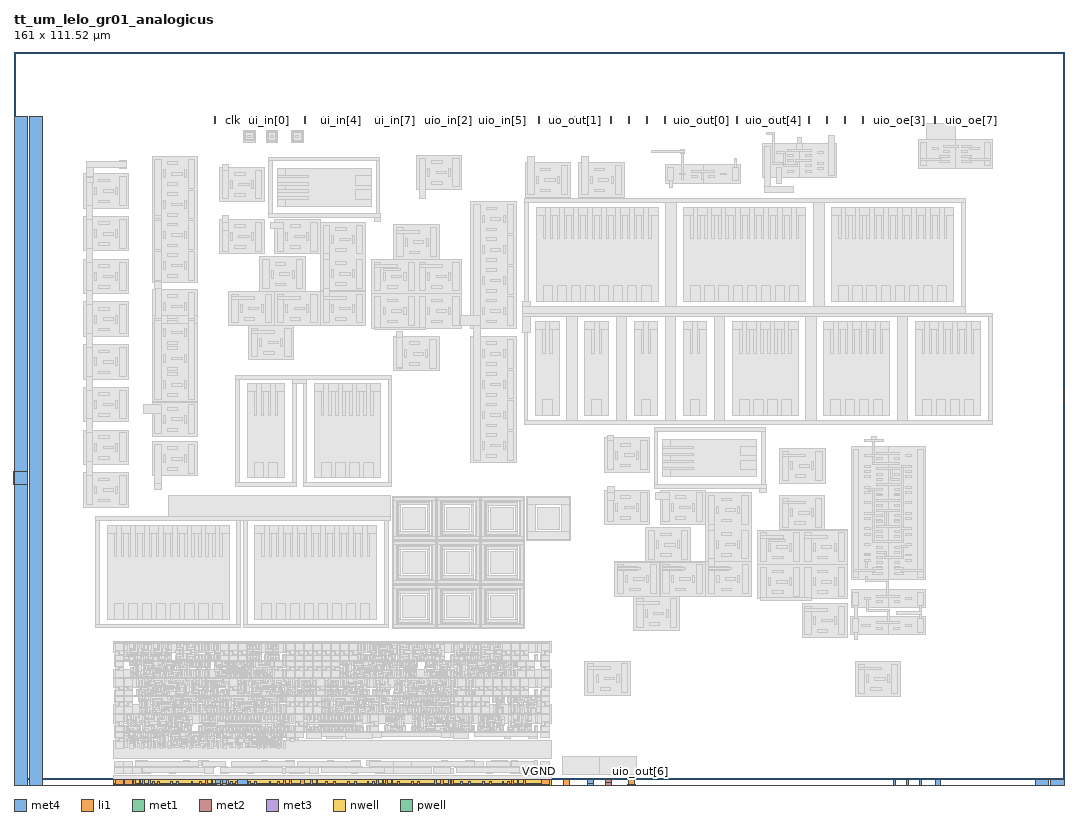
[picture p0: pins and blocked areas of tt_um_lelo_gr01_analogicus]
MACRO tt_um_lelo_gr01_analogicus
  CLASS BLOCK ;
  FOREIGN tt_um_lelo_gr01_analogicus ;
  ORIGIN 0.000 0.000 ;
  SIZE 161.000 BY 111.520 ;
  PIN clk
    DIRECTION INPUT ;
    USE SIGNAL ;
    ANTENNAGATEAREA 0.852000 ;
    PORT
      LAYER met4 ;
        RECT 33.430 100.520 33.730 101.520 ;
    END
  END clk
  PIN ena
    DIRECTION INPUT ;
    USE SIGNAL ;
    PORT
      LAYER met4 ;
        RECT 30.670 100.520 30.970 101.520 ;
    END
  END ena
  PIN rst_n
    DIRECTION INPUT ;
    USE SIGNAL ;
    ANTENNAGATEAREA 0.490500 ;
    ANTENNADIFFAREA 0.202500 ;
    PORT
      LAYER met4 ;
        RECT 36.190 100.520 36.490 101.520 ;
    END
  END rst_n
  PIN ui_in[0]
    DIRECTION INPUT ;
    USE SIGNAL ;
    ANTENNAGATEAREA 0.415500 ;
    ANTENNADIFFAREA 0.202500 ;
    PORT
      LAYER met4 ;
        RECT 38.950 100.520 39.250 101.520 ;
    END
  END ui_in[0]
  PIN ui_in[1]
    DIRECTION INPUT ;
    USE SIGNAL ;
    ANTENNAGATEAREA 0.490500 ;
    ANTENNADIFFAREA 0.202500 ;
    PORT
      LAYER met4 ;
        RECT 41.710 100.520 42.010 101.520 ;
    END
  END ui_in[1]
  PIN ui_in[2]
    DIRECTION INPUT ;
    USE SIGNAL ;
    PORT
      LAYER met4 ;
        RECT 44.470 100.520 44.770 101.520 ;
    END
  END ui_in[2]
  PIN ui_in[3]
    DIRECTION INPUT ;
    USE SIGNAL ;
    PORT
      LAYER met4 ;
        RECT 47.230 100.520 47.530 101.520 ;
    END
  END ui_in[3]
  PIN ui_in[4]
    DIRECTION INPUT ;
    USE SIGNAL ;
    PORT
      LAYER met4 ;
        RECT 49.990 100.520 50.290 101.520 ;
    END
  END ui_in[4]
  PIN ui_in[5]
    DIRECTION INPUT ;
    USE SIGNAL ;
    PORT
      LAYER met4 ;
        RECT 52.750 100.520 53.050 101.520 ;
    END
  END ui_in[5]
  PIN ui_in[6]
    DIRECTION INPUT ;
    USE SIGNAL ;
    PORT
      LAYER met4 ;
        RECT 55.510 100.520 55.810 101.520 ;
    END
  END ui_in[6]
  PIN ui_in[7]
    DIRECTION INPUT ;
    USE SIGNAL ;
    PORT
      LAYER met4 ;
        RECT 58.270 100.520 58.570 101.520 ;
    END
  END ui_in[7]
  PIN uio_in[0]
    DIRECTION INPUT ;
    USE SIGNAL ;
    PORT
      LAYER met4 ;
        RECT 61.030 100.520 61.330 101.520 ;
    END
  END uio_in[0]
  PIN uio_in[1]
    DIRECTION INPUT ;
    USE SIGNAL ;
    PORT
      LAYER met4 ;
        RECT 63.790 100.520 64.090 101.520 ;
    END
  END uio_in[1]
  PIN uio_in[2]
    DIRECTION INPUT ;
    USE SIGNAL ;
    PORT
      LAYER met4 ;
        RECT 66.550 100.520 66.850 101.520 ;
    END
  END uio_in[2]
  PIN uio_in[3]
    DIRECTION INPUT ;
    USE SIGNAL ;
    PORT
      LAYER met4 ;
        RECT 69.310 100.520 69.610 101.520 ;
    END
  END uio_in[3]
  PIN uio_in[4]
    DIRECTION INPUT ;
    USE SIGNAL ;
    PORT
      LAYER met4 ;
        RECT 72.070 100.520 72.370 101.520 ;
    END
  END uio_in[4]
  PIN uio_in[5]
    DIRECTION INPUT ;
    USE SIGNAL ;
    PORT
      LAYER met4 ;
        RECT 74.830 100.520 75.130 101.520 ;
    END
  END uio_in[5]
  PIN uio_in[6]
    DIRECTION INPUT ;
    USE SIGNAL ;
    PORT
      LAYER met4 ;
        RECT 77.590 100.520 77.890 101.520 ;
    END
  END uio_in[6]
  PIN uio_in[7]
    DIRECTION INPUT ;
    USE SIGNAL ;
    PORT
      LAYER met4 ;
        RECT 80.350 100.520 80.650 101.520 ;
    END
  END uio_in[7]
  PIN uio_oe[0]
    DIRECTION OUTPUT ;
    USE SIGNAL ;
    PORT
      LAYER met4 ;
        RECT 127.270 100.520 127.570 101.520 ;
    END
  END uio_oe[0]
  PIN uio_oe[1]
    DIRECTION OUTPUT ;
    USE SIGNAL ;
    PORT
      LAYER met4 ;
        RECT 130.030 100.520 130.330 101.520 ;
    END
  END uio_oe[1]
  PIN uio_oe[2]
    DIRECTION OUTPUT ;
    USE SIGNAL ;
    PORT
      LAYER met4 ;
        RECT 132.790 100.520 133.090 101.520 ;
    END
  END uio_oe[2]
  PIN uio_oe[3]
    DIRECTION OUTPUT ;
    USE SIGNAL ;
    PORT
      LAYER met4 ;
        RECT 135.550 100.520 135.850 101.520 ;
    END
  END uio_oe[3]
  PIN uio_oe[4]
    DIRECTION OUTPUT ;
    USE SIGNAL ;
    PORT
      LAYER met4 ;
        RECT 138.310 100.520 138.610 101.520 ;
    END
  END uio_oe[4]
  PIN uio_oe[5]
    DIRECTION OUTPUT ;
    USE SIGNAL ;
    PORT
      LAYER met4 ;
        RECT 141.070 100.520 141.370 101.520 ;
    END
  END uio_oe[5]
  PIN uio_oe[6]
    DIRECTION OUTPUT ;
    USE SIGNAL ;
    PORT
      LAYER met4 ;
        RECT 143.830 100.520 144.130 101.520 ;
    END
  END uio_oe[6]
  PIN uio_oe[7]
    DIRECTION OUTPUT ;
    USE SIGNAL ;
    PORT
      LAYER met4 ;
        RECT 146.590 100.520 146.890 101.520 ;
    END
  END uio_oe[7]
  PIN uio_out[0]
    DIRECTION OUTPUT ;
    USE SIGNAL ;
    ANTENNADIFFAREA 0.702900 ;
    PORT
      LAYER met4 ;
        RECT 105.190 100.520 105.490 101.520 ;
    END
  END uio_out[0]
  PIN uio_out[1]
    DIRECTION OUTPUT ;
    USE SIGNAL ;
    ANTENNADIFFAREA 0.702900 ;
    PORT
      LAYER met4 ;
        RECT 107.950 100.520 108.250 101.520 ;
    END
  END uio_out[1]
  PIN uio_out[2]
    DIRECTION OUTPUT ;
    USE SIGNAL ;
    ANTENNADIFFAREA 0.702900 ;
    PORT
      LAYER met4 ;
        RECT 110.710 100.520 111.010 101.520 ;
    END
  END uio_out[2]
  PIN uio_out[3]
    DIRECTION OUTPUT ;
    USE SIGNAL ;
    ANTENNADIFFAREA 0.702900 ;
    PORT
      LAYER met4 ;
        RECT 113.470 100.520 113.770 101.520 ;
    END
  END uio_out[3]
  PIN uio_out[4]
    DIRECTION OUTPUT ;
    USE SIGNAL ;
    ANTENNADIFFAREA 0.702900 ;
    PORT
      LAYER met4 ;
        RECT 116.230 100.520 116.530 101.520 ;
    END
  END uio_out[4]
  PIN uio_out[5]
    DIRECTION OUTPUT ;
    USE SIGNAL ;
    ANTENNADIFFAREA 0.702900 ;
    PORT
      LAYER li1 ;
        RECT 58.315 -2.050 58.875 -1.150 ;
        RECT 58.315 -2.975 58.680 -2.050 ;
        RECT 58.315 -3.360 58.895 -2.975 ;
      LAYER met1 ;
        RECT 54.160 -3.035 54.480 -2.975 ;
        RECT 58.315 -3.035 58.605 -2.990 ;
        RECT 54.160 -3.175 58.605 -3.035 ;
        RECT 54.160 -3.235 54.480 -3.175 ;
        RECT 58.315 -3.220 58.605 -3.175 ;
      LAYER met2 ;
        RECT 54.190 -3.265 54.450 -2.945 ;
        RECT 54.250 -4.030 54.390 -3.265 ;
        RECT 54.135 -4.310 54.505 -4.030 ;
      LAYER met3 ;
        RECT 53.900 -4.455 54.520 -4.005 ;
      LAYER met4 ;
        RECT 118.990 100.520 119.290 101.520 ;
        RECT 54.160 -4.020 54.490 -4.000 ;
        RECT 134.850 -4.020 135.150 0.000 ;
        RECT 54.160 -4.320 135.150 -4.020 ;
        RECT 54.160 -4.340 54.490 -4.320 ;
    END
  END uio_out[5]
  PIN uio_out[6]
    DIRECTION OUTPUT ;
    USE SIGNAL ;
    ANTENNADIFFAREA 0.702900 ;
    PORT
      LAYER li1 ;
        RECT 64.945 -2.050 65.505 -1.150 ;
        RECT 65.140 -2.975 65.505 -2.050 ;
        RECT 64.925 -3.360 65.505 -2.975 ;
      LAYER met1 ;
        RECT 55.080 -1.335 55.400 -1.275 ;
        RECT 65.215 -1.335 65.505 -1.290 ;
        RECT 55.080 -1.475 65.505 -1.335 ;
        RECT 55.080 -1.535 55.400 -1.475 ;
        RECT 65.215 -1.520 65.505 -1.475 ;
        RECT 55.075 -4.280 137.120 -4.000 ;
        RECT 55.075 -4.310 55.400 -4.280 ;
      LAYER met2 ;
        RECT 55.110 -1.565 55.370 -1.245 ;
        RECT 55.170 -4.000 55.310 -1.565 ;
        RECT 55.075 -4.280 55.415 -4.000 ;
        RECT 136.810 -4.325 137.090 -3.955 ;
      LAYER met3 ;
        RECT 136.700 -4.400 137.200 -3.900 ;
      LAYER met4 ;
        RECT 121.750 100.520 122.050 101.520 ;
        RECT 136.800 -3.900 137.100 0.000 ;
        RECT 136.700 -4.400 137.200 -3.900 ;
    END
  END uio_out[6]
  PIN uio_out[7]
    DIRECTION OUTPUT ;
    USE SIGNAL ;
    ANTENNADIFFAREA 0.702900 ;
    PORT
      LAYER li1 ;
        RECT 44.705 -2.050 45.265 -1.150 ;
        RECT 44.900 -2.975 45.265 -2.050 ;
        RECT 44.685 -3.360 45.265 -2.975 ;
      LAYER met1 ;
        RECT 39.440 -3.035 39.760 -2.975 ;
        RECT 44.975 -3.035 45.265 -2.990 ;
        RECT 39.440 -3.175 45.265 -3.035 ;
        RECT 39.440 -3.235 39.760 -3.175 ;
        RECT 44.975 -3.220 45.265 -3.175 ;
      LAYER met2 ;
        RECT 39.470 -3.265 39.730 -2.945 ;
        RECT 39.530 -3.920 39.670 -3.265 ;
        RECT 39.475 -4.550 39.755 -3.920 ;
        RECT 39.350 -5.150 39.900 -4.550 ;
      LAYER met3 ;
        RECT 39.350 -5.150 39.900 -4.550 ;
      LAYER met4 ;
        RECT 124.510 100.520 124.810 101.520 ;
        RECT 39.350 -4.705 39.900 -4.550 ;
        RECT 138.800 -4.650 139.100 0.000 ;
        RECT 137.750 -4.705 139.150 -4.650 ;
        RECT 39.350 -5.000 139.150 -4.705 ;
        RECT 39.350 -5.005 138.150 -5.000 ;
        RECT 39.350 -5.150 39.900 -5.005 ;
    END
  END uio_out[7]
  PIN uo_out[0]
    DIRECTION OUTPUT ;
    USE SIGNAL ;
    ANTENNAGATEAREA 0.789000 ;
    ANTENNADIFFAREA 1.872000 ;
    PORT
      LAYER li1 ;
        RECT 27.845 -2.540 28.245 -2.295 ;
      LAYER met1 ;
        RECT 27.955 -2.355 28.245 -2.310 ;
        RECT 27.955 -2.495 30.010 -2.355 ;
        RECT 27.955 -2.540 28.245 -2.495 ;
        RECT 29.870 -3.035 30.010 -2.495 ;
        RECT 33.460 -3.035 33.780 -2.975 ;
        RECT 29.870 -3.175 33.780 -3.035 ;
        RECT 33.460 -3.235 33.780 -3.175 ;
        RECT 33.500 -5.210 33.780 -5.180 ;
        RECT 141.350 -5.210 142.050 -3.550 ;
        RECT 33.500 -5.490 142.050 -5.210 ;
        RECT 33.500 -5.520 33.780 -5.490 ;
        RECT 141.350 -5.500 142.050 -5.490 ;
      LAYER met2 ;
        RECT 33.490 -3.265 33.750 -2.945 ;
        RECT 33.550 -3.900 33.690 -3.265 ;
        RECT 141.350 -3.650 142.050 -3.605 ;
        RECT 33.500 -5.210 33.780 -3.900 ;
        RECT 141.320 -4.350 142.080 -3.650 ;
        RECT 33.470 -5.490 33.810 -5.210 ;
      LAYER met3 ;
        RECT 141.325 -4.345 142.075 -3.595 ;
      LAYER met4 ;
        RECT 83.110 100.520 83.410 101.520 ;
        RECT 141.350 -3.620 142.050 0.000 ;
        RECT 141.320 -4.320 142.080 -3.620 ;
        RECT 141.350 -4.800 142.050 -4.320 ;
    END
  END uo_out[0]
  PIN uo_out[1]
    DIRECTION OUTPUT ;
    USE SIGNAL ;
    ANTENNADIFFAREA 0.702900 ;
    PORT
      LAYER met4 ;
        RECT 85.870 100.520 86.170 101.520 ;
    END
  END uo_out[1]
  PIN uo_out[2]
    DIRECTION OUTPUT ;
    USE SIGNAL ;
    PORT
      LAYER met4 ;
        RECT 88.630 100.520 88.930 101.520 ;
    END
  END uo_out[2]
  PIN uo_out[3]
    DIRECTION OUTPUT ;
    USE SIGNAL ;
    PORT
      LAYER met4 ;
        RECT 91.390 100.520 91.690 101.520 ;
    END
  END uo_out[3]
  PIN uo_out[4]
    DIRECTION OUTPUT ;
    USE SIGNAL ;
    PORT
      LAYER met4 ;
        RECT 94.150 100.520 94.450 101.520 ;
    END
  END uo_out[4]
  PIN uo_out[5]
    DIRECTION OUTPUT ;
    USE SIGNAL ;
    PORT
      LAYER met4 ;
        RECT 96.910 100.520 97.210 101.520 ;
    END
  END uo_out[5]
  PIN uo_out[6]
    DIRECTION OUTPUT ;
    USE SIGNAL ;
    PORT
      LAYER met4 ;
        RECT 99.670 100.520 99.970 101.520 ;
    END
  END uo_out[6]
  PIN uo_out[7]
    DIRECTION OUTPUT ;
    USE SIGNAL ;
    PORT
      LAYER met4 ;
        RECT 102.430 100.520 102.730 101.520 ;
    END
  END uo_out[7]
  PIN VDPWR
    DIRECTION INOUT ;
    USE POWER ;
    PORT
      LAYER nwell ;
        RECT 15.260 -2.310 82.340 0.000 ;
      LAYER li1 ;
        RECT 15.535 -0.810 16.745 0.000 ;
        RECT 16.915 -0.810 18.125 0.000 ;
        RECT 18.355 -0.810 18.565 0.000 ;
        RECT 19.235 -0.810 19.465 0.000 ;
        RECT 19.725 -0.810 19.975 0.000 ;
        RECT 20.565 -0.810 20.870 0.000 ;
        RECT 21.210 -0.810 21.540 -0.430 ;
        RECT 22.060 -0.810 22.310 -0.350 ;
        RECT 23.925 -0.810 24.295 -0.350 ;
        RECT 24.930 -0.810 25.260 -0.380 ;
        RECT 27.150 -0.810 27.400 -0.350 ;
        RECT 28.405 -0.810 28.735 -0.310 ;
        RECT 29.395 -0.810 29.605 0.000 ;
        RECT 30.275 -0.810 30.505 0.000 ;
        RECT 31.685 -0.810 31.935 0.000 ;
        RECT 32.525 -0.810 32.830 0.000 ;
        RECT 33.170 -0.810 33.500 -0.430 ;
        RECT 34.020 -0.810 34.270 -0.350 ;
        RECT 35.885 -0.810 36.255 -0.350 ;
        RECT 36.890 -0.810 37.220 -0.380 ;
        RECT 39.110 -0.810 39.360 -0.350 ;
        RECT 40.365 -0.810 40.695 -0.310 ;
        RECT 41.295 -0.810 41.585 0.000 ;
        RECT 42.270 -0.810 42.595 -0.005 ;
        RECT 43.905 -0.810 44.515 -0.010 ;
        RECT 45.475 -0.810 45.705 0.000 ;
        RECT 46.375 -0.810 46.585 0.000 ;
        RECT 47.705 -0.810 48.035 -0.310 ;
        RECT 49.040 -0.810 49.290 -0.350 ;
        RECT 51.180 -0.810 51.510 -0.380 ;
        RECT 52.145 -0.810 52.515 -0.350 ;
        RECT 54.130 -0.810 54.380 -0.350 ;
        RECT 54.900 -0.810 55.230 -0.430 ;
        RECT 55.570 -0.810 55.875 0.000 ;
        RECT 56.465 -0.810 56.715 0.000 ;
        RECT 56.995 -0.810 57.205 0.000 ;
        RECT 57.875 -0.810 58.105 0.000 ;
        RECT 58.800 -0.810 59.050 -0.310 ;
        RECT 61.000 -0.810 61.250 -0.310 ;
        RECT 61.840 -0.810 62.145 -0.310 ;
        RECT 64.495 -0.810 64.775 -0.140 ;
        RECT 65.455 -0.810 65.785 -0.090 ;
        RECT 66.595 -0.810 66.885 0.000 ;
        RECT 67.055 -0.810 67.345 0.000 ;
        RECT 68.405 -0.810 68.735 -0.310 ;
        RECT 69.740 -0.810 69.990 -0.350 ;
        RECT 71.880 -0.810 72.210 -0.380 ;
        RECT 72.845 -0.810 73.215 -0.350 ;
        RECT 74.830 -0.810 75.080 -0.350 ;
        RECT 75.600 -0.810 75.930 -0.430 ;
        RECT 76.270 -0.810 76.575 0.000 ;
        RECT 77.165 -0.810 77.415 0.000 ;
        RECT 78.085 -0.810 78.415 -0.010 ;
        RECT 80.855 -0.810 82.065 0.000 ;
        RECT 15.450 -0.980 82.150 -0.810 ;
        RECT 94.200 -0.900 95.150 0.000 ;
        RECT 15.535 -2.070 16.745 -0.980 ;
        RECT 17.665 -1.780 18.275 -0.980 ;
        RECT 19.585 -1.785 19.910 -0.980 ;
        RECT 21.625 -1.440 21.895 -0.980 ;
        RECT 23.685 -1.440 24.010 -0.980 ;
        RECT 25.485 -1.780 26.095 -0.980 ;
        RECT 27.405 -1.785 27.730 -0.980 ;
        RECT 16.225 -2.610 16.745 -2.070 ;
        RECT 28.415 -2.145 28.705 -0.980 ;
        RECT 29.325 -1.490 29.655 -0.980 ;
        RECT 30.725 -1.395 31.055 -0.980 ;
        RECT 31.625 -1.950 31.915 -0.980 ;
        RECT 32.665 -1.440 32.935 -0.980 ;
        RECT 34.725 -1.440 35.050 -0.980 ;
        RECT 36.285 -2.120 36.455 -0.980 ;
        RECT 38.825 -1.740 38.995 -0.980 ;
        RECT 39.915 -2.070 41.125 -0.980 ;
        RECT 40.605 -2.610 41.125 -2.070 ;
        RECT 41.295 -2.145 41.585 -0.980 ;
        RECT 42.270 -1.785 42.595 -0.980 ;
        RECT 43.905 -1.780 44.515 -0.980 ;
        RECT 45.435 -1.935 45.705 -0.980 ;
        RECT 46.375 -1.450 47.060 -0.980 ;
        RECT 47.725 -1.430 48.055 -0.980 ;
        RECT 48.655 -2.070 49.865 -0.980 ;
        RECT 49.345 -2.610 49.865 -2.070 ;
        RECT 50.545 -2.120 50.715 -0.980 ;
        RECT 53.085 -1.740 53.255 -0.980 ;
        RECT 54.175 -2.145 54.465 -0.980 ;
        RECT 55.190 -1.440 55.515 -0.980 ;
        RECT 57.305 -1.440 57.575 -0.980 ;
        RECT 59.065 -1.780 59.675 -0.980 ;
        RECT 60.985 -1.785 61.310 -0.980 ;
        RECT 62.510 -1.785 62.835 -0.980 ;
        RECT 64.145 -1.780 64.755 -0.980 ;
        RECT 65.675 -2.070 66.885 -0.980 ;
        RECT 66.365 -2.610 66.885 -2.070 ;
        RECT 67.055 -2.145 67.345 -0.980 ;
        RECT 68.945 -2.120 69.115 -0.980 ;
        RECT 71.485 -1.740 71.655 -0.980 ;
        RECT 72.615 -2.120 72.845 -0.980 ;
        RECT 73.515 -2.120 73.725 -0.980 ;
        RECT 74.510 -1.440 74.835 -0.980 ;
        RECT 76.625 -1.440 76.895 -0.980 ;
        RECT 78.085 -1.780 78.415 -0.980 ;
        RECT 79.935 -2.145 80.225 -0.980 ;
        RECT 80.855 -2.070 82.065 -0.980 ;
        RECT 80.855 -2.610 81.375 -2.070 ;
        RECT 94.100 -2.100 95.250 -0.900 ;
      LAYER met1 ;
        RECT 15.450 -1.135 82.150 -0.655 ;
        RECT 94.100 -2.100 95.250 -0.900 ;
      LAYER met2 ;
        RECT 90.630 -0.475 91.570 0.000 ;
        RECT 31.000 -1.080 32.540 -0.710 ;
        RECT 90.650 -9.695 91.550 -0.475 ;
        RECT 94.100 -2.100 95.250 -0.900 ;
        RECT 94.150 -9.920 95.200 -2.100 ;
      LAYER met3 ;
        RECT 161.000 57.670 161.030 59.670 ;
        RECT -0.030 45.180 0.000 47.180 ;
        RECT 90.650 -0.500 91.550 0.000 ;
        RECT 30.980 -1.060 32.560 -0.730 ;
        RECT 0.000 -10.000 161.000 -8.000 ;
      LAYER met4 ;
        RECT 0.000 47.185 2.000 101.520 ;
        RECT 161.000 57.665 161.005 59.675 ;
        RECT -0.005 45.175 2.000 47.185 ;
        RECT 0.000 -10.000 2.000 45.175 ;
        RECT 30.970 -9.895 32.570 0.000 ;
        RECT 159.000 -10.000 161.000 0.000 ;
    END
  END VDPWR
  PIN VGND
    DIRECTION INOUT ;
    USE GROUND ;
    PORT
      LAYER pwell ;
        RECT 28.345 -3.425 28.775 -2.640 ;
        RECT 41.225 -3.425 41.655 -2.640 ;
        RECT 54.105 -3.425 54.535 -2.640 ;
        RECT 66.985 -3.425 67.415 -2.640 ;
        RECT 79.865 -3.425 80.295 -2.640 ;
      LAYER li1 ;
        RECT 84.300 -1.950 85.250 0.000 ;
        RECT 15.535 -2.780 16.055 -2.240 ;
        RECT 39.915 -2.780 40.435 -2.240 ;
        RECT 48.655 -2.780 49.175 -2.240 ;
        RECT 65.675 -2.780 66.195 -2.240 ;
        RECT 15.535 -3.530 16.745 -2.780 ;
        RECT 17.665 -3.530 18.270 -3.050 ;
        RECT 19.600 -3.530 19.930 -3.050 ;
        RECT 21.625 -3.530 21.895 -3.070 ;
        RECT 23.685 -3.530 24.010 -3.070 ;
        RECT 25.485 -3.530 26.090 -3.050 ;
        RECT 27.420 -3.530 27.750 -3.050 ;
        RECT 28.415 -3.530 28.705 -2.805 ;
        RECT 28.875 -3.530 29.205 -3.050 ;
        RECT 30.555 -3.530 30.885 -3.170 ;
        RECT 31.415 -3.530 31.745 -3.150 ;
        RECT 32.665 -3.530 32.935 -3.070 ;
        RECT 34.725 -3.530 35.050 -3.070 ;
        RECT 36.205 -3.530 36.535 -3.130 ;
        RECT 38.495 -3.530 39.005 -2.995 ;
        RECT 39.915 -3.530 41.125 -2.780 ;
        RECT 41.295 -3.530 41.585 -2.805 ;
        RECT 42.250 -3.530 42.580 -3.050 ;
        RECT 43.910 -3.530 44.515 -3.050 ;
        RECT 45.435 -3.530 45.705 -2.895 ;
        RECT 46.295 -3.530 46.695 -3.035 ;
        RECT 48.145 -3.530 48.475 -3.025 ;
        RECT 48.655 -3.530 49.865 -2.780 ;
        RECT 50.465 -3.530 50.795 -3.130 ;
        RECT 52.755 -3.530 53.265 -2.995 ;
        RECT 54.175 -3.530 54.465 -2.805 ;
        RECT 55.190 -3.530 55.515 -3.070 ;
        RECT 57.305 -3.530 57.575 -3.070 ;
        RECT 59.065 -3.530 59.670 -3.050 ;
        RECT 61.000 -3.530 61.330 -3.050 ;
        RECT 62.490 -3.530 62.820 -3.050 ;
        RECT 64.150 -3.530 64.755 -3.050 ;
        RECT 65.675 -3.530 66.885 -2.780 ;
        RECT 67.055 -3.530 67.345 -2.805 ;
        RECT 68.865 -3.530 69.195 -3.130 ;
        RECT 71.155 -3.530 71.665 -2.995 ;
        RECT 72.615 -3.530 72.845 -2.710 ;
        RECT 73.515 -3.530 73.725 -2.710 ;
        RECT 74.510 -3.530 74.835 -3.070 ;
        RECT 76.625 -3.530 76.895 -3.070 ;
        RECT 77.640 -3.530 77.915 -2.710 ;
        RECT 81.545 -2.780 82.065 -2.240 ;
        RECT 78.585 -3.530 78.755 -3.060 ;
        RECT 79.425 -3.530 79.715 -3.060 ;
        RECT 79.935 -3.530 80.225 -2.805 ;
        RECT 80.855 -3.530 82.065 -2.780 ;
        RECT 15.450 -3.700 82.150 -3.530 ;
      LAYER met1 ;
        RECT 84.200 -2.050 85.400 -0.950 ;
        RECT 15.450 -3.855 82.150 -3.375 ;
      LAYER met2 ;
        RECT 84.200 -2.050 85.400 -0.950 ;
        RECT 34.300 -3.800 35.840 -3.430 ;
      LAYER met3 ;
        RECT 84.200 -2.050 85.400 -0.950 ;
        RECT 87.900 -1.750 88.900 -0.750 ;
        RECT 34.280 -3.780 35.860 -3.450 ;
        RECT 84.300 -5.600 85.250 -2.050 ;
        RECT 87.950 -5.600 88.850 -1.750 ;
        RECT 2.400 -7.600 158.600 -5.600 ;
      LAYER met4 ;
        RECT 2.400 -10.000 4.400 101.520 ;
        RECT 34.270 -7.350 35.870 0.000 ;
        RECT 87.950 -0.750 88.850 0.000 ;
        RECT 87.900 -1.750 88.900 -0.750 ;
        RECT 156.600 -10.000 158.600 0.000 ;
    END
  END VGND
  OBS
      LAYER pwell ;
        RECT 35.200 97.650 37.030 99.480 ;
        RECT 38.650 97.620 40.480 99.450 ;
        RECT 42.530 97.580 44.360 99.410 ;
        RECT 139.985 98.030 144.380 100.460 ;
      LAYER nwell ;
        RECT 10.670 87.520 17.630 92.800 ;
        RECT 10.670 80.970 17.630 86.250 ;
        RECT 10.670 74.420 17.630 79.700 ;
      LAYER pwell ;
        RECT 21.170 76.070 28.130 95.450 ;
      LAYER nwell ;
        RECT 31.460 88.520 38.420 93.800 ;
      LAYER pwell ;
        RECT 40.360 87.840 54.760 93.600 ;
      LAYER nwell ;
        RECT 61.720 90.370 68.680 95.650 ;
        RECT 78.370 89.220 85.330 94.500 ;
        RECT 86.620 89.220 93.580 94.500 ;
      LAYER pwell ;
        RECT 99.960 91.370 105.660 94.170 ;
      LAYER nwell ;
        RECT 105.660 91.370 111.360 94.170 ;
      LAYER pwell ;
        RECT 114.750 92.200 120.450 97.400 ;
      LAYER nwell ;
        RECT 120.450 92.200 126.150 97.400 ;
      LAYER pwell ;
        RECT 138.680 93.635 144.380 98.030 ;
      LAYER nwell ;
        RECT 144.380 93.635 150.080 98.030 ;
        RECT 31.460 80.520 38.420 85.800 ;
        RECT 39.960 80.520 46.920 85.800 ;
        RECT 10.670 67.870 17.630 73.150 ;
      LAYER pwell ;
        RECT 21.180 71.100 28.140 75.100 ;
        RECT 37.710 74.800 44.670 80.050 ;
        RECT 46.950 74.840 53.910 85.380 ;
      LAYER nwell ;
        RECT 58.260 79.690 65.220 84.960 ;
        RECT 58.260 79.680 68.680 79.690 ;
      LAYER pwell ;
        RECT 21.170 69.820 28.140 71.100 ;
        RECT 32.960 74.770 46.920 74.800 ;
      LAYER nwell ;
        RECT 10.670 61.320 17.630 66.600 ;
        RECT 10.670 54.770 17.630 60.050 ;
      LAYER pwell ;
        RECT 21.170 57.820 28.130 69.820 ;
        RECT 32.960 69.550 39.920 74.770 ;
        RECT 39.960 69.550 46.920 74.770 ;
        RECT 32.960 69.520 46.920 69.550 ;
        RECT 46.970 69.520 53.930 74.800 ;
      LAYER nwell ;
        RECT 54.870 74.410 68.680 79.680 ;
        RECT 54.870 74.400 61.830 74.410 ;
      LAYER pwell ;
        RECT 35.960 64.270 42.920 69.520 ;
        RECT 54.870 69.110 68.680 74.390 ;
      LAYER nwell ;
        RECT 70.070 69.120 77.030 88.500 ;
      LAYER pwell ;
        RECT 80.040 73.220 98.760 87.620 ;
        RECT 102.690 73.220 121.410 87.620 ;
        RECT 125.390 73.220 144.110 87.620 ;
      LAYER nwell ;
        RECT 58.220 62.570 65.180 67.850 ;
        RECT 10.670 48.220 17.630 53.500 ;
        RECT 21.170 52.520 28.130 57.800 ;
        RECT 10.670 41.670 17.630 46.950 ;
      LAYER pwell ;
        RECT 21.170 46.470 28.130 51.750 ;
        RECT 35.740 46.170 41.500 60.570 ;
        RECT 46.090 46.170 56.170 60.570 ;
      LAYER nwell ;
        RECT 70.070 48.470 77.030 67.850 ;
      LAYER pwell ;
        RECT 79.990 55.720 83.590 70.120 ;
        RECT 87.540 55.720 91.140 70.120 ;
        RECT 95.090 55.720 98.690 70.120 ;
        RECT 102.640 55.720 106.240 70.120 ;
        RECT 110.190 55.720 120.270 70.120 ;
        RECT 124.190 55.720 134.270 70.120 ;
        RECT 138.190 55.720 148.270 70.120 ;
      LAYER nwell ;
        RECT 90.560 47.015 97.520 52.295 ;
      LAYER pwell ;
        RECT 99.460 46.335 113.860 52.095 ;
      LAYER nwell ;
        RECT 117.400 45.385 124.360 50.665 ;
      LAYER pwell ;
        RECT 58.020 42.555 64.720 43.320 ;
        RECT 14.290 24.520 33.010 38.920 ;
        RECT 36.940 24.520 55.660 38.920 ;
        RECT 58.020 37.385 58.785 42.555 ;
        RECT 63.955 37.385 64.720 42.555 ;
        RECT 58.020 36.620 64.720 37.385 ;
        RECT 64.770 42.555 71.470 43.320 ;
        RECT 64.770 37.385 65.535 42.555 ;
        RECT 70.705 37.385 71.470 42.555 ;
        RECT 64.770 36.620 71.470 37.385 ;
        RECT 71.520 42.545 78.220 43.310 ;
        RECT 71.520 37.375 72.285 42.545 ;
        RECT 77.455 37.375 78.220 42.545 ;
        RECT 71.520 36.610 78.220 37.375 ;
        RECT 78.610 42.555 85.310 43.320 ;
        RECT 78.610 37.385 79.375 42.555 ;
        RECT 84.545 37.385 85.310 42.555 ;
      LAYER nwell ;
        RECT 90.560 39.015 97.520 44.295 ;
        RECT 99.060 39.015 106.020 44.295 ;
      LAYER pwell ;
        RECT 78.610 36.620 85.310 37.385 ;
        RECT 58.020 35.805 64.720 36.570 ;
        RECT 58.020 30.635 58.785 35.805 ;
        RECT 63.955 30.635 64.720 35.805 ;
        RECT 58.020 29.870 64.720 30.635 ;
        RECT 64.770 35.805 71.470 36.570 ;
        RECT 64.770 30.635 65.535 35.805 ;
        RECT 70.705 30.635 71.470 35.805 ;
        RECT 64.770 29.870 71.470 30.635 ;
        RECT 71.520 35.805 78.220 36.570 ;
        RECT 71.520 30.635 72.285 35.805 ;
        RECT 77.455 30.635 78.220 35.805 ;
        RECT 96.810 33.295 103.770 38.545 ;
        RECT 106.050 33.335 113.010 43.875 ;
      LAYER nwell ;
        RECT 117.360 38.185 124.320 43.455 ;
        RECT 117.360 38.175 127.780 38.185 ;
      LAYER pwell ;
        RECT 71.520 29.870 78.220 30.635 ;
        RECT 92.060 33.265 106.020 33.295 ;
        RECT 58.020 29.055 64.720 29.820 ;
        RECT 58.020 23.885 58.785 29.055 ;
        RECT 63.955 23.885 64.720 29.055 ;
        RECT 58.020 23.120 64.720 23.885 ;
        RECT 64.770 29.055 71.470 29.820 ;
        RECT 64.770 23.885 65.535 29.055 ;
        RECT 70.705 23.885 71.470 29.055 ;
        RECT 64.770 23.120 71.470 23.885 ;
        RECT 71.520 29.055 78.220 29.820 ;
        RECT 71.520 23.885 72.285 29.055 ;
        RECT 77.455 23.885 78.220 29.055 ;
        RECT 92.060 28.045 99.020 33.265 ;
        RECT 99.060 28.045 106.020 33.265 ;
        RECT 92.060 28.015 106.020 28.045 ;
        RECT 106.070 28.015 113.030 33.295 ;
      LAYER nwell ;
        RECT 113.970 32.905 127.780 38.175 ;
        RECT 113.970 32.895 120.930 32.905 ;
      LAYER pwell ;
        RECT 71.520 23.120 78.220 23.885 ;
        RECT 95.060 22.765 102.020 28.015 ;
        RECT 113.970 27.605 127.780 32.885 ;
        RECT 128.350 30.545 134.050 50.945 ;
      LAYER nwell ;
        RECT 134.050 30.545 139.750 50.945 ;
      LAYER pwell ;
        RECT 120.830 21.645 127.790 26.925 ;
        RECT 128.340 26.235 134.040 29.035 ;
      LAYER nwell ;
        RECT 134.040 26.235 139.740 29.035 ;
      LAYER pwell ;
        RECT 128.330 22.135 134.030 24.935 ;
      LAYER nwell ;
        RECT 134.030 22.135 139.730 24.935 ;
        RECT 15.260 19.450 82.340 21.055 ;
      LAYER pwell ;
        RECT 15.455 18.250 16.825 19.060 ;
        RECT 17.590 18.930 19.980 19.160 ;
        RECT 21.270 18.930 23.660 19.160 ;
        RECT 27.310 18.930 28.230 19.160 ;
        RECT 16.835 18.250 20.505 18.930 ;
        RECT 20.515 18.250 24.185 18.930 ;
        RECT 24.765 18.250 28.230 18.930 ;
        RECT 28.345 18.335 28.775 19.120 ;
        RECT 28.805 18.250 30.155 19.160 ;
        RECT 30.185 18.250 31.535 19.160 ;
        RECT 31.555 18.250 32.925 19.060 ;
        RECT 32.935 18.250 34.305 19.060 ;
        RECT 34.315 18.250 35.685 19.060 ;
        RECT 35.775 18.250 37.985 19.160 ;
        RECT 38.455 18.250 40.665 19.160 ;
        RECT 41.225 18.335 41.655 19.120 ;
        RECT 41.675 18.250 43.045 19.060 ;
        RECT 43.055 18.250 44.425 19.060 ;
        RECT 44.435 18.250 45.805 19.060 ;
        RECT 45.815 18.250 47.185 19.060 ;
        RECT 47.195 18.250 48.565 19.060 ;
        RECT 48.575 18.250 49.945 19.060 ;
        RECT 49.955 18.250 51.325 19.060 ;
        RECT 51.335 18.250 52.705 19.060 ;
        RECT 52.725 18.250 54.075 19.160 ;
        RECT 54.105 18.335 54.535 19.120 ;
        RECT 54.555 18.930 55.485 19.160 ;
        RECT 58.790 18.930 59.710 19.160 ;
        RECT 62.900 18.930 65.290 19.160 ;
        RECT 54.555 18.250 58.455 18.930 ;
        RECT 58.790 18.250 62.255 18.930 ;
        RECT 62.375 18.250 66.045 18.930 ;
        RECT 66.985 18.335 67.415 19.120 ;
        RECT 68.190 18.930 70.580 19.160 ;
        RECT 71.210 18.930 72.130 19.160 ;
        RECT 67.435 18.250 71.105 18.930 ;
        RECT 71.210 18.250 74.675 18.930 ;
        RECT 74.795 18.250 76.165 19.060 ;
        RECT 76.175 18.250 77.545 19.060 ;
        RECT 77.555 18.250 78.925 19.060 ;
        RECT 79.865 18.335 80.295 19.120 ;
        RECT 80.775 18.250 82.145 19.060 ;
        RECT 15.595 18.040 15.765 18.250 ;
        RECT 16.985 18.085 17.145 18.195 ;
        RECT 17.895 18.040 18.065 18.230 ;
        RECT 20.190 18.060 20.360 18.250 ;
        RECT 23.870 18.060 24.040 18.250 ;
        RECT 24.330 18.090 24.450 18.200 ;
        RECT 24.795 18.060 24.965 18.250 ;
        RECT 28.475 18.040 28.645 18.230 ;
        RECT 29.855 18.040 30.025 18.250 ;
        RECT 30.310 18.090 30.430 18.200 ;
        RECT 31.235 18.060 31.405 18.250 ;
        RECT 31.695 18.060 31.865 18.250 ;
        RECT 33.075 18.060 33.245 18.250 ;
        RECT 34.455 18.060 34.625 18.250 ;
        RECT 36.295 18.040 36.465 18.230 ;
        RECT 36.755 18.040 36.925 18.230 ;
        RECT 37.670 18.060 37.840 18.250 ;
        RECT 38.130 18.090 38.250 18.200 ;
        RECT 38.600 18.060 38.770 18.250 ;
        RECT 39.975 18.040 40.145 18.230 ;
        RECT 40.890 18.090 41.010 18.200 ;
        RECT 41.815 18.040 41.985 18.250 ;
        RECT 43.195 18.040 43.365 18.250 ;
        RECT 44.575 18.040 44.745 18.250 ;
        RECT 45.955 18.040 46.125 18.250 ;
        RECT 47.335 18.040 47.505 18.250 ;
        RECT 48.715 18.040 48.885 18.250 ;
        RECT 50.095 18.040 50.265 18.250 ;
        RECT 51.475 18.060 51.645 18.250 ;
        RECT 52.855 18.060 53.025 18.250 ;
        RECT 54.970 18.060 55.140 18.250 ;
        RECT 59.760 18.040 59.930 18.230 ;
        RECT 62.055 18.060 62.225 18.250 ;
        RECT 62.520 18.060 62.690 18.250 ;
        RECT 66.205 18.095 66.365 18.205 ;
        RECT 66.380 18.040 66.550 18.230 ;
        RECT 67.575 18.040 67.745 18.230 ;
        RECT 70.790 18.060 70.960 18.250 ;
        RECT 74.475 18.060 74.645 18.250 ;
        RECT 74.935 18.060 75.105 18.250 ;
        RECT 76.315 18.060 76.485 18.250 ;
        RECT 77.235 18.040 77.405 18.230 ;
        RECT 77.695 18.060 77.865 18.250 ;
        RECT 78.615 18.040 78.785 18.230 ;
        RECT 79.085 18.095 79.245 18.205 ;
        RECT 80.005 18.085 80.165 18.195 ;
        RECT 80.450 18.090 80.570 18.200 ;
        RECT 81.835 18.040 82.005 18.250 ;
        RECT 15.455 17.230 16.825 18.040 ;
        RECT 17.755 17.360 27.365 18.040 ;
        RECT 22.265 17.140 23.195 17.360 ;
        RECT 26.025 17.130 27.365 17.360 ;
        RECT 27.425 17.130 28.775 18.040 ;
        RECT 28.805 17.130 30.155 18.040 ;
        RECT 30.785 17.130 36.605 18.040 ;
        RECT 36.615 17.130 39.825 18.040 ;
        RECT 39.835 17.230 41.205 18.040 ;
        RECT 41.225 17.170 41.655 17.955 ;
        RECT 41.675 17.230 43.045 18.040 ;
        RECT 43.055 17.230 44.425 18.040 ;
        RECT 44.435 17.230 45.805 18.040 ;
        RECT 45.815 17.230 47.185 18.040 ;
        RECT 47.195 17.230 48.565 18.040 ;
        RECT 48.575 17.230 49.945 18.040 ;
        RECT 49.955 17.360 59.565 18.040 ;
        RECT 54.465 17.140 55.395 17.360 ;
        RECT 58.225 17.130 59.565 17.360 ;
        RECT 59.615 17.130 61.825 18.040 ;
        RECT 63.065 17.360 66.965 18.040 ;
        RECT 66.035 17.130 66.965 17.360 ;
        RECT 66.985 17.170 67.415 17.955 ;
        RECT 67.435 17.360 77.045 18.040 ;
        RECT 71.945 17.140 72.875 17.360 ;
        RECT 75.705 17.130 77.045 17.360 ;
        RECT 77.095 17.230 78.465 18.040 ;
        RECT 78.475 17.230 79.845 18.040 ;
        RECT 80.775 17.230 82.145 18.040 ;
      LAYER nwell ;
        RECT 15.260 14.010 82.340 16.840 ;
      LAYER pwell ;
        RECT 15.455 12.810 16.825 13.620 ;
        RECT 16.835 12.810 18.205 13.620 ;
        RECT 18.715 13.490 20.055 13.720 ;
        RECT 22.885 13.490 23.815 13.710 ;
        RECT 18.715 12.810 28.325 13.490 ;
        RECT 28.345 12.895 28.775 13.680 ;
        RECT 28.795 13.490 29.725 13.720 ;
        RECT 28.795 12.810 32.695 13.490 ;
        RECT 32.935 12.810 34.305 13.620 ;
        RECT 38.825 13.490 39.755 13.710 ;
        RECT 42.585 13.490 43.925 13.720 ;
        RECT 34.315 12.810 43.925 13.490 ;
        RECT 44.055 12.810 46.265 13.720 ;
        RECT 46.275 12.810 47.645 13.620 ;
        RECT 47.655 12.810 49.865 13.720 ;
        RECT 49.955 13.490 51.325 13.720 ;
        RECT 49.955 12.810 54.085 13.490 ;
        RECT 54.105 12.895 54.535 13.680 ;
        RECT 55.025 13.630 56.615 13.720 ;
        RECT 55.025 12.810 57.595 13.630 ;
        RECT 62.745 13.490 63.675 13.710 ;
        RECT 66.505 13.490 67.845 13.720 ;
        RECT 58.235 12.810 67.845 13.490 ;
        RECT 67.895 12.810 69.265 13.620 ;
        RECT 69.285 12.810 70.635 13.720 ;
        RECT 70.655 12.810 72.025 13.620 ;
        RECT 72.035 12.810 73.405 13.620 ;
        RECT 73.415 12.810 74.785 13.620 ;
        RECT 74.795 12.810 76.165 13.620 ;
        RECT 76.175 12.810 77.545 13.620 ;
        RECT 77.555 12.810 78.925 13.620 ;
        RECT 79.865 12.895 80.295 13.680 ;
        RECT 80.775 12.810 82.145 13.620 ;
        RECT 15.595 12.600 15.765 12.810 ;
        RECT 16.975 12.600 17.145 12.810 ;
        RECT 18.350 12.755 18.470 12.760 ;
        RECT 18.350 12.650 18.525 12.755 ;
        RECT 18.365 12.645 18.525 12.650 ;
        RECT 19.275 12.600 19.445 12.790 ;
        RECT 28.015 12.620 28.185 12.810 ;
        RECT 15.455 11.790 16.825 12.600 ;
        RECT 16.835 11.790 18.205 12.600 ;
        RECT 19.135 11.920 28.745 12.600 ;
        RECT 28.935 12.570 29.105 12.790 ;
        RECT 29.210 12.620 29.380 12.810 ;
        RECT 31.695 12.600 31.865 12.790 ;
        RECT 33.075 12.620 33.245 12.810 ;
        RECT 34.455 12.620 34.625 12.810 ;
        RECT 45.950 12.790 46.120 12.810 ;
        RECT 41.815 12.600 41.985 12.790 ;
        RECT 43.195 12.600 43.365 12.790 ;
        RECT 44.575 12.600 44.745 12.790 ;
        RECT 45.950 12.620 46.125 12.790 ;
        RECT 46.415 12.620 46.585 12.810 ;
        RECT 45.955 12.600 46.125 12.620 ;
        RECT 47.335 12.600 47.505 12.790 ;
        RECT 47.800 12.620 47.970 12.810 ;
        RECT 50.085 12.620 50.255 12.810 ;
        RECT 57.455 12.790 57.595 12.810 ;
        RECT 54.690 12.650 54.810 12.760 ;
        RECT 56.995 12.620 57.165 12.790 ;
        RECT 57.455 12.620 57.625 12.790 ;
        RECT 57.910 12.650 58.030 12.760 ;
        RECT 58.375 12.620 58.545 12.810 ;
        RECT 57.025 12.600 57.165 12.620 ;
        RECT 30.150 12.570 31.545 12.600 ;
        RECT 23.645 11.700 24.575 11.920 ;
        RECT 27.405 11.690 28.745 11.920 ;
        RECT 28.810 11.890 31.545 12.570 ;
        RECT 31.555 11.920 41.165 12.600 ;
        RECT 30.135 11.690 31.545 11.890 ;
        RECT 36.065 11.700 36.995 11.920 ;
        RECT 39.825 11.690 41.165 11.920 ;
        RECT 41.225 11.730 41.655 12.515 ;
        RECT 41.675 11.790 43.045 12.600 ;
        RECT 43.055 11.790 44.425 12.600 ;
        RECT 44.435 11.790 45.805 12.600 ;
        RECT 45.815 11.790 47.185 12.600 ;
        RECT 47.195 11.920 56.805 12.600 ;
        RECT 51.705 11.700 52.635 11.920 ;
        RECT 55.465 11.690 56.805 11.920 ;
        RECT 57.025 11.780 59.595 12.600 ;
        RECT 59.755 12.570 59.925 12.790 ;
        RECT 64.350 12.600 64.520 12.790 ;
        RECT 66.650 12.600 66.820 12.790 ;
        RECT 67.575 12.600 67.745 12.790 ;
        RECT 68.035 12.620 68.205 12.810 ;
        RECT 68.955 12.600 69.125 12.790 ;
        RECT 69.415 12.620 69.585 12.810 ;
        RECT 70.335 12.600 70.505 12.790 ;
        RECT 70.795 12.620 70.965 12.810 ;
        RECT 71.715 12.600 71.885 12.790 ;
        RECT 72.175 12.620 72.345 12.810 ;
        RECT 73.090 12.650 73.210 12.760 ;
        RECT 73.555 12.620 73.725 12.810 ;
        RECT 74.935 12.600 75.105 12.810 ;
        RECT 75.390 12.650 75.510 12.760 ;
        RECT 75.855 12.600 76.025 12.790 ;
        RECT 76.315 12.620 76.485 12.810 ;
        RECT 77.240 12.600 77.410 12.790 ;
        RECT 77.695 12.620 77.865 12.810 ;
        RECT 79.085 12.655 79.245 12.765 ;
        RECT 80.450 12.650 80.570 12.760 ;
        RECT 81.835 12.600 82.005 12.810 ;
        RECT 87.530 12.795 94.490 18.075 ;
        RECT 129.010 12.725 135.970 18.005 ;
        RECT 60.970 12.570 62.365 12.600 ;
        RECT 59.630 11.890 62.365 12.570 ;
        RECT 58.005 11.690 59.595 11.780 ;
        RECT 60.955 11.690 62.365 11.890 ;
        RECT 62.455 11.690 64.665 12.600 ;
        RECT 64.755 11.690 66.965 12.600 ;
        RECT 66.985 11.730 67.415 12.515 ;
        RECT 67.435 11.790 68.805 12.600 ;
        RECT 68.815 11.790 70.185 12.600 ;
        RECT 70.195 11.790 71.565 12.600 ;
        RECT 71.575 11.790 72.945 12.600 ;
        RECT 73.415 11.920 75.245 12.600 ;
        RECT 73.415 11.690 74.760 11.920 ;
        RECT 75.725 11.690 77.075 12.600 ;
        RECT 77.095 11.920 80.765 12.600 ;
        RECT 77.620 11.690 80.010 11.920 ;
        RECT 80.775 11.790 82.145 12.600 ;
      LAYER nwell ;
        RECT 15.260 8.570 82.340 11.400 ;
      LAYER pwell ;
        RECT 16.845 8.190 18.435 8.280 ;
        RECT 15.455 7.370 16.825 8.180 ;
        RECT 16.845 7.370 19.415 8.190 ;
        RECT 19.690 8.050 20.610 8.280 ;
        RECT 23.275 8.050 24.205 8.280 ;
        RECT 19.690 7.370 23.155 8.050 ;
        RECT 23.275 7.370 27.175 8.050 ;
        RECT 28.345 7.455 28.775 8.240 ;
        RECT 28.795 7.370 31.005 8.280 ;
        RECT 31.180 7.370 40.285 8.050 ;
        RECT 40.295 7.370 42.905 8.280 ;
        RECT 43.055 7.370 44.425 8.180 ;
        RECT 44.435 7.370 53.540 8.050 ;
        RECT 54.105 7.455 54.535 8.240 ;
        RECT 54.555 7.370 55.925 8.180 ;
        RECT 56.855 7.370 60.065 8.280 ;
        RECT 65.505 8.050 66.435 8.270 ;
        RECT 69.265 8.050 70.605 8.280 ;
        RECT 60.995 7.370 70.605 8.050 ;
        RECT 71.115 8.050 72.045 8.280 ;
        RECT 76.470 8.050 78.860 8.280 ;
        RECT 71.115 7.370 75.015 8.050 ;
        RECT 75.715 7.370 79.385 8.050 ;
        RECT 79.865 7.455 80.295 8.240 ;
        RECT 80.775 7.370 82.145 8.180 ;
        RECT 15.595 7.160 15.765 7.370 ;
        RECT 19.275 7.350 19.415 7.370 ;
        RECT 19.275 7.180 19.445 7.350 ;
        RECT 20.190 7.160 20.360 7.350 ;
        RECT 20.655 7.160 20.825 7.350 ;
        RECT 22.035 7.160 22.205 7.350 ;
        RECT 22.955 7.180 23.125 7.370 ;
        RECT 23.690 7.180 23.860 7.370 ;
        RECT 27.565 7.215 27.725 7.325 ;
        RECT 28.940 7.180 29.110 7.370 ;
        RECT 34.915 7.160 35.085 7.350 ;
        RECT 39.975 7.180 40.145 7.370 ;
        RECT 40.440 7.180 40.610 7.370 ;
        RECT 40.895 7.160 41.065 7.350 ;
        RECT 41.815 7.160 41.985 7.350 ;
        RECT 43.195 7.160 43.365 7.370 ;
        RECT 44.575 7.320 44.745 7.370 ;
        RECT 44.570 7.210 44.745 7.320 ;
        RECT 44.575 7.180 44.745 7.210 ;
        RECT 45.040 7.160 45.210 7.350 ;
        RECT 50.550 7.160 50.720 7.350 ;
        RECT 51.020 7.160 51.190 7.350 ;
        RECT 53.770 7.210 53.890 7.320 ;
        RECT 54.695 7.180 54.865 7.370 ;
        RECT 55.155 7.160 55.325 7.350 ;
        RECT 56.085 7.215 56.245 7.325 ;
        RECT 56.535 7.160 56.705 7.350 ;
        RECT 56.995 7.180 57.165 7.370 ;
        RECT 60.225 7.215 60.385 7.325 ;
        RECT 61.135 7.180 61.305 7.370 ;
        RECT 65.735 7.160 65.905 7.350 ;
        RECT 67.580 7.160 67.750 7.350 ;
        RECT 70.795 7.320 70.965 7.350 ;
        RECT 69.885 7.205 70.045 7.315 ;
        RECT 70.790 7.210 70.965 7.320 ;
        RECT 70.795 7.160 70.965 7.210 ;
        RECT 71.530 7.180 71.700 7.370 ;
        RECT 75.390 7.210 75.510 7.320 ;
        RECT 79.070 7.180 79.240 7.370 ;
        RECT 79.530 7.210 79.650 7.320 ;
        RECT 80.450 7.210 80.570 7.320 ;
        RECT 81.835 7.160 82.005 7.370 ;
        RECT 15.455 6.350 16.825 7.160 ;
        RECT 16.835 6.480 20.505 7.160 ;
        RECT 17.590 6.250 19.980 6.480 ;
        RECT 20.525 6.250 21.875 7.160 ;
        RECT 21.895 6.480 31.505 7.160 ;
        RECT 26.405 6.260 27.335 6.480 ;
        RECT 30.165 6.250 31.505 6.480 ;
        RECT 31.650 6.480 35.115 7.160 ;
        RECT 31.650 6.250 32.570 6.480 ;
        RECT 35.385 6.250 41.205 7.160 ;
        RECT 41.225 6.290 41.655 7.075 ;
        RECT 41.675 6.350 43.045 7.160 ;
        RECT 43.055 6.350 44.425 7.160 ;
        RECT 44.895 6.250 47.105 7.160 ;
        RECT 47.195 6.480 50.865 7.160 ;
        RECT 47.950 6.250 50.340 6.480 ;
        RECT 50.875 6.250 55.005 7.160 ;
        RECT 55.015 6.350 56.385 7.160 ;
        RECT 56.395 6.480 65.500 7.160 ;
        RECT 65.595 6.350 66.965 7.160 ;
        RECT 66.985 6.290 67.415 7.075 ;
        RECT 67.435 6.250 69.645 7.160 ;
        RECT 70.655 6.480 80.265 7.160 ;
        RECT 75.165 6.260 76.095 6.480 ;
        RECT 78.925 6.250 80.265 6.480 ;
        RECT 80.775 6.350 82.145 7.160 ;
      LAYER nwell ;
        RECT 15.260 3.130 82.340 5.960 ;
      LAYER pwell ;
        RECT 15.455 1.930 16.825 2.740 ;
        RECT 16.835 1.930 18.205 2.740 ;
        RECT 18.680 2.730 20.450 2.840 ;
        RECT 18.680 2.610 21.380 2.730 ;
        RECT 26.045 2.610 26.965 2.830 ;
        RECT 18.680 1.930 28.325 2.610 ;
        RECT 28.345 2.015 28.775 2.800 ;
        RECT 28.890 2.610 29.810 2.840 ;
        RECT 37.905 2.610 38.835 2.830 ;
        RECT 41.665 2.610 43.005 2.840 ;
        RECT 48.025 2.610 48.955 2.830 ;
        RECT 51.785 2.610 53.125 2.840 ;
        RECT 28.890 1.930 32.355 2.610 ;
        RECT 33.395 1.930 43.005 2.610 ;
        RECT 43.515 1.930 53.125 2.610 ;
        RECT 54.105 2.015 54.535 2.800 ;
        RECT 54.555 2.610 56.145 2.840 ;
        RECT 65.505 2.610 66.435 2.830 ;
        RECT 69.265 2.610 70.605 2.840 ;
        RECT 54.555 1.930 58.225 2.610 ;
        RECT 58.235 1.930 60.975 2.610 ;
        RECT 60.995 1.930 70.605 2.610 ;
        RECT 70.655 1.930 72.025 2.740 ;
        RECT 73.250 2.610 75.640 2.840 ;
        RECT 76.270 2.610 77.190 2.840 ;
        RECT 72.495 1.930 76.165 2.610 ;
        RECT 76.270 1.930 79.735 2.610 ;
        RECT 79.865 2.015 80.295 2.800 ;
        RECT 80.775 1.930 82.145 2.740 ;
        RECT 15.595 1.720 15.765 1.930 ;
        RECT 16.975 1.720 17.145 1.930 ;
        RECT 18.350 1.770 18.470 1.880 ;
        RECT 19.275 1.720 19.445 1.910 ;
        RECT 28.015 1.740 28.185 1.930 ;
        RECT 28.935 1.720 29.105 1.910 ;
        RECT 30.315 1.720 30.485 1.910 ;
        RECT 30.785 1.765 30.945 1.875 ;
        RECT 32.155 1.740 32.325 1.930 ;
        RECT 32.625 1.775 32.785 1.885 ;
        RECT 33.535 1.740 33.705 1.930 ;
        RECT 40.895 1.720 41.065 1.910 ;
        RECT 41.820 1.720 41.990 1.910 ;
        RECT 43.190 1.770 43.310 1.880 ;
        RECT 43.655 1.740 43.825 1.930 ;
        RECT 57.910 1.910 58.080 1.930 ;
        RECT 45.495 1.720 45.665 1.910 ;
        RECT 46.870 1.770 46.990 1.880 ;
        RECT 47.335 1.720 47.505 1.910 ;
        RECT 53.325 1.775 53.485 1.885 ;
        RECT 57.910 1.740 58.085 1.910 ;
        RECT 57.915 1.720 58.085 1.740 ;
        RECT 58.375 1.720 58.545 1.930 ;
        RECT 61.135 1.740 61.305 1.930 ;
        RECT 64.355 1.740 64.525 1.910 ;
        RECT 67.570 1.770 67.690 1.880 ;
        RECT 64.385 1.720 64.525 1.740 ;
        RECT 68.035 1.720 68.205 1.910 ;
        RECT 70.795 1.740 70.965 1.930 ;
        RECT 72.170 1.770 72.290 1.880 ;
        RECT 75.850 1.740 76.020 1.930 ;
        RECT 77.700 1.720 77.870 1.910 ;
        RECT 79.535 1.740 79.705 1.930 ;
        RECT 80.005 1.765 80.165 1.875 ;
        RECT 80.450 1.770 80.570 1.880 ;
        RECT 81.835 1.720 82.005 1.930 ;
        RECT 15.455 0.910 16.825 1.720 ;
        RECT 16.835 0.910 18.205 1.720 ;
        RECT 18.225 0.810 19.575 1.720 ;
        RECT 19.635 1.040 29.245 1.720 ;
        RECT 19.635 0.810 20.975 1.040 ;
        RECT 23.805 0.820 24.735 1.040 ;
        RECT 29.265 0.810 30.615 1.720 ;
        RECT 31.595 1.040 41.205 1.720 ;
        RECT 31.595 0.810 32.935 1.040 ;
        RECT 35.765 0.820 36.695 1.040 ;
        RECT 41.225 0.850 41.655 1.635 ;
        RECT 41.675 1.040 45.345 1.720 ;
        RECT 42.200 0.810 44.590 1.040 ;
        RECT 45.365 0.810 46.715 1.720 ;
        RECT 47.195 1.040 56.805 1.720 ;
        RECT 51.705 0.820 52.635 1.040 ;
        RECT 55.465 0.810 56.805 1.040 ;
        RECT 56.865 0.810 58.215 1.720 ;
        RECT 58.235 0.810 64.055 1.720 ;
        RECT 64.385 0.900 66.955 1.720 ;
        RECT 65.365 0.810 66.955 0.900 ;
        RECT 66.985 0.850 67.415 1.635 ;
        RECT 67.895 1.040 77.505 1.720 ;
        RECT 72.405 0.820 73.335 1.040 ;
        RECT 76.165 0.810 77.505 1.040 ;
        RECT 77.555 0.810 79.765 1.720 ;
        RECT 80.775 0.910 82.145 1.720 ;
        RECT 84.040 0.660 89.740 3.460 ;
      LAYER nwell ;
        RECT 89.740 0.660 95.440 3.460 ;
        RECT 15.260 0.000 82.340 0.520 ;
      LAYER pwell ;
        RECT 15.455 -3.510 16.825 -2.700 ;
        RECT 17.590 -2.830 19.980 -2.600 ;
        RECT 23.630 -2.830 24.550 -2.600 ;
        RECT 25.410 -2.830 27.800 -2.600 ;
        RECT 16.835 -3.510 20.505 -2.830 ;
        RECT 21.085 -3.510 24.550 -2.830 ;
        RECT 24.655 -3.510 28.325 -2.830 ;
        RECT 28.795 -3.510 31.835 -2.600 ;
        RECT 34.670 -2.830 35.590 -2.600 ;
        RECT 32.125 -3.510 35.590 -2.830 ;
        RECT 35.695 -2.830 36.625 -2.600 ;
        RECT 35.695 -3.510 39.595 -2.830 ;
        RECT 39.835 -3.510 41.205 -2.700 ;
        RECT 42.200 -2.830 44.590 -2.600 ;
        RECT 45.355 -2.830 46.720 -2.600 ;
        RECT 41.675 -3.510 45.345 -2.830 ;
        RECT 45.355 -3.510 48.565 -2.830 ;
        RECT 48.575 -3.510 49.945 -2.700 ;
        RECT 49.955 -2.830 50.885 -2.600 ;
        RECT 54.650 -2.830 55.570 -2.600 ;
        RECT 58.990 -2.830 61.380 -2.600 ;
        RECT 62.440 -2.830 64.830 -2.600 ;
        RECT 49.955 -3.510 53.855 -2.830 ;
        RECT 54.650 -3.510 58.115 -2.830 ;
        RECT 58.235 -3.510 61.905 -2.830 ;
        RECT 61.915 -3.510 65.585 -2.830 ;
        RECT 65.595 -3.510 66.965 -2.700 ;
        RECT 68.355 -2.830 69.285 -2.600 ;
        RECT 68.355 -3.510 72.255 -2.830 ;
        RECT 72.505 -3.510 73.855 -2.600 ;
        RECT 73.970 -2.830 74.890 -2.600 ;
        RECT 73.970 -3.510 77.435 -2.830 ;
        RECT 77.555 -3.510 79.765 -2.600 ;
        RECT 80.775 -3.510 82.145 -2.700 ;
        RECT 15.595 -3.700 15.765 -3.510 ;
        RECT 20.190 -3.700 20.360 -3.510 ;
        RECT 20.650 -3.670 20.770 -3.560 ;
        RECT 21.115 -3.700 21.285 -3.510 ;
        RECT 28.010 -3.700 28.180 -3.510 ;
        RECT 31.690 -3.530 31.835 -3.510 ;
        RECT 31.690 -3.700 31.860 -3.530 ;
        RECT 32.155 -3.700 32.325 -3.510 ;
        RECT 36.110 -3.700 36.280 -3.510 ;
        RECT 39.975 -3.700 40.145 -3.510 ;
        RECT 41.820 -3.700 41.990 -3.510 ;
        RECT 48.250 -3.700 48.420 -3.510 ;
        RECT 48.715 -3.700 48.885 -3.510 ;
        RECT 50.370 -3.700 50.540 -3.510 ;
        RECT 57.915 -3.700 58.085 -3.510 ;
        RECT 61.590 -3.700 61.760 -3.510 ;
        RECT 62.060 -3.700 62.230 -3.510 ;
        RECT 65.735 -3.700 65.905 -3.510 ;
        RECT 67.585 -3.665 67.745 -3.555 ;
        RECT 68.770 -3.700 68.940 -3.510 ;
        RECT 72.635 -3.700 72.805 -3.510 ;
        RECT 77.235 -3.700 77.405 -3.510 ;
        RECT 77.700 -3.700 77.870 -3.510 ;
        RECT 80.450 -3.670 80.570 -3.560 ;
        RECT 81.835 -3.700 82.005 -3.510 ;
      LAYER li1 ;
        RECT 35.380 99.130 36.850 99.300 ;
        RECT 35.380 98.000 35.550 99.130 ;
        RECT 35.870 98.400 36.360 98.730 ;
        RECT 36.680 98.000 36.850 99.130 ;
        RECT 35.380 97.830 36.850 98.000 ;
        RECT 38.830 99.100 40.300 99.270 ;
        RECT 38.830 97.970 39.000 99.100 ;
        RECT 39.320 98.370 39.810 98.700 ;
        RECT 40.130 97.970 40.300 99.100 ;
        RECT 38.830 97.800 40.300 97.970 ;
        RECT 42.710 99.060 44.180 99.230 ;
        RECT 42.710 97.930 42.880 99.060 ;
        RECT 43.200 98.330 43.690 98.660 ;
        RECT 44.010 97.930 44.180 99.060 ;
        RECT 115.335 98.855 116.535 99.155 ;
        RECT 42.710 97.760 44.180 97.930 ;
        RECT 102.200 96.380 102.850 96.600 ;
        RECT 97.740 96.080 102.850 96.380 ;
        RECT 102.200 95.950 102.850 96.080 ;
        RECT 16.170 94.720 17.270 94.770 ;
        RECT 11.120 93.720 17.270 94.720 ;
        RECT 11.120 92.360 12.120 93.720 ;
        RECT 16.170 93.670 17.270 93.720 ;
        RECT 11.110 92.245 12.120 92.360 ;
        RECT 11.095 91.470 12.120 92.245 ;
        RECT 13.030 91.560 14.630 91.960 ;
        RECT 11.095 87.960 12.070 91.470 ;
        RECT 12.390 89.560 12.710 90.760 ;
        RECT 13.670 89.960 15.270 90.360 ;
        RECT 15.590 89.560 15.910 90.760 ;
        RECT 13.030 88.360 14.630 88.760 ;
        RECT 16.230 87.960 17.190 92.360 ;
        RECT 11.095 85.810 12.045 87.960 ;
        RECT 21.610 86.400 22.570 95.010 ;
        RECT 23.530 94.210 25.130 94.610 ;
        RECT 22.890 92.210 23.210 93.410 ;
        RECT 24.170 92.610 25.770 93.010 ;
        RECT 26.090 92.210 26.410 93.410 ;
        RECT 23.530 91.010 25.130 91.410 ;
        RECT 26.730 90.610 27.690 95.010 ;
        RECT 39.040 94.780 56.080 95.340 ;
        RECT 31.910 93.360 32.860 94.220 ;
        RECT 23.530 89.510 25.130 89.910 ;
        RECT 22.890 87.510 23.210 88.710 ;
        RECT 24.170 87.910 25.770 88.310 ;
        RECT 26.090 87.510 26.410 88.710 ;
        RECT 21.590 85.910 22.570 86.400 ;
        RECT 23.530 86.310 25.130 86.710 ;
        RECT 26.730 85.910 27.690 90.310 ;
        RECT 31.900 88.960 32.860 93.360 ;
        RECT 33.820 92.560 35.420 92.960 ;
        RECT 33.180 90.560 33.500 91.760 ;
        RECT 34.460 90.960 36.060 91.360 ;
        RECT 36.380 90.560 36.700 91.760 ;
        RECT 33.820 89.360 35.420 89.760 ;
        RECT 37.020 88.960 37.980 93.360 ;
        RECT 39.040 86.660 39.600 94.780 ;
        RECT 40.360 92.520 41.560 93.600 ;
        RECT 40.360 92.160 45.160 92.520 ;
        RECT 40.360 91.080 45.160 91.440 ;
        RECT 52.360 91.080 54.760 92.520 ;
        RECT 40.360 90.360 41.560 91.080 ;
        RECT 40.360 90.000 45.160 90.360 ;
        RECT 40.360 88.920 45.160 89.280 ;
        RECT 52.360 88.920 54.760 90.360 ;
        RECT 40.360 87.840 41.560 88.920 ;
        RECT 55.520 86.670 56.080 94.780 ;
        RECT 62.160 88.990 63.120 95.210 ;
        RECT 64.080 94.410 65.680 94.810 ;
        RECT 63.440 92.410 63.760 93.610 ;
        RECT 64.720 92.810 66.320 93.210 ;
        RECT 66.640 92.410 66.960 93.610 ;
        RECT 64.080 91.210 65.680 91.610 ;
        RECT 67.280 90.810 68.240 95.210 ;
        RECT 78.810 89.660 79.770 95.500 ;
        RECT 80.730 93.260 82.330 93.660 ;
        RECT 80.090 91.260 80.410 92.460 ;
        RECT 81.370 91.660 82.970 92.060 ;
        RECT 83.290 91.260 83.610 92.460 ;
        RECT 80.730 90.060 82.330 90.460 ;
        RECT 83.930 89.660 84.890 94.060 ;
        RECT 87.060 89.660 88.020 95.500 ;
        RECT 88.980 93.260 90.580 93.660 ;
        RECT 88.340 91.260 88.660 92.460 ;
        RECT 89.620 91.660 91.220 92.060 ;
        RECT 91.540 91.260 91.860 92.460 ;
        RECT 88.980 90.060 90.580 90.460 ;
        RECT 92.180 89.660 93.140 94.060 ;
        RECT 100.260 91.770 101.160 93.770 ;
        RECT 102.330 92.920 102.630 95.950 ;
        RECT 110.430 93.770 110.830 95.160 ;
        RECT 103.860 93.020 107.460 93.320 ;
        RECT 102.060 92.620 102.960 92.920 ;
        RECT 102.330 91.950 102.630 92.620 ;
        RECT 103.860 92.520 104.700 92.540 ;
        RECT 103.860 92.220 104.760 92.520 ;
        RECT 105.490 91.910 105.790 93.020 ;
        RECT 108.360 92.620 109.260 92.920 ;
        RECT 106.560 92.520 107.400 92.540 ;
        RECT 106.560 92.220 107.460 92.520 ;
        RECT 110.160 91.770 111.060 93.770 ;
        RECT 100.520 90.680 100.920 91.770 ;
        RECT 115.005 90.880 115.955 97.010 ;
        RECT 116.235 94.555 116.535 98.855 ;
        RECT 120.200 97.500 120.700 98.300 ;
        RECT 120.000 96.550 120.900 97.500 ;
        RECT 118.650 96.250 122.250 96.550 ;
        RECT 116.850 95.850 118.350 96.150 ;
        RECT 123.150 95.850 124.050 96.150 ;
        RECT 116.230 94.240 117.760 94.555 ;
        RECT 118.050 94.150 118.350 95.850 ;
        RECT 118.650 95.750 119.490 95.770 ;
        RECT 121.350 95.750 122.190 95.770 ;
        RECT 118.650 95.450 119.550 95.750 ;
        RECT 121.350 95.450 122.250 95.750 ;
        RECT 118.650 94.950 119.490 94.970 ;
        RECT 118.650 94.650 119.550 94.950 ;
        RECT 119.850 94.650 122.250 94.950 ;
        RECT 119.850 94.150 120.150 94.650 ;
        RECT 123.150 94.250 124.050 94.550 ;
        RECT 118.050 93.850 120.150 94.150 ;
        RECT 121.350 93.850 122.250 94.150 ;
        RECT 116.850 91.350 117.750 93.750 ;
        RECT 123.150 93.450 124.050 93.750 ;
        RECT 118.650 93.350 119.490 93.370 ;
        RECT 121.350 93.350 122.190 93.370 ;
        RECT 118.650 93.050 119.550 93.350 ;
        RECT 121.350 93.050 122.250 93.350 ;
        RECT 124.950 92.600 125.850 98.650 ;
        RECT 138.980 95.185 139.880 97.630 ;
        RECT 142.580 96.880 144.765 97.180 ;
        RECT 145.280 96.880 146.780 97.180 ;
        RECT 146.480 96.780 146.780 96.880 ;
        RECT 140.780 96.480 141.680 96.780 ;
        RECT 146.480 96.480 147.980 96.780 ;
        RECT 142.580 96.380 143.420 96.400 ;
        RECT 145.280 96.380 146.120 96.400 ;
        RECT 142.580 96.080 143.480 96.380 ;
        RECT 145.280 96.080 146.180 96.380 ;
        RECT 142.580 95.585 143.420 95.605 ;
        RECT 145.280 95.585 146.120 95.605 ;
        RECT 141.980 95.285 143.480 95.585 ;
        RECT 145.280 95.285 146.780 95.585 ;
        RECT 141.980 95.185 142.280 95.285 ;
        RECT 138.980 94.885 142.280 95.185 ;
        RECT 138.980 94.035 139.880 94.885 ;
        RECT 141.980 94.785 142.280 94.885 ;
        RECT 146.480 95.185 146.780 95.285 ;
        RECT 148.880 95.185 149.780 97.630 ;
        RECT 146.480 94.885 149.780 95.185 ;
        RECT 142.580 94.785 143.420 94.805 ;
        RECT 145.280 94.785 146.120 94.805 ;
        RECT 146.480 94.785 146.780 94.885 ;
        RECT 141.980 94.485 143.480 94.785 ;
        RECT 145.280 94.485 146.780 94.785 ;
        RECT 148.880 94.035 149.780 94.885 ;
        RECT 115.005 89.950 119.535 90.880 ;
        RECT 115.005 89.945 115.955 89.950 ;
        RECT 99.920 88.940 101.520 88.970 ;
        RECT 122.570 88.940 124.170 88.970 ;
        RECT 78.300 88.380 145.850 88.940 ;
        RECT 55.210 86.660 56.210 86.670 ;
        RECT 11.095 81.410 12.070 85.810 ;
        RECT 13.030 85.010 14.630 85.410 ;
        RECT 12.390 83.010 12.710 84.210 ;
        RECT 13.670 83.410 15.270 83.810 ;
        RECT 15.590 83.010 15.910 84.210 ;
        RECT 13.030 81.810 14.630 82.210 ;
        RECT 16.230 81.410 17.190 85.810 ;
        RECT 21.590 85.610 22.550 85.910 ;
        RECT 11.095 79.260 12.045 81.410 ;
        RECT 21.590 81.210 22.570 85.610 ;
        RECT 23.530 84.810 25.130 85.210 ;
        RECT 22.890 82.810 23.210 84.010 ;
        RECT 24.170 83.210 25.770 83.610 ;
        RECT 26.090 82.810 26.410 84.010 ;
        RECT 23.530 81.610 25.130 82.010 ;
        RECT 26.730 81.210 27.690 85.610 ;
        RECT 31.910 85.360 32.910 86.370 ;
        RECT 39.040 86.100 56.210 86.660 ;
        RECT 55.210 85.420 56.210 86.100 ;
        RECT 31.900 84.170 32.910 85.360 ;
        RECT 33.820 84.560 35.420 84.960 ;
        RECT 21.590 80.910 22.550 81.210 ;
        RECT 31.900 80.960 32.860 84.170 ;
        RECT 33.180 82.560 33.500 83.760 ;
        RECT 34.460 82.960 36.060 83.360 ;
        RECT 36.380 82.560 36.700 83.760 ;
        RECT 33.820 81.360 35.420 81.760 ;
        RECT 37.020 80.960 37.980 85.360 ;
        RECT 39.330 84.400 41.360 85.360 ;
        RECT 42.320 84.560 43.920 84.960 ;
        RECT 40.400 80.960 41.360 84.400 ;
        RECT 41.680 82.560 42.000 83.760 ;
        RECT 42.960 82.960 44.560 83.360 ;
        RECT 44.880 82.560 45.200 83.760 ;
        RECT 42.320 81.360 43.920 81.760 ;
        RECT 45.520 80.960 46.480 85.360 ;
        RECT 47.390 84.920 48.350 84.940 ;
        RECT 11.095 74.860 12.070 79.260 ;
        RECT 13.030 78.460 14.630 78.860 ;
        RECT 12.390 76.460 12.710 77.660 ;
        RECT 13.670 76.860 15.270 77.260 ;
        RECT 15.590 76.460 15.910 77.660 ;
        RECT 13.030 75.260 14.630 75.660 ;
        RECT 16.230 74.860 17.190 79.260 ;
        RECT 21.590 76.510 22.570 80.910 ;
        RECT 23.530 80.110 25.130 80.510 ;
        RECT 22.890 78.110 23.210 79.310 ;
        RECT 24.170 78.510 25.770 78.910 ;
        RECT 26.090 78.110 26.410 79.310 ;
        RECT 23.530 76.910 25.130 77.310 ;
        RECT 26.730 76.510 27.690 80.910 ;
        RECT 47.390 80.540 48.370 84.920 ;
        RECT 49.310 84.140 50.910 84.540 ;
        RECT 48.670 82.140 48.990 83.340 ;
        RECT 49.950 82.540 51.550 82.940 ;
        RECT 51.870 82.140 52.190 83.340 ;
        RECT 49.310 80.940 50.910 81.340 ;
        RECT 52.510 80.540 53.470 84.940 ;
        RECT 58.700 84.120 59.660 84.520 ;
        RECT 58.700 83.720 62.220 84.120 ;
        RECT 47.410 79.680 48.370 80.540 ;
        RECT 58.700 80.120 59.660 83.720 ;
        RECT 59.980 81.720 60.300 82.920 ;
        RECT 61.260 82.120 62.860 82.520 ;
        RECT 63.180 81.720 63.500 82.920 ;
        RECT 60.620 80.520 62.220 80.920 ;
        RECT 63.820 80.120 64.780 84.520 ;
        RECT 21.590 76.250 22.550 76.510 ;
        RECT 21.590 75.210 22.580 76.250 ;
        RECT 38.150 75.210 39.110 79.610 ;
        RECT 40.070 78.810 41.670 79.210 ;
        RECT 39.430 76.810 39.750 78.010 ;
        RECT 40.710 77.210 42.310 77.610 ;
        RECT 42.630 76.810 42.950 78.010 ;
        RECT 40.070 75.610 41.670 76.010 ;
        RECT 43.270 75.210 44.230 79.610 ;
        RECT 47.390 75.280 48.370 79.680 ;
        RECT 49.310 78.880 50.910 79.280 ;
        RECT 48.670 76.880 48.990 78.080 ;
        RECT 49.950 77.280 51.550 77.680 ;
        RECT 51.870 76.880 52.190 78.080 ;
        RECT 49.310 75.680 50.910 76.080 ;
        RECT 52.510 75.280 53.470 79.680 ;
        RECT 55.310 78.840 56.270 79.240 ;
        RECT 55.310 78.440 58.830 78.840 ;
        RECT 11.095 72.710 12.045 74.860 ;
        RECT 11.095 68.310 12.070 72.710 ;
        RECT 13.030 71.910 14.630 72.310 ;
        RECT 12.390 69.910 12.710 71.110 ;
        RECT 13.670 70.310 15.270 70.710 ;
        RECT 15.590 69.910 15.910 71.110 ;
        RECT 13.030 68.710 14.630 69.110 ;
        RECT 16.230 68.310 17.190 72.710 ;
        RECT 21.620 70.660 22.580 75.210 ;
        RECT 23.540 73.860 25.140 74.260 ;
        RECT 22.900 71.860 23.220 73.060 ;
        RECT 24.180 72.260 25.780 72.660 ;
        RECT 26.100 71.860 26.420 73.060 ;
        RECT 23.540 70.660 25.140 71.060 ;
        RECT 26.740 70.660 27.700 74.660 ;
        RECT 21.610 70.260 22.580 70.660 ;
        RECT 26.730 70.260 27.700 70.660 ;
        RECT 33.400 74.020 34.360 74.360 ;
        RECT 33.400 73.960 36.460 74.020 ;
        RECT 33.400 73.560 36.920 73.960 ;
        RECT 33.400 73.520 36.460 73.560 ;
        RECT 11.095 66.160 12.045 68.310 ;
        RECT 11.095 61.760 12.070 66.160 ;
        RECT 13.030 65.360 14.630 65.760 ;
        RECT 12.390 63.360 12.710 64.560 ;
        RECT 13.670 63.760 15.270 64.160 ;
        RECT 15.590 63.360 15.910 64.560 ;
        RECT 13.030 62.160 14.630 62.560 ;
        RECT 16.230 61.760 17.190 66.160 ;
        RECT 11.095 59.610 12.045 61.760 ;
        RECT 11.095 55.210 12.070 59.610 ;
        RECT 13.030 58.810 14.630 59.210 ;
        RECT 12.390 56.810 12.710 58.010 ;
        RECT 13.670 57.210 15.270 57.610 ;
        RECT 15.590 56.810 15.910 58.010 ;
        RECT 13.030 55.610 14.630 56.010 ;
        RECT 16.230 55.210 17.190 59.610 ;
        RECT 21.610 58.260 22.570 70.260 ;
        RECT 23.530 69.860 25.130 70.260 ;
        RECT 22.890 67.860 23.210 69.060 ;
        RECT 24.170 68.260 25.770 68.660 ;
        RECT 26.090 67.860 26.410 69.060 ;
        RECT 23.530 66.660 25.130 67.060 ;
        RECT 23.530 65.860 25.130 66.260 ;
        RECT 22.890 63.860 23.210 65.060 ;
        RECT 24.170 64.260 25.770 64.660 ;
        RECT 26.090 63.860 26.410 65.060 ;
        RECT 23.530 62.660 25.130 63.060 ;
        RECT 23.530 61.860 25.130 62.260 ;
        RECT 22.890 59.860 23.210 61.060 ;
        RECT 24.170 60.260 25.770 60.660 ;
        RECT 26.090 59.860 26.410 61.060 ;
        RECT 23.530 58.660 25.130 59.060 ;
        RECT 26.730 58.260 27.690 70.260 ;
        RECT 33.400 69.960 34.360 73.520 ;
        RECT 34.680 71.560 35.000 72.760 ;
        RECT 35.960 71.960 37.560 72.360 ;
        RECT 37.880 71.560 38.200 72.760 ;
        RECT 35.320 70.360 36.920 70.760 ;
        RECT 38.520 69.960 39.480 74.360 ;
        RECT 40.400 74.020 41.360 74.360 ;
        RECT 40.400 73.960 43.460 74.020 ;
        RECT 40.400 73.560 43.920 73.960 ;
        RECT 40.400 73.520 43.460 73.560 ;
        RECT 40.400 69.960 41.360 73.520 ;
        RECT 41.680 71.560 42.000 72.760 ;
        RECT 42.960 71.960 44.560 72.360 ;
        RECT 44.880 71.560 45.200 72.760 ;
        RECT 42.320 70.360 43.920 70.760 ;
        RECT 45.520 69.960 46.480 74.360 ;
        RECT 47.410 74.020 48.370 75.280 ;
        RECT 55.310 74.840 56.270 78.440 ;
        RECT 56.590 77.950 59.190 78.270 ;
        RECT 56.590 76.440 56.910 77.640 ;
        RECT 57.870 76.840 59.470 77.240 ;
        RECT 59.790 76.440 60.110 77.640 ;
        RECT 57.230 75.240 58.830 75.640 ;
        RECT 60.430 74.840 61.390 79.240 ;
        RECT 62.160 78.850 63.120 79.250 ;
        RECT 62.160 78.450 65.680 78.850 ;
        RECT 62.160 74.850 63.120 78.450 ;
        RECT 63.440 76.450 63.760 77.650 ;
        RECT 64.720 76.850 66.320 77.250 ;
        RECT 66.640 76.450 66.960 77.650 ;
        RECT 64.080 75.250 65.680 75.650 ;
        RECT 67.280 74.850 68.240 79.250 ;
        RECT 47.410 73.960 50.460 74.020 ;
        RECT 47.410 73.560 50.930 73.960 ;
        RECT 47.410 73.520 50.460 73.560 ;
        RECT 47.410 69.960 48.370 73.520 ;
        RECT 48.690 71.560 49.010 72.760 ;
        RECT 49.970 71.960 51.570 72.360 ;
        RECT 51.890 71.560 52.210 72.760 ;
        RECT 49.330 70.360 50.930 70.760 ;
        RECT 52.530 69.960 53.490 74.360 ;
        RECT 55.310 69.260 56.270 73.950 ;
        RECT 57.230 73.150 58.830 73.550 ;
        RECT 56.590 71.150 56.910 72.350 ;
        RECT 57.870 71.550 59.470 71.950 ;
        RECT 59.790 71.150 60.110 72.350 ;
        RECT 57.230 69.950 58.830 70.350 ;
        RECT 60.430 69.550 61.390 73.950 ;
        RECT 62.160 69.260 63.120 73.950 ;
        RECT 64.080 73.150 65.680 73.550 ;
        RECT 63.440 71.150 63.760 72.350 ;
        RECT 64.720 71.550 66.320 71.950 ;
        RECT 66.640 71.150 66.960 72.350 ;
        RECT 64.080 69.950 65.680 70.350 ;
        RECT 67.280 69.550 68.240 73.950 ;
        RECT 70.510 71.020 71.470 88.060 ;
        RECT 72.430 87.260 74.030 87.660 ;
        RECT 71.790 85.260 72.110 86.460 ;
        RECT 73.070 85.660 74.670 86.060 ;
        RECT 74.990 85.260 75.310 86.460 ;
        RECT 72.430 84.060 74.030 84.460 ;
        RECT 75.630 83.660 76.590 88.060 ;
        RECT 72.430 82.560 74.030 82.960 ;
        RECT 71.790 80.560 72.110 81.760 ;
        RECT 73.070 80.960 74.670 81.360 ;
        RECT 74.990 80.560 75.310 81.760 ;
        RECT 72.430 79.360 74.030 79.760 ;
        RECT 75.630 78.960 76.590 83.360 ;
        RECT 72.430 77.860 74.030 78.260 ;
        RECT 71.790 75.860 72.110 77.060 ;
        RECT 73.070 76.260 74.670 76.660 ;
        RECT 74.990 75.860 75.310 77.060 ;
        RECT 72.430 74.660 74.030 75.060 ;
        RECT 75.630 74.260 76.590 78.660 ;
        RECT 72.430 73.160 74.030 73.560 ;
        RECT 71.790 71.160 72.110 72.360 ;
        RECT 73.070 71.560 74.670 71.960 ;
        RECT 74.990 71.160 75.310 72.360 ;
        RECT 68.420 69.520 71.470 71.020 ;
        RECT 72.430 69.960 74.030 70.360 ;
        RECT 75.630 69.560 76.590 73.960 ;
        RECT 78.300 73.220 78.860 88.380 ;
        RECT 80.040 86.420 81.480 87.620 ;
        RECT 81.120 82.820 81.480 86.420 ;
        RECT 82.200 86.420 83.640 87.620 ;
        RECT 82.200 82.820 82.560 86.420 ;
        RECT 83.280 82.820 83.640 86.420 ;
        RECT 84.360 86.420 85.800 87.620 ;
        RECT 84.360 82.820 84.720 86.420 ;
        RECT 85.440 82.820 85.800 86.420 ;
        RECT 86.520 86.420 87.960 87.620 ;
        RECT 86.520 82.820 86.880 86.420 ;
        RECT 87.600 82.820 87.960 86.420 ;
        RECT 88.680 86.420 90.120 87.620 ;
        RECT 88.680 82.820 89.040 86.420 ;
        RECT 89.760 82.820 90.120 86.420 ;
        RECT 90.840 86.420 92.280 87.620 ;
        RECT 90.840 82.820 91.200 86.420 ;
        RECT 91.920 82.820 92.280 86.420 ;
        RECT 93.000 86.420 94.440 87.620 ;
        RECT 93.000 82.820 93.360 86.420 ;
        RECT 94.080 82.820 94.440 86.420 ;
        RECT 95.160 86.420 96.600 87.620 ;
        RECT 95.160 82.820 95.520 86.420 ;
        RECT 96.240 82.820 96.600 86.420 ;
        RECT 97.320 86.420 98.760 87.620 ;
        RECT 97.320 82.820 97.680 86.420 ;
        RECT 81.120 73.220 82.560 75.620 ;
        RECT 83.280 73.220 84.720 75.620 ;
        RECT 85.440 73.220 86.880 75.620 ;
        RECT 87.600 73.220 89.040 75.620 ;
        RECT 89.760 73.220 91.200 75.620 ;
        RECT 91.920 73.220 93.360 75.620 ;
        RECT 94.080 73.220 95.520 75.620 ;
        RECT 96.240 73.220 97.680 75.620 ;
        RECT 77.970 72.460 79.120 73.220 ;
        RECT 99.920 72.460 101.520 88.380 ;
        RECT 102.690 86.420 104.130 87.620 ;
        RECT 103.770 82.820 104.130 86.420 ;
        RECT 104.850 86.420 106.290 87.620 ;
        RECT 104.850 82.820 105.210 86.420 ;
        RECT 105.930 82.820 106.290 86.420 ;
        RECT 107.010 86.420 108.450 87.620 ;
        RECT 107.010 82.820 107.370 86.420 ;
        RECT 108.090 82.820 108.450 86.420 ;
        RECT 109.170 86.420 110.610 87.620 ;
        RECT 109.170 82.820 109.530 86.420 ;
        RECT 110.250 82.820 110.610 86.420 ;
        RECT 111.330 86.420 112.770 87.620 ;
        RECT 111.330 82.820 111.690 86.420 ;
        RECT 112.410 82.820 112.770 86.420 ;
        RECT 113.490 86.420 114.930 87.620 ;
        RECT 113.490 82.820 113.850 86.420 ;
        RECT 114.570 82.820 114.930 86.420 ;
        RECT 115.650 86.420 117.090 87.620 ;
        RECT 115.650 82.820 116.010 86.420 ;
        RECT 116.730 82.820 117.090 86.420 ;
        RECT 117.810 86.420 119.250 87.620 ;
        RECT 117.810 82.820 118.170 86.420 ;
        RECT 118.890 82.820 119.250 86.420 ;
        RECT 119.970 86.420 121.410 87.620 ;
        RECT 119.970 82.820 120.330 86.420 ;
        RECT 103.770 73.220 105.210 75.620 ;
        RECT 105.930 73.220 107.370 75.620 ;
        RECT 108.090 73.220 109.530 75.620 ;
        RECT 110.250 73.220 111.690 75.620 ;
        RECT 112.410 73.220 113.850 75.620 ;
        RECT 114.570 73.220 116.010 75.620 ;
        RECT 116.730 73.220 118.170 75.620 ;
        RECT 118.890 73.220 120.330 75.620 ;
        RECT 122.570 72.460 124.210 88.380 ;
        RECT 125.390 86.420 126.830 87.620 ;
        RECT 126.470 82.820 126.830 86.420 ;
        RECT 127.550 86.420 128.990 87.620 ;
        RECT 127.550 82.820 127.910 86.420 ;
        RECT 128.630 82.820 128.990 86.420 ;
        RECT 129.710 86.420 131.150 87.620 ;
        RECT 129.710 82.820 130.070 86.420 ;
        RECT 130.790 82.820 131.150 86.420 ;
        RECT 131.870 86.420 133.310 87.620 ;
        RECT 131.870 82.820 132.230 86.420 ;
        RECT 132.950 82.820 133.310 86.420 ;
        RECT 134.030 86.420 135.470 87.620 ;
        RECT 134.030 82.820 134.390 86.420 ;
        RECT 135.110 82.820 135.470 86.420 ;
        RECT 136.190 86.420 137.630 87.620 ;
        RECT 136.190 82.820 136.550 86.420 ;
        RECT 137.270 82.820 137.630 86.420 ;
        RECT 138.350 86.420 139.790 87.620 ;
        RECT 138.350 82.820 138.710 86.420 ;
        RECT 139.430 82.820 139.790 86.420 ;
        RECT 140.510 86.420 141.950 87.620 ;
        RECT 140.510 82.820 140.870 86.420 ;
        RECT 141.590 82.820 141.950 86.420 ;
        RECT 142.670 86.420 144.110 87.620 ;
        RECT 142.670 82.820 143.030 86.420 ;
        RECT 126.470 73.220 127.910 75.620 ;
        RECT 128.630 73.220 130.070 75.620 ;
        RECT 130.790 73.220 132.230 75.620 ;
        RECT 132.950 73.220 134.390 75.620 ;
        RECT 135.110 73.220 136.550 75.620 ;
        RECT 137.270 73.220 138.710 75.620 ;
        RECT 139.430 73.220 140.870 75.620 ;
        RECT 141.590 73.220 143.030 75.620 ;
        RECT 145.290 72.460 145.850 88.380 ;
        RECT 77.970 72.420 145.850 72.460 ;
        RECT 77.970 71.440 145.870 72.420 ;
        RECT 77.970 70.880 150.010 71.440 ;
        RECT 77.970 70.870 145.870 70.880 ;
        RECT 36.400 68.770 37.360 69.110 ;
        RECT 36.400 68.710 39.210 68.770 ;
        RECT 36.400 68.310 39.920 68.710 ;
        RECT 36.400 68.270 39.210 68.310 ;
        RECT 36.400 64.710 37.360 68.270 ;
        RECT 37.680 66.310 38.000 67.510 ;
        RECT 38.960 66.710 40.560 67.110 ;
        RECT 40.880 66.310 41.200 67.510 ;
        RECT 38.320 65.110 39.920 65.510 ;
        RECT 41.520 64.710 42.480 69.110 ;
        RECT 55.310 68.860 63.120 69.260 ;
        RECT 58.620 67.670 59.620 68.670 ;
        RECT 58.625 63.025 59.620 67.670 ;
        RECT 60.580 66.610 62.180 67.010 ;
        RECT 59.940 64.610 60.260 65.810 ;
        RECT 61.220 65.010 62.820 65.410 ;
        RECT 63.140 64.610 63.460 65.810 ;
        RECT 60.580 63.410 62.180 63.810 ;
        RECT 58.660 63.010 59.620 63.025 ;
        RECT 63.780 63.010 64.740 67.410 ;
        RECT 42.670 61.890 44.920 61.920 ;
        RECT 34.000 61.330 57.910 61.890 ;
        RECT 19.870 57.360 21.820 57.370 ;
        RECT 19.870 56.020 22.570 57.360 ;
        RECT 23.530 56.560 25.130 56.960 ;
        RECT 11.095 53.060 12.045 55.210 ;
        RECT 11.095 48.660 12.070 53.060 ;
        RECT 13.030 52.260 14.630 52.660 ;
        RECT 12.390 50.260 12.710 51.460 ;
        RECT 13.670 50.660 15.270 51.060 ;
        RECT 15.590 50.260 15.910 51.460 ;
        RECT 13.030 49.060 14.630 49.460 ;
        RECT 16.230 48.660 17.190 53.060 ;
        RECT 21.610 52.960 22.570 56.020 ;
        RECT 22.890 54.560 23.210 55.760 ;
        RECT 24.170 54.960 25.770 55.360 ;
        RECT 26.090 54.560 26.410 55.760 ;
        RECT 23.530 53.360 25.130 53.760 ;
        RECT 26.730 52.960 27.690 57.360 ;
        RECT 11.095 46.510 12.045 48.660 ;
        RECT 11.095 42.120 12.070 46.510 ;
        RECT 13.030 45.710 14.630 46.110 ;
        RECT 12.390 43.710 12.710 44.910 ;
        RECT 13.670 44.110 15.270 44.510 ;
        RECT 15.590 43.710 15.910 44.910 ;
        RECT 13.030 42.510 14.630 42.910 ;
        RECT 11.110 42.110 12.070 42.120 ;
        RECT 16.230 42.110 17.190 46.510 ;
        RECT 21.610 45.270 22.570 51.320 ;
        RECT 23.530 50.510 25.130 50.910 ;
        RECT 22.890 48.510 23.210 49.710 ;
        RECT 24.170 48.910 25.770 49.310 ;
        RECT 26.090 48.510 26.410 49.710 ;
        RECT 23.530 47.310 25.130 47.710 ;
        RECT 26.730 46.910 27.690 51.310 ;
        RECT 21.570 44.320 22.570 45.270 ;
        RECT 34.000 45.410 34.560 61.330 ;
        RECT 42.670 60.720 44.920 61.330 ;
        RECT 35.740 59.370 37.180 60.570 ;
        RECT 36.820 55.770 37.180 59.370 ;
        RECT 37.900 59.370 39.340 60.570 ;
        RECT 37.900 55.770 38.260 59.370 ;
        RECT 38.980 55.770 39.340 59.370 ;
        RECT 40.060 59.370 41.500 60.570 ;
        RECT 40.060 55.770 40.420 59.370 ;
        RECT 36.820 46.170 38.260 48.570 ;
        RECT 38.980 46.170 40.420 48.570 ;
        RECT 42.680 45.410 43.240 60.720 ;
        RECT 34.000 44.850 43.240 45.410 ;
        RECT 44.350 45.410 44.910 60.720 ;
        RECT 46.090 59.370 47.530 60.570 ;
        RECT 47.170 55.770 47.530 59.370 ;
        RECT 48.250 59.370 49.690 60.570 ;
        RECT 48.250 55.770 48.610 59.370 ;
        RECT 49.330 55.770 49.690 59.370 ;
        RECT 50.410 59.370 51.850 60.570 ;
        RECT 50.410 55.770 50.770 59.370 ;
        RECT 51.490 55.770 51.850 59.370 ;
        RECT 52.570 59.370 54.010 60.570 ;
        RECT 52.570 55.770 52.930 59.370 ;
        RECT 53.650 55.770 54.010 59.370 ;
        RECT 54.730 59.370 56.170 60.570 ;
        RECT 54.730 55.770 55.090 59.370 ;
        RECT 47.170 46.170 48.610 48.570 ;
        RECT 49.330 46.170 50.770 48.570 ;
        RECT 51.490 46.170 52.930 48.570 ;
        RECT 53.650 46.170 55.090 48.570 ;
        RECT 57.350 45.410 57.910 61.330 ;
        RECT 70.510 48.910 71.470 69.520 ;
        RECT 77.970 68.520 79.120 70.870 ;
        RECT 79.990 68.920 81.430 70.120 ;
        RECT 72.430 66.610 74.030 67.010 ;
        RECT 71.790 64.610 72.110 65.810 ;
        RECT 73.070 65.010 74.670 65.410 ;
        RECT 74.990 64.610 75.310 65.810 ;
        RECT 72.430 63.410 74.030 63.810 ;
        RECT 75.630 63.010 76.590 67.410 ;
        RECT 72.430 61.910 74.030 62.310 ;
        RECT 71.790 59.910 72.110 61.110 ;
        RECT 73.070 60.310 74.670 60.710 ;
        RECT 74.990 59.910 75.310 61.110 ;
        RECT 72.430 58.710 74.030 59.110 ;
        RECT 75.630 58.310 76.590 62.710 ;
        RECT 72.430 57.210 74.030 57.610 ;
        RECT 71.790 55.210 72.110 56.410 ;
        RECT 73.070 55.610 74.670 56.010 ;
        RECT 74.990 55.210 75.310 56.410 ;
        RECT 72.430 54.010 74.030 54.410 ;
        RECT 75.630 53.610 76.590 58.010 ;
        RECT 78.250 54.960 78.810 68.520 ;
        RECT 81.070 65.320 81.430 68.920 ;
        RECT 82.150 68.920 83.590 70.120 ;
        RECT 82.150 65.320 82.510 68.920 ;
        RECT 81.070 55.720 82.510 58.120 ;
        RECT 84.720 54.960 86.370 70.870 ;
        RECT 87.540 68.920 88.980 70.120 ;
        RECT 88.620 65.320 88.980 68.920 ;
        RECT 89.700 68.920 91.140 70.120 ;
        RECT 89.700 65.320 90.060 68.920 ;
        RECT 88.620 55.720 90.060 58.120 ;
        RECT 92.320 54.960 93.920 70.870 ;
        RECT 95.090 68.920 96.530 70.120 ;
        RECT 96.170 65.320 96.530 68.920 ;
        RECT 97.250 68.920 98.690 70.120 ;
        RECT 97.250 65.320 97.610 68.920 ;
        RECT 96.170 55.720 97.610 58.120 ;
        RECT 99.870 54.960 101.470 70.870 ;
        RECT 102.640 68.920 104.080 70.120 ;
        RECT 103.720 65.320 104.080 68.920 ;
        RECT 104.800 68.920 106.240 70.120 ;
        RECT 104.800 65.320 105.160 68.920 ;
        RECT 103.720 55.720 105.160 58.120 ;
        RECT 107.420 54.960 109.020 70.870 ;
        RECT 110.190 68.920 111.630 70.120 ;
        RECT 111.270 65.320 111.630 68.920 ;
        RECT 112.350 68.920 113.790 70.120 ;
        RECT 112.350 65.320 112.710 68.920 ;
        RECT 113.430 65.320 113.790 68.920 ;
        RECT 114.510 68.920 115.950 70.120 ;
        RECT 114.510 65.320 114.870 68.920 ;
        RECT 115.590 65.320 115.950 68.920 ;
        RECT 116.670 68.920 118.110 70.120 ;
        RECT 116.670 65.320 117.030 68.920 ;
        RECT 117.750 65.320 118.110 68.920 ;
        RECT 118.830 68.920 120.270 70.120 ;
        RECT 118.830 65.320 119.190 68.920 ;
        RECT 111.270 55.720 112.710 58.120 ;
        RECT 113.430 55.720 114.870 58.120 ;
        RECT 115.590 55.720 117.030 58.120 ;
        RECT 117.750 55.720 119.190 58.120 ;
        RECT 121.420 54.960 123.020 70.870 ;
        RECT 124.190 68.920 125.630 70.120 ;
        RECT 125.270 65.320 125.630 68.920 ;
        RECT 126.350 68.920 127.790 70.120 ;
        RECT 126.350 65.320 126.710 68.920 ;
        RECT 127.430 65.320 127.790 68.920 ;
        RECT 128.510 68.920 129.950 70.120 ;
        RECT 128.510 65.320 128.870 68.920 ;
        RECT 129.590 65.320 129.950 68.920 ;
        RECT 130.670 68.920 132.110 70.120 ;
        RECT 130.670 65.320 131.030 68.920 ;
        RECT 131.750 65.320 132.110 68.920 ;
        RECT 132.830 68.920 134.270 70.120 ;
        RECT 132.830 65.320 133.190 68.920 ;
        RECT 125.270 55.720 126.710 58.120 ;
        RECT 127.430 55.720 128.870 58.120 ;
        RECT 129.590 55.720 131.030 58.120 ;
        RECT 131.750 55.720 133.190 58.120 ;
        RECT 135.420 54.960 137.020 70.870 ;
        RECT 138.190 68.920 139.630 70.120 ;
        RECT 139.270 65.320 139.630 68.920 ;
        RECT 140.350 68.920 141.790 70.120 ;
        RECT 140.350 65.320 140.710 68.920 ;
        RECT 141.430 65.320 141.790 68.920 ;
        RECT 142.510 68.920 143.950 70.120 ;
        RECT 142.510 65.320 142.870 68.920 ;
        RECT 143.590 65.320 143.950 68.920 ;
        RECT 144.670 68.920 146.110 70.120 ;
        RECT 144.670 65.320 145.030 68.920 ;
        RECT 145.750 65.320 146.110 68.920 ;
        RECT 146.830 68.920 148.270 70.120 ;
        RECT 146.830 65.320 147.190 68.920 ;
        RECT 139.270 55.720 140.710 58.120 ;
        RECT 141.430 55.720 142.870 58.120 ;
        RECT 143.590 55.720 145.030 58.120 ;
        RECT 145.750 55.720 147.190 58.120 ;
        RECT 149.450 54.960 150.010 70.880 ;
        RECT 78.250 54.420 150.010 54.960 ;
        RECT 78.250 54.400 85.330 54.420 ;
        RECT 85.800 54.400 122.010 54.420 ;
        RECT 122.450 54.400 150.010 54.420 ;
        RECT 92.320 54.370 93.920 54.400 ;
        RECT 99.870 54.370 101.470 54.400 ;
        RECT 107.420 54.370 109.020 54.400 ;
        RECT 135.420 54.370 137.020 54.400 ;
        RECT 72.430 52.510 74.030 52.910 ;
        RECT 71.790 50.510 72.110 51.710 ;
        RECT 73.070 50.910 74.670 51.310 ;
        RECT 74.990 50.510 75.310 51.710 ;
        RECT 72.430 49.310 74.030 49.710 ;
        RECT 75.630 48.910 76.590 53.310 ;
        RECT 98.140 53.275 115.180 53.835 ;
        RECT 91.010 51.855 91.960 52.715 ;
        RECT 91.000 47.455 91.960 51.855 ;
        RECT 92.920 51.055 94.520 51.455 ;
        RECT 92.280 49.055 92.600 50.255 ;
        RECT 93.560 49.455 95.160 49.855 ;
        RECT 95.480 49.055 95.800 50.255 ;
        RECT 92.920 47.855 94.520 48.255 ;
        RECT 96.120 47.455 97.080 51.855 ;
        RECT 44.350 44.850 57.910 45.410 ;
        RECT 98.140 45.155 98.700 53.275 ;
        RECT 99.460 51.015 100.660 52.095 ;
        RECT 99.460 50.655 104.260 51.015 ;
        RECT 99.460 49.575 104.260 49.935 ;
        RECT 111.460 49.575 113.860 51.015 ;
        RECT 99.460 48.855 100.660 49.575 ;
        RECT 99.460 48.495 104.260 48.855 ;
        RECT 99.460 47.415 104.260 47.775 ;
        RECT 111.460 47.415 113.860 48.855 ;
        RECT 99.460 46.335 100.660 47.415 ;
        RECT 114.620 45.165 115.180 53.275 ;
        RECT 131.510 52.075 132.250 52.460 ;
        RECT 130.470 52.070 132.630 52.075 ;
        RECT 130.470 51.775 133.320 52.070 ;
        RECT 131.510 51.750 132.250 51.775 ;
        RECT 132.420 51.770 133.320 51.775 ;
        RECT 117.840 49.825 118.800 50.225 ;
        RECT 117.840 49.425 121.360 49.825 ;
        RECT 117.840 45.825 118.800 49.425 ;
        RECT 119.120 47.425 119.440 48.625 ;
        RECT 120.400 47.825 122.000 48.225 ;
        RECT 122.320 47.425 122.640 48.625 ;
        RECT 119.760 46.225 121.360 46.625 ;
        RECT 122.960 45.825 123.920 50.225 ;
        RECT 114.310 45.155 115.310 45.165 ;
        RECT 91.010 43.855 92.010 44.865 ;
        RECT 98.140 44.595 115.310 45.155 ;
        RECT 114.310 43.915 115.310 44.595 ;
        RECT 23.620 40.240 57.770 43.420 ;
        RECT 12.550 39.680 57.770 40.240 ;
        RECT 12.550 23.760 13.110 39.680 ;
        RECT 23.620 39.620 57.770 39.680 ;
        RECT 58.150 42.695 64.590 43.190 ;
        RECT 14.290 37.720 15.730 38.920 ;
        RECT 15.370 34.120 15.730 37.720 ;
        RECT 16.450 37.720 17.890 38.920 ;
        RECT 16.450 34.120 16.810 37.720 ;
        RECT 17.530 34.120 17.890 37.720 ;
        RECT 18.610 37.720 20.050 38.920 ;
        RECT 18.610 34.120 18.970 37.720 ;
        RECT 19.690 34.120 20.050 37.720 ;
        RECT 20.770 37.720 22.210 38.920 ;
        RECT 20.770 34.120 21.130 37.720 ;
        RECT 21.850 34.120 22.210 37.720 ;
        RECT 22.930 37.720 24.370 38.920 ;
        RECT 22.930 34.120 23.290 37.720 ;
        RECT 24.010 34.120 24.370 37.720 ;
        RECT 25.090 37.720 26.530 38.920 ;
        RECT 25.090 34.120 25.450 37.720 ;
        RECT 26.170 34.120 26.530 37.720 ;
        RECT 27.250 37.720 28.690 38.920 ;
        RECT 27.250 34.120 27.610 37.720 ;
        RECT 28.330 34.120 28.690 37.720 ;
        RECT 29.410 37.720 30.850 38.920 ;
        RECT 29.410 34.120 29.770 37.720 ;
        RECT 30.490 34.120 30.850 37.720 ;
        RECT 31.570 37.720 33.010 38.920 ;
        RECT 31.570 34.120 31.930 37.720 ;
        RECT 15.370 24.520 16.810 26.920 ;
        RECT 17.530 24.520 18.970 26.920 ;
        RECT 19.690 24.520 21.130 26.920 ;
        RECT 21.850 24.520 23.290 26.920 ;
        RECT 24.010 24.520 25.450 26.920 ;
        RECT 26.170 24.520 27.610 26.920 ;
        RECT 28.330 24.520 29.770 26.920 ;
        RECT 30.490 24.520 31.930 26.920 ;
        RECT 34.190 23.760 34.750 39.620 ;
        RECT 12.550 23.200 34.750 23.760 ;
        RECT 35.200 23.760 35.760 39.620 ;
        RECT 36.940 37.720 38.380 38.920 ;
        RECT 38.020 34.120 38.380 37.720 ;
        RECT 39.100 37.720 40.540 38.920 ;
        RECT 39.100 34.120 39.460 37.720 ;
        RECT 40.180 34.120 40.540 37.720 ;
        RECT 41.260 37.720 42.700 38.920 ;
        RECT 41.260 34.120 41.620 37.720 ;
        RECT 42.340 34.120 42.700 37.720 ;
        RECT 43.420 37.720 44.860 38.920 ;
        RECT 43.420 34.120 43.780 37.720 ;
        RECT 44.500 34.120 44.860 37.720 ;
        RECT 45.580 37.720 47.020 38.920 ;
        RECT 45.580 34.120 45.940 37.720 ;
        RECT 46.660 34.120 47.020 37.720 ;
        RECT 47.740 37.720 49.180 38.920 ;
        RECT 47.740 34.120 48.100 37.720 ;
        RECT 48.820 34.120 49.180 37.720 ;
        RECT 49.900 37.720 51.340 38.920 ;
        RECT 49.900 34.120 50.260 37.720 ;
        RECT 50.980 34.120 51.340 37.720 ;
        RECT 52.060 37.720 53.500 38.920 ;
        RECT 52.060 34.120 52.420 37.720 ;
        RECT 53.140 34.120 53.500 37.720 ;
        RECT 54.220 37.720 55.660 38.920 ;
        RECT 54.220 34.120 54.580 37.720 ;
        RECT 38.020 24.520 39.460 26.920 ;
        RECT 40.180 24.520 41.620 26.920 ;
        RECT 42.340 24.520 43.780 26.920 ;
        RECT 44.500 24.520 45.940 26.920 ;
        RECT 46.660 24.520 48.100 26.920 ;
        RECT 48.820 24.520 50.260 26.920 ;
        RECT 50.980 24.520 52.420 26.920 ;
        RECT 53.140 24.520 54.580 26.920 ;
        RECT 56.840 23.760 57.400 39.620 ;
        RECT 58.150 37.245 58.645 42.695 ;
        RECT 58.965 42.015 63.775 42.375 ;
        RECT 58.965 37.925 59.325 42.015 ;
        RECT 59.635 38.235 63.105 41.705 ;
        RECT 63.415 37.925 63.775 42.015 ;
        RECT 58.965 37.565 63.775 37.925 ;
        RECT 64.095 37.245 64.590 42.695 ;
        RECT 58.150 36.750 64.590 37.245 ;
        RECT 64.900 42.695 71.340 43.190 ;
        RECT 64.900 37.245 65.395 42.695 ;
        RECT 65.715 42.015 70.525 42.375 ;
        RECT 65.715 37.925 66.075 42.015 ;
        RECT 66.385 38.235 69.855 41.705 ;
        RECT 70.165 37.925 70.525 42.015 ;
        RECT 65.715 37.565 70.525 37.925 ;
        RECT 70.845 37.245 71.340 42.695 ;
        RECT 64.900 36.750 71.340 37.245 ;
        RECT 71.650 42.685 78.090 43.180 ;
        RECT 71.650 37.235 72.145 42.685 ;
        RECT 72.465 42.005 77.275 42.365 ;
        RECT 72.465 37.915 72.825 42.005 ;
        RECT 73.135 38.225 76.605 41.695 ;
        RECT 76.915 37.915 77.275 42.005 ;
        RECT 72.465 37.555 77.275 37.915 ;
        RECT 77.595 37.235 78.090 42.685 ;
        RECT 71.650 36.740 78.090 37.235 ;
        RECT 78.740 42.015 85.180 43.190 ;
        RECT 78.740 37.925 79.915 42.015 ;
        RECT 80.225 38.235 83.695 41.705 ;
        RECT 84.005 37.925 85.180 42.015 ;
        RECT 91.000 42.665 92.010 43.855 ;
        RECT 92.920 43.055 94.520 43.455 ;
        RECT 91.000 39.455 91.960 42.665 ;
        RECT 92.280 41.055 92.600 42.255 ;
        RECT 93.560 41.455 95.160 41.855 ;
        RECT 95.480 41.055 95.800 42.255 ;
        RECT 92.920 39.855 94.520 40.255 ;
        RECT 96.120 39.455 97.080 43.855 ;
        RECT 98.430 42.895 100.460 43.855 ;
        RECT 101.420 43.055 103.020 43.455 ;
        RECT 99.500 39.455 100.460 42.895 ;
        RECT 100.780 41.055 101.100 42.255 ;
        RECT 102.060 41.455 103.660 41.855 ;
        RECT 103.980 41.055 104.300 42.255 ;
        RECT 101.420 39.855 103.020 40.255 ;
        RECT 104.620 39.455 105.580 43.855 ;
        RECT 106.490 43.415 107.450 43.435 ;
        RECT 106.490 39.035 107.470 43.415 ;
        RECT 108.410 42.635 110.010 43.035 ;
        RECT 107.770 40.635 108.090 41.835 ;
        RECT 109.050 41.035 110.650 41.435 ;
        RECT 110.970 40.635 111.290 41.835 ;
        RECT 108.410 39.435 110.010 39.835 ;
        RECT 111.610 39.035 112.570 43.435 ;
        RECT 117.800 42.615 118.760 43.015 ;
        RECT 117.800 42.215 121.320 42.615 ;
        RECT 106.510 38.175 107.470 39.035 ;
        RECT 117.800 38.615 118.760 42.215 ;
        RECT 119.080 40.215 119.400 41.415 ;
        RECT 120.360 40.615 121.960 41.015 ;
        RECT 122.280 40.215 122.600 41.415 ;
        RECT 119.720 39.015 121.320 39.415 ;
        RECT 122.920 38.615 123.880 43.015 ;
        RECT 78.740 36.750 85.180 37.925 ;
        RECT 58.150 35.945 64.590 36.440 ;
        RECT 58.150 30.495 58.645 35.945 ;
        RECT 58.965 35.265 63.775 35.625 ;
        RECT 58.965 31.175 59.325 35.265 ;
        RECT 59.635 31.485 63.105 34.955 ;
        RECT 63.415 31.175 63.775 35.265 ;
        RECT 58.965 30.815 63.775 31.175 ;
        RECT 64.095 30.495 64.590 35.945 ;
        RECT 58.150 30.000 64.590 30.495 ;
        RECT 64.900 35.945 71.340 36.440 ;
        RECT 64.900 30.495 65.395 35.945 ;
        RECT 65.715 35.265 70.525 35.625 ;
        RECT 65.715 31.175 66.075 35.265 ;
        RECT 66.385 31.485 69.855 34.955 ;
        RECT 70.165 31.175 70.525 35.265 ;
        RECT 65.715 30.815 70.525 31.175 ;
        RECT 70.845 30.495 71.340 35.945 ;
        RECT 64.900 30.000 71.340 30.495 ;
        RECT 71.650 35.945 78.090 36.440 ;
        RECT 71.650 30.495 72.145 35.945 ;
        RECT 72.465 35.265 77.275 35.625 ;
        RECT 72.465 31.175 72.825 35.265 ;
        RECT 73.135 31.485 76.605 34.955 ;
        RECT 76.915 31.175 77.275 35.265 ;
        RECT 72.465 30.815 77.275 31.175 ;
        RECT 77.595 30.495 78.090 35.945 ;
        RECT 97.250 33.705 98.210 38.105 ;
        RECT 99.170 37.305 100.770 37.705 ;
        RECT 98.530 35.305 98.850 36.505 ;
        RECT 99.810 35.705 101.410 36.105 ;
        RECT 101.730 35.305 102.050 36.505 ;
        RECT 99.170 34.105 100.770 34.505 ;
        RECT 102.370 33.705 103.330 38.105 ;
        RECT 106.490 33.775 107.470 38.175 ;
        RECT 108.410 37.375 110.010 37.775 ;
        RECT 107.770 35.375 108.090 36.575 ;
        RECT 109.050 35.775 110.650 36.175 ;
        RECT 110.970 35.375 111.290 36.575 ;
        RECT 108.410 34.175 110.010 34.575 ;
        RECT 111.610 33.775 112.570 38.175 ;
        RECT 114.410 37.335 115.370 37.735 ;
        RECT 114.410 36.935 117.930 37.335 ;
        RECT 71.650 30.000 78.090 30.495 ;
        RECT 92.500 32.515 93.460 32.855 ;
        RECT 92.500 32.455 95.560 32.515 ;
        RECT 92.500 32.055 96.020 32.455 ;
        RECT 92.500 32.015 95.560 32.055 ;
        RECT 35.200 23.200 57.400 23.760 ;
        RECT 58.150 29.195 64.590 29.690 ;
        RECT 58.150 23.745 58.645 29.195 ;
        RECT 58.965 28.515 63.775 28.875 ;
        RECT 58.965 24.425 59.325 28.515 ;
        RECT 59.635 24.735 63.105 28.205 ;
        RECT 63.415 24.425 63.775 28.515 ;
        RECT 58.965 24.065 63.775 24.425 ;
        RECT 64.095 23.745 64.590 29.195 ;
        RECT 58.150 23.250 64.590 23.745 ;
        RECT 64.900 29.195 71.340 29.690 ;
        RECT 64.900 23.745 65.395 29.195 ;
        RECT 65.715 28.515 70.525 28.875 ;
        RECT 65.715 24.425 66.075 28.515 ;
        RECT 66.385 24.735 69.855 28.205 ;
        RECT 70.165 24.425 70.525 28.515 ;
        RECT 65.715 24.065 70.525 24.425 ;
        RECT 70.845 23.745 71.340 29.195 ;
        RECT 64.900 23.250 71.340 23.745 ;
        RECT 71.650 29.195 78.090 29.690 ;
        RECT 71.650 23.745 72.145 29.195 ;
        RECT 72.465 28.515 77.275 28.875 ;
        RECT 72.465 24.425 72.825 28.515 ;
        RECT 73.135 24.735 76.605 28.205 ;
        RECT 76.915 24.425 77.275 28.515 ;
        RECT 72.465 24.065 77.275 24.425 ;
        RECT 77.595 23.745 78.090 29.195 ;
        RECT 92.500 28.455 93.460 32.015 ;
        RECT 93.780 30.055 94.100 31.255 ;
        RECT 95.060 30.455 96.660 30.855 ;
        RECT 96.980 30.055 97.300 31.255 ;
        RECT 94.420 28.855 96.020 29.255 ;
        RECT 97.620 28.455 98.580 32.855 ;
        RECT 99.500 32.515 100.460 32.855 ;
        RECT 99.500 32.455 102.560 32.515 ;
        RECT 99.500 32.055 103.020 32.455 ;
        RECT 99.500 32.015 102.560 32.055 ;
        RECT 99.500 28.455 100.460 32.015 ;
        RECT 100.780 30.055 101.100 31.255 ;
        RECT 102.060 30.455 103.660 30.855 ;
        RECT 103.980 30.055 104.300 31.255 ;
        RECT 101.420 28.855 103.020 29.255 ;
        RECT 104.620 28.455 105.580 32.855 ;
        RECT 106.510 32.515 107.470 33.775 ;
        RECT 114.410 33.335 115.370 36.935 ;
        RECT 115.690 36.445 118.290 36.765 ;
        RECT 115.690 34.935 116.010 36.135 ;
        RECT 116.970 35.335 118.570 35.735 ;
        RECT 118.890 34.935 119.210 36.135 ;
        RECT 116.330 33.735 117.930 34.135 ;
        RECT 119.530 33.335 120.490 37.735 ;
        RECT 121.260 37.345 122.220 37.745 ;
        RECT 121.260 36.945 124.780 37.345 ;
        RECT 121.260 33.345 122.220 36.945 ;
        RECT 122.540 34.945 122.860 36.145 ;
        RECT 123.820 35.345 125.420 35.745 ;
        RECT 125.740 34.945 126.060 36.145 ;
        RECT 123.180 33.745 124.780 34.145 ;
        RECT 126.380 33.345 127.340 37.745 ;
        RECT 106.510 32.455 109.560 32.515 ;
        RECT 106.510 32.055 110.030 32.455 ;
        RECT 106.510 32.015 109.560 32.055 ;
        RECT 106.510 28.455 107.470 32.015 ;
        RECT 107.790 30.055 108.110 31.255 ;
        RECT 109.070 30.455 110.670 30.855 ;
        RECT 110.990 30.055 111.310 31.255 ;
        RECT 108.430 28.855 110.030 29.255 ;
        RECT 111.630 28.455 112.590 32.855 ;
        RECT 114.410 27.755 115.370 32.445 ;
        RECT 116.330 31.645 117.930 32.045 ;
        RECT 115.690 29.645 116.010 30.845 ;
        RECT 116.970 30.045 118.570 30.445 ;
        RECT 118.890 29.645 119.210 30.845 ;
        RECT 116.330 28.445 117.930 28.845 ;
        RECT 119.530 28.045 120.490 32.445 ;
        RECT 121.260 27.755 122.220 32.445 ;
        RECT 123.180 31.645 124.780 32.045 ;
        RECT 122.540 29.645 122.860 30.845 ;
        RECT 123.820 30.045 125.420 30.445 ;
        RECT 125.740 29.645 126.060 30.845 ;
        RECT 123.180 28.445 124.780 28.845 ;
        RECT 126.380 28.045 127.340 32.445 ;
        RECT 128.650 32.095 129.550 50.545 ;
        RECT 131.650 49.695 131.950 51.750 ;
        RECT 134.950 50.095 135.790 50.115 ;
        RECT 132.250 49.795 135.850 50.095 ;
        RECT 130.450 49.395 131.950 49.695 ;
        RECT 136.750 49.395 137.650 49.695 ;
        RECT 131.650 48.495 131.950 49.395 ;
        RECT 132.250 49.295 133.090 49.315 ;
        RECT 134.950 49.295 135.790 49.315 ;
        RECT 132.250 48.995 133.150 49.295 ;
        RECT 134.950 48.995 135.850 49.295 ;
        RECT 132.250 48.495 133.090 48.515 ;
        RECT 131.650 48.195 135.850 48.495 ;
        RECT 130.450 48.095 131.290 48.115 ;
        RECT 130.450 47.795 131.350 48.095 ;
        RECT 136.150 47.795 137.650 48.095 ;
        RECT 132.250 47.395 135.850 47.695 ;
        RECT 130.450 46.995 131.350 47.295 ;
        RECT 132.250 46.595 133.150 46.895 ;
        RECT 130.450 46.495 131.290 46.515 ;
        RECT 130.450 46.195 131.350 46.495 ;
        RECT 132.250 46.095 133.090 46.115 ;
        RECT 134.350 46.095 134.650 47.395 ;
        RECT 134.950 46.895 135.790 46.915 ;
        RECT 134.950 46.595 135.850 46.895 ;
        RECT 132.250 45.795 133.150 46.095 ;
        RECT 134.350 45.795 135.850 46.095 ;
        RECT 132.250 45.295 133.090 45.315 ;
        RECT 132.250 44.995 135.850 45.295 ;
        RECT 130.450 44.595 131.350 44.895 ;
        RECT 131.050 44.295 131.950 44.595 ;
        RECT 130.450 43.795 131.350 44.095 ;
        RECT 130.450 42.495 131.290 42.515 ;
        RECT 130.450 42.195 131.350 42.495 ;
        RECT 131.650 40.895 131.950 44.295 ;
        RECT 132.250 44.195 133.150 44.495 ;
        RECT 134.950 44.195 135.850 44.495 ;
        RECT 132.250 43.695 133.090 43.715 ;
        RECT 134.950 43.695 135.790 43.715 ;
        RECT 132.250 43.395 133.150 43.695 ;
        RECT 134.950 43.395 135.850 43.695 ;
        RECT 134.950 42.895 135.790 42.915 ;
        RECT 132.250 42.595 135.850 42.895 ;
        RECT 132.250 42.095 133.090 42.115 ;
        RECT 134.950 42.095 135.790 42.115 ;
        RECT 132.250 41.795 133.150 42.095 ;
        RECT 134.950 41.795 135.850 42.095 ;
        RECT 132.250 41.295 133.090 41.315 ;
        RECT 132.250 40.995 135.850 41.295 ;
        RECT 130.450 40.595 131.950 40.895 ;
        RECT 130.450 39.795 131.350 40.095 ;
        RECT 130.450 38.495 131.290 38.515 ;
        RECT 130.450 38.195 131.350 38.495 ;
        RECT 130.450 37.395 131.350 37.695 ;
        RECT 131.650 36.495 131.950 40.595 ;
        RECT 132.250 40.195 133.150 40.495 ;
        RECT 132.250 39.695 133.090 39.715 ;
        RECT 132.250 39.395 133.150 39.695 ;
        RECT 133.450 38.895 133.750 40.995 ;
        RECT 134.950 40.195 135.850 40.495 ;
        RECT 134.950 39.695 135.790 39.715 ;
        RECT 134.950 39.395 135.850 39.695 ;
        RECT 132.250 38.595 135.850 38.895 ;
        RECT 136.150 38.495 136.450 47.795 ;
        RECT 136.750 47.295 137.590 47.315 ;
        RECT 136.750 46.995 137.650 47.295 ;
        RECT 136.750 46.195 137.650 46.495 ;
        RECT 136.750 44.895 137.590 44.915 ;
        RECT 136.750 44.595 137.650 44.895 ;
        RECT 136.750 44.095 137.590 44.115 ;
        RECT 136.750 43.795 137.650 44.095 ;
        RECT 136.750 42.195 137.650 42.495 ;
        RECT 136.750 40.895 137.590 40.915 ;
        RECT 136.750 40.595 137.650 40.895 ;
        RECT 136.750 40.095 137.590 40.115 ;
        RECT 136.750 39.795 137.650 40.095 ;
        RECT 136.150 38.195 137.650 38.495 ;
        RECT 132.250 37.795 133.150 38.095 ;
        RECT 134.950 37.795 135.850 38.095 ;
        RECT 132.250 37.295 133.090 37.315 ;
        RECT 134.950 37.295 135.790 37.315 ;
        RECT 132.250 36.995 133.150 37.295 ;
        RECT 134.950 36.995 135.850 37.295 ;
        RECT 136.150 36.495 136.450 38.195 ;
        RECT 136.750 37.395 137.650 37.695 ;
        RECT 131.650 36.195 136.450 36.495 ;
        RECT 130.450 35.795 131.350 36.095 ;
        RECT 136.750 35.795 137.650 36.095 ;
        RECT 132.250 35.695 133.090 35.715 ;
        RECT 134.950 35.695 135.790 35.715 ;
        RECT 132.250 35.395 133.150 35.695 ;
        RECT 134.950 35.395 135.850 35.695 ;
        RECT 136.150 35.495 137.050 35.795 ;
        RECT 132.250 34.895 133.090 34.915 ;
        RECT 134.950 34.895 135.790 34.915 ;
        RECT 132.250 34.595 133.750 34.895 ;
        RECT 134.950 34.595 135.850 34.895 ;
        RECT 130.450 34.495 131.290 34.515 ;
        RECT 130.450 34.195 131.350 34.495 ;
        RECT 133.450 34.095 133.750 34.595 ;
        RECT 134.950 34.095 135.790 34.115 ;
        RECT 136.150 34.095 136.450 35.495 ;
        RECT 136.750 34.195 137.650 34.495 ;
        RECT 132.250 33.795 133.150 34.095 ;
        RECT 133.450 33.795 136.450 34.095 ;
        RECT 130.450 33.395 131.350 33.695 ;
        RECT 136.750 33.395 137.650 33.695 ;
        RECT 130.610 32.375 130.910 33.395 ;
        RECT 132.250 33.295 133.090 33.315 ;
        RECT 134.950 33.295 135.790 33.315 ;
        RECT 132.250 32.995 133.150 33.295 ;
        RECT 134.950 32.995 135.850 33.295 ;
        RECT 132.250 32.495 133.090 32.515 ;
        RECT 134.950 32.495 135.790 32.515 ;
        RECT 131.650 32.195 133.150 32.495 ;
        RECT 134.950 32.195 136.450 32.495 ;
        RECT 131.650 32.095 131.950 32.195 ;
        RECT 128.650 31.795 131.950 32.095 ;
        RECT 128.650 30.945 129.550 31.795 ;
        RECT 131.650 31.695 131.950 31.795 ;
        RECT 136.150 32.095 136.450 32.195 ;
        RECT 138.550 32.095 139.450 50.545 ;
        RECT 136.150 31.795 139.450 32.095 ;
        RECT 132.250 31.695 133.090 31.715 ;
        RECT 134.950 31.695 135.790 31.715 ;
        RECT 136.150 31.695 136.450 31.795 ;
        RECT 131.650 31.395 133.150 31.695 ;
        RECT 134.950 31.395 136.450 31.695 ;
        RECT 130.610 30.625 130.910 30.985 ;
        RECT 138.550 30.945 139.450 31.795 ;
        RECT 130.610 30.325 134.060 30.625 ;
        RECT 71.650 23.250 78.090 23.745 ;
        RECT 95.500 27.265 96.460 27.605 ;
        RECT 95.500 27.205 98.310 27.265 ;
        RECT 95.500 26.805 99.020 27.205 ;
        RECT 95.500 26.765 98.310 26.805 ;
        RECT 95.500 23.205 96.460 26.765 ;
        RECT 96.780 24.805 97.100 26.005 ;
        RECT 98.060 25.205 99.660 25.605 ;
        RECT 99.980 24.805 100.300 26.005 ;
        RECT 97.420 23.605 99.020 24.005 ;
        RECT 100.620 23.205 101.580 27.605 ;
        RECT 114.410 27.355 122.220 27.755 ;
        RECT 128.640 26.635 129.540 28.635 ;
        RECT 133.760 28.185 134.060 30.325 ;
        RECT 132.240 27.885 135.840 28.185 ;
        RECT 130.690 27.785 130.990 27.795 ;
        RECT 130.440 27.485 131.340 27.785 ;
        RECT 136.740 27.485 137.640 27.785 ;
        RECT 121.270 26.085 122.230 26.485 ;
        RECT 121.270 25.695 124.790 26.085 ;
        RECT 121.270 22.085 122.230 25.695 ;
        RECT 123.190 25.685 124.790 25.695 ;
        RECT 122.550 23.685 122.870 24.885 ;
        RECT 123.830 24.085 125.430 24.485 ;
        RECT 125.750 23.685 126.070 24.885 ;
        RECT 123.190 22.485 124.790 22.885 ;
        RECT 126.390 22.085 127.350 26.485 ;
        RECT 128.880 24.535 129.280 26.635 ;
        RECT 130.690 25.975 130.990 27.485 ;
        RECT 132.240 27.385 133.080 27.405 ;
        RECT 134.940 27.385 135.780 27.405 ;
        RECT 132.240 27.085 133.140 27.385 ;
        RECT 134.940 27.085 135.840 27.385 ;
        RECT 138.540 26.635 139.440 28.635 ;
        RECT 130.690 25.675 134.190 25.975 ;
        RECT 128.630 22.535 129.530 24.535 ;
        RECT 133.890 24.085 134.190 25.675 ;
        RECT 138.820 25.655 139.220 26.635 ;
        RECT 135.250 25.255 139.220 25.655 ;
        RECT 138.820 24.535 139.220 25.255 ;
        RECT 132.230 23.785 135.830 24.085 ;
        RECT 129.950 23.385 131.330 23.685 ;
        RECT 136.730 23.385 137.630 23.685 ;
        RECT 132.230 23.285 133.070 23.305 ;
        RECT 134.930 23.285 135.770 23.305 ;
        RECT 132.230 22.985 133.130 23.285 ;
        RECT 134.930 22.985 135.830 23.285 ;
        RECT 138.530 22.535 139.430 24.535 ;
        RECT 128.880 21.345 129.280 22.535 ;
        RECT 15.450 20.780 82.150 20.950 ;
        RECT 15.535 19.690 16.745 20.780 ;
        RECT 15.535 18.980 16.055 19.520 ;
        RECT 16.225 19.150 16.745 19.690 ;
        RECT 16.915 19.710 17.475 20.610 ;
        RECT 17.665 19.980 18.275 20.780 ;
        RECT 18.445 19.810 18.695 20.610 ;
        RECT 15.535 18.230 16.745 18.980 ;
        RECT 16.915 18.785 17.280 19.710 ;
        RECT 17.745 19.640 18.695 19.810 ;
        RECT 18.865 19.935 19.315 20.610 ;
        RECT 19.585 19.975 19.910 20.780 ;
        RECT 17.745 19.470 17.915 19.640 ;
        RECT 17.460 19.135 17.915 19.470 ;
        RECT 18.865 19.395 19.040 19.935 ;
        RECT 20.080 19.805 20.425 20.610 ;
        RECT 19.505 19.635 20.425 19.805 ;
        RECT 20.595 19.710 21.155 20.610 ;
        RECT 21.345 19.980 21.955 20.780 ;
        RECT 22.125 19.810 22.375 20.610 ;
        RECT 19.505 19.440 19.855 19.635 ;
        RECT 18.090 19.220 19.040 19.395 ;
        RECT 17.745 19.050 17.915 19.135 ;
        RECT 17.745 18.880 18.695 19.050 ;
        RECT 16.915 18.400 17.495 18.785 ;
        RECT 17.665 18.230 18.270 18.710 ;
        RECT 18.445 18.400 18.695 18.880 ;
        RECT 18.865 19.000 19.040 19.220 ;
        RECT 19.405 19.170 19.855 19.440 ;
        RECT 20.025 19.220 20.425 19.465 ;
        RECT 19.505 19.050 19.855 19.170 ;
        RECT 18.865 18.400 19.335 19.000 ;
        RECT 19.505 18.880 20.425 19.050 ;
        RECT 19.600 18.230 19.930 18.710 ;
        RECT 20.100 18.400 20.425 18.880 ;
        RECT 20.595 18.785 20.960 19.710 ;
        RECT 21.425 19.640 22.375 19.810 ;
        RECT 22.545 19.935 22.995 20.610 ;
        RECT 23.265 19.975 23.590 20.780 ;
        RECT 21.425 19.470 21.595 19.640 ;
        RECT 21.140 19.135 21.595 19.470 ;
        RECT 22.545 19.395 22.720 19.935 ;
        RECT 23.760 19.805 24.105 20.610 ;
        RECT 24.850 20.150 25.135 20.610 ;
        RECT 25.305 20.320 25.575 20.780 ;
        RECT 24.850 19.930 25.805 20.150 ;
        RECT 23.185 19.635 24.105 19.805 ;
        RECT 23.185 19.440 23.535 19.635 ;
        RECT 21.770 19.220 22.720 19.395 ;
        RECT 21.425 19.050 21.595 19.135 ;
        RECT 21.425 18.880 22.375 19.050 ;
        RECT 20.595 18.400 21.175 18.785 ;
        RECT 21.345 18.230 21.950 18.710 ;
        RECT 22.125 18.400 22.375 18.880 ;
        RECT 22.545 19.000 22.720 19.220 ;
        RECT 23.085 19.170 23.535 19.440 ;
        RECT 23.705 19.220 24.105 19.465 ;
        RECT 24.735 19.200 25.425 19.760 ;
        RECT 23.185 19.050 23.535 19.170 ;
        RECT 22.545 18.400 23.015 19.000 ;
        RECT 23.185 18.880 24.105 19.050 ;
        RECT 25.595 19.030 25.805 19.930 ;
        RECT 23.280 18.230 23.610 18.710 ;
        RECT 23.780 18.400 24.105 18.880 ;
        RECT 24.850 18.860 25.805 19.030 ;
        RECT 25.975 19.760 26.375 20.610 ;
        RECT 26.565 20.150 26.845 20.610 ;
        RECT 27.365 20.320 27.690 20.780 ;
        RECT 26.565 19.930 27.690 20.150 ;
        RECT 25.975 19.200 27.070 19.760 ;
        RECT 27.240 19.470 27.690 19.930 ;
        RECT 27.860 19.640 28.245 20.610 ;
        RECT 24.850 18.400 25.135 18.860 ;
        RECT 25.305 18.230 25.575 18.690 ;
        RECT 25.975 18.400 26.375 19.200 ;
        RECT 27.240 19.140 27.795 19.470 ;
        RECT 27.240 19.030 27.690 19.140 ;
        RECT 26.565 18.860 27.690 19.030 ;
        RECT 27.965 18.970 28.245 19.640 ;
        RECT 28.415 19.615 28.705 20.780 ;
        RECT 28.935 19.640 29.145 20.780 ;
        RECT 29.315 19.630 29.645 20.610 ;
        RECT 29.815 19.640 30.045 20.780 ;
        RECT 30.315 19.640 30.525 20.780 ;
        RECT 30.695 19.630 31.025 20.610 ;
        RECT 31.195 19.640 31.425 20.780 ;
        RECT 31.635 19.690 32.845 20.780 ;
        RECT 33.015 19.690 34.225 20.780 ;
        RECT 34.395 19.690 35.605 20.780 ;
        RECT 35.815 20.440 36.955 20.610 ;
        RECT 35.815 19.980 36.115 20.440 ;
        RECT 36.285 19.810 36.615 20.270 ;
        RECT 26.565 18.400 26.845 18.860 ;
        RECT 27.365 18.230 27.690 18.690 ;
        RECT 27.860 18.400 28.245 18.970 ;
        RECT 28.415 18.230 28.705 18.955 ;
        RECT 28.935 18.230 29.145 19.050 ;
        RECT 29.315 19.030 29.565 19.630 ;
        RECT 29.735 19.220 30.065 19.470 ;
        RECT 29.315 18.400 29.645 19.030 ;
        RECT 29.815 18.230 30.045 19.050 ;
        RECT 30.315 18.230 30.525 19.050 ;
        RECT 30.695 19.030 30.945 19.630 ;
        RECT 31.115 19.220 31.445 19.470 ;
        RECT 30.695 18.400 31.025 19.030 ;
        RECT 31.195 18.230 31.425 19.050 ;
        RECT 31.635 18.980 32.155 19.520 ;
        RECT 32.325 19.150 32.845 19.690 ;
        RECT 33.015 18.980 33.535 19.520 ;
        RECT 33.705 19.150 34.225 19.690 ;
        RECT 34.395 18.980 34.915 19.520 ;
        RECT 35.085 19.150 35.605 19.690 ;
        RECT 35.855 19.590 36.615 19.810 ;
        RECT 36.785 19.810 36.955 20.440 ;
        RECT 37.125 19.980 37.455 20.780 ;
        RECT 37.625 19.810 37.900 20.610 ;
        RECT 36.785 19.600 37.900 19.810 ;
        RECT 38.540 19.810 38.815 20.610 ;
        RECT 38.985 19.980 39.315 20.780 ;
        RECT 39.485 20.440 40.625 20.610 ;
        RECT 39.485 19.810 39.655 20.440 ;
        RECT 38.540 19.600 39.655 19.810 ;
        RECT 39.825 19.810 40.155 20.270 ;
        RECT 40.325 19.980 40.625 20.440 ;
        RECT 39.825 19.590 40.585 19.810 ;
        RECT 41.295 19.615 41.585 20.780 ;
        RECT 41.755 19.690 42.965 20.780 ;
        RECT 43.135 19.690 44.345 20.780 ;
        RECT 44.515 19.690 45.725 20.780 ;
        RECT 45.895 19.690 47.105 20.780 ;
        RECT 47.275 19.690 48.485 20.780 ;
        RECT 48.655 19.690 49.865 20.780 ;
        RECT 50.035 19.690 51.245 20.780 ;
        RECT 51.415 19.690 52.625 20.780 ;
        RECT 35.855 19.050 36.070 19.590 ;
        RECT 36.240 19.220 37.010 19.420 ;
        RECT 37.180 19.220 37.900 19.420 ;
        RECT 38.540 19.220 39.260 19.420 ;
        RECT 39.430 19.220 40.200 19.420 ;
        RECT 40.370 19.050 40.585 19.590 ;
        RECT 31.635 18.230 32.845 18.980 ;
        RECT 33.015 18.230 34.225 18.980 ;
        RECT 34.395 18.230 35.605 18.980 ;
        RECT 35.855 18.880 37.455 19.050 ;
        RECT 36.285 18.870 37.455 18.880 ;
        RECT 35.825 18.230 36.115 18.700 ;
        RECT 36.285 18.400 36.615 18.870 ;
        RECT 36.785 18.230 36.955 18.700 ;
        RECT 37.125 18.400 37.455 18.870 ;
        RECT 37.625 18.230 37.900 19.050 ;
        RECT 38.540 18.230 38.815 19.050 ;
        RECT 38.985 18.880 40.585 19.050 ;
        RECT 41.755 18.980 42.275 19.520 ;
        RECT 42.445 19.150 42.965 19.690 ;
        RECT 43.135 18.980 43.655 19.520 ;
        RECT 43.825 19.150 44.345 19.690 ;
        RECT 44.515 18.980 45.035 19.520 ;
        RECT 45.205 19.150 45.725 19.690 ;
        RECT 45.895 18.980 46.415 19.520 ;
        RECT 46.585 19.150 47.105 19.690 ;
        RECT 47.275 18.980 47.795 19.520 ;
        RECT 47.965 19.150 48.485 19.690 ;
        RECT 48.655 18.980 49.175 19.520 ;
        RECT 49.345 19.150 49.865 19.690 ;
        RECT 50.035 18.980 50.555 19.520 ;
        RECT 50.725 19.150 51.245 19.690 ;
        RECT 51.415 18.980 51.935 19.520 ;
        RECT 52.105 19.150 52.625 19.690 ;
        RECT 52.835 19.640 53.065 20.780 ;
        RECT 53.235 19.630 53.565 20.610 ;
        RECT 53.735 19.640 53.945 20.780 ;
        RECT 52.815 19.220 53.145 19.470 ;
        RECT 38.985 18.870 40.155 18.880 ;
        RECT 38.985 18.400 39.315 18.870 ;
        RECT 39.485 18.230 39.655 18.700 ;
        RECT 39.825 18.400 40.155 18.870 ;
        RECT 40.325 18.230 40.615 18.700 ;
        RECT 41.295 18.230 41.585 18.955 ;
        RECT 41.755 18.230 42.965 18.980 ;
        RECT 43.135 18.230 44.345 18.980 ;
        RECT 44.515 18.230 45.725 18.980 ;
        RECT 45.895 18.230 47.105 18.980 ;
        RECT 47.275 18.230 48.485 18.980 ;
        RECT 48.655 18.230 49.865 18.980 ;
        RECT 50.035 18.230 51.245 18.980 ;
        RECT 51.415 18.230 52.625 18.980 ;
        RECT 52.835 18.230 53.065 19.050 ;
        RECT 53.315 19.030 53.565 19.630 ;
        RECT 54.175 19.615 54.465 20.780 ;
        RECT 54.640 19.640 54.975 20.610 ;
        RECT 55.145 19.640 55.315 20.780 ;
        RECT 55.485 20.440 57.515 20.610 ;
        RECT 53.235 18.400 53.565 19.030 ;
        RECT 53.735 18.230 53.945 19.050 ;
        RECT 54.640 18.970 54.810 19.640 ;
        RECT 55.485 19.470 55.655 20.440 ;
        RECT 54.980 19.140 55.235 19.470 ;
        RECT 55.460 19.140 55.655 19.470 ;
        RECT 55.825 20.100 56.950 20.270 ;
        RECT 55.065 18.970 55.235 19.140 ;
        RECT 55.825 18.970 55.995 20.100 ;
        RECT 54.175 18.230 54.465 18.955 ;
        RECT 54.640 18.400 54.895 18.970 ;
        RECT 55.065 18.800 55.995 18.970 ;
        RECT 56.165 19.760 57.175 19.930 ;
        RECT 56.165 18.960 56.335 19.760 ;
        RECT 56.540 19.080 56.815 19.560 ;
        RECT 56.535 18.910 56.815 19.080 ;
        RECT 55.820 18.765 55.995 18.800 ;
        RECT 55.065 18.230 55.395 18.630 ;
        RECT 55.820 18.400 56.350 18.765 ;
        RECT 56.540 18.400 56.815 18.910 ;
        RECT 56.985 18.400 57.175 19.760 ;
        RECT 57.345 19.775 57.515 20.440 ;
        RECT 57.685 20.020 57.855 20.780 ;
        RECT 58.090 20.020 58.605 20.430 ;
        RECT 57.345 19.585 58.095 19.775 ;
        RECT 58.265 19.210 58.605 20.020 ;
        RECT 57.375 19.040 58.605 19.210 ;
        RECT 58.775 19.640 59.160 20.610 ;
        RECT 59.330 20.320 59.655 20.780 ;
        RECT 60.175 20.150 60.455 20.610 ;
        RECT 59.330 19.930 60.455 20.150 ;
        RECT 57.355 18.230 57.865 18.765 ;
        RECT 58.085 18.435 58.330 19.040 ;
        RECT 58.775 18.970 59.055 19.640 ;
        RECT 59.330 19.470 59.780 19.930 ;
        RECT 60.645 19.760 61.045 20.610 ;
        RECT 61.445 20.320 61.715 20.780 ;
        RECT 61.885 20.150 62.170 20.610 ;
        RECT 59.225 19.140 59.780 19.470 ;
        RECT 59.950 19.200 61.045 19.760 ;
        RECT 59.330 19.030 59.780 19.140 ;
        RECT 58.775 18.400 59.160 18.970 ;
        RECT 59.330 18.860 60.455 19.030 ;
        RECT 59.330 18.230 59.655 18.690 ;
        RECT 60.175 18.400 60.455 18.860 ;
        RECT 60.645 18.400 61.045 19.200 ;
        RECT 61.215 19.930 62.170 20.150 ;
        RECT 61.215 19.030 61.425 19.930 ;
        RECT 62.455 19.805 62.800 20.610 ;
        RECT 62.970 19.975 63.295 20.780 ;
        RECT 63.565 19.935 64.015 20.610 ;
        RECT 61.595 19.200 62.285 19.760 ;
        RECT 62.455 19.635 63.375 19.805 ;
        RECT 62.455 19.220 62.855 19.465 ;
        RECT 63.025 19.440 63.375 19.635 ;
        RECT 63.025 19.170 63.475 19.440 ;
        RECT 63.840 19.395 64.015 19.935 ;
        RECT 64.185 19.810 64.435 20.610 ;
        RECT 64.605 19.980 65.215 20.780 ;
        RECT 64.185 19.640 65.135 19.810 ;
        RECT 65.405 19.710 65.965 20.610 ;
        RECT 64.965 19.470 65.135 19.640 ;
        RECT 63.840 19.220 64.790 19.395 ;
        RECT 63.025 19.050 63.375 19.170 ;
        RECT 61.215 18.860 62.170 19.030 ;
        RECT 61.445 18.230 61.715 18.690 ;
        RECT 61.885 18.400 62.170 18.860 ;
        RECT 62.455 18.880 63.375 19.050 ;
        RECT 63.840 19.000 64.015 19.220 ;
        RECT 64.965 19.135 65.420 19.470 ;
        RECT 64.965 19.050 65.135 19.135 ;
        RECT 62.455 18.400 62.780 18.880 ;
        RECT 62.950 18.230 63.280 18.710 ;
        RECT 63.545 18.400 64.015 19.000 ;
        RECT 64.185 18.880 65.135 19.050 ;
        RECT 64.185 18.400 64.435 18.880 ;
        RECT 65.600 18.785 65.965 19.710 ;
        RECT 67.055 19.615 67.345 20.780 ;
        RECT 67.515 19.710 68.075 20.610 ;
        RECT 68.265 19.980 68.875 20.780 ;
        RECT 69.045 19.810 69.295 20.610 ;
        RECT 64.610 18.230 65.215 18.710 ;
        RECT 65.385 18.400 65.965 18.785 ;
        RECT 67.055 18.230 67.345 18.955 ;
        RECT 67.515 18.785 67.880 19.710 ;
        RECT 68.345 19.640 69.295 19.810 ;
        RECT 69.465 19.935 69.915 20.610 ;
        RECT 70.185 19.975 70.510 20.780 ;
        RECT 68.345 19.470 68.515 19.640 ;
        RECT 68.060 19.135 68.515 19.470 ;
        RECT 69.465 19.395 69.640 19.935 ;
        RECT 70.680 19.805 71.025 20.610 ;
        RECT 70.105 19.635 71.025 19.805 ;
        RECT 71.195 19.640 71.580 20.610 ;
        RECT 71.750 20.320 72.075 20.780 ;
        RECT 72.595 20.150 72.875 20.610 ;
        RECT 71.750 19.930 72.875 20.150 ;
        RECT 70.105 19.440 70.455 19.635 ;
        RECT 68.690 19.220 69.640 19.395 ;
        RECT 68.345 19.050 68.515 19.135 ;
        RECT 68.345 18.880 69.295 19.050 ;
        RECT 67.515 18.400 68.095 18.785 ;
        RECT 68.265 18.230 68.870 18.710 ;
        RECT 69.045 18.400 69.295 18.880 ;
        RECT 69.465 19.000 69.640 19.220 ;
        RECT 70.005 19.170 70.455 19.440 ;
        RECT 70.625 19.220 71.025 19.465 ;
        RECT 70.105 19.050 70.455 19.170 ;
        RECT 69.465 18.400 69.935 19.000 ;
        RECT 70.105 18.880 71.025 19.050 ;
        RECT 70.200 18.230 70.530 18.710 ;
        RECT 70.700 18.400 71.025 18.880 ;
        RECT 71.195 18.970 71.475 19.640 ;
        RECT 71.750 19.470 72.200 19.930 ;
        RECT 73.065 19.760 73.465 20.610 ;
        RECT 73.865 20.320 74.135 20.780 ;
        RECT 74.305 20.150 74.590 20.610 ;
        RECT 71.645 19.140 72.200 19.470 ;
        RECT 72.370 19.200 73.465 19.760 ;
        RECT 71.750 19.030 72.200 19.140 ;
        RECT 71.195 18.400 71.580 18.970 ;
        RECT 71.750 18.860 72.875 19.030 ;
        RECT 71.750 18.230 72.075 18.690 ;
        RECT 72.595 18.400 72.875 18.860 ;
        RECT 73.065 18.400 73.465 19.200 ;
        RECT 73.635 19.930 74.590 20.150 ;
        RECT 73.635 19.030 73.845 19.930 ;
        RECT 74.015 19.200 74.705 19.760 ;
        RECT 74.875 19.690 76.085 20.780 ;
        RECT 76.255 19.690 77.465 20.780 ;
        RECT 77.635 19.690 78.845 20.780 ;
        RECT 73.635 18.860 74.590 19.030 ;
        RECT 73.865 18.230 74.135 18.690 ;
        RECT 74.305 18.400 74.590 18.860 ;
        RECT 74.875 18.980 75.395 19.520 ;
        RECT 75.565 19.150 76.085 19.690 ;
        RECT 76.255 18.980 76.775 19.520 ;
        RECT 76.945 19.150 77.465 19.690 ;
        RECT 77.635 18.980 78.155 19.520 ;
        RECT 78.325 19.150 78.845 19.690 ;
        RECT 79.935 19.615 80.225 20.780 ;
        RECT 80.855 19.690 82.065 20.780 ;
        RECT 80.855 19.150 81.375 19.690 ;
        RECT 81.545 18.980 82.065 19.520 ;
        RECT 74.875 18.230 76.085 18.980 ;
        RECT 76.255 18.230 77.465 18.980 ;
        RECT 77.635 18.230 78.845 18.980 ;
        RECT 79.935 18.230 80.225 18.955 ;
        RECT 80.855 18.230 82.065 18.980 ;
        RECT 15.450 18.060 82.150 18.230 ;
        RECT 15.535 17.310 16.745 18.060 ;
        RECT 17.840 17.510 18.095 17.800 ;
        RECT 18.265 17.680 18.595 18.060 ;
        RECT 17.840 17.340 18.590 17.510 ;
        RECT 15.535 16.770 16.055 17.310 ;
        RECT 16.225 16.600 16.745 17.140 ;
        RECT 15.535 15.510 16.745 16.600 ;
        RECT 17.840 16.520 18.190 17.170 ;
        RECT 18.360 16.350 18.590 17.340 ;
        RECT 17.840 16.180 18.590 16.350 ;
        RECT 17.840 15.680 18.095 16.180 ;
        RECT 18.265 15.510 18.595 16.010 ;
        RECT 18.765 15.680 18.935 17.800 ;
        RECT 19.295 17.700 19.625 18.060 ;
        RECT 19.795 17.670 20.290 17.840 ;
        RECT 20.495 17.670 21.350 17.840 ;
        RECT 19.165 16.480 19.625 17.530 ;
        RECT 19.105 15.695 19.430 16.480 ;
        RECT 19.795 16.310 19.965 17.670 ;
        RECT 20.135 16.760 20.485 17.380 ;
        RECT 20.655 17.160 21.010 17.380 ;
        RECT 20.655 16.570 20.825 17.160 ;
        RECT 21.180 16.960 21.350 17.670 ;
        RECT 22.225 17.600 22.555 18.060 ;
        RECT 22.765 17.700 23.115 17.870 ;
        RECT 21.555 17.130 22.345 17.380 ;
        RECT 22.765 17.310 23.025 17.700 ;
        RECT 23.335 17.610 24.285 17.890 ;
        RECT 24.455 17.620 24.645 18.060 ;
        RECT 24.815 17.680 25.885 17.850 ;
        RECT 22.515 16.960 22.685 17.140 ;
        RECT 19.795 16.140 20.190 16.310 ;
        RECT 20.360 16.180 20.825 16.570 ;
        RECT 20.995 16.790 22.685 16.960 ;
        RECT 20.020 16.010 20.190 16.140 ;
        RECT 20.995 16.010 21.165 16.790 ;
        RECT 22.855 16.620 23.025 17.310 ;
        RECT 21.525 16.450 23.025 16.620 ;
        RECT 23.215 16.650 23.425 17.440 ;
        RECT 23.595 16.820 23.945 17.440 ;
        RECT 24.115 16.830 24.285 17.610 ;
        RECT 24.815 17.450 24.985 17.680 ;
        RECT 24.455 17.280 24.985 17.450 ;
        RECT 24.455 17.000 24.675 17.280 ;
        RECT 25.155 17.110 25.395 17.510 ;
        RECT 24.115 16.660 24.520 16.830 ;
        RECT 24.855 16.740 25.395 17.110 ;
        RECT 25.565 17.325 25.885 17.680 ;
        RECT 26.130 17.600 26.435 18.060 ;
        RECT 26.605 17.350 26.855 17.880 ;
        RECT 25.565 17.150 25.890 17.325 ;
        RECT 25.565 16.850 26.480 17.150 ;
        RECT 25.740 16.820 26.480 16.850 ;
        RECT 23.215 16.490 23.890 16.650 ;
        RECT 24.350 16.570 24.520 16.660 ;
        RECT 23.215 16.480 24.180 16.490 ;
        RECT 22.855 16.310 23.025 16.450 ;
        RECT 19.600 15.510 19.850 15.970 ;
        RECT 20.020 15.680 20.270 16.010 ;
        RECT 20.485 15.680 21.165 16.010 ;
        RECT 21.335 16.110 22.410 16.280 ;
        RECT 22.855 16.140 23.415 16.310 ;
        RECT 23.720 16.190 24.180 16.480 ;
        RECT 24.350 16.400 25.570 16.570 ;
        RECT 21.335 15.770 21.505 16.110 ;
        RECT 21.740 15.510 22.070 15.940 ;
        RECT 22.240 15.770 22.410 16.110 ;
        RECT 22.705 15.510 23.075 15.970 ;
        RECT 23.245 15.680 23.415 16.140 ;
        RECT 24.350 16.020 24.520 16.400 ;
        RECT 25.740 16.230 25.910 16.820 ;
        RECT 26.650 16.700 26.855 17.350 ;
        RECT 27.025 17.305 27.275 18.060 ;
        RECT 27.555 17.240 27.765 18.060 ;
        RECT 27.935 17.260 28.265 17.890 ;
        RECT 23.650 15.680 24.520 16.020 ;
        RECT 25.110 16.060 25.910 16.230 ;
        RECT 24.690 15.510 24.940 15.970 ;
        RECT 25.110 15.770 25.280 16.060 ;
        RECT 25.460 15.510 25.790 15.890 ;
        RECT 26.130 15.510 26.435 16.650 ;
        RECT 26.605 15.820 26.855 16.700 ;
        RECT 27.935 16.660 28.185 17.260 ;
        RECT 28.435 17.240 28.665 18.060 ;
        RECT 28.935 17.240 29.145 18.060 ;
        RECT 29.315 17.260 29.645 17.890 ;
        RECT 28.355 16.820 28.685 17.070 ;
        RECT 29.315 16.660 29.565 17.260 ;
        RECT 29.815 17.240 30.045 18.060 ;
        RECT 30.955 17.590 31.125 18.060 ;
        RECT 31.795 17.590 31.965 18.060 ;
        RECT 32.230 17.670 33.460 17.890 ;
        RECT 31.295 17.420 31.625 17.500 ;
        RECT 32.655 17.420 32.985 17.500 ;
        RECT 30.715 17.240 32.985 17.420 ;
        RECT 33.210 17.420 33.460 17.670 ;
        RECT 33.630 17.590 33.800 18.060 ;
        RECT 33.970 17.420 34.300 17.890 ;
        RECT 34.570 17.590 34.740 18.060 ;
        RECT 33.210 17.240 34.300 17.420 ;
        RECT 34.910 17.420 35.240 17.890 ;
        RECT 35.410 17.590 35.580 18.060 ;
        RECT 35.750 17.420 36.080 17.890 ;
        RECT 36.250 17.590 36.420 18.060 ;
        RECT 34.910 17.240 36.490 17.420 ;
        RECT 36.710 17.280 37.005 18.060 ;
        RECT 37.565 17.530 37.910 17.890 ;
        RECT 38.370 17.700 38.700 18.060 ;
        RECT 38.905 17.530 39.225 17.890 ;
        RECT 37.565 17.360 39.225 17.530 ;
        RECT 29.735 16.820 30.065 17.070 ;
        RECT 30.715 16.730 31.125 17.240 ;
        RECT 31.335 16.900 31.995 17.070 ;
        RECT 27.025 15.510 27.275 16.650 ;
        RECT 27.555 15.510 27.765 16.650 ;
        RECT 27.935 15.680 28.265 16.660 ;
        RECT 28.435 15.510 28.665 16.650 ;
        RECT 28.935 15.510 29.145 16.650 ;
        RECT 29.315 15.680 29.645 16.660 ;
        RECT 29.815 15.510 30.045 16.650 ;
        RECT 30.715 16.520 31.585 16.730 ;
        RECT 31.825 16.700 31.995 16.900 ;
        RECT 32.520 16.870 33.190 17.070 ;
        RECT 33.380 16.870 34.900 17.070 ;
        RECT 35.070 16.870 35.565 17.070 ;
        RECT 35.735 16.870 36.065 17.070 ;
        RECT 34.730 16.700 34.900 16.870 ;
        RECT 35.735 16.700 35.905 16.870 ;
        RECT 31.825 16.530 34.560 16.700 ;
        RECT 34.730 16.530 35.905 16.700 ;
        RECT 30.915 15.850 31.165 16.350 ;
        RECT 31.335 16.020 31.585 16.520 ;
        RECT 34.390 16.360 34.560 16.530 ;
        RECT 36.320 16.360 36.490 17.240 ;
        RECT 36.755 16.650 37.255 17.110 ;
        RECT 37.425 16.820 38.035 17.150 ;
        RECT 38.215 16.900 38.545 17.070 ;
        RECT 38.215 16.650 38.540 16.900 ;
        RECT 36.755 16.470 38.540 16.650 ;
        RECT 31.755 16.190 34.220 16.360 ;
        RECT 34.390 16.190 36.490 16.360 ;
        RECT 31.755 15.850 32.525 16.190 ;
        RECT 30.915 15.680 32.525 15.850 ;
        RECT 32.695 15.510 33.000 16.010 ;
        RECT 33.170 15.680 33.420 16.190 ;
        RECT 34.010 16.020 34.220 16.190 ;
        RECT 34.950 16.020 35.200 16.190 ;
        RECT 36.720 16.120 38.755 16.290 ;
        RECT 36.720 16.040 37.830 16.120 ;
        RECT 33.590 15.510 33.840 16.010 ;
        RECT 34.010 15.680 34.325 16.020 ;
        RECT 35.375 16.010 35.545 16.020 ;
        RECT 36.295 16.010 36.465 16.020 ;
        RECT 34.530 15.850 34.780 16.010 ;
        RECT 35.370 15.850 35.620 16.010 ;
        RECT 34.530 15.680 35.620 15.850 ;
        RECT 35.790 15.510 36.040 16.010 ;
        RECT 36.210 15.680 36.490 16.010 ;
        RECT 36.720 15.680 36.980 16.040 ;
        RECT 37.150 15.510 37.480 15.870 ;
        RECT 37.660 15.680 37.830 16.040 ;
        RECT 38.085 15.510 38.255 15.950 ;
        RECT 38.425 15.860 38.755 16.120 ;
        RECT 38.925 16.030 39.225 17.360 ;
        RECT 39.405 17.320 39.735 18.060 ;
        RECT 39.915 17.310 41.125 18.060 ;
        RECT 41.295 17.335 41.585 18.060 ;
        RECT 41.755 17.310 42.965 18.060 ;
        RECT 43.135 17.310 44.345 18.060 ;
        RECT 44.515 17.310 45.725 18.060 ;
        RECT 45.895 17.310 47.105 18.060 ;
        RECT 47.275 17.310 48.485 18.060 ;
        RECT 48.655 17.310 49.865 18.060 ;
        RECT 50.040 17.510 50.295 17.800 ;
        RECT 50.465 17.680 50.795 18.060 ;
        RECT 50.040 17.340 50.790 17.510 ;
        RECT 39.410 16.520 39.685 17.150 ;
        RECT 39.915 16.770 40.435 17.310 ;
        RECT 40.605 16.600 41.125 17.140 ;
        RECT 41.755 16.770 42.275 17.310 ;
        RECT 39.395 15.860 39.700 16.350 ;
        RECT 38.425 15.680 39.700 15.860 ;
        RECT 39.915 15.510 41.125 16.600 ;
        RECT 41.295 15.510 41.585 16.675 ;
        RECT 42.445 16.600 42.965 17.140 ;
        RECT 43.135 16.770 43.655 17.310 ;
        RECT 43.825 16.600 44.345 17.140 ;
        RECT 44.515 16.770 45.035 17.310 ;
        RECT 45.205 16.600 45.725 17.140 ;
        RECT 45.895 16.770 46.415 17.310 ;
        RECT 46.585 16.600 47.105 17.140 ;
        RECT 47.275 16.770 47.795 17.310 ;
        RECT 47.965 16.600 48.485 17.140 ;
        RECT 48.655 16.770 49.175 17.310 ;
        RECT 49.345 16.600 49.865 17.140 ;
        RECT 41.755 15.510 42.965 16.600 ;
        RECT 43.135 15.510 44.345 16.600 ;
        RECT 44.515 15.510 45.725 16.600 ;
        RECT 45.895 15.510 47.105 16.600 ;
        RECT 47.275 15.510 48.485 16.600 ;
        RECT 48.655 15.510 49.865 16.600 ;
        RECT 50.040 16.520 50.390 17.170 ;
        RECT 50.560 16.350 50.790 17.340 ;
        RECT 50.040 16.180 50.790 16.350 ;
        RECT 50.040 15.680 50.295 16.180 ;
        RECT 50.465 15.510 50.795 16.010 ;
        RECT 50.965 15.680 51.135 17.800 ;
        RECT 51.495 17.700 51.825 18.060 ;
        RECT 51.995 17.670 52.490 17.840 ;
        RECT 52.695 17.670 53.550 17.840 ;
        RECT 51.365 16.480 51.825 17.530 ;
        RECT 51.305 15.695 51.630 16.480 ;
        RECT 51.995 16.310 52.165 17.670 ;
        RECT 52.335 16.760 52.685 17.380 ;
        RECT 52.855 17.160 53.210 17.380 ;
        RECT 52.855 16.570 53.025 17.160 ;
        RECT 53.380 16.960 53.550 17.670 ;
        RECT 54.425 17.600 54.755 18.060 ;
        RECT 54.965 17.700 55.315 17.870 ;
        RECT 53.755 17.130 54.545 17.380 ;
        RECT 54.965 17.310 55.225 17.700 ;
        RECT 55.535 17.610 56.485 17.890 ;
        RECT 56.655 17.620 56.845 18.060 ;
        RECT 57.015 17.680 58.085 17.850 ;
        RECT 54.715 16.960 54.885 17.140 ;
        RECT 51.995 16.140 52.390 16.310 ;
        RECT 52.560 16.180 53.025 16.570 ;
        RECT 53.195 16.790 54.885 16.960 ;
        RECT 52.220 16.010 52.390 16.140 ;
        RECT 53.195 16.010 53.365 16.790 ;
        RECT 55.055 16.620 55.225 17.310 ;
        RECT 53.725 16.450 55.225 16.620 ;
        RECT 55.415 16.650 55.625 17.440 ;
        RECT 55.795 16.820 56.145 17.440 ;
        RECT 56.315 16.830 56.485 17.610 ;
        RECT 57.015 17.450 57.185 17.680 ;
        RECT 56.655 17.280 57.185 17.450 ;
        RECT 56.655 17.000 56.875 17.280 ;
        RECT 57.355 17.110 57.595 17.510 ;
        RECT 56.315 16.660 56.720 16.830 ;
        RECT 57.055 16.740 57.595 17.110 ;
        RECT 57.765 17.325 58.085 17.680 ;
        RECT 58.330 17.600 58.635 18.060 ;
        RECT 58.805 17.350 59.055 17.880 ;
        RECT 57.765 17.150 58.090 17.325 ;
        RECT 57.765 16.850 58.680 17.150 ;
        RECT 57.940 16.820 58.680 16.850 ;
        RECT 55.415 16.490 56.090 16.650 ;
        RECT 56.550 16.570 56.720 16.660 ;
        RECT 55.415 16.480 56.380 16.490 ;
        RECT 55.055 16.310 55.225 16.450 ;
        RECT 51.800 15.510 52.050 15.970 ;
        RECT 52.220 15.680 52.470 16.010 ;
        RECT 52.685 15.680 53.365 16.010 ;
        RECT 53.535 16.110 54.610 16.280 ;
        RECT 55.055 16.140 55.615 16.310 ;
        RECT 55.920 16.190 56.380 16.480 ;
        RECT 56.550 16.400 57.770 16.570 ;
        RECT 53.535 15.770 53.705 16.110 ;
        RECT 53.940 15.510 54.270 15.940 ;
        RECT 54.440 15.770 54.610 16.110 ;
        RECT 54.905 15.510 55.275 15.970 ;
        RECT 55.445 15.680 55.615 16.140 ;
        RECT 56.550 16.020 56.720 16.400 ;
        RECT 57.940 16.230 58.110 16.820 ;
        RECT 58.850 16.700 59.055 17.350 ;
        RECT 59.225 17.305 59.475 18.060 ;
        RECT 59.700 17.240 59.975 18.060 ;
        RECT 60.145 17.420 60.475 17.890 ;
        RECT 60.645 17.590 60.815 18.060 ;
        RECT 60.985 17.420 61.315 17.890 ;
        RECT 61.485 17.590 61.775 18.060 ;
        RECT 60.145 17.410 61.315 17.420 ;
        RECT 60.145 17.240 61.745 17.410 ;
        RECT 63.190 17.250 63.435 17.855 ;
        RECT 63.655 17.525 64.165 18.060 ;
        RECT 59.700 16.870 60.420 17.070 ;
        RECT 60.590 16.870 61.360 17.070 ;
        RECT 61.530 16.700 61.745 17.240 ;
        RECT 55.850 15.680 56.720 16.020 ;
        RECT 57.310 16.060 58.110 16.230 ;
        RECT 56.890 15.510 57.140 15.970 ;
        RECT 57.310 15.770 57.480 16.060 ;
        RECT 57.660 15.510 57.990 15.890 ;
        RECT 58.330 15.510 58.635 16.650 ;
        RECT 58.805 15.820 59.055 16.700 ;
        RECT 59.225 15.510 59.475 16.650 ;
        RECT 59.700 16.480 60.815 16.690 ;
        RECT 59.700 15.680 59.975 16.480 ;
        RECT 60.145 15.510 60.475 16.310 ;
        RECT 60.645 15.850 60.815 16.480 ;
        RECT 60.985 16.480 61.745 16.700 ;
        RECT 62.915 17.080 64.145 17.250 ;
        RECT 60.985 16.020 61.315 16.480 ;
        RECT 61.485 15.850 61.785 16.310 ;
        RECT 62.915 16.270 63.255 17.080 ;
        RECT 63.425 16.515 64.175 16.705 ;
        RECT 62.915 15.860 63.430 16.270 ;
        RECT 60.645 15.680 61.785 15.850 ;
        RECT 63.665 15.510 63.835 16.270 ;
        RECT 64.005 15.850 64.175 16.515 ;
        RECT 64.345 16.530 64.535 17.890 ;
        RECT 64.705 17.720 64.980 17.890 ;
        RECT 64.705 17.550 64.985 17.720 ;
        RECT 64.705 16.730 64.980 17.550 ;
        RECT 65.170 17.525 65.700 17.890 ;
        RECT 66.125 17.660 66.455 18.060 ;
        RECT 65.525 17.490 65.700 17.525 ;
        RECT 65.185 16.530 65.355 17.330 ;
        RECT 64.345 16.360 65.355 16.530 ;
        RECT 65.525 17.320 66.455 17.490 ;
        RECT 66.625 17.320 66.880 17.890 ;
        RECT 67.055 17.335 67.345 18.060 ;
        RECT 67.520 17.510 67.775 17.800 ;
        RECT 67.945 17.680 68.275 18.060 ;
        RECT 67.520 17.340 68.270 17.510 ;
        RECT 65.525 16.190 65.695 17.320 ;
        RECT 66.285 17.150 66.455 17.320 ;
        RECT 64.570 16.020 65.695 16.190 ;
        RECT 65.865 16.820 66.060 17.150 ;
        RECT 66.285 16.820 66.540 17.150 ;
        RECT 65.865 15.850 66.035 16.820 ;
        RECT 66.710 16.650 66.880 17.320 ;
        RECT 64.005 15.680 66.035 15.850 ;
        RECT 66.205 15.510 66.375 16.650 ;
        RECT 66.545 15.680 66.880 16.650 ;
        RECT 67.055 15.510 67.345 16.675 ;
        RECT 67.520 16.520 67.870 17.170 ;
        RECT 68.040 16.350 68.270 17.340 ;
        RECT 67.520 16.180 68.270 16.350 ;
        RECT 67.520 15.680 67.775 16.180 ;
        RECT 67.945 15.510 68.275 16.010 ;
        RECT 68.445 15.680 68.615 17.800 ;
        RECT 68.975 17.700 69.305 18.060 ;
        RECT 69.475 17.670 69.970 17.840 ;
        RECT 70.175 17.670 71.030 17.840 ;
        RECT 68.845 16.480 69.305 17.530 ;
        RECT 68.785 15.695 69.110 16.480 ;
        RECT 69.475 16.310 69.645 17.670 ;
        RECT 69.815 16.760 70.165 17.380 ;
        RECT 70.335 17.160 70.690 17.380 ;
        RECT 70.335 16.570 70.505 17.160 ;
        RECT 70.860 16.960 71.030 17.670 ;
        RECT 71.905 17.600 72.235 18.060 ;
        RECT 72.445 17.700 72.795 17.870 ;
        RECT 71.235 17.130 72.025 17.380 ;
        RECT 72.445 17.310 72.705 17.700 ;
        RECT 73.015 17.610 73.965 17.890 ;
        RECT 74.135 17.620 74.325 18.060 ;
        RECT 74.495 17.680 75.565 17.850 ;
        RECT 72.195 16.960 72.365 17.140 ;
        RECT 69.475 16.140 69.870 16.310 ;
        RECT 70.040 16.180 70.505 16.570 ;
        RECT 70.675 16.790 72.365 16.960 ;
        RECT 69.700 16.010 69.870 16.140 ;
        RECT 70.675 16.010 70.845 16.790 ;
        RECT 72.535 16.620 72.705 17.310 ;
        RECT 71.205 16.450 72.705 16.620 ;
        RECT 72.895 16.650 73.105 17.440 ;
        RECT 73.275 16.820 73.625 17.440 ;
        RECT 73.795 16.830 73.965 17.610 ;
        RECT 74.495 17.450 74.665 17.680 ;
        RECT 74.135 17.280 74.665 17.450 ;
        RECT 74.135 17.000 74.355 17.280 ;
        RECT 74.835 17.110 75.075 17.510 ;
        RECT 73.795 16.660 74.200 16.830 ;
        RECT 74.535 16.740 75.075 17.110 ;
        RECT 75.245 17.325 75.565 17.680 ;
        RECT 75.810 17.600 76.115 18.060 ;
        RECT 76.285 17.350 76.535 17.880 ;
        RECT 75.245 17.150 75.570 17.325 ;
        RECT 75.245 16.850 76.160 17.150 ;
        RECT 75.420 16.820 76.160 16.850 ;
        RECT 72.895 16.490 73.570 16.650 ;
        RECT 74.030 16.570 74.200 16.660 ;
        RECT 72.895 16.480 73.860 16.490 ;
        RECT 72.535 16.310 72.705 16.450 ;
        RECT 69.280 15.510 69.530 15.970 ;
        RECT 69.700 15.680 69.950 16.010 ;
        RECT 70.165 15.680 70.845 16.010 ;
        RECT 71.015 16.110 72.090 16.280 ;
        RECT 72.535 16.140 73.095 16.310 ;
        RECT 73.400 16.190 73.860 16.480 ;
        RECT 74.030 16.400 75.250 16.570 ;
        RECT 71.015 15.770 71.185 16.110 ;
        RECT 71.420 15.510 71.750 15.940 ;
        RECT 71.920 15.770 72.090 16.110 ;
        RECT 72.385 15.510 72.755 15.970 ;
        RECT 72.925 15.680 73.095 16.140 ;
        RECT 74.030 16.020 74.200 16.400 ;
        RECT 75.420 16.230 75.590 16.820 ;
        RECT 76.330 16.700 76.535 17.350 ;
        RECT 76.705 17.305 76.955 18.060 ;
        RECT 77.175 17.310 78.385 18.060 ;
        RECT 78.555 17.310 79.765 18.060 ;
        RECT 80.855 17.310 82.065 18.060 ;
        RECT 77.175 16.770 77.695 17.310 ;
        RECT 73.330 15.680 74.200 16.020 ;
        RECT 74.790 16.060 75.590 16.230 ;
        RECT 74.370 15.510 74.620 15.970 ;
        RECT 74.790 15.770 74.960 16.060 ;
        RECT 75.140 15.510 75.470 15.890 ;
        RECT 75.810 15.510 76.115 16.650 ;
        RECT 76.285 15.820 76.535 16.700 ;
        RECT 76.705 15.510 76.955 16.650 ;
        RECT 77.865 16.600 78.385 17.140 ;
        RECT 78.555 16.770 79.075 17.310 ;
        RECT 79.245 16.600 79.765 17.140 ;
        RECT 77.175 15.510 78.385 16.600 ;
        RECT 78.555 15.510 79.765 16.600 ;
        RECT 80.855 16.600 81.375 17.140 ;
        RECT 81.545 16.770 82.065 17.310 ;
        RECT 87.970 17.235 88.930 17.635 ;
        RECT 87.970 16.845 91.490 17.235 ;
        RECT 80.855 15.510 82.065 16.600 ;
        RECT 15.450 15.340 82.150 15.510 ;
        RECT 15.535 14.250 16.745 15.340 ;
        RECT 16.915 14.250 18.125 15.340 ;
        RECT 15.535 13.540 16.055 14.080 ;
        RECT 16.225 13.710 16.745 14.250 ;
        RECT 16.915 13.540 17.435 14.080 ;
        RECT 17.605 13.710 18.125 14.250 ;
        RECT 18.805 14.200 19.055 15.340 ;
        RECT 19.225 14.150 19.475 15.030 ;
        RECT 19.645 14.200 19.950 15.340 ;
        RECT 20.290 14.960 20.620 15.340 ;
        RECT 20.800 14.790 20.970 15.080 ;
        RECT 21.140 14.880 21.390 15.340 ;
        RECT 20.170 14.620 20.970 14.790 ;
        RECT 21.560 14.830 22.430 15.170 ;
        RECT 15.535 12.790 16.745 13.540 ;
        RECT 16.915 12.790 18.125 13.540 ;
        RECT 18.805 12.790 19.055 13.545 ;
        RECT 19.225 13.500 19.430 14.150 ;
        RECT 20.170 14.030 20.340 14.620 ;
        RECT 21.560 14.450 21.730 14.830 ;
        RECT 22.665 14.710 22.835 15.170 ;
        RECT 23.005 14.880 23.375 15.340 ;
        RECT 23.670 14.740 23.840 15.080 ;
        RECT 24.010 14.910 24.340 15.340 ;
        RECT 24.575 14.740 24.745 15.080 ;
        RECT 20.510 14.280 21.730 14.450 ;
        RECT 21.900 14.370 22.360 14.660 ;
        RECT 22.665 14.540 23.225 14.710 ;
        RECT 23.670 14.570 24.745 14.740 ;
        RECT 24.915 14.840 25.595 15.170 ;
        RECT 25.810 14.840 26.060 15.170 ;
        RECT 26.230 14.880 26.480 15.340 ;
        RECT 23.055 14.400 23.225 14.540 ;
        RECT 21.900 14.360 22.865 14.370 ;
        RECT 21.560 14.190 21.730 14.280 ;
        RECT 22.190 14.200 22.865 14.360 ;
        RECT 19.600 14.000 20.340 14.030 ;
        RECT 19.600 13.700 20.515 14.000 ;
        RECT 20.190 13.525 20.515 13.700 ;
        RECT 19.225 12.970 19.475 13.500 ;
        RECT 19.645 12.790 19.950 13.250 ;
        RECT 20.195 13.170 20.515 13.525 ;
        RECT 20.685 13.740 21.225 14.110 ;
        RECT 21.560 14.020 21.965 14.190 ;
        RECT 20.685 13.340 20.925 13.740 ;
        RECT 21.405 13.570 21.625 13.850 ;
        RECT 21.095 13.400 21.625 13.570 ;
        RECT 21.095 13.170 21.265 13.400 ;
        RECT 21.795 13.240 21.965 14.020 ;
        RECT 22.135 13.410 22.485 14.030 ;
        RECT 22.655 13.410 22.865 14.200 ;
        RECT 23.055 14.230 24.555 14.400 ;
        RECT 23.055 13.540 23.225 14.230 ;
        RECT 24.915 14.060 25.085 14.840 ;
        RECT 25.890 14.710 26.060 14.840 ;
        RECT 23.395 13.890 25.085 14.060 ;
        RECT 25.255 14.280 25.720 14.670 ;
        RECT 25.890 14.540 26.285 14.710 ;
        RECT 23.395 13.710 23.565 13.890 ;
        RECT 20.195 13.000 21.265 13.170 ;
        RECT 21.435 12.790 21.625 13.230 ;
        RECT 21.795 12.960 22.745 13.240 ;
        RECT 23.055 13.150 23.315 13.540 ;
        RECT 23.735 13.470 24.525 13.720 ;
        RECT 22.965 12.980 23.315 13.150 ;
        RECT 23.525 12.790 23.855 13.250 ;
        RECT 24.730 13.180 24.900 13.890 ;
        RECT 25.255 13.690 25.425 14.280 ;
        RECT 25.070 13.470 25.425 13.690 ;
        RECT 25.595 13.470 25.945 14.090 ;
        RECT 26.115 13.180 26.285 14.540 ;
        RECT 26.650 14.370 26.975 15.155 ;
        RECT 26.455 13.320 26.915 14.370 ;
        RECT 24.730 13.010 25.585 13.180 ;
        RECT 25.790 13.010 26.285 13.180 ;
        RECT 26.455 12.790 26.785 13.150 ;
        RECT 27.145 13.050 27.315 15.170 ;
        RECT 27.485 14.840 27.815 15.340 ;
        RECT 27.985 14.670 28.240 15.170 ;
        RECT 27.490 14.500 28.240 14.670 ;
        RECT 27.490 13.510 27.720 14.500 ;
        RECT 27.890 13.680 28.240 14.330 ;
        RECT 28.415 14.175 28.705 15.340 ;
        RECT 28.880 14.200 29.215 15.170 ;
        RECT 29.385 14.200 29.555 15.340 ;
        RECT 29.725 15.000 31.755 15.170 ;
        RECT 28.880 13.530 29.050 14.200 ;
        RECT 29.725 14.030 29.895 15.000 ;
        RECT 29.220 13.700 29.475 14.030 ;
        RECT 29.700 13.700 29.895 14.030 ;
        RECT 30.065 14.660 31.190 14.830 ;
        RECT 29.305 13.530 29.475 13.700 ;
        RECT 30.065 13.530 30.235 14.660 ;
        RECT 27.490 13.340 28.240 13.510 ;
        RECT 27.485 12.790 27.815 13.170 ;
        RECT 27.985 13.050 28.240 13.340 ;
        RECT 28.415 12.790 28.705 13.515 ;
        RECT 28.880 12.960 29.135 13.530 ;
        RECT 29.305 13.360 30.235 13.530 ;
        RECT 30.405 14.320 31.415 14.490 ;
        RECT 30.405 13.520 30.575 14.320 ;
        RECT 30.780 13.980 31.055 14.120 ;
        RECT 30.775 13.810 31.055 13.980 ;
        RECT 30.060 13.325 30.235 13.360 ;
        RECT 29.305 12.790 29.635 13.190 ;
        RECT 30.060 12.960 30.590 13.325 ;
        RECT 30.780 12.960 31.055 13.810 ;
        RECT 31.225 12.960 31.415 14.320 ;
        RECT 31.585 14.335 31.755 15.000 ;
        RECT 31.925 14.580 32.095 15.340 ;
        RECT 32.330 14.580 32.845 14.990 ;
        RECT 31.585 14.145 32.335 14.335 ;
        RECT 32.505 13.770 32.845 14.580 ;
        RECT 33.015 14.250 34.225 15.340 ;
        RECT 34.400 14.670 34.655 15.170 ;
        RECT 34.825 14.840 35.155 15.340 ;
        RECT 34.400 14.500 35.150 14.670 ;
        RECT 31.615 13.600 32.845 13.770 ;
        RECT 31.595 12.790 32.105 13.325 ;
        RECT 32.325 12.995 32.570 13.600 ;
        RECT 33.015 13.540 33.535 14.080 ;
        RECT 33.705 13.710 34.225 14.250 ;
        RECT 34.400 13.680 34.750 14.330 ;
        RECT 33.015 12.790 34.225 13.540 ;
        RECT 34.920 13.510 35.150 14.500 ;
        RECT 34.400 13.340 35.150 13.510 ;
        RECT 34.400 13.050 34.655 13.340 ;
        RECT 34.825 12.790 35.155 13.170 ;
        RECT 35.325 13.050 35.495 15.170 ;
        RECT 35.665 14.370 35.990 15.155 ;
        RECT 36.160 14.880 36.410 15.340 ;
        RECT 36.580 14.840 36.830 15.170 ;
        RECT 37.045 14.840 37.725 15.170 ;
        RECT 36.580 14.710 36.750 14.840 ;
        RECT 36.355 14.540 36.750 14.710 ;
        RECT 35.725 13.320 36.185 14.370 ;
        RECT 36.355 13.180 36.525 14.540 ;
        RECT 36.920 14.280 37.385 14.670 ;
        RECT 36.695 13.470 37.045 14.090 ;
        RECT 37.215 13.690 37.385 14.280 ;
        RECT 37.555 14.060 37.725 14.840 ;
        RECT 37.895 14.740 38.065 15.080 ;
        RECT 38.300 14.910 38.630 15.340 ;
        RECT 38.800 14.740 38.970 15.080 ;
        RECT 39.265 14.880 39.635 15.340 ;
        RECT 37.895 14.570 38.970 14.740 ;
        RECT 39.805 14.710 39.975 15.170 ;
        RECT 40.210 14.830 41.080 15.170 ;
        RECT 41.250 14.880 41.500 15.340 ;
        RECT 39.415 14.540 39.975 14.710 ;
        RECT 39.415 14.400 39.585 14.540 ;
        RECT 38.085 14.230 39.585 14.400 ;
        RECT 40.280 14.370 40.740 14.660 ;
        RECT 37.555 13.890 39.245 14.060 ;
        RECT 37.215 13.470 37.570 13.690 ;
        RECT 37.740 13.180 37.910 13.890 ;
        RECT 38.115 13.470 38.905 13.720 ;
        RECT 39.075 13.710 39.245 13.890 ;
        RECT 39.415 13.540 39.585 14.230 ;
        RECT 35.855 12.790 36.185 13.150 ;
        RECT 36.355 13.010 36.850 13.180 ;
        RECT 37.055 13.010 37.910 13.180 ;
        RECT 38.785 12.790 39.115 13.250 ;
        RECT 39.325 13.150 39.585 13.540 ;
        RECT 39.775 14.360 40.740 14.370 ;
        RECT 40.910 14.450 41.080 14.830 ;
        RECT 41.670 14.790 41.840 15.080 ;
        RECT 42.020 14.960 42.350 15.340 ;
        RECT 41.670 14.620 42.470 14.790 ;
        RECT 39.775 14.200 40.450 14.360 ;
        RECT 40.910 14.280 42.130 14.450 ;
        RECT 39.775 13.410 39.985 14.200 ;
        RECT 40.910 14.190 41.080 14.280 ;
        RECT 40.155 13.410 40.505 14.030 ;
        RECT 40.675 14.020 41.080 14.190 ;
        RECT 40.675 13.240 40.845 14.020 ;
        RECT 41.015 13.570 41.235 13.850 ;
        RECT 41.415 13.740 41.955 14.110 ;
        RECT 42.300 14.030 42.470 14.620 ;
        RECT 42.690 14.200 42.995 15.340 ;
        RECT 43.165 14.150 43.415 15.030 ;
        RECT 43.585 14.200 43.835 15.340 ;
        RECT 44.095 15.000 45.235 15.170 ;
        RECT 44.095 14.540 44.395 15.000 ;
        RECT 44.565 14.370 44.895 14.830 ;
        RECT 42.300 14.000 43.040 14.030 ;
        RECT 41.015 13.400 41.545 13.570 ;
        RECT 39.325 12.980 39.675 13.150 ;
        RECT 39.895 12.960 40.845 13.240 ;
        RECT 41.015 12.790 41.205 13.230 ;
        RECT 41.375 13.170 41.545 13.400 ;
        RECT 41.715 13.340 41.955 13.740 ;
        RECT 42.125 13.700 43.040 14.000 ;
        RECT 42.125 13.525 42.450 13.700 ;
        RECT 42.125 13.170 42.445 13.525 ;
        RECT 43.210 13.500 43.415 14.150 ;
        RECT 44.135 14.150 44.895 14.370 ;
        RECT 45.065 14.370 45.235 15.000 ;
        RECT 45.405 14.540 45.735 15.340 ;
        RECT 45.905 14.370 46.180 15.170 ;
        RECT 45.065 14.160 46.180 14.370 ;
        RECT 46.355 14.250 47.565 15.340 ;
        RECT 44.135 13.610 44.350 14.150 ;
        RECT 44.520 13.780 45.290 13.980 ;
        RECT 45.460 13.780 46.180 13.980 ;
        RECT 41.375 13.000 42.445 13.170 ;
        RECT 42.690 12.790 42.995 13.250 ;
        RECT 43.165 12.970 43.415 13.500 ;
        RECT 43.585 12.790 43.835 13.545 ;
        RECT 44.135 13.440 45.735 13.610 ;
        RECT 44.565 13.430 45.735 13.440 ;
        RECT 44.105 12.790 44.395 13.260 ;
        RECT 44.565 12.960 44.895 13.430 ;
        RECT 45.065 12.790 45.235 13.260 ;
        RECT 45.405 12.960 45.735 13.430 ;
        RECT 45.905 12.790 46.180 13.610 ;
        RECT 46.355 13.540 46.875 14.080 ;
        RECT 47.045 13.710 47.565 14.250 ;
        RECT 47.740 14.370 48.015 15.170 ;
        RECT 48.185 14.540 48.515 15.340 ;
        RECT 48.685 15.000 49.825 15.170 ;
        RECT 48.685 14.370 48.855 15.000 ;
        RECT 47.740 14.160 48.855 14.370 ;
        RECT 49.025 14.370 49.355 14.830 ;
        RECT 49.525 14.540 49.825 15.000 ;
        RECT 49.025 14.150 49.785 14.370 ;
        RECT 47.740 13.780 48.460 13.980 ;
        RECT 48.630 13.780 49.400 13.980 ;
        RECT 49.570 13.640 49.785 14.150 ;
        RECT 50.060 14.115 50.315 15.340 ;
        RECT 50.485 14.500 50.740 15.170 ;
        RECT 50.910 14.940 51.240 15.340 ;
        RECT 52.110 14.940 52.515 15.340 ;
        RECT 52.785 14.760 53.135 15.130 ;
        RECT 51.050 14.590 53.135 14.760 ;
        RECT 49.570 13.610 49.805 13.640 ;
        RECT 46.355 12.790 47.565 13.540 ;
        RECT 47.740 12.790 48.015 13.610 ;
        RECT 48.185 13.470 49.805 13.610 ;
        RECT 48.185 13.440 49.785 13.470 ;
        RECT 48.185 13.430 49.355 13.440 ;
        RECT 48.185 12.960 48.515 13.430 ;
        RECT 48.685 12.790 48.855 13.260 ;
        RECT 49.025 12.960 49.355 13.430 ;
        RECT 49.525 12.790 49.815 13.260 ;
        RECT 50.060 12.790 50.315 13.615 ;
        RECT 50.485 13.530 50.655 14.500 ;
        RECT 51.050 14.320 51.220 14.590 ;
        RECT 50.825 14.150 51.220 14.320 ;
        RECT 51.390 14.200 52.410 14.420 ;
        RECT 50.825 13.700 50.995 14.150 ;
        RECT 52.145 14.060 52.410 14.200 ;
        RECT 52.580 14.200 53.135 14.590 ;
        RECT 53.305 14.660 53.475 15.130 ;
        RECT 53.305 14.490 53.485 14.660 ;
        RECT 53.680 14.520 53.995 15.340 ;
        RECT 51.165 13.780 51.635 13.980 ;
        RECT 51.805 13.610 51.975 13.805 ;
        RECT 50.485 12.960 50.820 13.530 ;
        RECT 51.465 13.475 51.975 13.610 ;
        RECT 51.015 12.790 51.185 13.455 ;
        RECT 51.465 13.440 51.970 13.475 ;
        RECT 51.465 13.085 51.685 13.440 ;
        RECT 52.145 13.270 52.315 14.060 ;
        RECT 52.580 13.950 52.750 14.200 ;
        RECT 53.305 14.030 53.475 14.490 ;
        RECT 52.560 13.780 52.750 13.950 ;
        RECT 52.920 13.780 53.475 14.030 ;
        RECT 53.650 13.780 53.995 14.350 ;
        RECT 54.175 14.175 54.465 15.340 ;
        RECT 55.095 14.200 55.385 15.340 ;
        RECT 55.555 14.620 56.005 15.170 ;
        RECT 56.195 14.620 56.525 15.340 ;
        RECT 52.560 13.395 52.730 13.780 ;
        RECT 51.855 13.100 52.315 13.270 ;
        RECT 52.485 13.025 52.730 13.395 ;
        RECT 52.905 13.430 53.995 13.610 ;
        RECT 52.905 13.025 53.135 13.430 ;
        RECT 53.325 12.790 53.495 13.260 ;
        RECT 53.665 13.025 53.995 13.430 ;
        RECT 54.175 12.790 54.465 13.515 ;
        RECT 55.095 12.790 55.385 13.590 ;
        RECT 55.555 13.250 55.805 14.620 ;
        RECT 56.735 14.450 57.035 15.000 ;
        RECT 57.205 14.670 57.485 15.340 ;
        RECT 58.320 14.670 58.575 15.170 ;
        RECT 58.745 14.840 59.075 15.340 ;
        RECT 58.320 14.500 59.070 14.670 ;
        RECT 56.095 14.280 57.035 14.450 ;
        RECT 56.095 14.030 56.265 14.280 ;
        RECT 57.370 14.030 57.685 14.470 ;
        RECT 55.975 13.700 56.265 14.030 ;
        RECT 56.435 13.780 56.765 14.030 ;
        RECT 56.995 13.780 57.685 14.030 ;
        RECT 56.095 13.610 56.265 13.700 ;
        RECT 58.320 13.680 58.670 14.330 ;
        RECT 56.095 13.420 57.485 13.610 ;
        RECT 58.840 13.510 59.070 14.500 ;
        RECT 55.555 12.960 56.105 13.250 ;
        RECT 56.275 12.790 56.525 13.250 ;
        RECT 57.155 13.060 57.485 13.420 ;
        RECT 58.320 13.340 59.070 13.510 ;
        RECT 58.320 13.050 58.575 13.340 ;
        RECT 58.745 12.790 59.075 13.170 ;
        RECT 59.245 13.050 59.415 15.170 ;
        RECT 59.585 14.370 59.910 15.155 ;
        RECT 60.080 14.880 60.330 15.340 ;
        RECT 60.500 14.840 60.750 15.170 ;
        RECT 60.965 14.840 61.645 15.170 ;
        RECT 60.500 14.710 60.670 14.840 ;
        RECT 60.275 14.540 60.670 14.710 ;
        RECT 59.645 13.320 60.105 14.370 ;
        RECT 60.275 13.180 60.445 14.540 ;
        RECT 60.840 14.280 61.305 14.670 ;
        RECT 60.615 13.470 60.965 14.090 ;
        RECT 61.135 13.690 61.305 14.280 ;
        RECT 61.475 14.060 61.645 14.840 ;
        RECT 61.815 14.740 61.985 15.080 ;
        RECT 62.220 14.910 62.550 15.340 ;
        RECT 62.720 14.740 62.890 15.080 ;
        RECT 63.185 14.880 63.555 15.340 ;
        RECT 61.815 14.570 62.890 14.740 ;
        RECT 63.725 14.710 63.895 15.170 ;
        RECT 64.130 14.830 65.000 15.170 ;
        RECT 65.170 14.880 65.420 15.340 ;
        RECT 63.335 14.540 63.895 14.710 ;
        RECT 63.335 14.400 63.505 14.540 ;
        RECT 62.005 14.230 63.505 14.400 ;
        RECT 64.200 14.370 64.660 14.660 ;
        RECT 61.475 13.890 63.165 14.060 ;
        RECT 61.135 13.470 61.490 13.690 ;
        RECT 61.660 13.180 61.830 13.890 ;
        RECT 62.035 13.470 62.825 13.720 ;
        RECT 62.995 13.710 63.165 13.890 ;
        RECT 63.335 13.540 63.505 14.230 ;
        RECT 59.775 12.790 60.105 13.150 ;
        RECT 60.275 13.010 60.770 13.180 ;
        RECT 60.975 13.010 61.830 13.180 ;
        RECT 62.705 12.790 63.035 13.250 ;
        RECT 63.245 13.150 63.505 13.540 ;
        RECT 63.695 14.360 64.660 14.370 ;
        RECT 64.830 14.450 65.000 14.830 ;
        RECT 65.590 14.790 65.760 15.080 ;
        RECT 65.940 14.960 66.270 15.340 ;
        RECT 65.590 14.620 66.390 14.790 ;
        RECT 63.695 14.200 64.370 14.360 ;
        RECT 64.830 14.280 66.050 14.450 ;
        RECT 63.695 13.410 63.905 14.200 ;
        RECT 64.830 14.190 65.000 14.280 ;
        RECT 64.075 13.410 64.425 14.030 ;
        RECT 64.595 14.020 65.000 14.190 ;
        RECT 64.595 13.240 64.765 14.020 ;
        RECT 64.935 13.570 65.155 13.850 ;
        RECT 65.335 13.740 65.875 14.110 ;
        RECT 66.220 14.030 66.390 14.620 ;
        RECT 66.610 14.200 66.915 15.340 ;
        RECT 67.085 14.150 67.335 15.030 ;
        RECT 67.505 14.200 67.755 15.340 ;
        RECT 67.975 14.250 69.185 15.340 ;
        RECT 66.220 14.000 66.960 14.030 ;
        RECT 64.935 13.400 65.465 13.570 ;
        RECT 63.245 12.980 63.595 13.150 ;
        RECT 63.815 12.960 64.765 13.240 ;
        RECT 64.935 12.790 65.125 13.230 ;
        RECT 65.295 13.170 65.465 13.400 ;
        RECT 65.635 13.340 65.875 13.740 ;
        RECT 66.045 13.700 66.960 14.000 ;
        RECT 66.045 13.525 66.370 13.700 ;
        RECT 66.045 13.170 66.365 13.525 ;
        RECT 67.130 13.500 67.335 14.150 ;
        RECT 65.295 13.000 66.365 13.170 ;
        RECT 66.610 12.790 66.915 13.250 ;
        RECT 67.085 12.970 67.335 13.500 ;
        RECT 67.505 12.790 67.755 13.545 ;
        RECT 67.975 13.540 68.495 14.080 ;
        RECT 68.665 13.710 69.185 14.250 ;
        RECT 69.395 14.200 69.625 15.340 ;
        RECT 69.795 14.190 70.125 15.170 ;
        RECT 70.295 14.200 70.505 15.340 ;
        RECT 70.735 14.250 71.945 15.340 ;
        RECT 72.115 14.250 73.325 15.340 ;
        RECT 73.495 14.250 74.705 15.340 ;
        RECT 74.875 14.250 76.085 15.340 ;
        RECT 76.255 14.250 77.465 15.340 ;
        RECT 77.635 14.250 78.845 15.340 ;
        RECT 69.375 13.780 69.705 14.030 ;
        RECT 67.975 12.790 69.185 13.540 ;
        RECT 69.395 12.790 69.625 13.610 ;
        RECT 69.875 13.590 70.125 14.190 ;
        RECT 69.795 12.960 70.125 13.590 ;
        RECT 70.295 12.790 70.505 13.610 ;
        RECT 70.735 13.540 71.255 14.080 ;
        RECT 71.425 13.710 71.945 14.250 ;
        RECT 72.115 13.540 72.635 14.080 ;
        RECT 72.805 13.710 73.325 14.250 ;
        RECT 73.495 13.540 74.015 14.080 ;
        RECT 74.185 13.710 74.705 14.250 ;
        RECT 74.875 13.540 75.395 14.080 ;
        RECT 75.565 13.710 76.085 14.250 ;
        RECT 76.255 13.540 76.775 14.080 ;
        RECT 76.945 13.710 77.465 14.250 ;
        RECT 77.635 13.540 78.155 14.080 ;
        RECT 78.325 13.710 78.845 14.250 ;
        RECT 79.935 14.175 80.225 15.340 ;
        RECT 80.855 14.250 82.065 15.340 ;
        RECT 80.855 13.710 81.375 14.250 ;
        RECT 81.545 13.540 82.065 14.080 ;
        RECT 70.735 12.790 71.945 13.540 ;
        RECT 72.115 12.790 73.325 13.540 ;
        RECT 73.495 12.790 74.705 13.540 ;
        RECT 74.875 12.790 76.085 13.540 ;
        RECT 76.255 12.790 77.465 13.540 ;
        RECT 77.635 12.790 78.845 13.540 ;
        RECT 79.935 12.790 80.225 13.515 ;
        RECT 80.855 12.790 82.065 13.540 ;
        RECT 87.970 13.235 88.930 16.845 ;
        RECT 89.890 16.835 91.490 16.845 ;
        RECT 89.250 14.835 89.570 16.035 ;
        RECT 90.530 15.235 92.130 15.635 ;
        RECT 92.450 14.835 92.770 16.035 ;
        RECT 89.890 13.635 91.490 14.035 ;
        RECT 93.090 13.235 94.050 17.635 ;
        RECT 129.450 17.165 130.410 17.565 ;
        RECT 129.450 16.765 132.970 17.165 ;
        RECT 129.450 13.165 130.410 16.765 ;
        RECT 130.730 14.765 131.050 15.965 ;
        RECT 132.010 15.165 133.610 15.565 ;
        RECT 133.930 14.765 134.250 15.965 ;
        RECT 131.370 13.565 132.970 13.965 ;
        RECT 134.570 13.165 135.530 17.565 ;
        RECT 15.450 12.620 82.150 12.790 ;
        RECT 15.535 11.870 16.745 12.620 ;
        RECT 16.915 11.870 18.125 12.620 ;
        RECT 19.220 12.070 19.475 12.360 ;
        RECT 19.645 12.240 19.975 12.620 ;
        RECT 19.220 11.900 19.970 12.070 ;
        RECT 15.535 11.330 16.055 11.870 ;
        RECT 16.225 11.160 16.745 11.700 ;
        RECT 16.915 11.330 17.435 11.870 ;
        RECT 17.605 11.160 18.125 11.700 ;
        RECT 15.535 10.070 16.745 11.160 ;
        RECT 16.915 10.070 18.125 11.160 ;
        RECT 19.220 11.080 19.570 11.730 ;
        RECT 19.740 10.910 19.970 11.900 ;
        RECT 19.220 10.740 19.970 10.910 ;
        RECT 19.220 10.240 19.475 10.740 ;
        RECT 19.645 10.070 19.975 10.570 ;
        RECT 20.145 10.240 20.315 12.360 ;
        RECT 20.675 12.260 21.005 12.620 ;
        RECT 21.175 12.230 21.670 12.400 ;
        RECT 21.875 12.230 22.730 12.400 ;
        RECT 20.545 11.040 21.005 12.090 ;
        RECT 20.485 10.255 20.810 11.040 ;
        RECT 21.175 10.870 21.345 12.230 ;
        RECT 21.515 11.320 21.865 11.940 ;
        RECT 22.035 11.720 22.390 11.940 ;
        RECT 22.035 11.130 22.205 11.720 ;
        RECT 22.560 11.520 22.730 12.230 ;
        RECT 23.605 12.160 23.935 12.620 ;
        RECT 24.145 12.260 24.495 12.430 ;
        RECT 22.935 11.690 23.725 11.940 ;
        RECT 24.145 11.870 24.405 12.260 ;
        RECT 24.715 12.170 25.665 12.450 ;
        RECT 25.835 12.180 26.025 12.620 ;
        RECT 26.195 12.240 27.265 12.410 ;
        RECT 23.895 11.520 24.065 11.700 ;
        RECT 21.175 10.700 21.570 10.870 ;
        RECT 21.740 10.740 22.205 11.130 ;
        RECT 22.375 11.350 24.065 11.520 ;
        RECT 21.400 10.570 21.570 10.700 ;
        RECT 22.375 10.570 22.545 11.350 ;
        RECT 24.235 11.180 24.405 11.870 ;
        RECT 22.905 11.010 24.405 11.180 ;
        RECT 24.595 11.210 24.805 12.000 ;
        RECT 24.975 11.380 25.325 12.000 ;
        RECT 25.495 11.390 25.665 12.170 ;
        RECT 26.195 12.010 26.365 12.240 ;
        RECT 25.835 11.840 26.365 12.010 ;
        RECT 25.835 11.560 26.055 11.840 ;
        RECT 26.535 11.670 26.775 12.070 ;
        RECT 25.495 11.220 25.900 11.390 ;
        RECT 26.235 11.300 26.775 11.670 ;
        RECT 26.945 11.885 27.265 12.240 ;
        RECT 27.510 12.160 27.815 12.620 ;
        RECT 27.985 11.910 28.235 12.440 ;
        RECT 26.945 11.710 27.270 11.885 ;
        RECT 26.945 11.410 27.860 11.710 ;
        RECT 27.120 11.380 27.860 11.410 ;
        RECT 24.595 11.050 25.270 11.210 ;
        RECT 25.730 11.130 25.900 11.220 ;
        RECT 24.595 11.040 25.560 11.050 ;
        RECT 24.235 10.870 24.405 11.010 ;
        RECT 20.980 10.070 21.230 10.530 ;
        RECT 21.400 10.240 21.650 10.570 ;
        RECT 21.865 10.240 22.545 10.570 ;
        RECT 22.715 10.670 23.790 10.840 ;
        RECT 24.235 10.700 24.795 10.870 ;
        RECT 25.100 10.750 25.560 11.040 ;
        RECT 25.730 10.960 26.950 11.130 ;
        RECT 22.715 10.330 22.885 10.670 ;
        RECT 23.120 10.070 23.450 10.500 ;
        RECT 23.620 10.330 23.790 10.670 ;
        RECT 24.085 10.070 24.455 10.530 ;
        RECT 24.625 10.240 24.795 10.700 ;
        RECT 25.730 10.580 25.900 10.960 ;
        RECT 27.120 10.790 27.290 11.380 ;
        RECT 28.030 11.260 28.235 11.910 ;
        RECT 28.405 11.865 28.655 12.620 ;
        RECT 28.895 12.135 29.685 12.400 ;
        RECT 28.875 11.460 29.260 11.940 ;
        RECT 29.430 11.280 29.685 12.135 ;
        RECT 29.855 11.955 30.085 12.400 ;
        RECT 30.265 12.125 30.595 12.620 ;
        RECT 30.770 11.990 31.020 12.450 ;
        RECT 29.855 11.460 30.265 11.955 ;
        RECT 30.850 11.780 31.020 11.990 ;
        RECT 31.190 11.960 31.465 12.620 ;
        RECT 31.640 12.070 31.895 12.360 ;
        RECT 32.065 12.240 32.395 12.620 ;
        RECT 31.640 11.900 32.390 12.070 ;
        RECT 30.450 11.280 30.680 11.710 ;
        RECT 25.030 10.240 25.900 10.580 ;
        RECT 26.490 10.620 27.290 10.790 ;
        RECT 26.070 10.070 26.320 10.530 ;
        RECT 26.490 10.330 26.660 10.620 ;
        RECT 26.840 10.070 27.170 10.450 ;
        RECT 27.510 10.070 27.815 11.210 ;
        RECT 27.985 10.380 28.235 11.260 ;
        RECT 28.405 10.070 28.655 11.210 ;
        RECT 28.890 11.110 30.680 11.280 ;
        RECT 30.850 11.260 31.465 11.780 ;
        RECT 28.890 10.745 29.145 11.110 ;
        RECT 29.315 10.750 29.645 10.940 ;
        RECT 29.870 10.815 30.120 11.110 ;
        RECT 29.315 10.575 29.505 10.750 ;
        RECT 28.875 10.070 29.505 10.575 ;
        RECT 29.685 10.240 30.160 10.580 ;
        RECT 30.345 10.070 30.560 10.915 ;
        RECT 30.865 10.910 31.035 11.260 ;
        RECT 31.640 11.080 31.990 11.730 ;
        RECT 30.760 10.240 31.035 10.910 ;
        RECT 31.205 10.070 31.465 11.080 ;
        RECT 32.160 10.910 32.390 11.900 ;
        RECT 31.640 10.740 32.390 10.910 ;
        RECT 31.640 10.240 31.895 10.740 ;
        RECT 32.065 10.070 32.395 10.570 ;
        RECT 32.565 10.240 32.735 12.360 ;
        RECT 33.095 12.260 33.425 12.620 ;
        RECT 33.595 12.230 34.090 12.400 ;
        RECT 34.295 12.230 35.150 12.400 ;
        RECT 32.965 11.040 33.425 12.090 ;
        RECT 32.905 10.255 33.230 11.040 ;
        RECT 33.595 10.870 33.765 12.230 ;
        RECT 33.935 11.320 34.285 11.940 ;
        RECT 34.455 11.720 34.810 11.940 ;
        RECT 34.455 11.130 34.625 11.720 ;
        RECT 34.980 11.520 35.150 12.230 ;
        RECT 36.025 12.160 36.355 12.620 ;
        RECT 36.565 12.260 36.915 12.430 ;
        RECT 35.355 11.690 36.145 11.940 ;
        RECT 36.565 11.870 36.825 12.260 ;
        RECT 37.135 12.170 38.085 12.450 ;
        RECT 38.255 12.180 38.445 12.620 ;
        RECT 38.615 12.240 39.685 12.410 ;
        RECT 36.315 11.520 36.485 11.700 ;
        RECT 33.595 10.700 33.990 10.870 ;
        RECT 34.160 10.740 34.625 11.130 ;
        RECT 34.795 11.350 36.485 11.520 ;
        RECT 33.820 10.570 33.990 10.700 ;
        RECT 34.795 10.570 34.965 11.350 ;
        RECT 36.655 11.180 36.825 11.870 ;
        RECT 35.325 11.010 36.825 11.180 ;
        RECT 37.015 11.210 37.225 12.000 ;
        RECT 37.395 11.380 37.745 12.000 ;
        RECT 37.915 11.390 38.085 12.170 ;
        RECT 38.615 12.010 38.785 12.240 ;
        RECT 38.255 11.840 38.785 12.010 ;
        RECT 38.255 11.560 38.475 11.840 ;
        RECT 38.955 11.670 39.195 12.070 ;
        RECT 37.915 11.220 38.320 11.390 ;
        RECT 38.655 11.300 39.195 11.670 ;
        RECT 39.365 11.885 39.685 12.240 ;
        RECT 39.930 12.160 40.235 12.620 ;
        RECT 40.405 11.910 40.655 12.440 ;
        RECT 39.365 11.710 39.690 11.885 ;
        RECT 39.365 11.410 40.280 11.710 ;
        RECT 39.540 11.380 40.280 11.410 ;
        RECT 37.015 11.050 37.690 11.210 ;
        RECT 38.150 11.130 38.320 11.220 ;
        RECT 37.015 11.040 37.980 11.050 ;
        RECT 36.655 10.870 36.825 11.010 ;
        RECT 33.400 10.070 33.650 10.530 ;
        RECT 33.820 10.240 34.070 10.570 ;
        RECT 34.285 10.240 34.965 10.570 ;
        RECT 35.135 10.670 36.210 10.840 ;
        RECT 36.655 10.700 37.215 10.870 ;
        RECT 37.520 10.750 37.980 11.040 ;
        RECT 38.150 10.960 39.370 11.130 ;
        RECT 35.135 10.330 35.305 10.670 ;
        RECT 35.540 10.070 35.870 10.500 ;
        RECT 36.040 10.330 36.210 10.670 ;
        RECT 36.505 10.070 36.875 10.530 ;
        RECT 37.045 10.240 37.215 10.700 ;
        RECT 38.150 10.580 38.320 10.960 ;
        RECT 39.540 10.790 39.710 11.380 ;
        RECT 40.450 11.260 40.655 11.910 ;
        RECT 40.825 11.865 41.075 12.620 ;
        RECT 41.295 11.895 41.585 12.620 ;
        RECT 41.755 11.870 42.965 12.620 ;
        RECT 43.135 11.870 44.345 12.620 ;
        RECT 44.515 11.870 45.725 12.620 ;
        RECT 45.895 11.870 47.105 12.620 ;
        RECT 47.280 12.070 47.535 12.360 ;
        RECT 47.705 12.240 48.035 12.620 ;
        RECT 47.280 11.900 48.030 12.070 ;
        RECT 41.755 11.330 42.275 11.870 ;
        RECT 37.450 10.240 38.320 10.580 ;
        RECT 38.910 10.620 39.710 10.790 ;
        RECT 38.490 10.070 38.740 10.530 ;
        RECT 38.910 10.330 39.080 10.620 ;
        RECT 39.260 10.070 39.590 10.450 ;
        RECT 39.930 10.070 40.235 11.210 ;
        RECT 40.405 10.380 40.655 11.260 ;
        RECT 40.825 10.070 41.075 11.210 ;
        RECT 41.295 10.070 41.585 11.235 ;
        RECT 42.445 11.160 42.965 11.700 ;
        RECT 43.135 11.330 43.655 11.870 ;
        RECT 43.825 11.160 44.345 11.700 ;
        RECT 44.515 11.330 45.035 11.870 ;
        RECT 45.205 11.160 45.725 11.700 ;
        RECT 45.895 11.330 46.415 11.870 ;
        RECT 46.585 11.160 47.105 11.700 ;
        RECT 41.755 10.070 42.965 11.160 ;
        RECT 43.135 10.070 44.345 11.160 ;
        RECT 44.515 10.070 45.725 11.160 ;
        RECT 45.895 10.070 47.105 11.160 ;
        RECT 47.280 11.080 47.630 11.730 ;
        RECT 47.800 10.910 48.030 11.900 ;
        RECT 47.280 10.740 48.030 10.910 ;
        RECT 47.280 10.240 47.535 10.740 ;
        RECT 47.705 10.070 48.035 10.570 ;
        RECT 48.205 10.240 48.375 12.360 ;
        RECT 48.735 12.260 49.065 12.620 ;
        RECT 49.235 12.230 49.730 12.400 ;
        RECT 49.935 12.230 50.790 12.400 ;
        RECT 48.605 11.040 49.065 12.090 ;
        RECT 48.545 10.255 48.870 11.040 ;
        RECT 49.235 10.870 49.405 12.230 ;
        RECT 49.575 11.320 49.925 11.940 ;
        RECT 50.095 11.720 50.450 11.940 ;
        RECT 50.095 11.130 50.265 11.720 ;
        RECT 50.620 11.520 50.790 12.230 ;
        RECT 51.665 12.160 51.995 12.620 ;
        RECT 52.205 12.260 52.555 12.430 ;
        RECT 50.995 11.690 51.785 11.940 ;
        RECT 52.205 11.870 52.465 12.260 ;
        RECT 52.775 12.170 53.725 12.450 ;
        RECT 53.895 12.180 54.085 12.620 ;
        RECT 54.255 12.240 55.325 12.410 ;
        RECT 51.955 11.520 52.125 11.700 ;
        RECT 49.235 10.700 49.630 10.870 ;
        RECT 49.800 10.740 50.265 11.130 ;
        RECT 50.435 11.350 52.125 11.520 ;
        RECT 49.460 10.570 49.630 10.700 ;
        RECT 50.435 10.570 50.605 11.350 ;
        RECT 52.295 11.180 52.465 11.870 ;
        RECT 50.965 11.010 52.465 11.180 ;
        RECT 52.655 11.210 52.865 12.000 ;
        RECT 53.035 11.380 53.385 12.000 ;
        RECT 53.555 11.390 53.725 12.170 ;
        RECT 54.255 12.010 54.425 12.240 ;
        RECT 53.895 11.840 54.425 12.010 ;
        RECT 53.895 11.560 54.115 11.840 ;
        RECT 54.595 11.670 54.835 12.070 ;
        RECT 53.555 11.220 53.960 11.390 ;
        RECT 54.295 11.300 54.835 11.670 ;
        RECT 55.005 11.885 55.325 12.240 ;
        RECT 55.570 12.160 55.875 12.620 ;
        RECT 56.045 11.910 56.295 12.440 ;
        RECT 55.005 11.710 55.330 11.885 ;
        RECT 55.005 11.410 55.920 11.710 ;
        RECT 55.180 11.380 55.920 11.410 ;
        RECT 52.655 11.050 53.330 11.210 ;
        RECT 53.790 11.130 53.960 11.220 ;
        RECT 52.655 11.040 53.620 11.050 ;
        RECT 52.295 10.870 52.465 11.010 ;
        RECT 49.040 10.070 49.290 10.530 ;
        RECT 49.460 10.240 49.710 10.570 ;
        RECT 49.925 10.240 50.605 10.570 ;
        RECT 50.775 10.670 51.850 10.840 ;
        RECT 52.295 10.700 52.855 10.870 ;
        RECT 53.160 10.750 53.620 11.040 ;
        RECT 53.790 10.960 55.010 11.130 ;
        RECT 50.775 10.330 50.945 10.670 ;
        RECT 51.180 10.070 51.510 10.500 ;
        RECT 51.680 10.330 51.850 10.670 ;
        RECT 52.145 10.070 52.515 10.530 ;
        RECT 52.685 10.240 52.855 10.700 ;
        RECT 53.790 10.580 53.960 10.960 ;
        RECT 55.180 10.790 55.350 11.380 ;
        RECT 56.090 11.260 56.295 11.910 ;
        RECT 56.465 11.865 56.715 12.620 ;
        RECT 57.135 11.990 57.465 12.350 ;
        RECT 58.095 12.160 58.345 12.620 ;
        RECT 58.515 12.160 59.065 12.450 ;
        RECT 57.135 11.800 58.525 11.990 ;
        RECT 58.355 11.710 58.525 11.800 ;
        RECT 53.090 10.240 53.960 10.580 ;
        RECT 54.550 10.620 55.350 10.790 ;
        RECT 54.130 10.070 54.380 10.530 ;
        RECT 54.550 10.330 54.720 10.620 ;
        RECT 54.900 10.070 55.230 10.450 ;
        RECT 55.570 10.070 55.875 11.210 ;
        RECT 56.045 10.380 56.295 11.260 ;
        RECT 56.935 11.380 57.625 11.630 ;
        RECT 57.855 11.380 58.185 11.630 ;
        RECT 58.355 11.380 58.645 11.710 ;
        RECT 56.465 10.070 56.715 11.210 ;
        RECT 56.935 10.940 57.250 11.380 ;
        RECT 58.355 11.130 58.525 11.380 ;
        RECT 57.585 10.960 58.525 11.130 ;
        RECT 57.135 10.070 57.415 10.740 ;
        RECT 57.585 10.410 57.885 10.960 ;
        RECT 58.815 10.790 59.065 12.160 ;
        RECT 59.235 11.820 59.525 12.620 ;
        RECT 59.715 12.135 60.505 12.400 ;
        RECT 59.695 11.460 60.080 11.940 ;
        RECT 60.250 11.280 60.505 12.135 ;
        RECT 60.675 11.955 60.905 12.400 ;
        RECT 61.085 12.125 61.415 12.620 ;
        RECT 61.590 11.990 61.840 12.450 ;
        RECT 60.675 11.460 61.085 11.955 ;
        RECT 61.670 11.780 61.840 11.990 ;
        RECT 62.010 11.960 62.285 12.620 ;
        RECT 62.505 12.150 62.795 12.620 ;
        RECT 62.965 11.980 63.295 12.450 ;
        RECT 63.465 12.150 63.635 12.620 ;
        RECT 63.805 11.980 64.135 12.450 ;
        RECT 62.965 11.970 64.135 11.980 ;
        RECT 62.535 11.940 64.135 11.970 ;
        RECT 62.515 11.800 64.135 11.940 ;
        RECT 64.305 11.800 64.580 12.620 ;
        RECT 64.805 12.150 65.095 12.620 ;
        RECT 65.265 11.980 65.595 12.450 ;
        RECT 65.765 12.150 65.935 12.620 ;
        RECT 66.105 11.980 66.435 12.450 ;
        RECT 65.265 11.970 66.435 11.980 ;
        RECT 64.835 11.800 66.435 11.970 ;
        RECT 66.605 11.800 66.880 12.620 ;
        RECT 67.055 11.895 67.345 12.620 ;
        RECT 67.515 11.870 68.725 12.620 ;
        RECT 68.895 11.870 70.105 12.620 ;
        RECT 70.275 11.870 71.485 12.620 ;
        RECT 71.655 11.870 72.865 12.620 ;
        RECT 61.270 11.280 61.500 11.710 ;
        RECT 58.095 10.070 58.425 10.790 ;
        RECT 58.615 10.240 59.065 10.790 ;
        RECT 59.235 10.070 59.525 11.210 ;
        RECT 59.710 11.110 61.500 11.280 ;
        RECT 61.670 11.260 62.285 11.780 ;
        RECT 62.515 11.770 62.750 11.800 ;
        RECT 62.535 11.260 62.750 11.770 ;
        RECT 62.920 11.430 63.690 11.630 ;
        RECT 63.860 11.430 64.580 11.630 ;
        RECT 64.835 11.260 65.050 11.800 ;
        RECT 65.220 11.430 65.990 11.630 ;
        RECT 66.160 11.430 66.880 11.630 ;
        RECT 67.515 11.330 68.035 11.870 ;
        RECT 59.710 10.745 59.965 11.110 ;
        RECT 60.135 10.750 60.465 10.940 ;
        RECT 60.690 10.815 60.940 11.110 ;
        RECT 60.135 10.575 60.325 10.750 ;
        RECT 59.695 10.070 60.325 10.575 ;
        RECT 60.505 10.240 60.980 10.580 ;
        RECT 61.165 10.070 61.380 10.915 ;
        RECT 61.685 10.910 61.855 11.260 ;
        RECT 61.580 10.240 61.855 10.910 ;
        RECT 62.025 10.070 62.285 11.080 ;
        RECT 62.535 11.040 63.295 11.260 ;
        RECT 62.495 10.410 62.795 10.870 ;
        RECT 62.965 10.580 63.295 11.040 ;
        RECT 63.465 11.040 64.580 11.250 ;
        RECT 64.835 11.040 65.595 11.260 ;
        RECT 63.465 10.410 63.635 11.040 ;
        RECT 62.495 10.240 63.635 10.410 ;
        RECT 63.805 10.070 64.135 10.870 ;
        RECT 64.305 10.240 64.580 11.040 ;
        RECT 64.795 10.410 65.095 10.870 ;
        RECT 65.265 10.580 65.595 11.040 ;
        RECT 65.765 11.040 66.880 11.250 ;
        RECT 65.765 10.410 65.935 11.040 ;
        RECT 64.795 10.240 65.935 10.410 ;
        RECT 66.105 10.070 66.435 10.870 ;
        RECT 66.605 10.240 66.880 11.040 ;
        RECT 67.055 10.070 67.345 11.235 ;
        RECT 68.205 11.160 68.725 11.700 ;
        RECT 68.895 11.330 69.415 11.870 ;
        RECT 69.585 11.160 70.105 11.700 ;
        RECT 70.275 11.330 70.795 11.870 ;
        RECT 70.965 11.160 71.485 11.700 ;
        RECT 71.655 11.330 72.175 11.870 ;
        RECT 73.500 11.780 73.760 12.620 ;
        RECT 73.935 11.875 74.190 12.450 ;
        RECT 74.360 12.240 74.690 12.620 ;
        RECT 74.905 12.070 75.075 12.450 ;
        RECT 74.360 11.900 75.075 12.070 ;
        RECT 72.345 11.160 72.865 11.700 ;
        RECT 67.515 10.070 68.725 11.160 ;
        RECT 68.895 10.070 70.105 11.160 ;
        RECT 70.275 10.070 71.485 11.160 ;
        RECT 71.655 10.070 72.865 11.160 ;
        RECT 73.500 10.070 73.760 11.220 ;
        RECT 73.935 11.145 74.105 11.875 ;
        RECT 74.360 11.710 74.530 11.900 ;
        RECT 75.835 11.800 76.065 12.620 ;
        RECT 76.235 11.820 76.565 12.450 ;
        RECT 74.275 11.380 74.530 11.710 ;
        RECT 74.360 11.170 74.530 11.380 ;
        RECT 74.810 11.350 75.165 11.720 ;
        RECT 75.815 11.380 76.145 11.630 ;
        RECT 76.315 11.220 76.565 11.820 ;
        RECT 76.735 11.800 76.945 12.620 ;
        RECT 77.175 11.970 77.500 12.450 ;
        RECT 77.670 12.140 78.000 12.620 ;
        RECT 77.175 11.800 78.095 11.970 ;
        RECT 78.265 11.850 78.735 12.450 ;
        RECT 77.745 11.680 78.095 11.800 ;
        RECT 77.175 11.385 77.575 11.630 ;
        RECT 77.745 11.410 78.195 11.680 ;
        RECT 78.560 11.630 78.735 11.850 ;
        RECT 78.905 11.970 79.155 12.450 ;
        RECT 79.330 12.140 79.935 12.620 ;
        RECT 80.105 12.065 80.685 12.450 ;
        RECT 78.905 11.800 79.855 11.970 ;
        RECT 79.685 11.715 79.855 11.800 ;
        RECT 78.560 11.455 79.510 11.630 ;
        RECT 73.935 10.240 74.190 11.145 ;
        RECT 74.360 11.000 75.075 11.170 ;
        RECT 74.360 10.070 74.690 10.830 ;
        RECT 74.905 10.240 75.075 11.000 ;
        RECT 75.835 10.070 76.065 11.210 ;
        RECT 76.235 10.240 76.565 11.220 ;
        RECT 77.745 11.215 78.095 11.410 ;
        RECT 76.735 10.070 76.945 11.210 ;
        RECT 77.175 11.045 78.095 11.215 ;
        RECT 77.175 10.240 77.520 11.045 ;
        RECT 78.560 10.915 78.735 11.455 ;
        RECT 79.685 11.380 80.140 11.715 ;
        RECT 79.685 11.210 79.855 11.380 ;
        RECT 77.690 10.070 78.015 10.875 ;
        RECT 78.285 10.240 78.735 10.915 ;
        RECT 78.905 11.040 79.855 11.210 ;
        RECT 80.320 11.140 80.685 12.065 ;
        RECT 80.855 11.870 82.065 12.620 ;
        RECT 78.905 10.240 79.155 11.040 ;
        RECT 79.325 10.070 79.935 10.870 ;
        RECT 80.125 10.240 80.685 11.140 ;
        RECT 80.855 11.160 81.375 11.700 ;
        RECT 81.545 11.330 82.065 11.870 ;
        RECT 80.855 10.070 82.065 11.160 ;
        RECT 15.450 9.900 82.150 10.070 ;
        RECT 15.535 8.810 16.745 9.900 ;
        RECT 15.535 8.100 16.055 8.640 ;
        RECT 16.225 8.270 16.745 8.810 ;
        RECT 16.915 8.760 17.205 9.900 ;
        RECT 17.375 9.180 17.825 9.730 ;
        RECT 18.015 9.180 18.345 9.900 ;
        RECT 15.535 7.350 16.745 8.100 ;
        RECT 16.915 7.350 17.205 8.150 ;
        RECT 17.375 7.810 17.625 9.180 ;
        RECT 18.555 9.010 18.855 9.560 ;
        RECT 19.025 9.230 19.305 9.900 ;
        RECT 17.915 8.840 18.855 9.010 ;
        RECT 17.915 8.590 18.085 8.840 ;
        RECT 19.190 8.590 19.505 9.030 ;
        RECT 17.795 8.260 18.085 8.590 ;
        RECT 18.255 8.340 18.585 8.590 ;
        RECT 18.815 8.340 19.505 8.590 ;
        RECT 19.675 8.760 20.060 9.730 ;
        RECT 20.230 9.440 20.555 9.900 ;
        RECT 21.075 9.270 21.355 9.730 ;
        RECT 20.230 9.050 21.355 9.270 ;
        RECT 17.915 8.170 18.085 8.260 ;
        RECT 17.915 7.980 19.305 8.170 ;
        RECT 17.375 7.520 17.925 7.810 ;
        RECT 18.095 7.350 18.345 7.810 ;
        RECT 18.975 7.620 19.305 7.980 ;
        RECT 19.675 8.090 19.955 8.760 ;
        RECT 20.230 8.590 20.680 9.050 ;
        RECT 21.545 8.880 21.945 9.730 ;
        RECT 22.345 9.440 22.615 9.900 ;
        RECT 22.785 9.270 23.070 9.730 ;
        RECT 20.125 8.260 20.680 8.590 ;
        RECT 20.850 8.320 21.945 8.880 ;
        RECT 20.230 8.150 20.680 8.260 ;
        RECT 19.675 7.520 20.060 8.090 ;
        RECT 20.230 7.980 21.355 8.150 ;
        RECT 20.230 7.350 20.555 7.810 ;
        RECT 21.075 7.520 21.355 7.980 ;
        RECT 21.545 7.520 21.945 8.320 ;
        RECT 22.115 9.050 23.070 9.270 ;
        RECT 22.115 8.150 22.325 9.050 ;
        RECT 22.495 8.320 23.185 8.880 ;
        RECT 23.360 8.760 23.695 9.730 ;
        RECT 23.865 8.760 24.035 9.900 ;
        RECT 24.205 9.560 26.235 9.730 ;
        RECT 22.115 7.980 23.070 8.150 ;
        RECT 22.345 7.350 22.615 7.810 ;
        RECT 22.785 7.520 23.070 7.980 ;
        RECT 23.360 8.090 23.530 8.760 ;
        RECT 24.205 8.590 24.375 9.560 ;
        RECT 23.700 8.260 23.955 8.590 ;
        RECT 24.180 8.260 24.375 8.590 ;
        RECT 24.545 9.220 25.670 9.390 ;
        RECT 23.785 8.090 23.955 8.260 ;
        RECT 24.545 8.090 24.715 9.220 ;
        RECT 23.360 7.520 23.615 8.090 ;
        RECT 23.785 7.920 24.715 8.090 ;
        RECT 24.885 8.880 25.895 9.050 ;
        RECT 24.885 8.080 25.055 8.880 ;
        RECT 24.540 7.885 24.715 7.920 ;
        RECT 23.785 7.350 24.115 7.750 ;
        RECT 24.540 7.520 25.070 7.885 ;
        RECT 25.260 7.860 25.535 8.680 ;
        RECT 25.255 7.690 25.535 7.860 ;
        RECT 25.260 7.520 25.535 7.690 ;
        RECT 25.705 7.520 25.895 8.880 ;
        RECT 26.065 8.895 26.235 9.560 ;
        RECT 26.405 9.140 26.575 9.900 ;
        RECT 26.810 9.140 27.325 9.550 ;
        RECT 26.065 8.705 26.815 8.895 ;
        RECT 26.985 8.330 27.325 9.140 ;
        RECT 28.415 8.735 28.705 9.900 ;
        RECT 28.880 8.930 29.155 9.730 ;
        RECT 29.325 9.100 29.655 9.900 ;
        RECT 29.825 9.560 30.965 9.730 ;
        RECT 29.825 8.930 29.995 9.560 ;
        RECT 28.880 8.720 29.995 8.930 ;
        RECT 30.165 8.930 30.495 9.390 ;
        RECT 30.665 9.100 30.965 9.560 ;
        RECT 31.265 9.155 31.535 9.900 ;
        RECT 32.165 9.895 38.440 9.900 ;
        RECT 31.705 8.985 31.995 9.725 ;
        RECT 32.165 9.170 32.420 9.895 ;
        RECT 32.605 9.000 32.865 9.725 ;
        RECT 33.035 9.170 33.280 9.895 ;
        RECT 33.465 9.000 33.725 9.725 ;
        RECT 33.895 9.170 34.140 9.895 ;
        RECT 34.325 9.000 34.585 9.725 ;
        RECT 34.755 9.170 35.000 9.895 ;
        RECT 35.170 9.000 35.430 9.725 ;
        RECT 35.600 9.170 35.860 9.895 ;
        RECT 36.030 9.000 36.290 9.725 ;
        RECT 36.460 9.170 36.720 9.895 ;
        RECT 36.890 9.000 37.150 9.725 ;
        RECT 37.320 9.170 37.580 9.895 ;
        RECT 37.750 9.000 38.010 9.725 ;
        RECT 38.180 9.100 38.440 9.895 ;
        RECT 32.605 8.985 38.010 9.000 ;
        RECT 30.165 8.710 30.925 8.930 ;
        RECT 28.880 8.340 29.600 8.540 ;
        RECT 29.770 8.340 30.540 8.540 ;
        RECT 26.095 8.160 27.325 8.330 ;
        RECT 30.710 8.170 30.925 8.710 ;
        RECT 31.265 8.760 38.010 8.985 ;
        RECT 31.265 8.200 32.430 8.760 ;
        RECT 38.610 8.590 38.860 9.725 ;
        RECT 39.040 9.090 39.300 9.900 ;
        RECT 39.475 8.590 39.720 9.730 ;
        RECT 39.900 9.090 40.195 9.900 ;
        RECT 40.385 8.920 40.715 9.730 ;
        RECT 40.885 9.100 41.125 9.900 ;
        RECT 40.385 8.750 41.100 8.920 ;
        RECT 32.600 8.340 39.720 8.590 ;
        RECT 26.075 7.350 26.585 7.885 ;
        RECT 26.805 7.555 27.050 8.160 ;
        RECT 28.415 7.350 28.705 8.075 ;
        RECT 28.880 7.350 29.155 8.170 ;
        RECT 29.325 8.000 30.925 8.170 ;
        RECT 31.235 8.170 32.430 8.200 ;
        RECT 31.235 8.030 38.010 8.170 ;
        RECT 31.265 8.000 38.010 8.030 ;
        RECT 29.325 7.990 30.495 8.000 ;
        RECT 29.325 7.520 29.655 7.990 ;
        RECT 29.825 7.350 29.995 7.820 ;
        RECT 30.165 7.520 30.495 7.990 ;
        RECT 30.665 7.350 30.955 7.820 ;
        RECT 31.265 7.350 31.565 7.830 ;
        RECT 31.735 7.545 31.995 8.000 ;
        RECT 32.165 7.350 32.425 7.830 ;
        RECT 32.605 7.545 32.865 8.000 ;
        RECT 33.035 7.350 33.285 7.830 ;
        RECT 33.465 7.545 33.725 8.000 ;
        RECT 33.895 7.350 34.145 7.830 ;
        RECT 34.325 7.545 34.585 8.000 ;
        RECT 34.755 7.350 35.000 7.830 ;
        RECT 35.170 7.545 35.445 8.000 ;
        RECT 35.615 7.350 35.860 7.830 ;
        RECT 36.030 7.545 36.290 8.000 ;
        RECT 36.460 7.350 36.720 7.830 ;
        RECT 36.890 7.545 37.150 8.000 ;
        RECT 37.320 7.350 37.580 7.830 ;
        RECT 37.750 7.545 38.010 8.000 ;
        RECT 38.180 7.350 38.440 7.910 ;
        RECT 38.610 7.530 38.860 8.340 ;
        RECT 39.040 7.350 39.300 7.875 ;
        RECT 39.470 7.530 39.720 8.340 ;
        RECT 39.890 8.030 40.205 8.590 ;
        RECT 40.380 8.340 40.760 8.580 ;
        RECT 40.930 8.510 41.100 8.750 ;
        RECT 41.305 8.880 41.475 9.730 ;
        RECT 41.645 9.100 41.975 9.900 ;
        RECT 42.145 8.880 42.315 9.730 ;
        RECT 41.305 8.710 42.315 8.880 ;
        RECT 42.485 8.750 42.815 9.900 ;
        RECT 43.135 8.810 44.345 9.900 ;
        RECT 44.525 9.090 44.820 9.900 ;
        RECT 40.930 8.340 41.430 8.510 ;
        RECT 40.930 8.170 41.100 8.340 ;
        RECT 41.820 8.200 42.315 8.710 ;
        RECT 41.815 8.170 42.315 8.200 ;
        RECT 40.465 8.000 41.100 8.170 ;
        RECT 41.305 8.000 42.315 8.170 ;
        RECT 39.900 7.350 40.205 7.860 ;
        RECT 40.465 7.520 40.635 8.000 ;
        RECT 40.815 7.350 41.055 7.830 ;
        RECT 41.305 7.520 41.475 8.000 ;
        RECT 41.645 7.350 41.975 7.830 ;
        RECT 42.145 7.520 42.315 8.000 ;
        RECT 42.485 7.350 42.815 8.150 ;
        RECT 43.135 8.100 43.655 8.640 ;
        RECT 43.825 8.270 44.345 8.810 ;
        RECT 45.000 8.590 45.245 9.730 ;
        RECT 45.420 9.090 45.680 9.900 ;
        RECT 46.280 9.895 52.555 9.900 ;
        RECT 45.860 8.590 46.110 9.725 ;
        RECT 46.280 9.100 46.540 9.895 ;
        RECT 46.710 9.000 46.970 9.725 ;
        RECT 47.140 9.170 47.400 9.895 ;
        RECT 47.570 9.000 47.830 9.725 ;
        RECT 48.000 9.170 48.260 9.895 ;
        RECT 48.430 9.000 48.690 9.725 ;
        RECT 48.860 9.170 49.120 9.895 ;
        RECT 49.290 9.000 49.550 9.725 ;
        RECT 49.720 9.170 49.965 9.895 ;
        RECT 50.135 9.000 50.395 9.725 ;
        RECT 50.580 9.170 50.825 9.895 ;
        RECT 50.995 9.000 51.255 9.725 ;
        RECT 51.440 9.170 51.685 9.895 ;
        RECT 51.855 9.000 52.115 9.725 ;
        RECT 52.300 9.170 52.555 9.895 ;
        RECT 46.710 8.985 52.115 9.000 ;
        RECT 52.725 8.985 53.015 9.725 ;
        RECT 53.185 9.155 53.455 9.900 ;
        RECT 46.710 8.760 53.455 8.985 ;
        RECT 43.135 7.350 44.345 8.100 ;
        RECT 44.515 8.030 44.830 8.590 ;
        RECT 45.000 8.340 52.120 8.590 ;
        RECT 44.515 7.350 44.820 7.860 ;
        RECT 45.000 7.530 45.250 8.340 ;
        RECT 45.420 7.350 45.680 7.875 ;
        RECT 45.860 7.530 46.110 8.340 ;
        RECT 52.290 8.200 53.455 8.760 ;
        RECT 54.175 8.735 54.465 9.900 ;
        RECT 54.635 8.810 55.845 9.900 ;
        RECT 56.960 9.370 57.220 9.730 ;
        RECT 57.390 9.540 57.720 9.900 ;
        RECT 57.900 9.370 58.070 9.730 ;
        RECT 58.325 9.460 58.495 9.900 ;
        RECT 58.665 9.550 59.940 9.730 ;
        RECT 56.960 9.290 58.070 9.370 ;
        RECT 58.665 9.290 58.995 9.550 ;
        RECT 56.960 9.120 58.995 9.290 ;
        RECT 52.290 8.170 53.485 8.200 ;
        RECT 46.710 8.030 53.485 8.170 ;
        RECT 54.635 8.100 55.155 8.640 ;
        RECT 55.325 8.270 55.845 8.810 ;
        RECT 56.995 8.760 58.780 8.940 ;
        RECT 56.995 8.300 57.495 8.760 ;
        RECT 57.665 8.260 58.275 8.590 ;
        RECT 58.455 8.510 58.780 8.760 ;
        RECT 58.455 8.340 58.785 8.510 ;
        RECT 46.710 8.000 53.455 8.030 ;
        RECT 46.280 7.350 46.540 7.910 ;
        RECT 46.710 7.545 46.970 8.000 ;
        RECT 47.140 7.350 47.400 7.830 ;
        RECT 47.570 7.545 47.830 8.000 ;
        RECT 48.000 7.350 48.260 7.830 ;
        RECT 48.430 7.545 48.690 8.000 ;
        RECT 48.860 7.350 49.105 7.830 ;
        RECT 49.275 7.545 49.550 8.000 ;
        RECT 49.720 7.350 49.965 7.830 ;
        RECT 50.135 7.545 50.395 8.000 ;
        RECT 50.575 7.350 50.825 7.830 ;
        RECT 50.995 7.545 51.255 8.000 ;
        RECT 51.435 7.350 51.685 7.830 ;
        RECT 51.855 7.545 52.115 8.000 ;
        RECT 52.295 7.350 52.555 7.830 ;
        RECT 52.725 7.545 52.985 8.000 ;
        RECT 53.155 7.350 53.455 7.830 ;
        RECT 54.175 7.350 54.465 8.075 ;
        RECT 54.635 7.350 55.845 8.100 ;
        RECT 56.950 7.350 57.245 8.130 ;
        RECT 59.165 8.050 59.465 9.380 ;
        RECT 59.635 9.060 59.940 9.550 ;
        RECT 61.080 9.230 61.335 9.730 ;
        RECT 61.505 9.400 61.835 9.900 ;
        RECT 61.080 9.060 61.830 9.230 ;
        RECT 59.650 8.260 59.925 8.890 ;
        RECT 61.080 8.240 61.430 8.890 ;
        RECT 57.805 7.880 59.465 8.050 ;
        RECT 57.805 7.520 58.150 7.880 ;
        RECT 58.610 7.350 58.940 7.710 ;
        RECT 59.145 7.520 59.465 7.880 ;
        RECT 59.645 7.350 59.975 8.090 ;
        RECT 61.600 8.070 61.830 9.060 ;
        RECT 61.080 7.900 61.830 8.070 ;
        RECT 61.080 7.610 61.335 7.900 ;
        RECT 61.505 7.350 61.835 7.730 ;
        RECT 62.005 7.610 62.175 9.730 ;
        RECT 62.345 8.930 62.670 9.715 ;
        RECT 62.840 9.440 63.090 9.900 ;
        RECT 63.260 9.400 63.510 9.730 ;
        RECT 63.725 9.400 64.405 9.730 ;
        RECT 63.260 9.270 63.430 9.400 ;
        RECT 63.035 9.100 63.430 9.270 ;
        RECT 62.405 7.880 62.865 8.930 ;
        RECT 63.035 7.740 63.205 9.100 ;
        RECT 63.600 8.840 64.065 9.230 ;
        RECT 63.375 8.030 63.725 8.650 ;
        RECT 63.895 8.250 64.065 8.840 ;
        RECT 64.235 8.620 64.405 9.400 ;
        RECT 64.575 9.300 64.745 9.640 ;
        RECT 64.980 9.470 65.310 9.900 ;
        RECT 65.480 9.300 65.650 9.640 ;
        RECT 65.945 9.440 66.315 9.900 ;
        RECT 64.575 9.130 65.650 9.300 ;
        RECT 66.485 9.270 66.655 9.730 ;
        RECT 66.890 9.390 67.760 9.730 ;
        RECT 67.930 9.440 68.180 9.900 ;
        RECT 66.095 9.100 66.655 9.270 ;
        RECT 66.095 8.960 66.265 9.100 ;
        RECT 64.765 8.790 66.265 8.960 ;
        RECT 66.960 8.930 67.420 9.220 ;
        RECT 64.235 8.450 65.925 8.620 ;
        RECT 63.895 8.030 64.250 8.250 ;
        RECT 64.420 7.740 64.590 8.450 ;
        RECT 64.795 8.030 65.585 8.280 ;
        RECT 65.755 8.270 65.925 8.450 ;
        RECT 66.095 8.100 66.265 8.790 ;
        RECT 62.535 7.350 62.865 7.710 ;
        RECT 63.035 7.570 63.530 7.740 ;
        RECT 63.735 7.570 64.590 7.740 ;
        RECT 65.465 7.350 65.795 7.810 ;
        RECT 66.005 7.710 66.265 8.100 ;
        RECT 66.455 8.920 67.420 8.930 ;
        RECT 67.590 9.010 67.760 9.390 ;
        RECT 68.350 9.350 68.520 9.640 ;
        RECT 68.700 9.520 69.030 9.900 ;
        RECT 68.350 9.180 69.150 9.350 ;
        RECT 66.455 8.760 67.130 8.920 ;
        RECT 67.590 8.840 68.810 9.010 ;
        RECT 66.455 7.970 66.665 8.760 ;
        RECT 67.590 8.750 67.760 8.840 ;
        RECT 66.835 7.970 67.185 8.590 ;
        RECT 67.355 8.580 67.760 8.750 ;
        RECT 67.355 7.800 67.525 8.580 ;
        RECT 67.695 8.130 67.915 8.410 ;
        RECT 68.095 8.300 68.635 8.670 ;
        RECT 68.980 8.590 69.150 9.180 ;
        RECT 69.370 8.760 69.675 9.900 ;
        RECT 69.845 8.710 70.095 9.590 ;
        RECT 70.265 8.760 70.515 9.900 ;
        RECT 71.200 8.760 71.535 9.730 ;
        RECT 71.705 8.760 71.875 9.900 ;
        RECT 72.045 9.560 74.075 9.730 ;
        RECT 68.980 8.560 69.720 8.590 ;
        RECT 67.695 7.960 68.225 8.130 ;
        RECT 66.005 7.540 66.355 7.710 ;
        RECT 66.575 7.520 67.525 7.800 ;
        RECT 67.695 7.350 67.885 7.790 ;
        RECT 68.055 7.730 68.225 7.960 ;
        RECT 68.395 7.900 68.635 8.300 ;
        RECT 68.805 8.260 69.720 8.560 ;
        RECT 68.805 8.085 69.130 8.260 ;
        RECT 68.805 7.730 69.125 8.085 ;
        RECT 69.890 8.060 70.095 8.710 ;
        RECT 68.055 7.560 69.125 7.730 ;
        RECT 69.370 7.350 69.675 7.810 ;
        RECT 69.845 7.530 70.095 8.060 ;
        RECT 70.265 7.350 70.515 8.105 ;
        RECT 71.200 8.090 71.370 8.760 ;
        RECT 72.045 8.590 72.215 9.560 ;
        RECT 71.540 8.260 71.795 8.590 ;
        RECT 72.020 8.260 72.215 8.590 ;
        RECT 72.385 9.220 73.510 9.390 ;
        RECT 71.625 8.090 71.795 8.260 ;
        RECT 72.385 8.090 72.555 9.220 ;
        RECT 71.200 7.520 71.455 8.090 ;
        RECT 71.625 7.920 72.555 8.090 ;
        RECT 72.725 8.880 73.735 9.050 ;
        RECT 72.725 8.080 72.895 8.880 ;
        RECT 72.380 7.885 72.555 7.920 ;
        RECT 71.625 7.350 71.955 7.750 ;
        RECT 72.380 7.520 72.910 7.885 ;
        RECT 73.100 7.860 73.375 8.680 ;
        RECT 73.095 7.690 73.375 7.860 ;
        RECT 73.100 7.520 73.375 7.690 ;
        RECT 73.545 7.520 73.735 8.880 ;
        RECT 73.905 8.895 74.075 9.560 ;
        RECT 74.245 9.140 74.415 9.900 ;
        RECT 74.650 9.140 75.165 9.550 ;
        RECT 73.905 8.705 74.655 8.895 ;
        RECT 74.825 8.330 75.165 9.140 ;
        RECT 73.935 8.160 75.165 8.330 ;
        RECT 75.795 8.830 76.355 9.730 ;
        RECT 76.545 9.100 77.155 9.900 ;
        RECT 77.325 8.930 77.575 9.730 ;
        RECT 73.915 7.350 74.425 7.885 ;
        RECT 74.645 7.555 74.890 8.160 ;
        RECT 75.795 7.905 76.160 8.830 ;
        RECT 76.625 8.760 77.575 8.930 ;
        RECT 77.745 9.055 78.195 9.730 ;
        RECT 78.465 9.095 78.790 9.900 ;
        RECT 76.625 8.590 76.795 8.760 ;
        RECT 76.340 8.255 76.795 8.590 ;
        RECT 77.745 8.515 77.920 9.055 ;
        RECT 78.960 8.925 79.305 9.730 ;
        RECT 78.385 8.755 79.305 8.925 ;
        RECT 78.385 8.560 78.735 8.755 ;
        RECT 79.935 8.735 80.225 9.900 ;
        RECT 80.855 8.810 82.065 9.900 ;
        RECT 76.970 8.340 77.920 8.515 ;
        RECT 76.625 8.170 76.795 8.255 ;
        RECT 76.625 8.000 77.575 8.170 ;
        RECT 75.795 7.520 76.375 7.905 ;
        RECT 76.545 7.350 77.150 7.830 ;
        RECT 77.325 7.520 77.575 8.000 ;
        RECT 77.745 8.120 77.920 8.340 ;
        RECT 78.285 8.290 78.735 8.560 ;
        RECT 78.905 8.340 79.305 8.585 ;
        RECT 78.385 8.170 78.735 8.290 ;
        RECT 80.855 8.270 81.375 8.810 ;
        RECT 77.745 7.520 78.215 8.120 ;
        RECT 78.385 8.000 79.305 8.170 ;
        RECT 81.545 8.100 82.065 8.640 ;
        RECT 78.480 7.350 78.810 7.830 ;
        RECT 78.980 7.520 79.305 8.000 ;
        RECT 79.935 7.350 80.225 8.075 ;
        RECT 80.855 7.350 82.065 8.100 ;
        RECT 15.450 7.180 82.150 7.350 ;
        RECT 15.535 6.430 16.745 7.180 ;
        RECT 16.915 6.625 17.495 7.010 ;
        RECT 17.665 6.700 18.270 7.180 ;
        RECT 15.535 5.890 16.055 6.430 ;
        RECT 16.225 5.720 16.745 6.260 ;
        RECT 15.535 4.630 16.745 5.720 ;
        RECT 16.915 5.700 17.280 6.625 ;
        RECT 18.445 6.530 18.695 7.010 ;
        RECT 17.745 6.360 18.695 6.530 ;
        RECT 18.865 6.410 19.335 7.010 ;
        RECT 19.600 6.700 19.930 7.180 ;
        RECT 20.100 6.530 20.425 7.010 ;
        RECT 17.745 6.275 17.915 6.360 ;
        RECT 17.460 5.940 17.915 6.275 ;
        RECT 18.865 6.190 19.040 6.410 ;
        RECT 19.505 6.360 20.425 6.530 ;
        RECT 20.635 6.360 20.865 7.180 ;
        RECT 21.035 6.380 21.365 7.010 ;
        RECT 19.505 6.240 19.855 6.360 ;
        RECT 18.090 6.015 19.040 6.190 ;
        RECT 17.745 5.770 17.915 5.940 ;
        RECT 16.915 4.800 17.475 5.700 ;
        RECT 17.745 5.600 18.695 5.770 ;
        RECT 17.665 4.630 18.275 5.430 ;
        RECT 18.445 4.800 18.695 5.600 ;
        RECT 18.865 5.475 19.040 6.015 ;
        RECT 19.405 5.970 19.855 6.240 ;
        RECT 19.505 5.775 19.855 5.970 ;
        RECT 20.025 5.945 20.425 6.190 ;
        RECT 20.615 5.940 20.945 6.190 ;
        RECT 21.115 5.780 21.365 6.380 ;
        RECT 21.535 6.360 21.745 7.180 ;
        RECT 21.980 6.630 22.235 6.920 ;
        RECT 22.405 6.800 22.735 7.180 ;
        RECT 21.980 6.460 22.730 6.630 ;
        RECT 19.505 5.605 20.425 5.775 ;
        RECT 18.865 4.800 19.315 5.475 ;
        RECT 19.585 4.630 19.910 5.435 ;
        RECT 20.080 4.800 20.425 5.605 ;
        RECT 20.635 4.630 20.865 5.770 ;
        RECT 21.035 4.800 21.365 5.780 ;
        RECT 21.535 4.630 21.745 5.770 ;
        RECT 21.980 5.640 22.330 6.290 ;
        RECT 22.500 5.470 22.730 6.460 ;
        RECT 21.980 5.300 22.730 5.470 ;
        RECT 21.980 4.800 22.235 5.300 ;
        RECT 22.405 4.630 22.735 5.130 ;
        RECT 22.905 4.800 23.075 6.920 ;
        RECT 23.435 6.820 23.765 7.180 ;
        RECT 23.935 6.790 24.430 6.960 ;
        RECT 24.635 6.790 25.490 6.960 ;
        RECT 23.305 5.600 23.765 6.650 ;
        RECT 23.245 4.815 23.570 5.600 ;
        RECT 23.935 5.430 24.105 6.790 ;
        RECT 24.275 5.880 24.625 6.500 ;
        RECT 24.795 6.280 25.150 6.500 ;
        RECT 24.795 5.690 24.965 6.280 ;
        RECT 25.320 6.080 25.490 6.790 ;
        RECT 26.365 6.720 26.695 7.180 ;
        RECT 26.905 6.820 27.255 6.990 ;
        RECT 25.695 6.250 26.485 6.500 ;
        RECT 26.905 6.430 27.165 6.820 ;
        RECT 27.475 6.730 28.425 7.010 ;
        RECT 28.595 6.740 28.785 7.180 ;
        RECT 28.955 6.800 30.025 6.970 ;
        RECT 26.655 6.080 26.825 6.260 ;
        RECT 23.935 5.260 24.330 5.430 ;
        RECT 24.500 5.300 24.965 5.690 ;
        RECT 25.135 5.910 26.825 6.080 ;
        RECT 24.160 5.130 24.330 5.260 ;
        RECT 25.135 5.130 25.305 5.910 ;
        RECT 26.995 5.740 27.165 6.430 ;
        RECT 25.665 5.570 27.165 5.740 ;
        RECT 27.355 5.770 27.565 6.560 ;
        RECT 27.735 5.940 28.085 6.560 ;
        RECT 28.255 5.950 28.425 6.730 ;
        RECT 28.955 6.570 29.125 6.800 ;
        RECT 28.595 6.400 29.125 6.570 ;
        RECT 28.595 6.120 28.815 6.400 ;
        RECT 29.295 6.230 29.535 6.630 ;
        RECT 28.255 5.780 28.660 5.950 ;
        RECT 28.995 5.860 29.535 6.230 ;
        RECT 29.705 6.445 30.025 6.800 ;
        RECT 30.270 6.720 30.575 7.180 ;
        RECT 30.745 6.470 30.995 7.000 ;
        RECT 29.705 6.270 30.030 6.445 ;
        RECT 29.705 5.970 30.620 6.270 ;
        RECT 29.880 5.940 30.620 5.970 ;
        RECT 27.355 5.610 28.030 5.770 ;
        RECT 28.490 5.690 28.660 5.780 ;
        RECT 27.355 5.600 28.320 5.610 ;
        RECT 26.995 5.430 27.165 5.570 ;
        RECT 23.740 4.630 23.990 5.090 ;
        RECT 24.160 4.800 24.410 5.130 ;
        RECT 24.625 4.800 25.305 5.130 ;
        RECT 25.475 5.230 26.550 5.400 ;
        RECT 26.995 5.260 27.555 5.430 ;
        RECT 27.860 5.310 28.320 5.600 ;
        RECT 28.490 5.520 29.710 5.690 ;
        RECT 25.475 4.890 25.645 5.230 ;
        RECT 25.880 4.630 26.210 5.060 ;
        RECT 26.380 4.890 26.550 5.230 ;
        RECT 26.845 4.630 27.215 5.090 ;
        RECT 27.385 4.800 27.555 5.260 ;
        RECT 28.490 5.140 28.660 5.520 ;
        RECT 29.880 5.350 30.050 5.940 ;
        RECT 30.790 5.820 30.995 6.470 ;
        RECT 31.165 6.425 31.415 7.180 ;
        RECT 31.635 6.440 32.020 7.010 ;
        RECT 32.190 6.720 32.515 7.180 ;
        RECT 33.035 6.550 33.315 7.010 ;
        RECT 27.790 4.800 28.660 5.140 ;
        RECT 29.250 5.180 30.050 5.350 ;
        RECT 28.830 4.630 29.080 5.090 ;
        RECT 29.250 4.890 29.420 5.180 ;
        RECT 29.600 4.630 29.930 5.010 ;
        RECT 30.270 4.630 30.575 5.770 ;
        RECT 30.745 4.940 30.995 5.820 ;
        RECT 31.635 5.770 31.915 6.440 ;
        RECT 32.190 6.380 33.315 6.550 ;
        RECT 32.190 6.270 32.640 6.380 ;
        RECT 32.085 5.940 32.640 6.270 ;
        RECT 33.505 6.210 33.905 7.010 ;
        RECT 34.305 6.720 34.575 7.180 ;
        RECT 34.745 6.550 35.030 7.010 ;
        RECT 35.555 6.710 35.725 7.180 ;
        RECT 36.395 6.710 36.565 7.180 ;
        RECT 36.830 6.790 38.060 7.010 ;
        RECT 31.165 4.630 31.415 5.770 ;
        RECT 31.635 4.800 32.020 5.770 ;
        RECT 32.190 5.480 32.640 5.940 ;
        RECT 32.810 5.650 33.905 6.210 ;
        RECT 32.190 5.260 33.315 5.480 ;
        RECT 32.190 4.630 32.515 5.090 ;
        RECT 33.035 4.800 33.315 5.260 ;
        RECT 33.505 4.800 33.905 5.650 ;
        RECT 34.075 6.380 35.030 6.550 ;
        RECT 35.895 6.540 36.225 6.620 ;
        RECT 37.255 6.540 37.585 6.620 ;
        RECT 34.075 5.480 34.285 6.380 ;
        RECT 35.315 6.360 37.585 6.540 ;
        RECT 37.810 6.540 38.060 6.790 ;
        RECT 38.230 6.710 38.400 7.180 ;
        RECT 38.570 6.540 38.900 7.010 ;
        RECT 39.170 6.710 39.340 7.180 ;
        RECT 37.810 6.360 38.900 6.540 ;
        RECT 39.510 6.540 39.840 7.010 ;
        RECT 40.010 6.710 40.180 7.180 ;
        RECT 40.350 6.540 40.680 7.010 ;
        RECT 40.850 6.710 41.020 7.180 ;
        RECT 39.510 6.360 41.090 6.540 ;
        RECT 41.295 6.455 41.585 7.180 ;
        RECT 34.455 5.650 35.145 6.210 ;
        RECT 35.315 5.850 35.725 6.360 ;
        RECT 35.935 6.020 36.595 6.190 ;
        RECT 35.315 5.640 36.185 5.850 ;
        RECT 36.425 5.820 36.595 6.020 ;
        RECT 37.120 5.990 37.790 6.190 ;
        RECT 37.980 5.990 39.500 6.190 ;
        RECT 39.670 5.990 40.165 6.190 ;
        RECT 40.335 5.990 40.665 6.190 ;
        RECT 39.330 5.820 39.500 5.990 ;
        RECT 40.335 5.820 40.505 5.990 ;
        RECT 36.425 5.650 39.160 5.820 ;
        RECT 39.330 5.650 40.505 5.820 ;
        RECT 34.075 5.260 35.030 5.480 ;
        RECT 34.305 4.630 34.575 5.090 ;
        RECT 34.745 4.800 35.030 5.260 ;
        RECT 35.515 4.970 35.765 5.470 ;
        RECT 35.935 5.140 36.185 5.640 ;
        RECT 38.990 5.480 39.160 5.650 ;
        RECT 40.920 5.480 41.090 6.360 ;
        RECT 41.755 6.430 42.965 7.180 ;
        RECT 43.135 6.430 44.345 7.180 ;
        RECT 41.755 5.890 42.275 6.430 ;
        RECT 36.355 5.310 38.820 5.480 ;
        RECT 38.990 5.310 41.090 5.480 ;
        RECT 36.355 4.970 37.125 5.310 ;
        RECT 35.515 4.800 37.125 4.970 ;
        RECT 37.295 4.630 37.600 5.130 ;
        RECT 37.770 4.800 38.020 5.310 ;
        RECT 38.610 5.140 38.820 5.310 ;
        RECT 39.550 5.140 39.800 5.310 ;
        RECT 38.190 4.630 38.440 5.130 ;
        RECT 38.610 4.800 38.925 5.140 ;
        RECT 39.975 5.130 40.145 5.140 ;
        RECT 40.895 5.130 41.065 5.140 ;
        RECT 39.130 4.970 39.380 5.130 ;
        RECT 39.970 4.970 40.220 5.130 ;
        RECT 39.130 4.800 40.220 4.970 ;
        RECT 40.390 4.630 40.640 5.130 ;
        RECT 40.810 4.800 41.090 5.130 ;
        RECT 41.295 4.630 41.585 5.795 ;
        RECT 42.445 5.720 42.965 6.260 ;
        RECT 43.135 5.890 43.655 6.430 ;
        RECT 44.980 6.360 45.255 7.180 ;
        RECT 45.425 6.540 45.755 7.010 ;
        RECT 45.925 6.710 46.095 7.180 ;
        RECT 46.265 6.540 46.595 7.010 ;
        RECT 46.765 6.710 47.055 7.180 ;
        RECT 45.425 6.530 46.595 6.540 ;
        RECT 47.275 6.625 47.855 7.010 ;
        RECT 48.025 6.700 48.630 7.180 ;
        RECT 45.425 6.500 47.025 6.530 ;
        RECT 45.425 6.360 47.045 6.500 ;
        RECT 46.810 6.330 47.045 6.360 ;
        RECT 43.825 5.720 44.345 6.260 ;
        RECT 44.980 5.990 45.700 6.190 ;
        RECT 45.870 5.990 46.640 6.190 ;
        RECT 46.810 5.820 47.025 6.330 ;
        RECT 41.755 4.630 42.965 5.720 ;
        RECT 43.135 4.630 44.345 5.720 ;
        RECT 44.980 5.600 46.095 5.810 ;
        RECT 44.980 4.800 45.255 5.600 ;
        RECT 45.425 4.630 45.755 5.430 ;
        RECT 45.925 4.970 46.095 5.600 ;
        RECT 46.265 5.600 47.025 5.820 ;
        RECT 47.275 5.700 47.640 6.625 ;
        RECT 48.805 6.530 49.055 7.010 ;
        RECT 48.105 6.360 49.055 6.530 ;
        RECT 49.225 6.410 49.695 7.010 ;
        RECT 49.960 6.700 50.290 7.180 ;
        RECT 50.460 6.530 50.785 7.010 ;
        RECT 48.105 6.275 48.275 6.360 ;
        RECT 47.820 5.940 48.275 6.275 ;
        RECT 49.225 6.190 49.400 6.410 ;
        RECT 49.865 6.360 50.785 6.530 ;
        RECT 50.965 6.460 51.295 7.180 ;
        RECT 51.465 6.510 51.635 6.970 ;
        RECT 51.805 6.800 52.135 7.180 ;
        RECT 52.365 6.630 52.575 7.010 ;
        RECT 52.745 6.800 53.075 7.180 ;
        RECT 53.245 6.800 54.915 6.970 ;
        RECT 53.245 6.630 53.415 6.800 ;
        RECT 49.865 6.240 50.215 6.360 ;
        RECT 48.450 6.015 49.400 6.190 ;
        RECT 48.105 5.770 48.275 5.940 ;
        RECT 46.265 5.140 46.595 5.600 ;
        RECT 46.765 4.970 47.065 5.430 ;
        RECT 45.925 4.800 47.065 4.970 ;
        RECT 47.275 4.800 47.835 5.700 ;
        RECT 48.105 5.600 49.055 5.770 ;
        RECT 48.025 4.630 48.635 5.430 ;
        RECT 48.805 4.800 49.055 5.600 ;
        RECT 49.225 5.475 49.400 6.015 ;
        RECT 49.765 5.970 50.215 6.240 ;
        RECT 49.865 5.775 50.215 5.970 ;
        RECT 50.385 5.945 50.785 6.190 ;
        RECT 49.865 5.605 50.785 5.775 ;
        RECT 49.225 4.800 49.675 5.475 ;
        RECT 49.945 4.630 50.270 5.435 ;
        RECT 50.440 4.800 50.785 5.605 ;
        RECT 50.965 4.630 51.295 5.770 ;
        RECT 51.465 4.800 51.655 6.510 ;
        RECT 51.850 6.460 53.415 6.630 ;
        RECT 51.850 5.770 52.020 6.460 ;
        RECT 52.270 5.970 52.600 6.190 ;
        RECT 52.870 6.160 53.205 6.270 ;
        RECT 52.855 5.990 53.205 6.160 ;
        RECT 51.850 5.600 52.655 5.770 ;
        RECT 52.870 5.640 53.205 5.990 ;
        RECT 53.555 5.830 53.725 6.270 ;
        RECT 54.205 6.190 54.420 6.520 ;
        RECT 53.955 6.020 54.420 6.190 ;
        RECT 53.555 5.640 53.960 5.830 ;
        RECT 54.205 5.640 54.420 6.020 ;
        RECT 54.655 5.640 54.875 6.535 ;
        RECT 55.095 6.430 56.305 7.180 ;
        RECT 56.475 6.670 56.780 7.180 ;
        RECT 55.095 5.890 55.615 6.430 ;
        RECT 55.785 5.720 56.305 6.260 ;
        RECT 56.475 5.940 56.790 6.500 ;
        RECT 56.960 6.190 57.210 7.000 ;
        RECT 57.380 6.655 57.640 7.180 ;
        RECT 57.820 6.190 58.070 7.000 ;
        RECT 58.240 6.620 58.500 7.180 ;
        RECT 58.670 6.530 58.930 6.985 ;
        RECT 59.100 6.700 59.360 7.180 ;
        RECT 59.530 6.530 59.790 6.985 ;
        RECT 59.960 6.700 60.220 7.180 ;
        RECT 60.390 6.530 60.650 6.985 ;
        RECT 60.820 6.700 61.065 7.180 ;
        RECT 61.235 6.530 61.510 6.985 ;
        RECT 61.680 6.700 61.925 7.180 ;
        RECT 62.095 6.530 62.355 6.985 ;
        RECT 62.535 6.700 62.785 7.180 ;
        RECT 62.955 6.530 63.215 6.985 ;
        RECT 63.395 6.700 63.645 7.180 ;
        RECT 63.815 6.530 64.075 6.985 ;
        RECT 64.255 6.700 64.515 7.180 ;
        RECT 64.685 6.530 64.945 6.985 ;
        RECT 65.115 6.700 65.415 7.180 ;
        RECT 58.670 6.360 65.415 6.530 ;
        RECT 56.960 5.940 64.080 6.190 ;
        RECT 51.885 4.630 52.135 5.430 ;
        RECT 52.325 4.840 52.655 5.600 ;
        RECT 52.825 5.300 54.835 5.470 ;
        RECT 52.825 4.800 52.995 5.300 ;
        RECT 53.205 4.630 53.455 5.090 ;
        RECT 53.665 4.800 53.835 5.300 ;
        RECT 54.205 4.630 54.455 5.090 ;
        RECT 54.665 4.800 54.835 5.300 ;
        RECT 55.095 4.630 56.305 5.720 ;
        RECT 56.485 4.630 56.780 5.440 ;
        RECT 56.960 4.800 57.205 5.940 ;
        RECT 57.380 4.630 57.640 5.440 ;
        RECT 57.820 4.805 58.070 5.940 ;
        RECT 64.250 5.820 65.415 6.360 ;
        RECT 65.675 6.430 66.885 7.180 ;
        RECT 67.055 6.455 67.345 7.180 ;
        RECT 65.675 5.890 66.195 6.430 ;
        RECT 67.520 6.360 67.795 7.180 ;
        RECT 67.965 6.540 68.295 7.010 ;
        RECT 68.465 6.710 68.635 7.180 ;
        RECT 68.805 6.540 69.135 7.010 ;
        RECT 69.305 6.710 69.595 7.180 ;
        RECT 67.965 6.530 69.135 6.540 ;
        RECT 70.740 6.630 70.995 6.920 ;
        RECT 71.165 6.800 71.495 7.180 ;
        RECT 67.965 6.360 69.565 6.530 ;
        RECT 70.740 6.460 71.490 6.630 ;
        RECT 64.250 5.770 65.445 5.820 ;
        RECT 58.670 5.650 65.445 5.770 ;
        RECT 66.365 5.720 66.885 6.260 ;
        RECT 67.520 5.990 68.240 6.190 ;
        RECT 68.410 5.990 69.180 6.190 ;
        RECT 69.350 5.820 69.565 6.360 ;
        RECT 58.670 5.545 65.415 5.650 ;
        RECT 58.670 5.530 64.075 5.545 ;
        RECT 58.240 4.635 58.500 5.430 ;
        RECT 58.670 4.805 58.930 5.530 ;
        RECT 59.100 4.635 59.360 5.360 ;
        RECT 59.530 4.805 59.790 5.530 ;
        RECT 59.960 4.635 60.220 5.360 ;
        RECT 60.390 4.805 60.650 5.530 ;
        RECT 60.820 4.635 61.080 5.360 ;
        RECT 61.250 4.805 61.510 5.530 ;
        RECT 61.680 4.635 61.925 5.360 ;
        RECT 62.095 4.805 62.355 5.530 ;
        RECT 62.540 4.635 62.785 5.360 ;
        RECT 62.955 4.805 63.215 5.530 ;
        RECT 63.400 4.635 63.645 5.360 ;
        RECT 63.815 4.805 64.075 5.530 ;
        RECT 64.260 4.635 64.515 5.360 ;
        RECT 64.685 4.805 64.975 5.545 ;
        RECT 58.240 4.630 64.515 4.635 ;
        RECT 65.145 4.630 65.415 5.375 ;
        RECT 65.675 4.630 66.885 5.720 ;
        RECT 67.055 4.630 67.345 5.795 ;
        RECT 67.520 5.600 68.635 5.810 ;
        RECT 67.520 4.800 67.795 5.600 ;
        RECT 67.965 4.630 68.295 5.430 ;
        RECT 68.465 4.970 68.635 5.600 ;
        RECT 68.805 5.600 69.565 5.820 ;
        RECT 70.740 5.640 71.090 6.290 ;
        RECT 68.805 5.140 69.135 5.600 ;
        RECT 71.260 5.470 71.490 6.460 ;
        RECT 69.305 4.970 69.605 5.430 ;
        RECT 68.465 4.800 69.605 4.970 ;
        RECT 70.740 5.300 71.490 5.470 ;
        RECT 70.740 4.800 70.995 5.300 ;
        RECT 71.165 4.630 71.495 5.130 ;
        RECT 71.665 4.800 71.835 6.920 ;
        RECT 72.195 6.820 72.525 7.180 ;
        RECT 72.695 6.790 73.190 6.960 ;
        RECT 73.395 6.790 74.250 6.960 ;
        RECT 72.065 5.600 72.525 6.650 ;
        RECT 72.005 4.815 72.330 5.600 ;
        RECT 72.695 5.430 72.865 6.790 ;
        RECT 73.035 5.880 73.385 6.500 ;
        RECT 73.555 6.280 73.910 6.500 ;
        RECT 73.555 5.690 73.725 6.280 ;
        RECT 74.080 6.080 74.250 6.790 ;
        RECT 75.125 6.720 75.455 7.180 ;
        RECT 75.665 6.820 76.015 6.990 ;
        RECT 74.455 6.250 75.245 6.500 ;
        RECT 75.665 6.430 75.925 6.820 ;
        RECT 76.235 6.730 77.185 7.010 ;
        RECT 77.355 6.740 77.545 7.180 ;
        RECT 77.715 6.800 78.785 6.970 ;
        RECT 75.415 6.080 75.585 6.260 ;
        RECT 72.695 5.260 73.090 5.430 ;
        RECT 73.260 5.300 73.725 5.690 ;
        RECT 73.895 5.910 75.585 6.080 ;
        RECT 72.920 5.130 73.090 5.260 ;
        RECT 73.895 5.130 74.065 5.910 ;
        RECT 75.755 5.740 75.925 6.430 ;
        RECT 74.425 5.570 75.925 5.740 ;
        RECT 76.115 5.770 76.325 6.560 ;
        RECT 76.495 5.940 76.845 6.560 ;
        RECT 77.015 5.950 77.185 6.730 ;
        RECT 77.715 6.570 77.885 6.800 ;
        RECT 77.355 6.400 77.885 6.570 ;
        RECT 77.355 6.120 77.575 6.400 ;
        RECT 78.055 6.230 78.295 6.630 ;
        RECT 77.015 5.780 77.420 5.950 ;
        RECT 77.755 5.860 78.295 6.230 ;
        RECT 78.465 6.445 78.785 6.800 ;
        RECT 79.030 6.720 79.335 7.180 ;
        RECT 79.505 6.470 79.755 7.000 ;
        RECT 78.465 6.270 78.790 6.445 ;
        RECT 78.465 5.970 79.380 6.270 ;
        RECT 78.640 5.940 79.380 5.970 ;
        RECT 76.115 5.610 76.790 5.770 ;
        RECT 77.250 5.690 77.420 5.780 ;
        RECT 76.115 5.600 77.080 5.610 ;
        RECT 75.755 5.430 75.925 5.570 ;
        RECT 72.500 4.630 72.750 5.090 ;
        RECT 72.920 4.800 73.170 5.130 ;
        RECT 73.385 4.800 74.065 5.130 ;
        RECT 74.235 5.230 75.310 5.400 ;
        RECT 75.755 5.260 76.315 5.430 ;
        RECT 76.620 5.310 77.080 5.600 ;
        RECT 77.250 5.520 78.470 5.690 ;
        RECT 74.235 4.890 74.405 5.230 ;
        RECT 74.640 4.630 74.970 5.060 ;
        RECT 75.140 4.890 75.310 5.230 ;
        RECT 75.605 4.630 75.975 5.090 ;
        RECT 76.145 4.800 76.315 5.260 ;
        RECT 77.250 5.140 77.420 5.520 ;
        RECT 78.640 5.350 78.810 5.940 ;
        RECT 79.550 5.820 79.755 6.470 ;
        RECT 79.925 6.425 80.175 7.180 ;
        RECT 80.855 6.430 82.065 7.180 ;
        RECT 76.550 4.800 77.420 5.140 ;
        RECT 78.010 5.180 78.810 5.350 ;
        RECT 77.590 4.630 77.840 5.090 ;
        RECT 78.010 4.890 78.180 5.180 ;
        RECT 78.360 4.630 78.690 5.010 ;
        RECT 79.030 4.630 79.335 5.770 ;
        RECT 79.505 4.940 79.755 5.820 ;
        RECT 79.925 4.630 80.175 5.770 ;
        RECT 80.855 5.720 81.375 6.260 ;
        RECT 81.545 5.890 82.065 6.430 ;
        RECT 80.855 4.630 82.065 5.720 ;
        RECT 15.450 4.460 82.150 4.630 ;
        RECT 15.535 3.370 16.745 4.460 ;
        RECT 16.915 3.370 18.125 4.460 ;
        RECT 18.755 3.610 19.020 4.460 ;
        RECT 19.190 3.440 19.520 4.285 ;
        RECT 15.535 2.660 16.055 3.200 ;
        RECT 16.225 2.830 16.745 3.370 ;
        RECT 16.915 2.660 17.435 3.200 ;
        RECT 17.605 2.830 18.125 3.370 ;
        RECT 18.755 3.320 19.520 3.440 ;
        RECT 19.690 3.320 19.860 4.460 ;
        RECT 20.030 3.740 20.360 4.250 ;
        RECT 18.755 3.270 19.355 3.320 ;
        RECT 18.755 2.720 19.310 3.270 ;
        RECT 20.030 3.150 20.280 3.740 ;
        RECT 20.650 3.590 20.820 4.200 ;
        RECT 20.990 3.770 21.320 4.460 ;
        RECT 21.550 3.910 21.790 4.200 ;
        RECT 21.990 4.080 22.410 4.460 ;
        RECT 22.590 3.990 23.220 4.240 ;
        RECT 23.670 4.080 24.000 4.460 ;
        RECT 22.590 3.910 22.760 3.990 ;
        RECT 24.170 3.910 24.340 4.200 ;
        RECT 24.520 4.080 24.900 4.460 ;
        RECT 25.140 4.075 25.970 4.245 ;
        RECT 21.550 3.740 22.760 3.910 ;
        RECT 19.480 2.820 20.280 3.150 ;
        RECT 18.755 2.680 19.340 2.720 ;
        RECT 15.535 1.910 16.745 2.660 ;
        RECT 16.915 1.910 18.125 2.660 ;
        RECT 18.755 2.650 19.355 2.680 ;
        RECT 18.755 2.590 19.440 2.650 ;
        RECT 18.755 1.910 19.025 2.420 ;
        RECT 19.195 2.090 19.440 2.590 ;
        RECT 19.610 1.910 19.940 2.650 ;
        RECT 20.110 2.170 20.280 2.820 ;
        RECT 20.450 3.570 20.820 3.590 ;
        RECT 20.450 3.400 22.420 3.570 ;
        RECT 20.450 2.505 20.640 3.400 ;
        RECT 22.590 3.230 22.760 3.740 ;
        RECT 22.930 3.480 23.450 3.790 ;
        RECT 20.840 3.060 22.760 3.230 ;
        RECT 20.840 3.000 21.190 3.060 ;
        RECT 21.320 2.830 21.670 2.890 ;
        RECT 20.990 2.560 21.670 2.830 ;
        RECT 20.450 2.175 20.800 2.505 ;
        RECT 21.000 1.910 21.640 2.390 ;
        RECT 21.840 2.300 22.010 3.060 ;
        RECT 22.930 2.890 23.110 3.300 ;
        RECT 22.180 2.720 22.530 2.840 ;
        RECT 23.280 2.720 23.450 3.480 ;
        RECT 22.180 2.550 23.450 2.720 ;
        RECT 23.620 3.660 24.970 3.910 ;
        RECT 23.620 2.890 23.790 3.660 ;
        RECT 24.720 3.400 24.970 3.660 ;
        RECT 23.960 3.230 24.210 3.390 ;
        RECT 25.140 3.230 25.310 4.075 ;
        RECT 26.205 3.790 26.375 4.290 ;
        RECT 26.545 3.960 26.875 4.460 ;
        RECT 27.095 3.870 27.315 4.290 ;
        RECT 27.485 3.960 27.815 4.460 ;
        RECT 25.480 3.400 25.980 3.780 ;
        RECT 26.205 3.620 26.900 3.790 ;
        RECT 23.960 3.060 25.310 3.230 ;
        RECT 24.890 3.020 25.310 3.060 ;
        RECT 23.620 2.550 24.020 2.890 ;
        RECT 24.310 2.560 24.720 2.890 ;
        RECT 21.840 2.130 22.690 2.300 ;
        RECT 23.250 1.910 23.570 2.370 ;
        RECT 23.770 2.120 24.020 2.550 ;
        RECT 24.310 1.910 24.720 2.350 ;
        RECT 24.890 2.290 25.060 3.020 ;
        RECT 25.230 2.470 25.580 2.840 ;
        RECT 25.760 2.530 25.980 3.400 ;
        RECT 26.150 2.830 26.560 3.450 ;
        RECT 26.730 2.650 26.900 3.620 ;
        RECT 26.205 2.460 26.900 2.650 ;
        RECT 24.890 2.090 25.905 2.290 ;
        RECT 26.205 2.130 26.375 2.460 ;
        RECT 27.095 2.390 27.325 3.870 ;
        RECT 27.985 3.790 28.245 4.290 ;
        RECT 27.495 3.620 28.245 3.790 ;
        RECT 27.495 2.630 27.725 3.620 ;
        RECT 27.895 2.800 28.245 3.450 ;
        RECT 28.415 3.295 28.705 4.460 ;
        RECT 28.875 3.320 29.260 4.290 ;
        RECT 29.430 4.000 29.755 4.460 ;
        RECT 30.275 3.830 30.555 4.290 ;
        RECT 29.430 3.610 30.555 3.830 ;
        RECT 28.875 2.650 29.155 3.320 ;
        RECT 29.430 3.150 29.880 3.610 ;
        RECT 30.745 3.440 31.145 4.290 ;
        RECT 31.545 4.000 31.815 4.460 ;
        RECT 31.985 3.830 32.270 4.290 ;
        RECT 29.325 2.820 29.880 3.150 ;
        RECT 30.050 2.880 31.145 3.440 ;
        RECT 29.430 2.710 29.880 2.820 ;
        RECT 27.495 2.460 28.245 2.630 ;
        RECT 26.545 1.910 26.875 2.290 ;
        RECT 27.095 2.170 27.315 2.390 ;
        RECT 27.485 1.910 27.815 2.290 ;
        RECT 27.985 2.170 28.245 2.460 ;
        RECT 28.415 1.910 28.705 2.635 ;
        RECT 28.875 2.080 29.260 2.650 ;
        RECT 29.430 2.540 30.555 2.710 ;
        RECT 29.430 1.910 29.755 2.370 ;
        RECT 30.275 2.080 30.555 2.540 ;
        RECT 30.745 2.080 31.145 2.880 ;
        RECT 31.315 3.610 32.270 3.830 ;
        RECT 33.480 3.790 33.735 4.290 ;
        RECT 33.905 3.960 34.235 4.460 ;
        RECT 33.480 3.620 34.230 3.790 ;
        RECT 31.315 2.710 31.525 3.610 ;
        RECT 31.695 2.880 32.385 3.440 ;
        RECT 33.480 2.800 33.830 3.450 ;
        RECT 31.315 2.540 32.270 2.710 ;
        RECT 34.000 2.630 34.230 3.620 ;
        RECT 31.545 1.910 31.815 2.370 ;
        RECT 31.985 2.080 32.270 2.540 ;
        RECT 33.480 2.460 34.230 2.630 ;
        RECT 33.480 2.170 33.735 2.460 ;
        RECT 33.905 1.910 34.235 2.290 ;
        RECT 34.405 2.170 34.575 4.290 ;
        RECT 34.745 3.490 35.070 4.275 ;
        RECT 35.240 4.000 35.490 4.460 ;
        RECT 35.660 3.960 35.910 4.290 ;
        RECT 36.125 3.960 36.805 4.290 ;
        RECT 35.660 3.830 35.830 3.960 ;
        RECT 35.435 3.660 35.830 3.830 ;
        RECT 34.805 2.440 35.265 3.490 ;
        RECT 35.435 2.300 35.605 3.660 ;
        RECT 36.000 3.400 36.465 3.790 ;
        RECT 35.775 2.590 36.125 3.210 ;
        RECT 36.295 2.810 36.465 3.400 ;
        RECT 36.635 3.180 36.805 3.960 ;
        RECT 36.975 3.860 37.145 4.200 ;
        RECT 37.380 4.030 37.710 4.460 ;
        RECT 37.880 3.860 38.050 4.200 ;
        RECT 38.345 4.000 38.715 4.460 ;
        RECT 36.975 3.690 38.050 3.860 ;
        RECT 38.885 3.830 39.055 4.290 ;
        RECT 39.290 3.950 40.160 4.290 ;
        RECT 40.330 4.000 40.580 4.460 ;
        RECT 38.495 3.660 39.055 3.830 ;
        RECT 38.495 3.520 38.665 3.660 ;
        RECT 37.165 3.350 38.665 3.520 ;
        RECT 39.360 3.490 39.820 3.780 ;
        RECT 36.635 3.010 38.325 3.180 ;
        RECT 36.295 2.590 36.650 2.810 ;
        RECT 36.820 2.300 36.990 3.010 ;
        RECT 37.195 2.590 37.985 2.840 ;
        RECT 38.155 2.830 38.325 3.010 ;
        RECT 38.495 2.660 38.665 3.350 ;
        RECT 34.935 1.910 35.265 2.270 ;
        RECT 35.435 2.130 35.930 2.300 ;
        RECT 36.135 2.130 36.990 2.300 ;
        RECT 37.865 1.910 38.195 2.370 ;
        RECT 38.405 2.270 38.665 2.660 ;
        RECT 38.855 3.480 39.820 3.490 ;
        RECT 39.990 3.570 40.160 3.950 ;
        RECT 40.750 3.910 40.920 4.200 ;
        RECT 41.100 4.080 41.430 4.460 ;
        RECT 40.750 3.740 41.550 3.910 ;
        RECT 38.855 3.320 39.530 3.480 ;
        RECT 39.990 3.400 41.210 3.570 ;
        RECT 38.855 2.530 39.065 3.320 ;
        RECT 39.990 3.310 40.160 3.400 ;
        RECT 39.235 2.530 39.585 3.150 ;
        RECT 39.755 3.140 40.160 3.310 ;
        RECT 39.755 2.360 39.925 3.140 ;
        RECT 40.095 2.690 40.315 2.970 ;
        RECT 40.495 2.860 41.035 3.230 ;
        RECT 41.380 3.150 41.550 3.740 ;
        RECT 41.770 3.320 42.075 4.460 ;
        RECT 42.245 3.270 42.495 4.150 ;
        RECT 42.665 3.320 42.915 4.460 ;
        RECT 43.600 3.790 43.855 4.290 ;
        RECT 44.025 3.960 44.355 4.460 ;
        RECT 43.600 3.620 44.350 3.790 ;
        RECT 41.380 3.120 42.120 3.150 ;
        RECT 40.095 2.520 40.625 2.690 ;
        RECT 38.405 2.100 38.755 2.270 ;
        RECT 38.975 2.080 39.925 2.360 ;
        RECT 40.095 1.910 40.285 2.350 ;
        RECT 40.455 2.290 40.625 2.520 ;
        RECT 40.795 2.460 41.035 2.860 ;
        RECT 41.205 2.820 42.120 3.120 ;
        RECT 41.205 2.645 41.530 2.820 ;
        RECT 41.205 2.290 41.525 2.645 ;
        RECT 42.290 2.620 42.495 3.270 ;
        RECT 43.600 2.800 43.950 3.450 ;
        RECT 40.455 2.120 41.525 2.290 ;
        RECT 41.770 1.910 42.075 2.370 ;
        RECT 42.245 2.090 42.495 2.620 ;
        RECT 42.665 1.910 42.915 2.665 ;
        RECT 44.120 2.630 44.350 3.620 ;
        RECT 43.600 2.460 44.350 2.630 ;
        RECT 43.600 2.170 43.855 2.460 ;
        RECT 44.025 1.910 44.355 2.290 ;
        RECT 44.525 2.170 44.695 4.290 ;
        RECT 44.865 3.490 45.190 4.275 ;
        RECT 45.360 4.000 45.610 4.460 ;
        RECT 45.780 3.960 46.030 4.290 ;
        RECT 46.245 3.960 46.925 4.290 ;
        RECT 45.780 3.830 45.950 3.960 ;
        RECT 45.555 3.660 45.950 3.830 ;
        RECT 44.925 2.440 45.385 3.490 ;
        RECT 45.555 2.300 45.725 3.660 ;
        RECT 46.120 3.400 46.585 3.790 ;
        RECT 45.895 2.590 46.245 3.210 ;
        RECT 46.415 2.810 46.585 3.400 ;
        RECT 46.755 3.180 46.925 3.960 ;
        RECT 47.095 3.860 47.265 4.200 ;
        RECT 47.500 4.030 47.830 4.460 ;
        RECT 48.000 3.860 48.170 4.200 ;
        RECT 48.465 4.000 48.835 4.460 ;
        RECT 47.095 3.690 48.170 3.860 ;
        RECT 49.005 3.830 49.175 4.290 ;
        RECT 49.410 3.950 50.280 4.290 ;
        RECT 50.450 4.000 50.700 4.460 ;
        RECT 48.615 3.660 49.175 3.830 ;
        RECT 48.615 3.520 48.785 3.660 ;
        RECT 47.285 3.350 48.785 3.520 ;
        RECT 49.480 3.490 49.940 3.780 ;
        RECT 46.755 3.010 48.445 3.180 ;
        RECT 46.415 2.590 46.770 2.810 ;
        RECT 46.940 2.300 47.110 3.010 ;
        RECT 47.315 2.590 48.105 2.840 ;
        RECT 48.275 2.830 48.445 3.010 ;
        RECT 48.615 2.660 48.785 3.350 ;
        RECT 45.055 1.910 45.385 2.270 ;
        RECT 45.555 2.130 46.050 2.300 ;
        RECT 46.255 2.130 47.110 2.300 ;
        RECT 47.985 1.910 48.315 2.370 ;
        RECT 48.525 2.270 48.785 2.660 ;
        RECT 48.975 3.480 49.940 3.490 ;
        RECT 50.110 3.570 50.280 3.950 ;
        RECT 50.870 3.910 51.040 4.200 ;
        RECT 51.220 4.080 51.550 4.460 ;
        RECT 50.870 3.740 51.670 3.910 ;
        RECT 48.975 3.320 49.650 3.480 ;
        RECT 50.110 3.400 51.330 3.570 ;
        RECT 48.975 2.530 49.185 3.320 ;
        RECT 50.110 3.310 50.280 3.400 ;
        RECT 49.355 2.530 49.705 3.150 ;
        RECT 49.875 3.140 50.280 3.310 ;
        RECT 49.875 2.360 50.045 3.140 ;
        RECT 50.215 2.690 50.435 2.970 ;
        RECT 50.615 2.860 51.155 3.230 ;
        RECT 51.500 3.150 51.670 3.740 ;
        RECT 51.890 3.320 52.195 4.460 ;
        RECT 52.365 3.270 52.615 4.150 ;
        RECT 52.785 3.320 53.035 4.460 ;
        RECT 54.175 3.295 54.465 4.460 ;
        RECT 54.655 3.660 54.985 4.460 ;
        RECT 55.160 3.320 55.495 4.290 ;
        RECT 55.665 3.660 55.995 4.460 ;
        RECT 56.395 3.490 56.645 4.290 ;
        RECT 56.830 3.740 57.160 4.460 ;
        RECT 57.380 3.490 57.630 4.290 ;
        RECT 57.805 4.080 58.135 4.460 ;
        RECT 55.675 3.320 57.730 3.490 ;
        RECT 51.500 3.120 52.240 3.150 ;
        RECT 50.215 2.520 50.745 2.690 ;
        RECT 48.525 2.100 48.875 2.270 ;
        RECT 49.095 2.080 50.045 2.360 ;
        RECT 50.215 1.910 50.405 2.350 ;
        RECT 50.575 2.290 50.745 2.520 ;
        RECT 50.915 2.460 51.155 2.860 ;
        RECT 51.325 2.820 52.240 3.120 ;
        RECT 51.325 2.645 51.650 2.820 ;
        RECT 51.325 2.290 51.645 2.645 ;
        RECT 52.410 2.620 52.615 3.270 ;
        RECT 55.160 2.760 55.335 3.320 ;
        RECT 55.675 3.140 55.900 3.320 ;
        RECT 55.505 2.900 55.900 3.140 ;
        RECT 50.575 2.120 51.645 2.290 ;
        RECT 51.890 1.910 52.195 2.370 ;
        RECT 52.365 2.090 52.615 2.620 ;
        RECT 52.785 1.910 53.035 2.665 ;
        RECT 54.175 1.910 54.465 2.635 ;
        RECT 54.645 1.910 54.975 2.635 ;
        RECT 55.155 2.630 55.335 2.760 ;
        RECT 55.155 2.590 55.495 2.630 ;
        RECT 55.160 2.165 55.495 2.590 ;
        RECT 55.165 2.120 55.495 2.165 ;
        RECT 55.665 1.910 55.900 2.715 ;
        RECT 56.070 2.240 56.330 3.150 ;
        RECT 56.640 3.130 56.810 3.150 ;
        RECT 56.510 2.240 56.810 3.130 ;
        RECT 56.985 2.245 57.340 3.150 ;
        RECT 57.560 2.410 57.730 3.320 ;
        RECT 57.900 2.580 58.105 3.900 ;
        RECT 58.315 3.490 58.625 4.290 ;
        RECT 58.795 3.660 59.105 4.460 ;
        RECT 59.275 3.830 59.535 4.290 ;
        RECT 59.705 4.000 59.960 4.460 ;
        RECT 60.135 3.830 60.395 4.290 ;
        RECT 59.275 3.660 60.395 3.830 ;
        RECT 58.315 3.320 59.345 3.490 ;
        RECT 58.315 2.410 58.485 3.320 ;
        RECT 58.655 2.580 59.005 3.150 ;
        RECT 59.175 3.070 59.345 3.320 ;
        RECT 60.135 3.410 60.395 3.660 ;
        RECT 60.565 3.590 60.850 4.460 ;
        RECT 61.080 3.790 61.335 4.290 ;
        RECT 61.505 3.960 61.835 4.460 ;
        RECT 61.080 3.620 61.830 3.790 ;
        RECT 60.135 3.240 60.890 3.410 ;
        RECT 59.175 2.900 60.315 3.070 ;
        RECT 60.485 2.730 60.890 3.240 ;
        RECT 61.080 2.800 61.430 3.450 ;
        RECT 59.240 2.560 60.890 2.730 ;
        RECT 61.600 2.630 61.830 3.620 ;
        RECT 57.560 2.080 58.055 2.410 ;
        RECT 58.315 2.080 58.615 2.410 ;
        RECT 58.785 1.910 59.060 2.390 ;
        RECT 59.240 2.170 59.535 2.560 ;
        RECT 59.705 1.910 59.960 2.390 ;
        RECT 60.135 2.170 60.395 2.560 ;
        RECT 61.080 2.460 61.830 2.630 ;
        RECT 60.565 1.910 60.845 2.390 ;
        RECT 61.080 2.170 61.335 2.460 ;
        RECT 61.505 1.910 61.835 2.290 ;
        RECT 62.005 2.170 62.175 4.290 ;
        RECT 62.345 3.490 62.670 4.275 ;
        RECT 62.840 4.000 63.090 4.460 ;
        RECT 63.260 3.960 63.510 4.290 ;
        RECT 63.725 3.960 64.405 4.290 ;
        RECT 63.260 3.830 63.430 3.960 ;
        RECT 63.035 3.660 63.430 3.830 ;
        RECT 62.405 2.440 62.865 3.490 ;
        RECT 63.035 2.300 63.205 3.660 ;
        RECT 63.600 3.400 64.065 3.790 ;
        RECT 63.375 2.590 63.725 3.210 ;
        RECT 63.895 2.810 64.065 3.400 ;
        RECT 64.235 3.180 64.405 3.960 ;
        RECT 64.575 3.860 64.745 4.200 ;
        RECT 64.980 4.030 65.310 4.460 ;
        RECT 65.480 3.860 65.650 4.200 ;
        RECT 65.945 4.000 66.315 4.460 ;
        RECT 64.575 3.690 65.650 3.860 ;
        RECT 66.485 3.830 66.655 4.290 ;
        RECT 66.890 3.950 67.760 4.290 ;
        RECT 67.930 4.000 68.180 4.460 ;
        RECT 66.095 3.660 66.655 3.830 ;
        RECT 66.095 3.520 66.265 3.660 ;
        RECT 64.765 3.350 66.265 3.520 ;
        RECT 66.960 3.490 67.420 3.780 ;
        RECT 64.235 3.010 65.925 3.180 ;
        RECT 63.895 2.590 64.250 2.810 ;
        RECT 64.420 2.300 64.590 3.010 ;
        RECT 64.795 2.590 65.585 2.840 ;
        RECT 65.755 2.830 65.925 3.010 ;
        RECT 66.095 2.660 66.265 3.350 ;
        RECT 62.535 1.910 62.865 2.270 ;
        RECT 63.035 2.130 63.530 2.300 ;
        RECT 63.735 2.130 64.590 2.300 ;
        RECT 65.465 1.910 65.795 2.370 ;
        RECT 66.005 2.270 66.265 2.660 ;
        RECT 66.455 3.480 67.420 3.490 ;
        RECT 67.590 3.570 67.760 3.950 ;
        RECT 68.350 3.910 68.520 4.200 ;
        RECT 68.700 4.080 69.030 4.460 ;
        RECT 68.350 3.740 69.150 3.910 ;
        RECT 66.455 3.320 67.130 3.480 ;
        RECT 67.590 3.400 68.810 3.570 ;
        RECT 66.455 2.530 66.665 3.320 ;
        RECT 67.590 3.310 67.760 3.400 ;
        RECT 66.835 2.530 67.185 3.150 ;
        RECT 67.355 3.140 67.760 3.310 ;
        RECT 67.355 2.360 67.525 3.140 ;
        RECT 67.695 2.690 67.915 2.970 ;
        RECT 68.095 2.860 68.635 3.230 ;
        RECT 68.980 3.150 69.150 3.740 ;
        RECT 69.370 3.320 69.675 4.460 ;
        RECT 69.845 3.270 70.095 4.150 ;
        RECT 70.265 3.320 70.515 4.460 ;
        RECT 70.735 3.370 71.945 4.460 ;
        RECT 68.980 3.120 69.720 3.150 ;
        RECT 67.695 2.520 68.225 2.690 ;
        RECT 66.005 2.100 66.355 2.270 ;
        RECT 66.575 2.080 67.525 2.360 ;
        RECT 67.695 1.910 67.885 2.350 ;
        RECT 68.055 2.290 68.225 2.520 ;
        RECT 68.395 2.460 68.635 2.860 ;
        RECT 68.805 2.820 69.720 3.120 ;
        RECT 68.805 2.645 69.130 2.820 ;
        RECT 68.805 2.290 69.125 2.645 ;
        RECT 69.890 2.620 70.095 3.270 ;
        RECT 68.055 2.120 69.125 2.290 ;
        RECT 69.370 1.910 69.675 2.370 ;
        RECT 69.845 2.090 70.095 2.620 ;
        RECT 70.265 1.910 70.515 2.665 ;
        RECT 70.735 2.660 71.255 3.200 ;
        RECT 71.425 2.830 71.945 3.370 ;
        RECT 72.575 3.390 73.135 4.290 ;
        RECT 73.325 3.660 73.935 4.460 ;
        RECT 74.105 3.490 74.355 4.290 ;
        RECT 70.735 1.910 71.945 2.660 ;
        RECT 72.575 2.465 72.940 3.390 ;
        RECT 73.405 3.320 74.355 3.490 ;
        RECT 74.525 3.615 74.975 4.290 ;
        RECT 75.245 3.655 75.570 4.460 ;
        RECT 73.405 3.150 73.575 3.320 ;
        RECT 73.120 2.815 73.575 3.150 ;
        RECT 74.525 3.075 74.700 3.615 ;
        RECT 75.740 3.485 76.085 4.290 ;
        RECT 75.165 3.315 76.085 3.485 ;
        RECT 76.255 3.320 76.640 4.290 ;
        RECT 76.810 4.000 77.135 4.460 ;
        RECT 77.655 3.830 77.935 4.290 ;
        RECT 76.810 3.610 77.935 3.830 ;
        RECT 75.165 3.120 75.515 3.315 ;
        RECT 73.750 2.900 74.700 3.075 ;
        RECT 73.405 2.730 73.575 2.815 ;
        RECT 73.405 2.560 74.355 2.730 ;
        RECT 72.575 2.080 73.155 2.465 ;
        RECT 73.325 1.910 73.930 2.390 ;
        RECT 74.105 2.080 74.355 2.560 ;
        RECT 74.525 2.680 74.700 2.900 ;
        RECT 75.065 2.850 75.515 3.120 ;
        RECT 75.685 2.900 76.085 3.145 ;
        RECT 75.165 2.730 75.515 2.850 ;
        RECT 74.525 2.080 74.995 2.680 ;
        RECT 75.165 2.560 76.085 2.730 ;
        RECT 75.260 1.910 75.590 2.390 ;
        RECT 75.760 2.080 76.085 2.560 ;
        RECT 76.255 2.650 76.535 3.320 ;
        RECT 76.810 3.150 77.260 3.610 ;
        RECT 78.125 3.440 78.525 4.290 ;
        RECT 78.925 4.000 79.195 4.460 ;
        RECT 79.365 3.830 79.650 4.290 ;
        RECT 76.705 2.820 77.260 3.150 ;
        RECT 77.430 2.880 78.525 3.440 ;
        RECT 76.810 2.710 77.260 2.820 ;
        RECT 76.255 2.080 76.640 2.650 ;
        RECT 76.810 2.540 77.935 2.710 ;
        RECT 76.810 1.910 77.135 2.370 ;
        RECT 77.655 2.080 77.935 2.540 ;
        RECT 78.125 2.080 78.525 2.880 ;
        RECT 78.695 3.610 79.650 3.830 ;
        RECT 78.695 2.710 78.905 3.610 ;
        RECT 79.075 2.880 79.765 3.440 ;
        RECT 79.935 3.295 80.225 4.460 ;
        RECT 80.855 3.370 82.065 4.460 ;
        RECT 86.100 3.700 87.100 4.750 ;
        RECT 80.855 2.830 81.375 3.370 ;
        RECT 78.695 2.540 79.650 2.710 ;
        RECT 81.545 2.660 82.065 3.200 ;
        RECT 84.340 3.050 85.240 3.060 ;
        RECT 78.925 1.910 79.195 2.370 ;
        RECT 79.365 2.080 79.650 2.540 ;
        RECT 79.935 1.910 80.225 2.635 ;
        RECT 80.855 1.910 82.065 2.660 ;
        RECT 15.450 1.740 82.150 1.910 ;
        RECT 15.535 0.990 16.745 1.740 ;
        RECT 16.915 0.990 18.125 1.740 ;
        RECT 15.535 0.450 16.055 0.990 ;
        RECT 16.225 0.280 16.745 0.820 ;
        RECT 16.915 0.450 17.435 0.990 ;
        RECT 18.355 0.920 18.565 1.740 ;
        RECT 18.735 0.940 19.065 1.570 ;
        RECT 17.605 0.280 18.125 0.820 ;
        RECT 18.735 0.340 18.985 0.940 ;
        RECT 19.235 0.920 19.465 1.740 ;
        RECT 19.725 0.985 19.975 1.740 ;
        RECT 20.145 1.030 20.395 1.560 ;
        RECT 20.565 1.280 20.870 1.740 ;
        RECT 21.115 1.360 22.185 1.530 ;
        RECT 19.155 0.500 19.485 0.750 ;
        RECT 20.145 0.380 20.350 1.030 ;
        RECT 21.115 1.005 21.435 1.360 ;
        RECT 21.110 0.830 21.435 1.005 ;
        RECT 20.520 0.530 21.435 0.830 ;
        RECT 21.605 0.790 21.845 1.190 ;
        RECT 22.015 1.130 22.185 1.360 ;
        RECT 22.355 1.300 22.545 1.740 ;
        RECT 22.715 1.290 23.665 1.570 ;
        RECT 23.885 1.380 24.235 1.550 ;
        RECT 22.015 0.960 22.545 1.130 ;
        RECT 20.520 0.500 21.260 0.530 ;
        RECT 15.535 0.000 16.745 0.280 ;
        RECT 16.915 0.000 18.125 0.280 ;
        RECT 18.355 0.000 18.565 0.330 ;
        RECT 18.735 -0.640 19.065 0.340 ;
        RECT 19.235 0.000 19.465 0.330 ;
        RECT 19.725 0.000 19.975 0.330 ;
        RECT 20.145 -0.500 20.395 0.380 ;
        RECT 20.565 0.000 20.870 0.330 ;
        RECT 21.090 -0.090 21.260 0.500 ;
        RECT 21.605 0.420 22.145 0.790 ;
        RECT 22.325 0.680 22.545 0.960 ;
        RECT 22.715 0.510 22.885 1.290 ;
        RECT 22.480 0.340 22.885 0.510 ;
        RECT 23.055 0.500 23.405 1.120 ;
        RECT 22.480 0.250 22.650 0.340 ;
        RECT 23.575 0.330 23.785 1.120 ;
        RECT 21.430 0.080 22.650 0.250 ;
        RECT 23.110 0.170 23.785 0.330 ;
        RECT 21.090 -0.260 21.890 -0.090 ;
        RECT 21.720 -0.550 21.890 -0.260 ;
        RECT 22.480 -0.300 22.650 0.080 ;
        RECT 22.820 0.160 23.785 0.170 ;
        RECT 23.975 0.990 24.235 1.380 ;
        RECT 24.445 1.280 24.775 1.740 ;
        RECT 25.650 1.350 26.505 1.520 ;
        RECT 26.710 1.350 27.205 1.520 ;
        RECT 27.375 1.380 27.705 1.740 ;
        RECT 23.975 0.300 24.145 0.990 ;
        RECT 24.315 0.640 24.485 0.820 ;
        RECT 24.655 0.810 25.445 1.060 ;
        RECT 25.650 0.640 25.820 1.350 ;
        RECT 25.990 0.840 26.345 1.060 ;
        RECT 24.315 0.470 26.005 0.640 ;
        RECT 22.820 -0.130 23.280 0.160 ;
        RECT 23.975 0.130 25.475 0.300 ;
        RECT 23.975 -0.010 24.145 0.130 ;
        RECT 23.585 -0.180 24.145 -0.010 ;
        RECT 22.480 -0.640 23.350 -0.300 ;
        RECT 23.585 -0.640 23.755 -0.180 ;
        RECT 24.590 -0.210 25.665 -0.040 ;
        RECT 24.590 -0.550 24.760 -0.210 ;
        RECT 25.495 -0.550 25.665 -0.210 ;
        RECT 25.835 -0.310 26.005 0.470 ;
        RECT 26.175 0.250 26.345 0.840 ;
        RECT 26.515 0.440 26.865 1.060 ;
        RECT 26.175 -0.140 26.640 0.250 ;
        RECT 27.035 -0.010 27.205 1.350 ;
        RECT 27.375 0.160 27.835 1.210 ;
        RECT 26.810 -0.180 27.205 -0.010 ;
        RECT 26.810 -0.310 26.980 -0.180 ;
        RECT 25.835 -0.640 26.515 -0.310 ;
        RECT 26.730 -0.640 26.980 -0.310 ;
        RECT 27.570 -0.625 27.895 0.160 ;
        RECT 28.065 -0.640 28.235 1.480 ;
        RECT 28.405 1.360 28.735 1.740 ;
        RECT 28.905 1.190 29.160 1.480 ;
        RECT 28.410 1.020 29.160 1.190 ;
        RECT 28.410 0.030 28.640 1.020 ;
        RECT 29.395 0.920 29.605 1.740 ;
        RECT 29.775 0.940 30.105 1.570 ;
        RECT 28.810 0.200 29.160 0.850 ;
        RECT 29.775 0.340 30.025 0.940 ;
        RECT 30.275 0.920 30.505 1.740 ;
        RECT 31.685 0.985 31.935 1.740 ;
        RECT 32.105 1.030 32.355 1.560 ;
        RECT 32.525 1.280 32.830 1.740 ;
        RECT 33.075 1.360 34.145 1.530 ;
        RECT 30.195 0.500 30.525 0.750 ;
        RECT 32.105 0.380 32.310 1.030 ;
        RECT 33.075 1.005 33.395 1.360 ;
        RECT 33.070 0.830 33.395 1.005 ;
        RECT 32.480 0.530 33.395 0.830 ;
        RECT 33.565 0.790 33.805 1.190 ;
        RECT 33.975 1.130 34.145 1.360 ;
        RECT 34.315 1.300 34.505 1.740 ;
        RECT 34.675 1.290 35.625 1.570 ;
        RECT 35.845 1.380 36.195 1.550 ;
        RECT 33.975 0.960 34.505 1.130 ;
        RECT 32.480 0.500 33.220 0.530 ;
        RECT 28.410 -0.140 29.160 0.030 ;
        RECT 29.395 0.000 29.605 0.330 ;
        RECT 28.905 -0.640 29.160 -0.140 ;
        RECT 29.775 -0.640 30.105 0.340 ;
        RECT 30.275 0.000 30.505 0.330 ;
        RECT 31.685 0.000 31.935 0.330 ;
        RECT 32.105 -0.500 32.355 0.380 ;
        RECT 32.525 0.000 32.830 0.330 ;
        RECT 33.050 -0.090 33.220 0.500 ;
        RECT 33.565 0.420 34.105 0.790 ;
        RECT 34.285 0.680 34.505 0.960 ;
        RECT 34.675 0.510 34.845 1.290 ;
        RECT 34.440 0.340 34.845 0.510 ;
        RECT 35.015 0.500 35.365 1.120 ;
        RECT 34.440 0.250 34.610 0.340 ;
        RECT 35.535 0.330 35.745 1.120 ;
        RECT 33.390 0.080 34.610 0.250 ;
        RECT 35.070 0.170 35.745 0.330 ;
        RECT 33.050 -0.260 33.850 -0.090 ;
        RECT 33.680 -0.550 33.850 -0.260 ;
        RECT 34.440 -0.300 34.610 0.080 ;
        RECT 34.780 0.160 35.745 0.170 ;
        RECT 35.935 0.990 36.195 1.380 ;
        RECT 36.405 1.280 36.735 1.740 ;
        RECT 37.610 1.350 38.465 1.520 ;
        RECT 38.670 1.350 39.165 1.520 ;
        RECT 39.335 1.380 39.665 1.740 ;
        RECT 35.935 0.300 36.105 0.990 ;
        RECT 36.275 0.640 36.445 0.820 ;
        RECT 36.615 0.810 37.405 1.060 ;
        RECT 37.610 0.640 37.780 1.350 ;
        RECT 37.950 0.840 38.305 1.060 ;
        RECT 36.275 0.470 37.965 0.640 ;
        RECT 34.780 -0.130 35.240 0.160 ;
        RECT 35.935 0.130 37.435 0.300 ;
        RECT 35.935 -0.010 36.105 0.130 ;
        RECT 35.545 -0.180 36.105 -0.010 ;
        RECT 34.440 -0.640 35.310 -0.300 ;
        RECT 35.545 -0.640 35.715 -0.180 ;
        RECT 36.550 -0.210 37.625 -0.040 ;
        RECT 36.550 -0.550 36.720 -0.210 ;
        RECT 37.455 -0.550 37.625 -0.210 ;
        RECT 37.795 -0.310 37.965 0.470 ;
        RECT 38.135 0.250 38.305 0.840 ;
        RECT 38.475 0.440 38.825 1.060 ;
        RECT 38.135 -0.140 38.600 0.250 ;
        RECT 38.995 -0.010 39.165 1.350 ;
        RECT 39.335 0.160 39.795 1.210 ;
        RECT 38.770 -0.180 39.165 -0.010 ;
        RECT 38.770 -0.310 38.940 -0.180 ;
        RECT 37.795 -0.640 38.475 -0.310 ;
        RECT 38.690 -0.640 38.940 -0.310 ;
        RECT 39.530 -0.625 39.855 0.160 ;
        RECT 40.025 -0.640 40.195 1.480 ;
        RECT 40.365 1.360 40.695 1.740 ;
        RECT 40.865 1.190 41.120 1.480 ;
        RECT 40.370 1.020 41.120 1.190 ;
        RECT 40.370 0.030 40.600 1.020 ;
        RECT 41.295 1.015 41.585 1.740 ;
        RECT 41.755 1.090 42.080 1.570 ;
        RECT 42.250 1.260 42.580 1.740 ;
        RECT 41.755 0.920 42.675 1.090 ;
        RECT 42.845 0.970 43.315 1.570 ;
        RECT 40.770 0.200 41.120 0.850 ;
        RECT 42.325 0.800 42.675 0.920 ;
        RECT 41.755 0.505 42.155 0.750 ;
        RECT 42.325 0.530 42.775 0.800 ;
        RECT 43.140 0.750 43.315 0.970 ;
        RECT 43.485 1.090 43.735 1.570 ;
        RECT 43.910 1.260 44.515 1.740 ;
        RECT 44.685 1.185 45.265 1.570 ;
        RECT 43.485 0.920 44.435 1.090 ;
        RECT 44.265 0.835 44.435 0.920 ;
        RECT 43.140 0.575 44.090 0.750 ;
        RECT 40.370 -0.140 41.120 0.030 ;
        RECT 41.295 0.000 41.585 0.355 ;
        RECT 42.325 0.335 42.675 0.530 ;
        RECT 41.755 0.165 42.675 0.335 ;
        RECT 40.865 -0.640 41.120 -0.140 ;
        RECT 41.755 -0.640 42.100 0.165 ;
        RECT 43.140 0.035 43.315 0.575 ;
        RECT 44.265 0.500 44.720 0.835 ;
        RECT 44.265 0.330 44.435 0.500 ;
        RECT 42.865 -0.640 43.315 0.035 ;
        RECT 43.485 0.160 44.435 0.330 ;
        RECT 44.900 0.260 45.265 1.185 ;
        RECT 45.475 0.920 45.705 1.740 ;
        RECT 45.875 0.940 46.205 1.570 ;
        RECT 45.455 0.500 45.785 0.750 ;
        RECT 45.955 0.340 46.205 0.940 ;
        RECT 46.375 0.920 46.585 1.740 ;
        RECT 47.280 1.190 47.535 1.480 ;
        RECT 47.705 1.360 48.035 1.740 ;
        RECT 47.280 1.020 48.030 1.190 ;
        RECT 43.485 -0.640 43.735 0.160 ;
        RECT 44.705 -0.640 45.265 0.260 ;
        RECT 45.475 0.000 45.705 0.330 ;
        RECT 45.875 -0.640 46.205 0.340 ;
        RECT 46.375 0.000 46.585 0.330 ;
        RECT 47.280 0.200 47.630 0.850 ;
        RECT 47.800 0.030 48.030 1.020 ;
        RECT 47.280 -0.140 48.030 0.030 ;
        RECT 47.280 -0.640 47.535 -0.140 ;
        RECT 48.205 -0.640 48.375 1.480 ;
        RECT 48.735 1.380 49.065 1.740 ;
        RECT 49.235 1.350 49.730 1.520 ;
        RECT 49.935 1.350 50.790 1.520 ;
        RECT 48.605 0.160 49.065 1.210 ;
        RECT 48.545 -0.625 48.870 0.160 ;
        RECT 49.235 -0.010 49.405 1.350 ;
        RECT 49.575 0.440 49.925 1.060 ;
        RECT 50.095 0.840 50.450 1.060 ;
        RECT 50.095 0.250 50.265 0.840 ;
        RECT 50.620 0.640 50.790 1.350 ;
        RECT 51.665 1.280 51.995 1.740 ;
        RECT 52.205 1.380 52.555 1.550 ;
        RECT 50.995 0.810 51.785 1.060 ;
        RECT 52.205 0.990 52.465 1.380 ;
        RECT 52.775 1.290 53.725 1.570 ;
        RECT 53.895 1.300 54.085 1.740 ;
        RECT 54.255 1.360 55.325 1.530 ;
        RECT 51.955 0.640 52.125 0.820 ;
        RECT 49.235 -0.180 49.630 -0.010 ;
        RECT 49.800 -0.140 50.265 0.250 ;
        RECT 50.435 0.470 52.125 0.640 ;
        RECT 49.460 -0.310 49.630 -0.180 ;
        RECT 50.435 -0.310 50.605 0.470 ;
        RECT 52.295 0.300 52.465 0.990 ;
        RECT 50.965 0.130 52.465 0.300 ;
        RECT 52.655 0.330 52.865 1.120 ;
        RECT 53.035 0.500 53.385 1.120 ;
        RECT 53.555 0.510 53.725 1.290 ;
        RECT 54.255 1.130 54.425 1.360 ;
        RECT 53.895 0.960 54.425 1.130 ;
        RECT 53.895 0.680 54.115 0.960 ;
        RECT 54.595 0.790 54.835 1.190 ;
        RECT 53.555 0.340 53.960 0.510 ;
        RECT 54.295 0.420 54.835 0.790 ;
        RECT 55.005 1.005 55.325 1.360 ;
        RECT 55.570 1.280 55.875 1.740 ;
        RECT 56.045 1.030 56.295 1.560 ;
        RECT 55.005 0.830 55.330 1.005 ;
        RECT 55.005 0.530 55.920 0.830 ;
        RECT 55.180 0.500 55.920 0.530 ;
        RECT 52.655 0.170 53.330 0.330 ;
        RECT 53.790 0.250 53.960 0.340 ;
        RECT 52.655 0.160 53.620 0.170 ;
        RECT 52.295 -0.010 52.465 0.130 ;
        RECT 49.460 -0.640 49.710 -0.310 ;
        RECT 49.925 -0.640 50.605 -0.310 ;
        RECT 50.775 -0.210 51.850 -0.040 ;
        RECT 52.295 -0.180 52.855 -0.010 ;
        RECT 53.160 -0.130 53.620 0.160 ;
        RECT 53.790 0.080 55.010 0.250 ;
        RECT 50.775 -0.550 50.945 -0.210 ;
        RECT 51.680 -0.550 51.850 -0.210 ;
        RECT 52.685 -0.640 52.855 -0.180 ;
        RECT 53.790 -0.300 53.960 0.080 ;
        RECT 55.180 -0.090 55.350 0.500 ;
        RECT 56.090 0.380 56.295 1.030 ;
        RECT 56.465 0.985 56.715 1.740 ;
        RECT 56.995 0.920 57.205 1.740 ;
        RECT 57.375 0.940 57.705 1.570 ;
        RECT 55.570 0.000 55.875 0.330 ;
        RECT 53.090 -0.640 53.960 -0.300 ;
        RECT 54.550 -0.260 55.350 -0.090 ;
        RECT 54.550 -0.550 54.720 -0.260 ;
        RECT 56.045 -0.500 56.295 0.380 ;
        RECT 57.375 0.340 57.625 0.940 ;
        RECT 57.875 0.920 58.105 1.740 ;
        RECT 58.420 1.270 58.590 1.740 ;
        RECT 58.760 1.100 59.090 1.570 ;
        RECT 59.260 1.270 59.430 1.740 ;
        RECT 59.600 1.100 59.930 1.570 ;
        RECT 60.100 1.270 60.270 1.740 ;
        RECT 58.350 0.920 59.930 1.100 ;
        RECT 60.540 1.100 60.870 1.570 ;
        RECT 61.040 1.270 61.210 1.740 ;
        RECT 61.380 1.350 62.610 1.570 ;
        RECT 61.380 1.100 61.630 1.350 ;
        RECT 62.875 1.270 63.045 1.740 ;
        RECT 63.715 1.270 63.885 1.740 ;
        RECT 60.540 0.920 61.630 1.100 ;
        RECT 61.855 1.100 62.185 1.180 ;
        RECT 63.215 1.100 63.545 1.180 ;
        RECT 64.495 1.110 64.825 1.470 ;
        RECT 65.455 1.280 65.705 1.740 ;
        RECT 65.875 1.280 66.425 1.570 ;
        RECT 61.855 0.920 64.125 1.100 ;
        RECT 64.495 0.920 65.885 1.110 ;
        RECT 57.795 0.500 58.125 0.750 ;
        RECT 56.465 0.000 56.715 0.330 ;
        RECT 56.995 0.000 57.205 0.330 ;
        RECT 57.375 -0.640 57.705 0.340 ;
        RECT 57.875 0.000 58.105 0.330 ;
        RECT 58.350 0.040 58.520 0.920 ;
        RECT 58.775 0.550 59.105 0.750 ;
        RECT 59.275 0.550 59.770 0.750 ;
        RECT 59.940 0.550 61.460 0.750 ;
        RECT 61.650 0.550 62.320 0.750 ;
        RECT 62.845 0.580 63.505 0.750 ;
        RECT 58.935 0.380 59.105 0.550 ;
        RECT 59.940 0.380 60.110 0.550 ;
        RECT 62.845 0.380 63.015 0.580 ;
        RECT 63.715 0.410 64.125 0.920 ;
        RECT 65.715 0.830 65.885 0.920 ;
        RECT 58.935 0.210 60.110 0.380 ;
        RECT 60.280 0.210 63.015 0.380 ;
        RECT 60.280 0.040 60.450 0.210 ;
        RECT 63.255 0.200 64.125 0.410 ;
        RECT 64.295 0.500 64.985 0.750 ;
        RECT 65.215 0.500 65.545 0.750 ;
        RECT 65.715 0.500 66.005 0.830 ;
        RECT 58.350 -0.130 60.450 0.040 ;
        RECT 60.620 -0.130 63.085 0.040 ;
        RECT 59.640 -0.300 59.890 -0.130 ;
        RECT 60.620 -0.300 60.830 -0.130 ;
        RECT 58.375 -0.310 58.545 -0.300 ;
        RECT 59.295 -0.310 59.465 -0.300 ;
        RECT 58.350 -0.640 58.630 -0.310 ;
        RECT 59.220 -0.470 59.470 -0.310 ;
        RECT 60.060 -0.470 60.310 -0.310 ;
        RECT 59.220 -0.640 60.310 -0.470 ;
        RECT 60.515 -0.640 60.830 -0.300 ;
        RECT 61.420 -0.640 61.670 -0.130 ;
        RECT 62.315 -0.470 63.085 -0.130 ;
        RECT 63.255 -0.300 63.505 0.200 ;
        RECT 64.295 0.060 64.610 0.500 ;
        RECT 65.715 0.250 65.885 0.500 ;
        RECT 64.945 0.080 65.885 0.250 ;
        RECT 63.675 -0.470 63.925 0.030 ;
        RECT 64.945 -0.470 65.245 0.080 ;
        RECT 66.175 -0.090 66.425 1.280 ;
        RECT 66.595 0.940 66.885 1.740 ;
        RECT 67.055 1.015 67.345 1.740 ;
        RECT 67.980 1.190 68.235 1.480 ;
        RECT 68.405 1.360 68.735 1.740 ;
        RECT 67.980 1.020 68.730 1.190 ;
        RECT 66.595 0.000 66.885 0.330 ;
        RECT 67.055 0.000 67.345 0.355 ;
        RECT 67.980 0.200 68.330 0.850 ;
        RECT 68.500 0.030 68.730 1.020 ;
        RECT 62.315 -0.640 63.925 -0.470 ;
        RECT 65.975 -0.640 66.425 -0.090 ;
        RECT 67.980 -0.140 68.730 0.030 ;
        RECT 67.980 -0.640 68.235 -0.140 ;
        RECT 68.905 -0.640 69.075 1.480 ;
        RECT 69.435 1.380 69.765 1.740 ;
        RECT 69.935 1.350 70.430 1.520 ;
        RECT 70.635 1.350 71.490 1.520 ;
        RECT 69.305 0.160 69.765 1.210 ;
        RECT 69.245 -0.625 69.570 0.160 ;
        RECT 69.935 -0.010 70.105 1.350 ;
        RECT 70.275 0.440 70.625 1.060 ;
        RECT 70.795 0.840 71.150 1.060 ;
        RECT 70.795 0.250 70.965 0.840 ;
        RECT 71.320 0.640 71.490 1.350 ;
        RECT 72.365 1.280 72.695 1.740 ;
        RECT 72.905 1.380 73.255 1.550 ;
        RECT 71.695 0.810 72.485 1.060 ;
        RECT 72.905 0.990 73.165 1.380 ;
        RECT 73.475 1.290 74.425 1.570 ;
        RECT 74.595 1.300 74.785 1.740 ;
        RECT 74.955 1.360 76.025 1.530 ;
        RECT 72.655 0.640 72.825 0.820 ;
        RECT 69.935 -0.180 70.330 -0.010 ;
        RECT 70.500 -0.140 70.965 0.250 ;
        RECT 71.135 0.470 72.825 0.640 ;
        RECT 70.160 -0.310 70.330 -0.180 ;
        RECT 71.135 -0.310 71.305 0.470 ;
        RECT 72.995 0.300 73.165 0.990 ;
        RECT 71.665 0.130 73.165 0.300 ;
        RECT 73.355 0.330 73.565 1.120 ;
        RECT 73.735 0.500 74.085 1.120 ;
        RECT 74.255 0.510 74.425 1.290 ;
        RECT 74.955 1.130 75.125 1.360 ;
        RECT 74.595 0.960 75.125 1.130 ;
        RECT 74.595 0.680 74.815 0.960 ;
        RECT 75.295 0.790 75.535 1.190 ;
        RECT 74.255 0.340 74.660 0.510 ;
        RECT 74.995 0.420 75.535 0.790 ;
        RECT 75.705 1.005 76.025 1.360 ;
        RECT 76.270 1.280 76.575 1.740 ;
        RECT 76.745 1.030 76.995 1.560 ;
        RECT 75.705 0.830 76.030 1.005 ;
        RECT 75.705 0.530 76.620 0.830 ;
        RECT 75.880 0.500 76.620 0.530 ;
        RECT 73.355 0.170 74.030 0.330 ;
        RECT 74.490 0.250 74.660 0.340 ;
        RECT 73.355 0.160 74.320 0.170 ;
        RECT 72.995 -0.010 73.165 0.130 ;
        RECT 70.160 -0.640 70.410 -0.310 ;
        RECT 70.625 -0.640 71.305 -0.310 ;
        RECT 71.475 -0.210 72.550 -0.040 ;
        RECT 72.995 -0.180 73.555 -0.010 ;
        RECT 73.860 -0.130 74.320 0.160 ;
        RECT 74.490 0.080 75.710 0.250 ;
        RECT 71.475 -0.550 71.645 -0.210 ;
        RECT 72.380 -0.550 72.550 -0.210 ;
        RECT 73.385 -0.640 73.555 -0.180 ;
        RECT 74.490 -0.300 74.660 0.080 ;
        RECT 75.880 -0.090 76.050 0.500 ;
        RECT 76.790 0.380 76.995 1.030 ;
        RECT 77.165 0.985 77.415 1.740 ;
        RECT 77.640 0.920 77.915 1.740 ;
        RECT 78.085 1.100 78.415 1.570 ;
        RECT 78.585 1.270 78.755 1.740 ;
        RECT 78.925 1.100 79.255 1.570 ;
        RECT 79.425 1.270 79.715 1.740 ;
        RECT 78.085 1.090 79.255 1.100 ;
        RECT 78.085 1.060 79.685 1.090 ;
        RECT 78.085 0.920 79.705 1.060 ;
        RECT 80.855 0.990 82.065 1.740 ;
        RECT 79.470 0.890 79.705 0.920 ;
        RECT 77.640 0.550 78.360 0.750 ;
        RECT 78.530 0.550 79.300 0.750 ;
        RECT 79.470 0.380 79.685 0.890 ;
        RECT 76.270 0.000 76.575 0.330 ;
        RECT 73.790 -0.640 74.660 -0.300 ;
        RECT 75.250 -0.260 76.050 -0.090 ;
        RECT 75.250 -0.550 75.420 -0.260 ;
        RECT 76.745 -0.500 76.995 0.380 ;
        RECT 77.165 0.000 77.415 0.330 ;
        RECT 77.640 0.160 78.755 0.370 ;
        RECT 77.640 -0.640 77.915 0.160 ;
        RECT 78.585 -0.470 78.755 0.160 ;
        RECT 78.925 0.160 79.685 0.380 ;
        RECT 80.855 0.280 81.375 0.820 ;
        RECT 81.545 0.450 82.065 0.990 ;
        RECT 78.925 -0.300 79.255 0.160 ;
        RECT 80.855 0.000 82.065 0.280 ;
        RECT 84.300 0.000 85.250 3.050 ;
        RECT 86.150 2.210 87.050 3.700 ;
        RECT 94.240 3.050 95.140 3.060 ;
        RECT 87.940 2.310 91.540 2.610 ;
        RECT 86.140 1.910 87.050 2.210 ;
        RECT 86.150 1.900 87.050 1.910 ;
        RECT 87.940 1.810 88.780 1.830 ;
        RECT 87.940 1.510 88.840 1.810 ;
        RECT 79.425 -0.470 79.725 -0.010 ;
        RECT 89.150 -0.050 90.000 2.310 ;
        RECT 92.440 1.910 93.340 2.210 ;
        RECT 90.640 1.810 91.480 1.830 ;
        RECT 90.640 1.510 91.540 1.810 ;
        RECT 94.200 0.000 95.150 3.050 ;
        RECT 78.585 -0.640 79.725 -0.470 ;
        RECT 16.915 -2.050 17.475 -1.150 ;
        RECT 18.445 -1.950 18.695 -1.150 ;
        RECT 16.915 -2.975 17.280 -2.050 ;
        RECT 17.745 -2.120 18.695 -1.950 ;
        RECT 18.865 -1.825 19.315 -1.150 ;
        RECT 17.745 -2.290 17.915 -2.120 ;
        RECT 17.460 -2.625 17.915 -2.290 ;
        RECT 18.865 -2.365 19.040 -1.825 ;
        RECT 20.080 -1.955 20.425 -1.150 ;
        RECT 21.170 -1.610 21.455 -1.150 ;
        RECT 21.170 -1.830 22.125 -1.610 ;
        RECT 19.505 -2.125 20.425 -1.955 ;
        RECT 19.505 -2.320 19.855 -2.125 ;
        RECT 18.090 -2.540 19.040 -2.365 ;
        RECT 17.745 -2.710 17.915 -2.625 ;
        RECT 17.745 -2.880 18.695 -2.710 ;
        RECT 16.915 -3.360 17.495 -2.975 ;
        RECT 18.445 -3.360 18.695 -2.880 ;
        RECT 18.865 -2.760 19.040 -2.540 ;
        RECT 19.405 -2.590 19.855 -2.320 ;
        RECT 20.025 -2.540 20.425 -2.295 ;
        RECT 21.055 -2.560 21.745 -2.000 ;
        RECT 19.505 -2.710 19.855 -2.590 ;
        RECT 18.865 -3.360 19.335 -2.760 ;
        RECT 19.505 -2.880 20.425 -2.710 ;
        RECT 21.915 -2.730 22.125 -1.830 ;
        RECT 20.100 -3.360 20.425 -2.880 ;
        RECT 21.170 -2.900 22.125 -2.730 ;
        RECT 22.295 -2.000 22.695 -1.150 ;
        RECT 22.885 -1.610 23.165 -1.150 ;
        RECT 22.885 -1.830 24.010 -1.610 ;
        RECT 22.295 -2.560 23.390 -2.000 ;
        RECT 23.560 -2.290 24.010 -1.830 ;
        RECT 24.180 -2.120 24.565 -1.150 ;
        RECT 21.170 -3.360 21.455 -2.900 ;
        RECT 22.295 -3.360 22.695 -2.560 ;
        RECT 23.560 -2.620 24.115 -2.290 ;
        RECT 23.560 -2.730 24.010 -2.620 ;
        RECT 22.885 -2.900 24.010 -2.730 ;
        RECT 24.285 -2.790 24.565 -2.120 ;
        RECT 22.885 -3.360 23.165 -2.900 ;
        RECT 24.180 -3.360 24.565 -2.790 ;
        RECT 24.735 -2.050 25.295 -1.150 ;
        RECT 26.265 -1.950 26.515 -1.150 ;
        RECT 24.735 -2.975 25.100 -2.050 ;
        RECT 25.565 -2.120 26.515 -1.950 ;
        RECT 26.685 -1.825 27.135 -1.150 ;
        RECT 25.565 -2.290 25.735 -2.120 ;
        RECT 25.280 -2.625 25.735 -2.290 ;
        RECT 26.685 -2.365 26.860 -1.825 ;
        RECT 27.900 -1.955 28.245 -1.150 ;
        RECT 28.935 -1.680 29.155 -1.150 ;
        RECT 29.825 -1.680 30.050 -1.150 ;
        RECT 28.935 -1.945 30.050 -1.680 ;
        RECT 30.220 -1.695 30.535 -1.150 ;
        RECT 30.220 -1.925 31.055 -1.695 ;
        RECT 27.325 -2.125 28.245 -1.955 ;
        RECT 27.325 -2.320 27.675 -2.125 ;
        RECT 25.910 -2.540 26.860 -2.365 ;
        RECT 25.565 -2.710 25.735 -2.625 ;
        RECT 25.565 -2.880 26.515 -2.710 ;
        RECT 24.735 -3.360 25.315 -2.975 ;
        RECT 26.265 -3.360 26.515 -2.880 ;
        RECT 26.685 -2.760 26.860 -2.540 ;
        RECT 27.225 -2.590 27.675 -2.320 ;
        RECT 27.325 -2.710 27.675 -2.590 ;
        RECT 26.685 -3.360 27.155 -2.760 ;
        RECT 27.325 -2.880 28.245 -2.710 ;
        RECT 28.885 -2.865 29.200 -2.290 ;
        RECT 27.920 -3.360 28.245 -2.880 ;
        RECT 29.390 -3.250 29.770 -2.290 ;
        RECT 30.220 -2.620 30.545 -2.205 ;
        RECT 30.715 -2.620 31.055 -1.925 ;
        RECT 30.715 -2.790 30.885 -2.620 ;
        RECT 31.225 -2.790 31.455 -1.150 ;
        RECT 32.210 -1.610 32.495 -1.150 ;
        RECT 32.210 -1.830 33.165 -1.610 ;
        RECT 32.095 -2.560 32.785 -2.000 ;
        RECT 32.955 -2.730 33.165 -1.830 ;
        RECT 30.145 -2.960 30.885 -2.790 ;
        RECT 30.145 -3.360 30.335 -2.960 ;
        RECT 31.055 -2.980 31.455 -2.790 ;
        RECT 32.210 -2.900 33.165 -2.730 ;
        RECT 33.335 -2.000 33.735 -1.150 ;
        RECT 33.925 -1.610 34.205 -1.150 ;
        RECT 33.925 -1.830 35.050 -1.610 ;
        RECT 33.335 -2.560 34.430 -2.000 ;
        RECT 34.600 -2.290 35.050 -1.830 ;
        RECT 35.220 -2.120 35.605 -1.150 ;
        RECT 31.055 -3.360 31.245 -2.980 ;
        RECT 32.210 -3.360 32.495 -2.900 ;
        RECT 33.335 -3.360 33.735 -2.560 ;
        RECT 34.600 -2.620 35.155 -2.290 ;
        RECT 34.600 -2.730 35.050 -2.620 ;
        RECT 33.925 -2.900 35.050 -2.730 ;
        RECT 35.325 -2.790 35.605 -2.120 ;
        RECT 33.925 -3.360 34.205 -2.900 ;
        RECT 35.220 -3.360 35.605 -2.790 ;
        RECT 35.780 -2.120 36.115 -1.150 ;
        RECT 36.625 -1.320 38.655 -1.150 ;
        RECT 35.780 -2.790 35.950 -2.120 ;
        RECT 36.625 -2.290 36.795 -1.320 ;
        RECT 36.120 -2.620 36.375 -2.290 ;
        RECT 36.600 -2.620 36.795 -2.290 ;
        RECT 36.965 -1.660 38.090 -1.490 ;
        RECT 36.205 -2.790 36.375 -2.620 ;
        RECT 36.965 -2.790 37.135 -1.660 ;
        RECT 35.780 -3.360 36.035 -2.790 ;
        RECT 36.205 -2.960 37.135 -2.790 ;
        RECT 37.305 -2.000 38.315 -1.830 ;
        RECT 37.305 -2.800 37.475 -2.000 ;
        RECT 37.680 -2.680 37.955 -2.200 ;
        RECT 37.675 -2.850 37.955 -2.680 ;
        RECT 36.960 -2.995 37.135 -2.960 ;
        RECT 36.960 -3.360 37.490 -2.995 ;
        RECT 37.680 -3.360 37.955 -2.850 ;
        RECT 38.125 -3.360 38.315 -2.000 ;
        RECT 38.485 -1.985 38.655 -1.320 ;
        RECT 39.230 -1.740 39.745 -1.330 ;
        RECT 38.485 -2.175 39.235 -1.985 ;
        RECT 39.405 -2.550 39.745 -1.740 ;
        RECT 41.755 -1.955 42.100 -1.150 ;
        RECT 42.865 -1.825 43.315 -1.150 ;
        RECT 41.755 -2.125 42.675 -1.955 ;
        RECT 41.755 -2.540 42.155 -2.295 ;
        RECT 42.325 -2.320 42.675 -2.125 ;
        RECT 38.515 -2.720 39.745 -2.550 ;
        RECT 42.325 -2.590 42.775 -2.320 ;
        RECT 43.140 -2.365 43.315 -1.825 ;
        RECT 43.485 -1.950 43.735 -1.150 ;
        RECT 43.485 -2.120 44.435 -1.950 ;
        RECT 44.265 -2.290 44.435 -2.120 ;
        RECT 45.890 -2.035 46.195 -1.250 ;
        RECT 46.370 -1.970 47.065 -1.660 ;
        RECT 43.140 -2.540 44.090 -2.365 ;
        RECT 42.325 -2.710 42.675 -2.590 ;
        RECT 39.225 -3.325 39.470 -2.720 ;
        RECT 41.755 -2.880 42.675 -2.710 ;
        RECT 43.140 -2.760 43.315 -2.540 ;
        RECT 44.265 -2.625 44.720 -2.290 ;
        RECT 44.265 -2.710 44.435 -2.625 ;
        RECT 41.755 -3.360 42.080 -2.880 ;
        RECT 42.845 -3.360 43.315 -2.760 ;
        RECT 43.485 -2.880 44.435 -2.710 ;
        RECT 45.890 -2.840 46.065 -2.035 ;
        RECT 47.240 -2.140 47.525 -1.195 ;
        RECT 48.225 -1.600 48.395 -1.170 ;
        RECT 46.665 -2.290 47.525 -2.140 ;
        RECT 46.235 -2.310 47.525 -2.290 ;
        RECT 47.715 -1.830 48.395 -1.600 ;
        RECT 46.235 -2.670 47.225 -2.310 ;
        RECT 47.715 -2.480 47.950 -1.830 ;
        RECT 43.485 -3.360 43.735 -2.880 ;
        RECT 45.890 -3.360 46.125 -2.840 ;
        RECT 47.055 -3.005 47.225 -2.670 ;
        RECT 47.395 -2.810 47.950 -2.480 ;
        RECT 47.735 -2.960 47.950 -2.810 ;
        RECT 48.120 -2.170 48.425 -2.000 ;
        RECT 50.040 -2.120 50.375 -1.150 ;
        RECT 50.885 -1.320 52.915 -1.150 ;
        RECT 48.120 -2.850 48.420 -2.170 ;
        RECT 50.040 -2.790 50.210 -2.120 ;
        RECT 50.885 -2.290 51.055 -1.320 ;
        RECT 50.380 -2.620 50.635 -2.290 ;
        RECT 50.860 -2.620 51.055 -2.290 ;
        RECT 51.225 -1.660 52.350 -1.490 ;
        RECT 50.465 -2.790 50.635 -2.620 ;
        RECT 51.225 -2.790 51.395 -1.660 ;
        RECT 47.055 -3.200 47.455 -3.005 ;
        RECT 47.285 -3.345 47.455 -3.200 ;
        RECT 47.735 -3.335 47.975 -2.960 ;
        RECT 50.040 -3.360 50.295 -2.790 ;
        RECT 50.465 -2.960 51.395 -2.790 ;
        RECT 51.565 -2.000 52.575 -1.830 ;
        RECT 51.565 -2.800 51.735 -2.000 ;
        RECT 51.940 -2.680 52.215 -2.200 ;
        RECT 51.935 -2.850 52.215 -2.680 ;
        RECT 51.220 -2.995 51.395 -2.960 ;
        RECT 51.220 -3.360 51.750 -2.995 ;
        RECT 51.940 -3.360 52.215 -2.850 ;
        RECT 52.385 -3.360 52.575 -2.000 ;
        RECT 52.745 -1.985 52.915 -1.320 ;
        RECT 53.490 -1.740 54.005 -1.330 ;
        RECT 52.745 -2.175 53.495 -1.985 ;
        RECT 53.665 -2.550 54.005 -1.740 ;
        RECT 52.775 -2.720 54.005 -2.550 ;
        RECT 54.635 -2.120 55.020 -1.150 ;
        RECT 56.035 -1.610 56.315 -1.150 ;
        RECT 55.190 -1.830 56.315 -1.610 ;
        RECT 53.485 -3.325 53.730 -2.720 ;
        RECT 54.635 -2.790 54.915 -2.120 ;
        RECT 55.190 -2.290 55.640 -1.830 ;
        RECT 56.505 -2.000 56.905 -1.150 ;
        RECT 57.745 -1.610 58.030 -1.150 ;
        RECT 55.085 -2.620 55.640 -2.290 ;
        RECT 55.810 -2.560 56.905 -2.000 ;
        RECT 55.190 -2.730 55.640 -2.620 ;
        RECT 54.635 -3.360 55.020 -2.790 ;
        RECT 55.190 -2.900 56.315 -2.730 ;
        RECT 56.035 -3.360 56.315 -2.900 ;
        RECT 56.505 -3.360 56.905 -2.560 ;
        RECT 57.075 -1.830 58.030 -1.610 ;
        RECT 57.075 -2.730 57.285 -1.830 ;
        RECT 59.845 -1.950 60.095 -1.150 ;
        RECT 57.455 -2.560 58.145 -2.000 ;
        RECT 59.145 -2.120 60.095 -1.950 ;
        RECT 60.265 -1.825 60.715 -1.150 ;
        RECT 59.145 -2.290 59.315 -2.120 ;
        RECT 58.860 -2.625 59.315 -2.290 ;
        RECT 60.265 -2.365 60.440 -1.825 ;
        RECT 61.480 -1.955 61.825 -1.150 ;
        RECT 60.905 -2.125 61.825 -1.955 ;
        RECT 61.995 -1.955 62.340 -1.150 ;
        RECT 63.105 -1.825 63.555 -1.150 ;
        RECT 61.995 -2.125 62.915 -1.955 ;
        RECT 60.905 -2.320 61.255 -2.125 ;
        RECT 59.490 -2.540 60.440 -2.365 ;
        RECT 59.145 -2.710 59.315 -2.625 ;
        RECT 57.075 -2.900 58.030 -2.730 ;
        RECT 59.145 -2.880 60.095 -2.710 ;
        RECT 57.745 -3.360 58.030 -2.900 ;
        RECT 59.845 -3.360 60.095 -2.880 ;
        RECT 60.265 -2.760 60.440 -2.540 ;
        RECT 60.805 -2.590 61.255 -2.320 ;
        RECT 61.425 -2.540 61.825 -2.295 ;
        RECT 61.995 -2.540 62.395 -2.295 ;
        RECT 62.565 -2.320 62.915 -2.125 ;
        RECT 60.905 -2.710 61.255 -2.590 ;
        RECT 62.565 -2.590 63.015 -2.320 ;
        RECT 63.380 -2.365 63.555 -1.825 ;
        RECT 63.725 -1.950 63.975 -1.150 ;
        RECT 63.725 -2.120 64.675 -1.950 ;
        RECT 64.505 -2.290 64.675 -2.120 ;
        RECT 68.440 -2.120 68.775 -1.150 ;
        RECT 69.285 -1.320 71.315 -1.150 ;
        RECT 63.380 -2.540 64.330 -2.365 ;
        RECT 62.565 -2.710 62.915 -2.590 ;
        RECT 60.265 -3.360 60.735 -2.760 ;
        RECT 60.905 -2.880 61.825 -2.710 ;
        RECT 61.500 -3.360 61.825 -2.880 ;
        RECT 61.995 -2.880 62.915 -2.710 ;
        RECT 63.380 -2.760 63.555 -2.540 ;
        RECT 64.505 -2.625 64.960 -2.290 ;
        RECT 64.505 -2.710 64.675 -2.625 ;
        RECT 61.995 -3.360 62.320 -2.880 ;
        RECT 63.085 -3.360 63.555 -2.760 ;
        RECT 63.725 -2.880 64.675 -2.710 ;
        RECT 68.440 -2.790 68.610 -2.120 ;
        RECT 69.285 -2.290 69.455 -1.320 ;
        RECT 68.780 -2.620 69.035 -2.290 ;
        RECT 69.260 -2.620 69.455 -2.290 ;
        RECT 69.625 -1.660 70.750 -1.490 ;
        RECT 68.865 -2.790 69.035 -2.620 ;
        RECT 69.625 -2.790 69.795 -1.660 ;
        RECT 63.725 -3.360 63.975 -2.880 ;
        RECT 68.440 -3.360 68.695 -2.790 ;
        RECT 68.865 -2.960 69.795 -2.790 ;
        RECT 69.965 -2.000 70.975 -1.830 ;
        RECT 69.965 -2.800 70.135 -2.000 ;
        RECT 70.340 -2.680 70.615 -2.200 ;
        RECT 70.335 -2.850 70.615 -2.680 ;
        RECT 69.620 -2.995 69.795 -2.960 ;
        RECT 69.620 -3.360 70.150 -2.995 ;
        RECT 70.340 -3.360 70.615 -2.850 ;
        RECT 70.785 -3.360 70.975 -2.000 ;
        RECT 71.145 -1.985 71.315 -1.320 ;
        RECT 71.890 -1.740 72.405 -1.330 ;
        RECT 71.145 -2.175 71.895 -1.985 ;
        RECT 72.065 -2.550 72.405 -1.740 ;
        RECT 73.015 -2.130 73.345 -1.150 ;
        RECT 72.595 -2.540 72.925 -2.290 ;
        RECT 71.175 -2.720 72.405 -2.550 ;
        RECT 71.885 -3.325 72.130 -2.720 ;
        RECT 73.095 -2.730 73.345 -2.130 ;
        RECT 73.015 -3.360 73.345 -2.730 ;
        RECT 73.955 -2.120 74.340 -1.150 ;
        RECT 75.355 -1.610 75.635 -1.150 ;
        RECT 74.510 -1.830 75.635 -1.610 ;
        RECT 73.955 -2.790 74.235 -2.120 ;
        RECT 74.510 -2.290 74.960 -1.830 ;
        RECT 75.825 -2.000 76.225 -1.150 ;
        RECT 77.065 -1.610 77.350 -1.150 ;
        RECT 74.405 -2.620 74.960 -2.290 ;
        RECT 75.130 -2.560 76.225 -2.000 ;
        RECT 74.510 -2.730 74.960 -2.620 ;
        RECT 73.955 -3.360 74.340 -2.790 ;
        RECT 74.510 -2.900 75.635 -2.730 ;
        RECT 75.355 -3.360 75.635 -2.900 ;
        RECT 75.825 -3.360 76.225 -2.560 ;
        RECT 76.395 -1.830 77.350 -1.610 ;
        RECT 76.395 -2.730 76.605 -1.830 ;
        RECT 77.640 -1.950 77.915 -1.150 ;
        RECT 78.585 -1.320 79.725 -1.150 ;
        RECT 78.585 -1.950 78.755 -1.320 ;
        RECT 76.775 -2.560 77.465 -2.000 ;
        RECT 77.640 -2.160 78.755 -1.950 ;
        RECT 78.925 -1.950 79.255 -1.490 ;
        RECT 79.425 -1.780 79.725 -1.320 ;
        RECT 78.925 -2.170 79.685 -1.950 ;
        RECT 77.640 -2.540 78.360 -2.340 ;
        RECT 78.530 -2.540 79.300 -2.340 ;
        RECT 79.470 -2.710 79.685 -2.170 ;
        RECT 76.395 -2.900 77.350 -2.730 ;
        RECT 77.065 -3.360 77.350 -2.900 ;
        RECT 78.085 -2.880 79.685 -2.710 ;
        RECT 78.085 -2.890 79.255 -2.880 ;
        RECT 78.085 -3.360 78.415 -2.890 ;
        RECT 78.925 -3.360 79.255 -2.890 ;
      LAYER met1 ;
        RECT 115.305 99.185 115.605 99.215 ;
        RECT 35.890 98.690 36.340 98.760 ;
        RECT 37.100 98.690 37.380 99.010 ;
        RECT 35.890 98.410 37.380 98.690 ;
        RECT 39.340 98.680 39.790 98.730 ;
        RECT 40.370 98.680 40.650 99.100 ;
        RECT 115.275 98.825 115.635 99.185 ;
        RECT 115.305 98.795 115.605 98.825 ;
        RECT 35.890 98.370 36.340 98.410 ;
        RECT 39.340 98.400 40.650 98.680 ;
        RECT 43.220 98.610 43.670 98.690 ;
        RECT 44.300 98.610 44.580 98.640 ;
        RECT 39.340 98.340 39.790 98.400 ;
        RECT 43.220 98.330 44.580 98.610 ;
        RECT 43.220 98.300 43.670 98.330 ;
        RECT 44.300 98.300 44.580 98.330 ;
        RECT 114.050 97.800 120.730 98.300 ;
        RECT 17.890 96.090 66.320 97.050 ;
        RECT 17.890 96.020 25.770 96.090 ;
        RECT 12.270 92.720 12.870 94.170 ;
        RECT 16.170 93.670 17.270 94.770 ;
        RECT 14.320 92.950 15.270 92.970 ;
        RECT 12.390 42.510 12.710 92.720 ;
        RECT 13.030 87.450 13.990 91.960 ;
        RECT 14.310 88.360 15.270 92.950 ;
        RECT 17.890 90.570 18.850 96.020 ;
        RECT 17.870 88.070 18.870 90.570 ;
        RECT 13.030 86.490 15.300 87.450 ;
        RECT 14.340 85.410 15.300 86.490 ;
        RECT 13.030 80.900 13.990 85.410 ;
        RECT 14.310 84.040 15.300 85.410 ;
        RECT 17.890 84.520 18.850 88.070 ;
        RECT 14.310 81.810 15.270 84.040 ;
        RECT 17.870 82.020 18.870 84.520 ;
        RECT 22.890 83.670 23.210 94.610 ;
        RECT 22.820 82.320 23.270 83.670 ;
        RECT 17.890 81.850 18.850 82.020 ;
        RECT 17.890 81.640 18.870 81.850 ;
        RECT 13.030 79.940 15.250 80.900 ;
        RECT 17.890 80.170 18.850 81.640 ;
        RECT 14.290 78.860 15.250 79.940 ;
        RECT 13.030 74.350 13.990 78.860 ;
        RECT 14.290 77.540 15.270 78.860 ;
        RECT 17.870 77.670 18.870 80.170 ;
        RECT 22.890 79.870 23.210 82.320 ;
        RECT 14.310 75.260 15.270 77.540 ;
        RECT 13.030 73.390 15.250 74.350 ;
        RECT 14.290 72.310 15.250 73.390 ;
        RECT 13.030 67.550 13.990 72.310 ;
        RECT 14.290 71.340 15.270 72.310 ;
        RECT 14.310 68.710 15.270 71.340 ;
        RECT 13.030 66.590 15.300 67.550 ;
        RECT 14.340 65.760 15.300 66.590 ;
        RECT 13.030 61.250 13.990 65.760 ;
        RECT 14.310 64.590 15.300 65.760 ;
        RECT 14.310 62.160 15.270 64.590 ;
        RECT 13.030 60.290 15.250 61.250 ;
        RECT 14.290 59.210 15.250 60.290 ;
        RECT 13.030 54.650 13.990 59.210 ;
        RECT 14.290 57.840 15.270 59.210 ;
        RECT 14.310 55.610 15.270 57.840 ;
        RECT 13.030 53.690 15.300 54.650 ;
        RECT 14.340 52.660 15.300 53.690 ;
        RECT 13.030 48.100 13.990 52.660 ;
        RECT 14.310 51.240 15.300 52.660 ;
        RECT 14.310 49.060 15.270 51.240 ;
        RECT 17.890 50.600 18.850 77.670 ;
        RECT 22.770 76.720 23.220 79.870 ;
        RECT 23.530 76.220 24.490 94.610 ;
        RECT 24.810 76.910 25.770 96.020 ;
        RECT 29.460 94.970 42.550 95.470 ;
        RECT 29.460 88.300 29.960 94.970 ;
        RECT 33.820 94.320 34.970 94.720 ;
        RECT 33.760 94.170 34.970 94.320 ;
        RECT 31.910 93.920 34.970 94.170 ;
        RECT 31.910 93.570 34.810 93.920 ;
        RECT 31.910 93.170 34.780 93.570 ;
        RECT 33.180 89.520 33.500 92.960 ;
        RECT 29.410 87.740 29.960 88.300 ;
        RECT 32.960 89.360 33.500 89.520 ;
        RECT 33.820 91.410 34.780 93.170 ;
        RECT 35.460 92.960 41.490 93.520 ;
        RECT 35.100 92.520 41.490 92.960 ;
        RECT 33.820 90.375 34.820 91.410 ;
        RECT 33.820 89.360 34.780 90.375 ;
        RECT 32.960 88.270 33.460 89.360 ;
        RECT 32.930 87.770 33.490 88.270 ;
        RECT 29.460 76.940 29.960 87.740 ;
        RECT 32.960 87.520 33.460 87.770 ;
        RECT 33.960 86.450 34.960 86.520 ;
        RECT 35.100 86.450 36.060 92.520 ;
        RECT 63.440 91.530 63.760 94.810 ;
        RECT 48.360 91.380 49.320 91.400 ;
        RECT 48.340 90.380 49.350 91.380 ;
        RECT 59.990 91.210 63.780 91.530 ;
        RECT 40.460 88.505 41.460 89.050 ;
        RECT 40.445 87.870 41.460 88.505 ;
        RECT 48.340 88.030 49.300 90.380 ;
        RECT 40.410 86.920 41.510 87.870 ;
        RECT 48.340 87.070 54.110 88.030 ;
        RECT 59.990 87.230 60.310 91.210 ;
        RECT 40.445 86.530 41.460 86.920 ;
        RECT 33.880 86.370 36.060 86.450 ;
        RECT 31.880 85.490 36.060 86.370 ;
        RECT 39.305 85.515 43.465 86.530 ;
        RECT 31.880 85.370 34.960 85.490 ;
        RECT 39.305 85.420 40.320 85.515 ;
        RECT 33.960 84.960 34.960 85.370 ;
        RECT 33.180 81.680 33.500 84.960 ;
        RECT 33.820 84.520 34.960 84.960 ;
        RECT 33.180 81.360 33.620 81.680 ;
        RECT 33.820 81.360 34.780 84.520 ;
        RECT 33.300 80.180 33.620 81.360 ;
        RECT 33.270 79.860 33.650 80.180 ;
        RECT 35.100 78.530 36.060 84.960 ;
        RECT 39.300 84.340 40.320 85.420 ;
        RECT 42.460 84.960 43.460 85.515 ;
        RECT 39.305 84.315 40.320 84.340 ;
        RECT 39.520 79.860 39.900 80.180 ;
        RECT 39.550 79.210 39.870 79.860 ;
        RECT 41.680 79.210 42.000 84.960 ;
        RECT 42.320 84.520 43.460 84.960 ;
        RECT 42.320 81.360 43.280 84.520 ;
        RECT 43.600 80.750 44.560 84.960 ;
        RECT 48.690 84.540 49.010 84.580 ;
        RECT 48.670 80.940 49.010 84.540 ;
        RECT 49.310 84.430 50.270 84.540 ;
        RECT 49.310 80.940 50.290 84.430 ;
        RECT 43.570 79.790 44.590 80.750 ;
        RECT 39.430 78.860 39.870 79.210 ;
        RECT 34.980 77.540 36.060 78.530 ;
        RECT 34.980 77.510 35.940 77.540 ;
        RECT 29.430 76.440 29.990 76.940 ;
        RECT 22.900 76.200 24.490 76.220 ;
        RECT 21.590 75.180 22.550 76.200 ;
        RECT 22.900 75.240 25.750 76.200 ;
        RECT 22.900 75.220 23.770 75.240 ;
        RECT 22.900 70.260 23.220 75.220 ;
        RECT 24.790 74.260 25.750 75.240 ;
        RECT 23.540 73.350 24.500 74.260 ;
        RECT 22.890 66.660 23.220 70.260 ;
        RECT 22.900 66.260 23.220 66.660 ;
        RECT 22.890 62.660 23.220 66.260 ;
        RECT 22.900 62.260 23.220 62.660 ;
        RECT 22.890 58.810 23.220 62.260 ;
        RECT 23.530 70.660 24.500 73.350 ;
        RECT 22.890 58.660 23.210 58.810 ;
        RECT 19.890 56.070 20.950 57.070 ;
        RECT 22.670 56.520 23.220 57.970 ;
        RECT 22.890 53.360 23.210 56.520 ;
        RECT 23.530 53.360 24.490 70.660 ;
        RECT 24.790 58.775 25.780 74.260 ;
        RECT 29.460 65.520 29.960 76.440 ;
        RECT 32.230 75.180 33.190 76.200 ;
        RECT 29.430 65.020 29.990 65.520 ;
        RECT 24.810 58.660 25.770 58.775 ;
        RECT 24.810 55.700 25.770 56.960 ;
        RECT 32.240 55.700 33.180 75.180 ;
        RECT 34.680 70.360 35.000 74.960 ;
        RECT 35.320 62.510 36.280 73.960 ;
        RECT 36.600 70.360 37.560 78.530 ;
        RECT 38.120 76.200 39.080 76.230 ;
        RECT 38.090 75.180 39.110 76.200 ;
        RECT 39.430 75.610 39.750 78.860 ;
        RECT 38.120 75.150 39.080 75.180 ;
        RECT 40.070 74.930 41.030 79.210 ;
        RECT 41.350 75.610 42.310 79.210 ;
        RECT 40.020 74.610 41.030 74.930 ;
        RECT 40.050 74.540 41.030 74.610 ;
        RECT 41.680 74.620 42.190 74.940 ;
        RECT 41.680 74.610 42.150 74.620 ;
        RECT 40.050 68.710 40.370 74.540 ;
        RECT 41.680 70.360 42.000 74.610 ;
        RECT 43.730 73.960 44.690 75.530 ;
        RECT 45.230 75.500 46.190 80.780 ;
        RECT 48.690 79.280 49.010 80.940 ;
        RECT 49.330 79.280 50.290 80.940 ;
        RECT 48.670 75.680 49.010 79.280 ;
        RECT 49.310 75.680 50.290 79.280 ;
        RECT 50.590 76.000 51.550 84.540 ;
        RECT 53.150 84.450 54.110 87.070 ;
        RECT 55.210 85.170 56.210 86.720 ;
        RECT 59.970 86.270 60.310 87.230 ;
        RECT 62.170 86.750 63.120 90.820 ;
        RECT 64.080 86.750 65.040 94.810 ;
        RECT 59.970 86.120 60.300 86.270 ;
        RECT 50.590 75.920 51.560 76.000 ;
        RECT 45.200 74.540 46.220 75.500 ;
        RECT 48.690 74.970 49.010 75.680 ;
        RECT 48.660 74.570 49.060 74.970 ;
        RECT 42.320 68.760 43.280 73.960 ;
        RECT 43.600 73.540 44.690 73.960 ;
        RECT 43.600 70.360 44.560 73.540 ;
        RECT 48.690 70.360 49.010 74.570 ;
        RECT 49.330 71.680 50.290 75.680 ;
        RECT 50.460 75.520 51.560 75.920 ;
        RECT 50.600 73.960 51.560 75.520 ;
        RECT 50.600 73.000 51.570 73.960 ;
        RECT 49.320 70.360 50.290 71.680 ;
        RECT 50.610 71.460 51.570 73.000 ;
        RECT 50.600 70.440 51.570 71.460 ;
        RECT 50.610 70.360 51.570 70.440 ;
        RECT 37.680 65.550 38.000 68.710 ;
        RECT 37.460 65.110 38.000 65.550 ;
        RECT 37.460 64.990 37.960 65.110 ;
        RECT 38.320 62.510 39.280 68.710 ;
        RECT 39.600 65.110 40.560 68.710 ;
        RECT 43.730 61.920 44.690 69.780 ;
        RECT 49.320 64.750 50.280 70.360 ;
        RECT 42.670 60.720 44.920 61.920 ;
        RECT 46.070 60.570 47.570 60.620 ;
        RECT 35.720 59.370 37.170 60.570 ;
        RECT 40.070 59.370 47.570 60.570 ;
        RECT 24.810 54.750 33.180 55.700 ;
        RECT 24.810 54.740 33.170 54.750 ;
        RECT 24.810 52.720 25.770 54.740 ;
        RECT 24.820 52.700 25.770 52.720 ;
        RECT 24.820 52.520 25.800 52.700 ;
        RECT 23.520 51.740 25.800 52.520 ;
        RECT 23.520 51.620 24.520 51.740 ;
        RECT 22.890 50.600 23.210 50.910 ;
        RECT 17.890 49.850 23.210 50.600 ;
        RECT 17.920 49.640 23.210 49.850 ;
        RECT 17.920 49.620 20.020 49.640 ;
        RECT 13.030 47.140 15.250 48.100 ;
        RECT 22.890 47.310 23.210 49.640 ;
        RECT 23.530 47.310 24.490 51.620 ;
        RECT 24.810 47.370 25.770 50.910 ;
        RECT 14.290 46.110 15.250 47.140 ;
        RECT 24.770 46.320 25.770 47.370 ;
        RECT 13.030 38.920 13.990 46.110 ;
        RECT 14.290 44.640 15.270 46.110 ;
        RECT 32.220 45.295 33.170 54.740 ;
        RECT 21.620 45.270 33.170 45.295 ;
        RECT 14.310 42.510 15.270 44.640 ;
        RECT 21.520 44.345 33.170 45.270 ;
        RECT 21.520 44.320 22.570 44.345 ;
        RECT 23.600 43.420 32.770 44.345 ;
        RECT 49.320 43.420 51.150 64.750 ;
        RECT 55.230 62.510 56.190 85.170 ;
        RECT 59.980 83.580 60.300 86.120 ;
        RECT 60.590 85.790 65.040 86.750 ;
        RECT 65.360 91.050 66.320 96.090 ;
        RECT 74.320 96.030 88.660 96.990 ;
        RECT 90.260 96.120 92.030 97.030 ;
        RECT 114.050 96.500 114.550 97.800 ;
        RECT 124.850 97.700 126.000 98.750 ;
        RECT 144.160 97.210 144.490 99.605 ;
        RECT 144.110 96.910 144.530 97.210 ;
        RECT 74.320 91.050 75.280 96.030 ;
        RECT 78.820 94.520 79.770 95.520 ;
        RECT 65.360 90.090 75.280 91.050 ;
        RECT 60.600 85.720 61.580 85.790 ;
        RECT 60.620 85.440 61.580 85.720 ;
        RECT 60.590 84.480 61.610 85.440 ;
        RECT 57.110 83.105 60.300 83.580 ;
        RECT 57.110 82.435 60.305 83.105 ;
        RECT 56.560 79.530 56.940 79.850 ;
        RECT 56.590 75.240 56.910 79.530 ;
        RECT 57.230 75.240 58.190 81.890 ;
        RECT 59.980 80.520 60.300 82.435 ;
        RECT 60.620 81.920 61.580 84.480 ;
        RECT 60.620 80.900 61.590 81.920 ;
        RECT 60.620 80.520 61.580 80.900 ;
        RECT 61.900 80.520 62.860 84.120 ;
        RECT 62.200 79.500 62.520 80.520 ;
        RECT 63.420 79.530 63.800 79.850 ;
        RECT 63.450 78.850 63.770 79.530 ;
        RECT 56.590 62.720 56.910 73.550 ;
        RECT 57.230 69.950 58.190 73.550 ;
        RECT 58.510 69.950 59.470 78.840 ;
        RECT 63.440 78.490 63.770 78.850 ;
        RECT 63.440 75.250 63.760 78.490 ;
        RECT 64.080 75.250 65.040 81.920 ;
        RECT 65.360 75.250 66.320 90.090 ;
        RECT 80.090 90.060 80.410 96.030 ;
        RECT 80.730 90.060 81.690 95.500 ;
        RECT 87.070 94.520 88.020 95.520 ;
        RECT 82.010 91.000 82.970 93.660 ;
        RECT 81.990 90.040 84.400 91.000 ;
        RECT 88.340 90.060 88.660 96.030 ;
        RECT 88.980 90.060 89.940 95.450 ;
        RECT 90.270 93.660 91.220 96.120 ;
        RECT 102.270 96.000 114.550 96.500 ;
        RECT 142.580 96.080 143.460 96.420 ;
        RECT 145.280 96.080 146.160 96.420 ;
        RECT 118.650 95.450 119.530 95.790 ;
        RECT 121.350 95.450 122.230 95.790 ;
        RECT 142.580 95.285 143.460 95.625 ;
        RECT 145.280 95.285 146.160 95.625 ;
        RECT 110.400 95.190 110.860 95.220 ;
        RECT 110.370 94.790 110.890 95.190 ;
        RECT 110.400 94.760 110.860 94.790 ;
        RECT 118.650 94.650 119.530 94.990 ;
        RECT 142.580 94.485 143.460 94.825 ;
        RECT 145.280 94.485 146.160 94.825 ;
        RECT 90.260 92.400 91.220 93.660 ;
        RECT 118.650 93.050 119.530 93.390 ;
        RECT 121.350 93.050 122.230 93.390 ;
        RECT 91.850 92.400 92.830 92.430 ;
        RECT 90.260 91.420 92.830 92.400 ;
        RECT 102.300 92.220 102.660 92.250 ;
        RECT 103.860 92.220 104.740 92.560 ;
        RECT 106.560 92.220 107.440 92.560 ;
        RECT 102.270 91.920 102.690 92.220 ;
        RECT 105.460 92.180 105.820 92.210 ;
        RECT 102.300 91.890 102.660 91.920 ;
        RECT 105.430 91.880 105.850 92.180 ;
        RECT 105.460 91.850 105.820 91.880 ;
        RECT 90.260 90.240 91.220 91.420 ;
        RECT 91.850 91.390 92.830 91.420 ;
        RECT 96.180 90.340 97.150 91.600 ;
        RECT 116.750 91.250 117.850 92.350 ;
        RECT 100.490 91.050 100.950 91.080 ;
        RECT 100.460 90.650 100.980 91.050 ;
        RECT 118.635 90.910 119.565 90.940 ;
        RECT 100.490 90.620 100.950 90.650 ;
        RECT 83.440 88.660 84.400 90.040 ;
        RECT 90.260 89.840 91.240 90.240 ;
        RECT 96.190 88.690 97.150 90.340 ;
        RECT 118.605 89.920 119.595 90.910 ;
        RECT 118.635 89.890 119.565 89.920 ;
        RECT 96.190 88.660 98.770 88.690 ;
        RECT 73.970 87.660 75.020 87.670 ;
        RECT 68.660 87.170 68.960 87.200 ;
        RECT 66.750 86.870 68.960 87.170 ;
        RECT 68.660 86.840 68.960 86.870 ;
        RECT 65.365 73.550 66.315 75.250 ;
        RECT 63.440 69.620 63.760 73.550 ;
        RECT 64.080 71.440 65.040 73.550 ;
        RECT 64.070 70.420 65.040 71.440 ;
        RECT 64.080 69.950 65.040 70.420 ;
        RECT 63.420 68.820 64.670 69.620 ;
        RECT 65.360 69.050 66.320 73.550 ;
        RECT 68.320 69.520 70.120 71.020 ;
        RECT 71.790 69.960 72.110 87.660 ;
        RECT 71.800 69.050 72.105 69.960 ;
        RECT 72.430 69.170 73.390 87.660 ;
        RECT 73.710 69.220 75.020 87.660 ;
        RECT 80.020 85.495 81.470 87.620 ;
        RECT 83.440 86.440 98.770 88.660 ;
        RECT 97.320 86.420 98.770 86.440 ;
        RECT 99.945 88.320 121.495 89.745 ;
        RECT 122.570 88.420 144.070 89.720 ;
        RECT 99.945 88.295 103.420 88.320 ;
        RECT 104.570 88.295 121.445 88.320 ;
        RECT 99.945 85.495 101.395 88.295 ;
        RECT 80.020 84.045 101.395 85.495 ;
        RECT 102.670 85.270 104.120 87.620 ;
        RECT 120.020 87.520 121.445 88.295 ;
        RECT 119.995 86.395 121.445 87.520 ;
        RECT 122.570 85.270 123.870 88.420 ;
        RECT 142.770 87.620 144.070 88.420 ;
        RECT 102.670 83.970 123.870 85.270 ;
        RECT 125.370 79.445 126.820 87.620 ;
        RECT 142.670 86.420 144.120 87.620 ;
        RECT 146.820 79.445 148.270 79.470 ;
        RECT 125.370 77.995 148.270 79.445 ;
        RECT 58.620 67.670 59.620 68.670 ;
        RECT 65.360 68.530 72.105 69.050 ;
        RECT 59.940 68.110 72.105 68.530 ;
        RECT 59.940 63.410 60.260 68.110 ;
        RECT 65.360 68.090 72.105 68.110 ;
        RECT 60.570 66.970 61.570 67.770 ;
        RECT 61.860 67.010 62.070 67.020 ;
        RECT 62.670 67.010 62.820 67.020 ;
        RECT 60.580 63.410 61.540 66.970 ;
        RECT 61.860 62.720 62.820 67.010 ;
        RECT 65.360 66.970 70.070 68.090 ;
        RECT 71.800 67.010 72.105 68.090 ;
        RECT 72.420 67.720 73.420 69.170 ;
        RECT 73.710 67.720 76.370 69.220 ;
        RECT 77.970 68.520 79.120 73.220 ;
        RECT 104.820 72.370 117.570 72.420 ;
        RECT 82.220 70.970 90.870 72.170 ;
        RECT 82.220 70.120 83.420 70.970 ;
        RECT 89.670 70.170 90.870 70.970 ;
        RECT 97.370 71.220 117.570 72.370 ;
        RECT 97.370 71.170 106.020 71.220 ;
        RECT 89.670 70.145 96.470 70.170 ;
        RECT 79.970 68.470 81.420 70.120 ;
        RECT 82.170 68.970 83.620 70.120 ;
        RECT 82.170 68.920 83.520 68.970 ;
        RECT 87.520 68.470 88.970 70.120 ;
        RECT 89.670 68.970 96.645 70.145 ;
        RECT 97.370 70.120 98.570 71.170 ;
        RECT 104.820 70.120 106.020 71.170 ;
        RECT 116.370 70.120 117.570 71.220 ;
        RECT 141.630 70.870 143.650 72.460 ;
        RECT 146.820 70.800 148.270 77.995 ;
        RECT 94.320 68.920 96.645 68.970 ;
        RECT 97.270 68.920 98.670 70.120 ;
        RECT 102.670 70.095 104.070 70.120 ;
        RECT 64.920 64.520 70.320 66.970 ;
        RECT 56.570 62.020 62.820 62.720 ;
        RECT 56.570 60.570 57.920 62.020 ;
        RECT 54.720 59.370 57.920 60.570 ;
        RECT 55.670 57.670 57.920 59.370 ;
        RECT 71.790 49.310 72.110 67.010 ;
        RECT 72.430 49.310 73.390 67.720 ;
        RECT 73.710 47.965 75.020 67.720 ;
        RECT 73.720 46.420 75.020 47.965 ;
        RECT 79.970 67.420 88.970 68.470 ;
        RECT 95.095 68.370 96.645 68.920 ;
        RECT 102.670 68.370 104.095 70.095 ;
        RECT 104.820 68.920 106.220 70.120 ;
        RECT 110.220 68.370 111.620 70.120 ;
        RECT 116.370 68.920 125.620 70.120 ;
        RECT 132.820 68.920 139.620 70.120 ;
        RECT 146.800 68.920 148.270 70.800 ;
        RECT 146.800 68.900 148.240 68.920 ;
        RECT 95.095 67.420 111.620 68.370 ;
        RECT 79.970 45.370 81.420 67.420 ;
        RECT 114.310 56.360 115.290 56.370 ;
        RECT 114.280 55.350 115.320 56.360 ;
        RECT 114.310 54.170 115.270 55.350 ;
        RECT 114.310 53.210 116.790 54.170 ;
        RECT 92.860 52.665 93.910 52.815 ;
        RECT 91.010 52.065 93.910 52.665 ;
        RECT 91.010 51.665 93.880 52.065 ;
        RECT 83.450 49.980 84.410 50.010 ;
        RECT 83.450 49.020 86.740 49.980 ;
        RECT 83.450 48.990 84.410 49.020 ;
        RECT 79.970 44.220 83.520 45.370 ;
        RECT 23.600 43.170 85.220 43.420 ;
        RECT 23.600 42.020 85.210 43.170 ;
        RECT 23.600 39.620 59.320 42.020 ;
        RECT 23.600 39.580 32.770 39.620 ;
        RECT 13.030 37.720 15.720 38.920 ;
        RECT 31.570 37.720 38.370 38.920 ;
        RECT 54.220 37.720 55.670 38.920 ;
        RECT 57.920 37.920 59.320 39.620 ;
        RECT 59.840 38.440 62.900 41.500 ;
        RECT 63.420 37.920 66.070 42.020 ;
        RECT 66.595 38.445 69.645 41.495 ;
        RECT 70.170 37.920 72.820 42.020 ;
        RECT 76.920 42.010 85.210 42.020 ;
        RECT 73.340 38.430 76.400 41.490 ;
        RECT 76.920 37.930 79.920 42.010 ;
        RECT 80.410 38.420 83.510 41.520 ;
        RECT 84.010 37.930 85.210 42.010 ;
        RECT 76.920 37.920 85.210 37.930 ;
        RECT 57.920 37.790 85.210 37.920 ;
        RECT 13.030 37.690 15.700 37.720 ;
        RECT 57.920 36.950 85.220 37.790 ;
        RECT 57.920 36.720 85.210 36.950 ;
        RECT 57.920 35.270 78.320 36.720 ;
        RECT 57.920 31.170 59.320 35.270 ;
        RECT 59.840 31.690 62.900 34.750 ;
        RECT 63.420 31.170 66.070 35.270 ;
        RECT 66.595 31.695 69.645 34.745 ;
        RECT 70.170 31.170 72.820 35.270 ;
        RECT 73.340 31.690 76.400 34.750 ;
        RECT 76.920 31.170 78.320 35.270 ;
        RECT 85.780 33.675 86.740 49.020 ;
        RECT 88.560 46.795 89.060 50.815 ;
        RECT 92.280 48.015 92.600 51.455 ;
        RECT 88.510 46.235 89.060 46.795 ;
        RECT 92.060 47.855 92.600 48.015 ;
        RECT 92.920 49.905 93.880 51.665 ;
        RECT 94.560 51.455 100.590 52.015 ;
        RECT 94.200 51.015 100.590 51.455 ;
        RECT 92.920 48.870 93.920 49.905 ;
        RECT 92.920 47.855 93.880 48.870 ;
        RECT 92.060 46.765 92.560 47.855 ;
        RECT 92.030 46.265 92.590 46.765 ;
        RECT 38.600 29.250 39.350 30.000 ;
        RECT 57.920 28.520 78.320 31.170 ;
        RECT 57.920 24.420 59.320 28.520 ;
        RECT 59.840 24.940 62.900 28.000 ;
        RECT 63.420 24.420 66.070 28.520 ;
        RECT 66.370 24.730 69.870 28.220 ;
        RECT 70.170 24.420 72.820 28.520 ;
        RECT 73.340 24.940 76.400 28.000 ;
        RECT 76.920 24.420 78.320 28.520 ;
        RECT 57.920 23.020 78.320 24.420 ;
        RECT 88.560 24.015 89.060 46.235 ;
        RECT 92.060 46.015 92.560 46.265 ;
        RECT 93.060 44.945 94.060 45.015 ;
        RECT 94.200 44.945 95.160 51.015 ;
        RECT 107.460 49.875 108.420 49.895 ;
        RECT 107.440 48.875 108.450 49.875 ;
        RECT 99.560 47.000 100.560 47.545 ;
        RECT 99.545 46.365 100.560 47.000 ;
        RECT 107.440 46.525 108.400 48.875 ;
        RECT 99.510 45.415 100.610 46.365 ;
        RECT 107.440 45.565 113.210 46.525 ;
        RECT 99.545 45.025 100.560 45.415 ;
        RECT 92.980 44.865 95.160 44.945 ;
        RECT 90.980 43.985 95.160 44.865 ;
        RECT 98.405 44.010 102.565 45.025 ;
        RECT 90.980 43.865 94.060 43.985 ;
        RECT 98.405 43.915 99.420 44.010 ;
        RECT 93.060 43.455 94.060 43.865 ;
        RECT 92.280 40.175 92.600 43.455 ;
        RECT 92.920 43.015 94.060 43.455 ;
        RECT 92.280 39.855 92.720 40.175 ;
        RECT 92.920 39.855 93.880 43.015 ;
        RECT 92.400 38.675 92.720 39.855 ;
        RECT 92.370 38.355 92.750 38.675 ;
        RECT 94.200 37.025 95.160 43.455 ;
        RECT 98.400 42.835 99.420 43.915 ;
        RECT 101.560 43.455 102.560 44.010 ;
        RECT 98.405 42.810 99.420 42.835 ;
        RECT 98.620 38.355 99.000 38.675 ;
        RECT 98.650 37.705 98.970 38.355 ;
        RECT 100.780 37.705 101.100 43.455 ;
        RECT 101.420 43.015 102.560 43.455 ;
        RECT 101.420 39.855 102.380 43.015 ;
        RECT 102.700 39.245 103.660 43.455 ;
        RECT 107.790 43.035 108.110 43.075 ;
        RECT 107.770 39.435 108.110 43.035 ;
        RECT 108.410 42.925 109.370 43.035 ;
        RECT 108.410 39.435 109.390 42.925 ;
        RECT 102.670 38.285 103.690 39.245 ;
        RECT 98.530 37.355 98.970 37.705 ;
        RECT 94.080 36.035 95.160 37.025 ;
        RECT 94.080 36.005 95.040 36.035 ;
        RECT 91.330 33.675 92.290 34.695 ;
        RECT 88.530 23.515 89.090 24.015 ;
        RECT 15.450 20.625 82.150 21.105 ;
        RECT 24.735 19.745 25.025 19.790 ;
        RECT 20.210 19.605 25.025 19.745 ;
        RECT 20.210 19.465 20.350 19.605 ;
        RECT 24.735 19.560 25.025 19.605 ;
        RECT 57.855 19.745 58.145 19.790 ;
        RECT 63.820 19.745 64.140 19.805 ;
        RECT 57.855 19.605 64.140 19.745 ;
        RECT 57.855 19.560 58.145 19.605 ;
        RECT 63.820 19.545 64.140 19.605 ;
        RECT 65.660 19.545 65.980 19.805 ;
        RECT 67.500 19.545 67.820 19.805 ;
        RECT 20.120 19.205 20.440 19.465 ;
        RECT 20.580 19.405 20.900 19.465 ;
        RECT 23.815 19.405 24.105 19.450 ;
        RECT 20.580 19.265 24.105 19.405 ;
        RECT 20.580 19.205 20.900 19.265 ;
        RECT 23.815 19.220 24.105 19.265 ;
        RECT 29.780 19.405 30.100 19.465 ;
        RECT 31.175 19.405 31.465 19.450 ;
        RECT 29.780 19.265 31.465 19.405 ;
        RECT 29.780 19.205 30.100 19.265 ;
        RECT 31.175 19.220 31.465 19.265 ;
        RECT 36.680 19.205 37.000 19.465 ;
        RECT 37.615 19.220 37.905 19.450 ;
        RECT 38.995 19.220 39.285 19.450 ;
        RECT 39.915 19.405 40.205 19.450 ;
        RECT 45.420 19.405 45.740 19.465 ;
        RECT 39.915 19.265 45.740 19.405 ;
        RECT 39.915 19.220 40.205 19.265 ;
        RECT 24.260 19.065 24.580 19.125 ;
        RECT 29.335 19.065 29.625 19.110 ;
        RECT 24.260 18.925 29.625 19.065 ;
        RECT 24.260 18.865 24.580 18.925 ;
        RECT 29.335 18.880 29.625 18.925 ;
        RECT 33.920 19.065 34.240 19.125 ;
        RECT 37.690 19.065 37.830 19.220 ;
        RECT 33.920 18.925 37.830 19.065 ;
        RECT 39.070 19.065 39.210 19.220 ;
        RECT 45.420 19.205 45.740 19.265 ;
        RECT 48.640 19.405 48.960 19.465 ;
        RECT 52.795 19.405 53.085 19.450 ;
        RECT 61.520 19.405 61.840 19.465 ;
        RECT 62.455 19.405 62.745 19.450 ;
        RECT 48.640 19.265 61.290 19.405 ;
        RECT 48.640 19.205 48.960 19.265 ;
        RECT 52.795 19.220 53.085 19.265 ;
        RECT 48.180 19.065 48.500 19.125 ;
        RECT 39.070 18.925 48.500 19.065 ;
        RECT 33.920 18.865 34.240 18.925 ;
        RECT 48.180 18.865 48.500 18.925 ;
        RECT 56.475 19.065 56.765 19.110 ;
        RECT 58.775 19.065 59.065 19.110 ;
        RECT 56.475 18.925 59.065 19.065 ;
        RECT 61.150 19.065 61.290 19.265 ;
        RECT 61.520 19.265 62.745 19.405 ;
        RECT 61.520 19.205 61.840 19.265 ;
        RECT 62.455 19.220 62.745 19.265 ;
        RECT 70.735 19.405 71.025 19.450 ;
        RECT 74.415 19.405 74.705 19.450 ;
        RECT 76.240 19.405 76.560 19.465 ;
        RECT 70.735 19.265 76.560 19.405 ;
        RECT 70.735 19.220 71.025 19.265 ;
        RECT 74.415 19.220 74.705 19.265 ;
        RECT 76.240 19.205 76.560 19.265 ;
        RECT 65.660 19.065 65.980 19.125 ;
        RECT 61.150 18.925 65.980 19.065 ;
        RECT 56.475 18.880 56.765 18.925 ;
        RECT 58.775 18.880 59.065 18.925 ;
        RECT 65.660 18.865 65.980 18.925 ;
        RECT 14.575 18.725 14.915 18.820 ;
        RECT 16.915 18.725 17.205 18.770 ;
        RECT 14.575 18.585 17.205 18.725 ;
        RECT 14.575 18.490 14.915 18.585 ;
        RECT 16.915 18.540 17.205 18.585 ;
        RECT 18.280 18.725 18.600 18.785 ;
        RECT 20.595 18.725 20.885 18.770 ;
        RECT 18.280 18.585 20.885 18.725 ;
        RECT 18.280 18.525 18.600 18.585 ;
        RECT 20.595 18.540 20.885 18.585 ;
        RECT 27.955 18.725 28.245 18.770 ;
        RECT 28.860 18.725 29.180 18.785 ;
        RECT 27.955 18.585 29.180 18.725 ;
        RECT 27.955 18.540 28.245 18.585 ;
        RECT 28.860 18.525 29.180 18.585 ;
        RECT 30.700 18.525 31.020 18.785 ;
        RECT 36.220 18.525 36.540 18.785 ;
        RECT 38.980 18.525 39.300 18.785 ;
        RECT 53.255 18.725 53.545 18.770 ;
        RECT 53.700 18.725 54.020 18.785 ;
        RECT 53.255 18.585 54.020 18.725 ;
        RECT 53.255 18.540 53.545 18.585 ;
        RECT 53.700 18.525 54.020 18.585 ;
        RECT 54.620 18.525 54.940 18.785 ;
        RECT 56.920 18.525 57.240 18.785 ;
        RECT 64.740 18.725 65.060 18.785 ;
        RECT 71.195 18.725 71.485 18.770 ;
        RECT 64.740 18.585 71.485 18.725 ;
        RECT 64.740 18.525 65.060 18.585 ;
        RECT 71.195 18.540 71.485 18.585 ;
        RECT 15.450 17.905 82.150 18.385 ;
        RECT 36.680 17.705 37.000 17.765 ;
        RECT 37.615 17.705 37.905 17.750 ;
        RECT 54.620 17.705 54.940 17.765 ;
        RECT 36.680 17.565 37.905 17.705 ;
        RECT 36.680 17.505 37.000 17.565 ;
        RECT 37.615 17.520 37.905 17.565 ;
        RECT 51.490 17.565 54.940 17.705 ;
        RECT 21.495 17.365 22.145 17.410 ;
        RECT 25.095 17.365 25.385 17.410 ;
        RECT 30.700 17.365 31.020 17.425 ;
        RECT 41.740 17.365 42.060 17.425 ;
        RECT 51.490 17.410 51.630 17.565 ;
        RECT 54.620 17.505 54.940 17.565 ;
        RECT 58.775 17.705 59.065 17.750 ;
        RECT 61.520 17.705 61.840 17.765 ;
        RECT 58.775 17.565 61.840 17.705 ;
        RECT 58.775 17.520 59.065 17.565 ;
        RECT 61.520 17.505 61.840 17.565 ;
        RECT 64.740 17.505 65.060 17.765 ;
        RECT 66.595 17.705 66.885 17.750 ;
        RECT 66.595 17.565 69.110 17.705 ;
        RECT 66.595 17.520 66.885 17.565 ;
        RECT 53.700 17.410 54.020 17.425 ;
        RECT 68.970 17.410 69.110 17.565 ;
        RECT 76.240 17.505 76.560 17.765 ;
        RECT 71.180 17.410 71.500 17.425 ;
        RECT 21.495 17.225 31.020 17.365 ;
        RECT 21.495 17.180 22.145 17.225 ;
        RECT 24.795 17.180 25.385 17.225 ;
        RECT 18.300 17.025 18.590 17.070 ;
        RECT 20.135 17.025 20.425 17.070 ;
        RECT 23.715 17.025 24.005 17.070 ;
        RECT 18.300 16.885 24.005 17.025 ;
        RECT 18.300 16.840 18.590 16.885 ;
        RECT 20.135 16.840 20.425 16.885 ;
        RECT 23.715 16.840 24.005 16.885 ;
        RECT 24.795 16.865 25.085 17.180 ;
        RECT 30.700 17.165 31.020 17.225 ;
        RECT 32.170 17.225 42.060 17.365 ;
        RECT 27.480 17.025 27.800 17.085 ;
        RECT 28.415 17.025 28.705 17.070 ;
        RECT 29.780 17.025 30.100 17.085 ;
        RECT 32.170 17.025 32.310 17.225 ;
        RECT 41.740 17.165 42.060 17.225 ;
        RECT 51.415 17.180 51.705 17.410 ;
        RECT 53.695 17.365 54.345 17.410 ;
        RECT 57.295 17.365 57.585 17.410 ;
        RECT 53.695 17.225 57.585 17.365 ;
        RECT 53.695 17.180 54.345 17.225 ;
        RECT 56.995 17.180 57.585 17.225 ;
        RECT 68.895 17.180 69.185 17.410 ;
        RECT 71.175 17.365 71.825 17.410 ;
        RECT 74.775 17.365 75.065 17.410 ;
        RECT 71.175 17.225 75.065 17.365 ;
        RECT 71.175 17.180 71.825 17.225 ;
        RECT 74.475 17.180 75.065 17.225 ;
        RECT 53.700 17.165 54.020 17.180 ;
        RECT 27.480 16.885 32.310 17.025 ;
        RECT 32.555 17.025 32.845 17.070 ;
        RECT 35.315 17.025 35.605 17.070 ;
        RECT 32.555 16.885 35.605 17.025 ;
        RECT 27.480 16.825 27.800 16.885 ;
        RECT 28.415 16.840 28.705 16.885 ;
        RECT 29.780 16.825 30.100 16.885 ;
        RECT 32.555 16.840 32.845 16.885 ;
        RECT 35.315 16.840 35.605 16.885 ;
        RECT 35.775 17.025 36.065 17.070 ;
        RECT 37.615 17.025 37.905 17.070 ;
        RECT 35.775 16.885 37.905 17.025 ;
        RECT 35.775 16.840 36.065 16.885 ;
        RECT 37.615 16.840 37.905 16.885 ;
        RECT 50.500 17.025 50.790 17.070 ;
        RECT 52.335 17.025 52.625 17.070 ;
        RECT 55.915 17.025 56.205 17.070 ;
        RECT 50.500 16.885 56.205 17.025 ;
        RECT 50.500 16.840 50.790 16.885 ;
        RECT 52.335 16.840 52.625 16.885 ;
        RECT 55.915 16.840 56.205 16.885 ;
        RECT 56.995 16.865 57.285 17.180 ;
        RECT 71.180 17.165 71.500 17.180 ;
        RECT 57.840 17.025 58.160 17.085 ;
        RECT 59.695 17.025 59.985 17.070 ;
        RECT 57.840 16.885 59.985 17.025 ;
        RECT 17.820 16.485 18.140 16.745 ;
        RECT 19.200 16.485 19.520 16.745 ;
        RECT 31.175 16.500 31.465 16.730 ;
        RECT 34.380 16.685 34.700 16.745 ;
        RECT 34.855 16.685 35.145 16.730 ;
        RECT 34.380 16.545 35.145 16.685 ;
        RECT 35.390 16.685 35.530 16.840 ;
        RECT 57.840 16.825 58.160 16.885 ;
        RECT 59.695 16.840 59.985 16.885 ;
        RECT 61.075 17.025 61.365 17.070 ;
        RECT 62.440 17.025 62.760 17.085 ;
        RECT 61.075 16.885 62.760 17.025 ;
        RECT 61.075 16.840 61.365 16.885 ;
        RECT 62.440 16.825 62.760 16.885 ;
        RECT 67.980 17.025 68.270 17.070 ;
        RECT 69.815 17.025 70.105 17.070 ;
        RECT 73.395 17.025 73.685 17.070 ;
        RECT 67.980 16.885 73.685 17.025 ;
        RECT 67.980 16.840 68.270 16.885 ;
        RECT 69.815 16.840 70.105 16.885 ;
        RECT 73.395 16.840 73.685 16.885 ;
        RECT 74.475 16.865 74.765 17.180 ;
        RECT 36.680 16.685 37.000 16.745 ;
        RECT 35.390 16.545 37.000 16.685 ;
        RECT 18.705 16.345 18.995 16.390 ;
        RECT 20.595 16.345 20.885 16.390 ;
        RECT 23.715 16.345 24.005 16.390 ;
        RECT 18.705 16.205 24.005 16.345 ;
        RECT 31.250 16.345 31.390 16.500 ;
        RECT 34.380 16.485 34.700 16.545 ;
        RECT 34.855 16.500 35.145 16.545 ;
        RECT 36.680 16.485 37.000 16.545 ;
        RECT 39.455 16.500 39.745 16.730 ;
        RECT 33.000 16.345 33.320 16.405 ;
        RECT 39.530 16.345 39.670 16.500 ;
        RECT 50.020 16.485 50.340 16.745 ;
        RECT 63.820 16.485 64.140 16.745 ;
        RECT 64.280 16.485 64.600 16.745 ;
        RECT 65.200 16.685 65.520 16.745 ;
        RECT 67.515 16.685 67.805 16.730 ;
        RECT 65.200 16.545 67.805 16.685 ;
        RECT 65.200 16.485 65.520 16.545 ;
        RECT 67.515 16.500 67.805 16.545 ;
        RECT 43.120 16.345 43.440 16.405 ;
        RECT 31.250 16.205 33.320 16.345 ;
        RECT 18.705 16.160 18.995 16.205 ;
        RECT 20.595 16.160 20.885 16.205 ;
        RECT 23.715 16.160 24.005 16.205 ;
        RECT 33.000 16.145 33.320 16.205 ;
        RECT 34.930 16.205 43.440 16.345 ;
        RECT 26.560 15.805 26.880 16.065 ;
        RECT 27.940 15.805 28.260 16.065 ;
        RECT 28.400 16.005 28.720 16.065 ;
        RECT 29.335 16.005 29.625 16.050 ;
        RECT 28.400 15.865 29.625 16.005 ;
        RECT 28.400 15.805 28.720 15.865 ;
        RECT 29.335 15.820 29.625 15.865 ;
        RECT 29.780 16.005 30.100 16.065 ;
        RECT 34.930 16.005 35.070 16.205 ;
        RECT 43.120 16.145 43.440 16.205 ;
        RECT 50.905 16.345 51.195 16.390 ;
        RECT 52.795 16.345 53.085 16.390 ;
        RECT 55.915 16.345 56.205 16.390 ;
        RECT 50.905 16.205 56.205 16.345 ;
        RECT 50.905 16.160 51.195 16.205 ;
        RECT 52.795 16.160 53.085 16.205 ;
        RECT 55.915 16.160 56.205 16.205 ;
        RECT 59.680 16.345 60.000 16.405 ;
        RECT 61.075 16.345 61.365 16.390 ;
        RECT 59.680 16.205 61.365 16.345 ;
        RECT 63.910 16.345 64.050 16.485 ;
        RECT 68.385 16.345 68.675 16.390 ;
        RECT 70.275 16.345 70.565 16.390 ;
        RECT 73.395 16.345 73.685 16.390 ;
        RECT 63.910 16.205 64.510 16.345 ;
        RECT 59.680 16.145 60.000 16.205 ;
        RECT 61.075 16.160 61.365 16.205 ;
        RECT 29.780 15.865 35.070 16.005 ;
        RECT 35.315 16.005 35.605 16.050 ;
        RECT 36.235 16.005 36.525 16.050 ;
        RECT 35.315 15.865 36.525 16.005 ;
        RECT 64.370 16.005 64.510 16.205 ;
        RECT 68.385 16.205 73.685 16.345 ;
        RECT 68.385 16.160 68.675 16.205 ;
        RECT 70.275 16.160 70.565 16.205 ;
        RECT 73.395 16.160 73.685 16.205 ;
        RECT 73.940 16.005 74.260 16.065 ;
        RECT 64.370 15.865 74.260 16.005 ;
        RECT 29.780 15.805 30.100 15.865 ;
        RECT 35.315 15.820 35.605 15.865 ;
        RECT 36.235 15.820 36.525 15.865 ;
        RECT 73.940 15.805 74.260 15.865 ;
        RECT 15.450 15.185 82.150 15.665 ;
        RECT 19.215 14.985 19.505 15.030 ;
        RECT 20.120 14.985 20.440 15.045 ;
        RECT 19.215 14.845 20.440 14.985 ;
        RECT 19.215 14.800 19.505 14.845 ;
        RECT 20.120 14.785 20.440 14.845 ;
        RECT 33.920 14.985 34.240 15.045 ;
        RECT 55.555 14.985 55.845 15.030 ;
        RECT 57.840 14.985 58.160 15.045 ;
        RECT 33.920 14.845 41.050 14.985 ;
        RECT 33.920 14.785 34.240 14.845 ;
        RECT 22.075 14.645 22.365 14.690 ;
        RECT 25.195 14.645 25.485 14.690 ;
        RECT 27.085 14.645 27.375 14.690 ;
        RECT 22.075 14.505 27.375 14.645 ;
        RECT 22.075 14.460 22.365 14.505 ;
        RECT 25.195 14.460 25.485 14.505 ;
        RECT 27.085 14.460 27.375 14.505 ;
        RECT 30.700 14.645 31.020 14.705 ;
        RECT 34.380 14.645 34.700 14.705 ;
        RECT 30.700 14.505 34.700 14.645 ;
        RECT 30.700 14.445 31.020 14.505 ;
        RECT 34.380 14.445 34.700 14.505 ;
        RECT 35.265 14.645 35.555 14.690 ;
        RECT 37.155 14.645 37.445 14.690 ;
        RECT 40.275 14.645 40.565 14.690 ;
        RECT 35.265 14.505 40.565 14.645 ;
        RECT 35.265 14.460 35.555 14.505 ;
        RECT 37.155 14.460 37.445 14.505 ;
        RECT 40.275 14.460 40.565 14.505 ;
        RECT 17.820 14.305 18.140 14.365 ;
        RECT 27.955 14.305 28.245 14.350 ;
        RECT 17.820 14.165 28.245 14.305 ;
        RECT 17.820 14.105 18.140 14.165 ;
        RECT 27.955 14.120 28.245 14.165 ;
        RECT 32.095 14.305 32.385 14.350 ;
        RECT 33.460 14.305 33.780 14.365 ;
        RECT 32.095 14.165 33.780 14.305 ;
        RECT 32.095 14.120 32.385 14.165 ;
        RECT 33.460 14.105 33.780 14.165 ;
        RECT 35.775 14.305 36.065 14.350 ;
        RECT 36.220 14.305 36.540 14.365 ;
        RECT 35.775 14.165 36.540 14.305 ;
        RECT 40.910 14.305 41.050 14.845 ;
        RECT 55.555 14.845 58.160 14.985 ;
        RECT 55.555 14.800 55.845 14.845 ;
        RECT 57.840 14.785 58.160 14.845 ;
        RECT 69.815 14.985 70.105 15.030 ;
        RECT 71.180 14.985 71.500 15.045 ;
        RECT 69.815 14.845 71.500 14.985 ;
        RECT 69.815 14.800 70.105 14.845 ;
        RECT 71.180 14.785 71.500 14.845 ;
        RECT 43.120 14.445 43.440 14.705 ;
        RECT 45.420 14.445 45.740 14.705 ;
        RECT 53.255 14.645 53.545 14.690 ;
        RECT 56.920 14.645 57.240 14.705 ;
        RECT 53.255 14.505 57.240 14.645 ;
        RECT 53.255 14.460 53.545 14.505 ;
        RECT 56.920 14.445 57.240 14.505 ;
        RECT 59.185 14.645 59.475 14.690 ;
        RECT 61.075 14.645 61.365 14.690 ;
        RECT 64.195 14.645 64.485 14.690 ;
        RECT 59.185 14.505 64.485 14.645 ;
        RECT 59.185 14.460 59.475 14.505 ;
        RECT 61.075 14.460 61.365 14.505 ;
        RECT 64.195 14.460 64.485 14.505 ;
        RECT 45.510 14.305 45.650 14.445 ;
        RECT 40.910 14.165 44.500 14.305 ;
        RECT 35.775 14.120 36.065 14.165 ;
        RECT 36.220 14.105 36.540 14.165 ;
        RECT 20.995 13.670 21.285 13.985 ;
        RECT 22.075 13.965 22.365 14.010 ;
        RECT 25.655 13.965 25.945 14.010 ;
        RECT 27.490 13.965 27.780 14.010 ;
        RECT 22.075 13.825 27.780 13.965 ;
        RECT 22.075 13.780 22.365 13.825 ;
        RECT 25.655 13.780 25.945 13.825 ;
        RECT 27.490 13.780 27.780 13.825 ;
        RECT 28.860 13.965 29.180 14.025 ;
        RECT 30.715 13.965 31.005 14.010 ;
        RECT 28.860 13.825 31.005 13.965 ;
        RECT 28.860 13.765 29.180 13.825 ;
        RECT 30.715 13.780 31.005 13.825 ;
        RECT 31.620 13.965 31.940 14.025 ;
        RECT 34.395 13.965 34.685 14.010 ;
        RECT 31.620 13.825 34.685 13.965 ;
        RECT 31.620 13.765 31.940 13.825 ;
        RECT 34.395 13.780 34.685 13.825 ;
        RECT 34.860 13.965 35.150 14.010 ;
        RECT 36.695 13.965 36.985 14.010 ;
        RECT 40.275 13.965 40.565 14.010 ;
        RECT 34.860 13.825 40.565 13.965 ;
        RECT 34.860 13.780 35.150 13.825 ;
        RECT 36.695 13.780 36.985 13.825 ;
        RECT 40.275 13.780 40.565 13.825 ;
        RECT 24.260 13.670 24.580 13.685 ;
        RECT 20.695 13.625 21.285 13.670 ;
        RECT 23.935 13.625 24.585 13.670 ;
        RECT 20.695 13.485 24.585 13.625 ;
        RECT 20.695 13.440 20.985 13.485 ;
        RECT 23.935 13.440 24.585 13.485 ;
        RECT 26.575 13.440 26.865 13.670 ;
        RECT 38.055 13.625 38.705 13.670 ;
        RECT 38.980 13.625 39.300 13.685 ;
        RECT 41.355 13.670 41.645 13.985 ;
        RECT 41.355 13.625 41.945 13.670 ;
        RECT 38.055 13.485 41.945 13.625 ;
        RECT 44.360 13.625 44.500 14.165 ;
        RECT 45.050 14.165 45.650 14.305 ;
        RECT 53.715 14.305 54.005 14.350 ;
        RECT 55.555 14.305 55.845 14.350 ;
        RECT 53.715 14.165 55.845 14.305 ;
        RECT 45.050 14.010 45.190 14.165 ;
        RECT 53.715 14.120 54.005 14.165 ;
        RECT 55.555 14.120 55.845 14.165 ;
        RECT 59.680 14.105 60.000 14.365 ;
        RECT 65.660 14.105 65.980 14.365 ;
        RECT 44.975 13.780 45.265 14.010 ;
        RECT 45.895 13.965 46.185 14.010 ;
        RECT 48.180 13.965 48.500 14.025 ;
        RECT 45.895 13.825 48.500 13.965 ;
        RECT 45.895 13.780 46.185 13.825 ;
        RECT 48.180 13.765 48.500 13.825 ;
        RECT 48.640 13.765 48.960 14.025 ;
        RECT 51.185 13.965 51.475 14.010 ;
        RECT 56.460 13.965 56.780 14.025 ;
        RECT 49.190 13.825 56.780 13.965 ;
        RECT 49.190 13.625 49.330 13.825 ;
        RECT 51.185 13.780 51.475 13.825 ;
        RECT 56.460 13.765 56.780 13.825 ;
        RECT 57.380 13.765 57.700 14.025 ;
        RECT 58.315 13.780 58.605 14.010 ;
        RECT 58.780 13.965 59.070 14.010 ;
        RECT 60.615 13.965 60.905 14.010 ;
        RECT 64.195 13.965 64.485 14.010 ;
        RECT 58.780 13.825 64.485 13.965 ;
        RECT 58.780 13.780 59.070 13.825 ;
        RECT 60.615 13.780 60.905 13.825 ;
        RECT 64.195 13.780 64.485 13.825 ;
        RECT 44.360 13.485 49.330 13.625 ;
        RECT 49.575 13.625 49.865 13.670 ;
        RECT 51.860 13.625 52.180 13.685 ;
        RECT 49.575 13.485 52.180 13.625 ;
        RECT 58.390 13.625 58.530 13.780 ;
        RECT 61.060 13.625 61.380 13.685 ;
        RECT 65.275 13.670 65.565 13.985 ;
        RECT 65.750 13.965 65.890 14.105 ;
        RECT 69.355 13.965 69.645 14.010 ;
        RECT 65.750 13.825 69.645 13.965 ;
        RECT 69.355 13.780 69.645 13.825 ;
        RECT 58.390 13.485 61.380 13.625 ;
        RECT 38.055 13.440 38.705 13.485 ;
        RECT 24.260 13.425 24.580 13.440 ;
        RECT 26.650 13.285 26.790 13.440 ;
        RECT 38.980 13.425 39.300 13.485 ;
        RECT 41.655 13.440 41.945 13.485 ;
        RECT 49.575 13.440 49.865 13.485 ;
        RECT 51.860 13.425 52.180 13.485 ;
        RECT 61.060 13.425 61.380 13.485 ;
        RECT 61.975 13.625 62.625 13.670 ;
        RECT 65.275 13.625 65.865 13.670 ;
        RECT 66.120 13.625 66.440 13.685 ;
        RECT 89.250 13.635 89.570 23.965 ;
        RECT 89.890 13.635 90.850 22.015 ;
        RECT 91.340 21.015 92.280 33.675 ;
        RECT 93.780 28.855 94.100 33.455 ;
        RECT 94.420 21.005 95.380 32.455 ;
        RECT 95.700 28.855 96.660 37.025 ;
        RECT 97.220 34.695 98.180 34.725 ;
        RECT 97.190 33.675 98.210 34.695 ;
        RECT 98.530 34.105 98.850 37.355 ;
        RECT 97.220 33.645 98.180 33.675 ;
        RECT 99.170 33.425 100.130 37.705 ;
        RECT 100.450 34.105 101.410 37.705 ;
        RECT 99.120 33.105 100.130 33.425 ;
        RECT 99.150 33.035 100.130 33.105 ;
        RECT 100.780 33.115 101.290 33.435 ;
        RECT 100.780 33.105 101.250 33.115 ;
        RECT 99.150 27.205 99.470 33.035 ;
        RECT 100.780 28.855 101.100 33.105 ;
        RECT 102.830 32.455 103.790 34.025 ;
        RECT 104.330 33.995 105.290 39.275 ;
        RECT 107.790 37.775 108.110 39.435 ;
        RECT 108.430 37.775 109.390 39.435 ;
        RECT 107.770 34.175 108.110 37.775 ;
        RECT 108.410 34.175 109.390 37.775 ;
        RECT 109.690 34.495 110.650 43.035 ;
        RECT 112.250 42.945 113.210 45.565 ;
        RECT 114.310 43.665 115.310 45.215 ;
        RECT 114.330 42.760 115.290 43.665 ;
        RECT 115.830 42.760 116.790 53.210 ;
        RECT 131.500 51.740 132.270 52.480 ;
        RECT 119.120 46.225 119.440 50.675 ;
        RECT 121.010 50.645 122.030 51.605 ;
        RECT 119.760 46.160 120.720 49.825 ;
        RECT 121.040 46.225 122.000 50.645 ;
        RECT 134.950 50.095 135.830 50.135 ;
        RECT 134.950 49.795 136.450 50.095 ;
        RECT 132.250 48.995 133.130 49.335 ;
        RECT 134.950 48.995 135.830 49.335 ;
        RECT 132.250 48.495 133.130 48.535 ;
        RECT 132.250 48.195 133.750 48.495 ;
        RECT 130.450 47.795 131.330 48.135 ;
        RECT 130.450 46.495 131.330 46.535 ;
        RECT 119.090 44.795 119.410 45.165 ;
        RECT 119.080 44.640 119.410 44.795 ;
        RECT 119.050 44.320 119.430 44.640 ;
        RECT 119.720 44.615 120.720 46.160 ;
        RECT 114.330 41.800 116.790 42.760 ;
        RECT 109.690 34.415 110.660 34.495 ;
        RECT 104.300 33.035 105.320 33.995 ;
        RECT 107.790 33.465 108.110 34.175 ;
        RECT 107.760 33.065 108.160 33.465 ;
        RECT 101.420 27.255 102.380 32.455 ;
        RECT 102.700 32.035 103.790 32.455 ;
        RECT 102.700 28.855 103.660 32.035 ;
        RECT 107.790 28.855 108.110 33.065 ;
        RECT 108.430 30.175 109.390 34.175 ;
        RECT 109.560 34.015 110.660 34.415 ;
        RECT 109.700 32.455 110.660 34.015 ;
        RECT 109.700 31.495 110.670 32.455 ;
        RECT 108.420 28.855 109.390 30.175 ;
        RECT 109.710 29.955 110.670 31.495 ;
        RECT 109.700 28.935 110.670 29.955 ;
        RECT 109.710 28.855 110.670 28.935 ;
        RECT 96.780 24.045 97.100 27.205 ;
        RECT 96.560 23.605 97.100 24.045 ;
        RECT 96.560 23.485 97.060 23.605 ;
        RECT 97.420 21.005 98.380 27.205 ;
        RECT 98.700 23.605 99.660 27.205 ;
        RECT 102.830 20.415 103.790 28.275 ;
        RECT 108.420 21.005 109.380 28.855 ;
        RECT 114.330 21.005 115.290 41.800 ;
        RECT 115.660 38.025 116.040 38.345 ;
        RECT 115.690 33.735 116.010 38.025 ;
        RECT 116.330 33.735 117.290 40.385 ;
        RECT 119.080 39.015 119.400 44.320 ;
        RECT 119.700 44.315 120.720 44.615 ;
        RECT 129.850 46.195 131.330 46.495 ;
        RECT 119.700 44.215 120.680 44.315 ;
        RECT 119.720 43.935 120.680 44.215 ;
        RECT 119.690 42.975 120.710 43.935 ;
        RECT 127.450 42.975 128.470 43.935 ;
        RECT 119.720 40.415 120.680 42.975 ;
        RECT 119.720 39.395 120.690 40.415 ;
        RECT 119.720 39.015 120.680 39.395 ;
        RECT 121.000 39.015 121.960 42.615 ;
        RECT 121.300 37.995 121.620 39.015 ;
        RECT 122.520 38.025 122.900 38.345 ;
        RECT 122.550 37.345 122.870 38.025 ;
        RECT 102.830 20.015 104.020 20.415 ;
        RECT 91.170 13.635 92.130 19.365 ;
        RECT 61.975 13.485 66.440 13.625 ;
        RECT 61.975 13.440 62.625 13.485 ;
        RECT 65.575 13.440 65.865 13.485 ;
        RECT 66.120 13.425 66.440 13.485 ;
        RECT 28.875 13.285 29.165 13.330 ;
        RECT 26.650 13.145 29.165 13.285 ;
        RECT 28.875 13.100 29.165 13.145 ;
        RECT 31.160 13.285 31.480 13.345 ;
        RECT 36.680 13.285 37.000 13.345 ;
        RECT 31.160 13.145 37.000 13.285 ;
        RECT 31.160 13.085 31.480 13.145 ;
        RECT 36.680 13.085 37.000 13.145 ;
        RECT 45.420 13.085 45.740 13.345 ;
        RECT 48.640 13.285 48.960 13.345 ;
        RECT 50.495 13.285 50.785 13.330 ;
        RECT 48.640 13.145 50.785 13.285 ;
        RECT 48.640 13.085 48.960 13.145 ;
        RECT 50.495 13.100 50.785 13.145 ;
        RECT 51.415 13.285 51.705 13.330 ;
        RECT 57.840 13.285 58.160 13.345 ;
        RECT 51.415 13.145 58.160 13.285 ;
        RECT 51.415 13.100 51.705 13.145 ;
        RECT 57.840 13.085 58.160 13.145 ;
        RECT 64.280 13.285 64.600 13.345 ;
        RECT 67.055 13.285 67.345 13.330 ;
        RECT 64.280 13.145 67.345 13.285 ;
        RECT 64.280 13.085 64.600 13.145 ;
        RECT 67.055 13.100 67.345 13.145 ;
        RECT 15.450 12.465 82.150 12.945 ;
        RECT 29.795 12.265 30.085 12.310 ;
        RECT 31.160 12.265 31.480 12.325 ;
        RECT 33.920 12.265 34.240 12.325 ;
        RECT 29.795 12.125 31.480 12.265 ;
        RECT 29.795 12.080 30.085 12.125 ;
        RECT 31.160 12.065 31.480 12.125 ;
        RECT 32.630 12.125 34.240 12.265 ;
        RECT 22.875 11.925 23.525 11.970 ;
        RECT 26.475 11.925 26.765 11.970 ;
        RECT 27.940 11.925 28.260 11.985 ;
        RECT 22.875 11.785 28.260 11.925 ;
        RECT 22.875 11.740 23.525 11.785 ;
        RECT 26.175 11.740 26.765 11.785 ;
        RECT 17.820 11.585 18.140 11.645 ;
        RECT 19.215 11.585 19.505 11.630 ;
        RECT 17.820 11.445 19.505 11.585 ;
        RECT 17.820 11.385 18.140 11.445 ;
        RECT 19.215 11.400 19.505 11.445 ;
        RECT 19.680 11.585 19.970 11.630 ;
        RECT 21.515 11.585 21.805 11.630 ;
        RECT 25.095 11.585 25.385 11.630 ;
        RECT 19.680 11.445 25.385 11.585 ;
        RECT 19.680 11.400 19.970 11.445 ;
        RECT 21.515 11.400 21.805 11.445 ;
        RECT 25.095 11.400 25.385 11.445 ;
        RECT 26.175 11.425 26.465 11.740 ;
        RECT 27.940 11.725 28.260 11.785 ;
        RECT 28.875 11.925 29.165 11.970 ;
        RECT 30.240 11.925 30.560 11.985 ;
        RECT 32.630 11.925 32.770 12.125 ;
        RECT 33.920 12.065 34.240 12.125 ;
        RECT 36.680 12.265 37.000 12.325 ;
        RECT 40.375 12.265 40.665 12.310 ;
        RECT 36.680 12.125 40.665 12.265 ;
        RECT 36.680 12.065 37.000 12.125 ;
        RECT 40.375 12.080 40.665 12.125 ;
        RECT 57.840 12.265 58.160 12.325 ;
        RECT 58.775 12.265 59.065 12.310 ;
        RECT 60.615 12.265 60.905 12.310 ;
        RECT 57.840 12.125 60.905 12.265 ;
        RECT 57.840 12.065 58.160 12.125 ;
        RECT 58.775 12.080 59.065 12.125 ;
        RECT 60.615 12.080 60.905 12.125 ;
        RECT 66.120 12.065 66.440 12.325 ;
        RECT 28.875 11.785 30.560 11.925 ;
        RECT 28.875 11.740 29.165 11.785 ;
        RECT 30.240 11.725 30.560 11.785 ;
        RECT 31.250 11.785 32.770 11.925 ;
        RECT 31.250 11.630 31.390 11.785 ;
        RECT 33.000 11.725 33.320 11.985 ;
        RECT 35.295 11.925 35.945 11.970 ;
        RECT 38.895 11.925 39.185 11.970 ;
        RECT 45.420 11.925 45.740 11.985 ;
        RECT 35.295 11.785 45.740 11.925 ;
        RECT 35.295 11.740 35.945 11.785 ;
        RECT 38.595 11.740 39.185 11.785 ;
        RECT 31.175 11.400 31.465 11.630 ;
        RECT 32.100 11.585 32.390 11.630 ;
        RECT 33.935 11.585 34.225 11.630 ;
        RECT 37.515 11.585 37.805 11.630 ;
        RECT 32.100 11.445 37.805 11.585 ;
        RECT 32.100 11.400 32.390 11.445 ;
        RECT 33.935 11.400 34.225 11.445 ;
        RECT 37.515 11.400 37.805 11.445 ;
        RECT 38.595 11.425 38.885 11.740 ;
        RECT 45.420 11.725 45.740 11.785 ;
        RECT 48.640 11.725 48.960 11.985 ;
        RECT 50.935 11.925 51.585 11.970 ;
        RECT 51.860 11.925 52.180 11.985 ;
        RECT 54.535 11.925 54.825 11.970 ;
        RECT 50.935 11.785 54.825 11.925 ;
        RECT 50.935 11.740 51.585 11.785 ;
        RECT 51.860 11.725 52.180 11.785 ;
        RECT 54.235 11.740 54.825 11.785 ;
        RECT 56.460 11.925 56.780 11.985 ;
        RECT 56.460 11.785 58.530 11.925 ;
        RECT 47.740 11.585 48.030 11.630 ;
        RECT 49.575 11.585 49.865 11.630 ;
        RECT 53.155 11.585 53.445 11.630 ;
        RECT 47.740 11.445 53.445 11.585 ;
        RECT 47.740 11.400 48.030 11.445 ;
        RECT 49.575 11.400 49.865 11.445 ;
        RECT 53.155 11.400 53.445 11.445 ;
        RECT 54.235 11.425 54.525 11.740 ;
        RECT 56.460 11.725 56.780 11.785 ;
        RECT 56.920 11.585 57.240 11.645 ;
        RECT 56.090 11.445 57.240 11.585 ;
        RECT 20.595 11.245 20.885 11.290 ;
        RECT 23.340 11.245 23.660 11.305 ;
        RECT 20.595 11.105 23.660 11.245 ;
        RECT 20.595 11.060 20.885 11.105 ;
        RECT 23.340 11.045 23.660 11.105 ;
        RECT 31.620 11.245 31.940 11.305 ;
        RECT 34.840 11.245 35.160 11.305 ;
        RECT 56.090 11.290 56.230 11.445 ;
        RECT 56.920 11.385 57.240 11.445 ;
        RECT 57.380 11.585 57.700 11.645 ;
        RECT 57.855 11.585 58.145 11.630 ;
        RECT 57.380 11.445 58.145 11.585 ;
        RECT 58.390 11.585 58.530 11.785 ;
        RECT 59.680 11.725 60.000 11.985 ;
        RECT 62.440 11.725 62.760 11.985 ;
        RECT 77.620 11.925 77.940 11.985 ;
        RECT 66.670 11.785 77.940 11.925 ;
        RECT 62.915 11.585 63.205 11.630 ;
        RECT 58.390 11.445 63.205 11.585 ;
        RECT 57.380 11.385 57.700 11.445 ;
        RECT 57.855 11.400 58.145 11.445 ;
        RECT 62.915 11.400 63.205 11.445 ;
        RECT 47.275 11.245 47.565 11.290 ;
        RECT 31.620 11.105 54.390 11.245 ;
        RECT 31.620 11.045 31.940 11.105 ;
        RECT 34.840 11.045 35.160 11.105 ;
        RECT 47.275 11.060 47.565 11.105 ;
        RECT 20.085 10.905 20.375 10.950 ;
        RECT 21.975 10.905 22.265 10.950 ;
        RECT 25.095 10.905 25.385 10.950 ;
        RECT 20.085 10.765 25.385 10.905 ;
        RECT 20.085 10.720 20.375 10.765 ;
        RECT 21.975 10.720 22.265 10.765 ;
        RECT 25.095 10.720 25.385 10.765 ;
        RECT 27.955 10.905 28.245 10.950 ;
        RECT 32.505 10.905 32.795 10.950 ;
        RECT 34.395 10.905 34.685 10.950 ;
        RECT 37.515 10.905 37.805 10.950 ;
        RECT 27.955 10.765 31.390 10.905 ;
        RECT 27.955 10.720 28.245 10.765 ;
        RECT 19.660 10.565 19.980 10.625 ;
        RECT 28.030 10.565 28.170 10.720 ;
        RECT 19.660 10.425 28.170 10.565 ;
        RECT 19.660 10.365 19.980 10.425 ;
        RECT 29.780 10.365 30.100 10.625 ;
        RECT 31.250 10.565 31.390 10.765 ;
        RECT 32.505 10.765 37.805 10.905 ;
        RECT 32.505 10.720 32.795 10.765 ;
        RECT 34.395 10.720 34.685 10.765 ;
        RECT 37.515 10.720 37.805 10.765 ;
        RECT 48.145 10.905 48.435 10.950 ;
        RECT 50.035 10.905 50.325 10.950 ;
        RECT 53.155 10.905 53.445 10.950 ;
        RECT 48.145 10.765 53.445 10.905 ;
        RECT 54.250 10.905 54.390 11.105 ;
        RECT 56.015 11.060 56.305 11.290 ;
        RECT 57.930 11.245 58.070 11.400 ;
        RECT 64.280 11.385 64.600 11.645 ;
        RECT 65.660 11.385 65.980 11.645 ;
        RECT 66.120 11.585 66.440 11.645 ;
        RECT 66.670 11.630 66.810 11.785 ;
        RECT 77.620 11.725 77.940 11.785 ;
        RECT 66.595 11.585 66.885 11.630 ;
        RECT 66.120 11.445 66.885 11.585 ;
        RECT 66.120 11.385 66.440 11.445 ;
        RECT 66.595 11.400 66.885 11.445 ;
        RECT 74.875 11.585 75.165 11.630 ;
        RECT 75.795 11.585 76.085 11.630 ;
        RECT 74.875 11.445 76.085 11.585 ;
        RECT 74.875 11.400 75.165 11.445 ;
        RECT 75.795 11.400 76.085 11.445 ;
        RECT 77.175 11.585 77.465 11.630 ;
        RECT 79.460 11.585 79.780 11.645 ;
        RECT 77.175 11.445 79.780 11.585 ;
        RECT 102.830 11.575 103.790 20.015 ;
        RECT 115.690 18.635 116.010 32.045 ;
        RECT 116.330 28.445 117.290 32.045 ;
        RECT 117.610 28.445 118.570 37.335 ;
        RECT 122.540 36.985 122.870 37.345 ;
        RECT 122.540 33.745 122.860 36.985 ;
        RECT 123.180 33.745 124.140 40.415 ;
        RECT 124.460 33.745 125.420 37.345 ;
        RECT 122.540 27.395 122.860 32.990 ;
        RECT 124.465 32.045 125.415 33.745 ;
        RECT 123.180 29.935 124.140 32.045 ;
        RECT 123.170 28.915 124.140 29.935 ;
        RECT 123.180 28.445 124.140 28.915 ;
        RECT 124.460 27.535 125.420 32.045 ;
        RECT 127.495 30.200 128.425 42.975 ;
        RECT 129.850 41.375 130.150 46.195 ;
        RECT 132.250 45.795 133.130 46.135 ;
        RECT 132.250 45.295 133.130 45.335 ;
        RECT 133.450 45.295 133.750 48.195 ;
        RECT 136.150 47.295 136.450 49.795 ;
        RECT 136.750 47.295 137.630 47.335 ;
        RECT 136.150 46.995 137.630 47.295 ;
        RECT 134.950 46.595 135.830 46.935 ;
        RECT 132.250 44.995 133.750 45.295 ;
        RECT 132.250 43.395 133.130 43.735 ;
        RECT 130.450 42.495 131.330 42.535 ;
        RECT 130.450 42.195 131.950 42.495 ;
        RECT 129.820 41.075 130.180 41.375 ;
        RECT 131.650 41.295 131.950 42.195 ;
        RECT 132.250 41.795 133.130 42.135 ;
        RECT 132.250 41.295 133.130 41.335 ;
        RECT 129.850 34.495 130.150 41.075 ;
        RECT 131.650 40.995 133.130 41.295 ;
        RECT 132.250 39.395 133.130 39.735 ;
        RECT 130.450 38.495 131.330 38.535 ;
        RECT 130.450 38.195 131.350 38.495 ;
        RECT 133.450 38.265 133.750 44.995 ;
        RECT 136.750 44.895 137.630 44.935 ;
        RECT 136.750 44.595 138.250 44.895 ;
        RECT 136.750 44.095 137.630 44.135 ;
        RECT 136.150 43.795 137.630 44.095 ;
        RECT 134.950 43.395 135.830 43.735 ;
        RECT 134.950 42.895 135.830 42.935 ;
        RECT 136.150 42.895 136.450 43.795 ;
        RECT 134.950 42.595 136.450 42.895 ;
        RECT 134.950 41.795 135.830 42.135 ;
        RECT 136.150 40.095 136.450 42.595 ;
        RECT 136.750 40.895 137.630 40.935 ;
        RECT 137.950 40.895 138.250 44.595 ;
        RECT 136.750 40.595 138.250 40.895 ;
        RECT 136.750 40.095 137.630 40.135 ;
        RECT 136.150 39.795 137.630 40.095 ;
        RECT 134.950 39.395 135.830 39.735 ;
        RECT 131.050 37.895 131.950 38.195 ;
        RECT 133.450 37.965 137.380 38.265 ;
        RECT 131.650 34.895 131.950 37.895 ;
        RECT 137.080 37.375 137.380 37.965 ;
        RECT 132.250 36.995 133.130 37.335 ;
        RECT 134.950 36.995 135.830 37.335 ;
        RECT 132.250 35.395 133.130 35.735 ;
        RECT 134.950 35.395 135.830 35.735 ;
        RECT 132.250 34.895 133.130 34.935 ;
        RECT 131.650 34.595 133.130 34.895 ;
        RECT 134.950 34.595 135.830 34.935 ;
        RECT 130.450 34.495 131.330 34.535 ;
        RECT 129.850 34.195 131.330 34.495 ;
        RECT 134.950 34.095 135.830 34.135 ;
        RECT 137.950 34.095 138.250 40.595 ;
        RECT 134.950 33.795 138.250 34.095 ;
        RECT 132.250 32.995 133.130 33.335 ;
        RECT 134.950 32.995 135.830 33.335 ;
        RECT 130.610 31.275 130.910 32.705 ;
        RECT 132.250 32.195 133.130 32.535 ;
        RECT 134.950 32.195 135.830 32.535 ;
        RECT 132.250 31.395 133.130 31.735 ;
        RECT 134.950 31.395 135.830 31.735 ;
        RECT 130.610 31.015 131.050 31.275 ;
        RECT 130.550 30.715 131.050 31.015 ;
        RECT 127.465 29.270 128.455 30.200 ;
        RECT 124.460 27.395 125.430 27.535 ;
        RECT 119.930 26.515 120.490 27.015 ;
        RECT 119.960 24.015 120.460 26.515 ;
        RECT 119.930 23.515 120.490 24.015 ;
        RECT 122.550 22.485 122.870 27.025 ;
        RECT 123.190 21.005 124.150 26.085 ;
        RECT 124.470 22.485 125.430 27.395 ;
        RECT 127.495 26.430 128.425 29.270 ;
        RECT 129.950 24.895 130.310 25.195 ;
        RECT 129.980 23.665 130.280 24.895 ;
        RECT 129.950 23.365 130.310 23.665 ;
        RECT 128.820 21.315 129.340 21.715 ;
        RECT 130.730 13.565 131.050 30.715 ;
        RECT 132.240 27.085 133.120 27.425 ;
        RECT 134.940 27.085 135.820 27.425 ;
        RECT 135.220 25.685 135.620 25.715 ;
        RECT 135.190 25.225 135.650 25.685 ;
        RECT 135.220 25.195 135.620 25.225 ;
        RECT 132.230 22.985 133.110 23.325 ;
        RECT 134.930 22.985 135.810 23.325 ;
        RECT 131.370 13.565 132.330 22.015 ;
        RECT 132.650 13.565 133.610 19.415 ;
        RECT 77.175 11.400 77.465 11.445 ;
        RECT 64.370 11.245 64.510 11.385 ;
        RECT 57.930 11.105 64.510 11.245 ;
        RECT 65.750 11.245 65.890 11.385 ;
        RECT 71.640 11.245 71.960 11.305 ;
        RECT 74.950 11.245 75.090 11.400 ;
        RECT 79.460 11.385 79.780 11.445 ;
        RECT 65.750 11.105 75.090 11.245 ;
        RECT 71.640 11.045 71.960 11.105 ;
        RECT 61.060 10.905 61.380 10.965 ;
        RECT 54.250 10.765 61.380 10.905 ;
        RECT 48.145 10.720 48.435 10.765 ;
        RECT 50.035 10.720 50.325 10.765 ;
        RECT 53.155 10.720 53.445 10.765 ;
        RECT 61.060 10.705 61.380 10.765 ;
        RECT 33.000 10.565 33.320 10.625 ;
        RECT 31.250 10.425 33.320 10.565 ;
        RECT 33.000 10.365 33.320 10.425 ;
        RECT 56.460 10.565 56.780 10.625 ;
        RECT 60.615 10.565 60.905 10.610 ;
        RECT 56.460 10.425 60.905 10.565 ;
        RECT 56.460 10.365 56.780 10.425 ;
        RECT 60.615 10.380 60.905 10.425 ;
        RECT 61.520 10.365 61.840 10.625 ;
        RECT 72.560 10.565 72.880 10.625 ;
        RECT 73.955 10.565 74.245 10.610 ;
        RECT 72.560 10.425 74.245 10.565 ;
        RECT 72.560 10.365 72.880 10.425 ;
        RECT 73.955 10.380 74.245 10.425 ;
        RECT 75.780 10.565 76.100 10.625 ;
        RECT 76.255 10.565 76.545 10.610 ;
        RECT 75.780 10.425 76.545 10.565 ;
        RECT 75.780 10.365 76.100 10.425 ;
        RECT 76.255 10.380 76.545 10.425 ;
        RECT 80.380 10.365 80.700 10.625 ;
        RECT 15.450 9.745 82.150 10.225 ;
        RECT 19.200 9.545 19.520 9.605 ;
        RECT 19.675 9.545 19.965 9.590 ;
        RECT 19.200 9.405 19.965 9.545 ;
        RECT 19.200 9.345 19.520 9.405 ;
        RECT 19.675 9.360 19.965 9.405 ;
        RECT 23.340 9.345 23.660 9.605 ;
        RECT 66.120 9.545 66.440 9.605 ;
        RECT 51.950 9.405 66.440 9.545 ;
        RECT 29.780 9.205 30.100 9.265 ;
        RECT 50.955 9.205 51.245 9.250 ;
        RECT 25.730 9.065 30.100 9.205 ;
        RECT 19.200 8.865 19.520 8.925 ;
        RECT 25.730 8.910 25.870 9.065 ;
        RECT 29.780 9.005 30.100 9.065 ;
        RECT 39.990 9.065 51.245 9.205 ;
        RECT 19.200 8.725 23.110 8.865 ;
        RECT 19.200 8.665 19.520 8.725 ;
        RECT 18.295 8.340 18.585 8.570 ;
        RECT 20.120 8.525 20.440 8.585 ;
        RECT 22.435 8.525 22.725 8.570 ;
        RECT 20.120 8.385 22.725 8.525 ;
        RECT 22.970 8.525 23.110 8.725 ;
        RECT 25.655 8.680 25.945 8.910 ;
        RECT 26.560 8.865 26.880 8.925 ;
        RECT 33.460 8.865 33.780 8.925 ;
        RECT 26.560 8.725 33.780 8.865 ;
        RECT 26.560 8.665 26.880 8.725 ;
        RECT 33.460 8.665 33.780 8.725 ;
        RECT 29.320 8.525 29.640 8.585 ;
        RECT 22.970 8.385 29.640 8.525 ;
        RECT 18.370 8.185 18.510 8.340 ;
        RECT 20.120 8.325 20.440 8.385 ;
        RECT 22.435 8.340 22.725 8.385 ;
        RECT 29.320 8.325 29.640 8.385 ;
        RECT 30.240 8.325 30.560 8.585 ;
        RECT 39.990 8.570 40.130 9.065 ;
        RECT 50.955 9.020 51.245 9.065 ;
        RECT 39.915 8.340 40.205 8.570 ;
        RECT 40.530 8.525 40.820 8.570 ;
        RECT 40.530 8.385 42.430 8.525 ;
        RECT 40.530 8.340 40.820 8.385 ;
        RECT 21.040 8.185 21.360 8.245 ;
        RECT 18.370 8.045 21.360 8.185 ;
        RECT 21.040 7.985 21.360 8.045 ;
        RECT 21.960 8.185 22.280 8.245 ;
        RECT 31.175 8.185 31.465 8.230 ;
        RECT 21.960 8.045 31.465 8.185 ;
        RECT 21.960 7.985 22.280 8.045 ;
        RECT 31.175 8.000 31.465 8.045 ;
        RECT 41.740 7.985 42.060 8.245 ;
        RECT 17.360 7.645 17.680 7.905 ;
        RECT 25.180 7.645 25.500 7.905 ;
        RECT 30.255 7.845 30.545 7.890 ;
        RECT 37.600 7.845 37.920 7.905 ;
        RECT 30.255 7.705 37.920 7.845 ;
        RECT 42.290 7.845 42.430 8.385 ;
        RECT 44.500 8.325 44.820 8.585 ;
        RECT 48.180 8.525 48.500 8.585 ;
        RECT 51.950 8.525 52.090 9.405 ;
        RECT 66.120 9.345 66.440 9.405 ;
        RECT 71.640 9.545 71.960 9.605 ;
        RECT 75.795 9.545 76.085 9.590 ;
        RECT 71.640 9.405 76.085 9.545 ;
        RECT 71.640 9.345 71.960 9.405 ;
        RECT 75.795 9.360 76.085 9.405 ;
        RECT 57.840 9.205 58.160 9.265 ;
        RECT 57.010 9.065 58.160 9.205 ;
        RECT 52.780 8.865 53.100 8.925 ;
        RECT 57.010 8.910 57.150 9.065 ;
        RECT 57.840 9.005 58.160 9.065 ;
        RECT 61.945 9.205 62.235 9.250 ;
        RECT 63.835 9.205 64.125 9.250 ;
        RECT 66.955 9.205 67.245 9.250 ;
        RECT 61.945 9.065 67.245 9.205 ;
        RECT 61.945 9.020 62.235 9.065 ;
        RECT 63.835 9.020 64.125 9.065 ;
        RECT 66.955 9.020 67.245 9.065 ;
        RECT 56.935 8.865 57.225 8.910 ;
        RECT 52.780 8.725 57.225 8.865 ;
        RECT 52.780 8.665 53.100 8.725 ;
        RECT 56.935 8.680 57.225 8.725 ;
        RECT 59.680 8.865 60.000 8.925 ;
        RECT 59.680 8.725 70.490 8.865 ;
        RECT 59.680 8.665 60.000 8.725 ;
        RECT 70.350 8.585 70.490 8.725 ;
        RECT 73.940 8.665 74.260 8.925 ;
        RECT 48.180 8.385 52.090 8.525 ;
        RECT 57.380 8.525 57.700 8.585 ;
        RECT 57.855 8.525 58.145 8.570 ;
        RECT 57.380 8.385 58.145 8.525 ;
        RECT 48.180 8.325 48.500 8.385 ;
        RECT 57.380 8.325 57.700 8.385 ;
        RECT 57.855 8.340 58.145 8.385 ;
        RECT 61.060 8.325 61.380 8.585 ;
        RECT 61.540 8.525 61.830 8.570 ;
        RECT 63.375 8.525 63.665 8.570 ;
        RECT 66.955 8.525 67.245 8.570 ;
        RECT 61.540 8.385 67.245 8.525 ;
        RECT 61.540 8.340 61.830 8.385 ;
        RECT 63.375 8.340 63.665 8.385 ;
        RECT 66.955 8.340 67.245 8.385 ;
        RECT 53.255 8.185 53.545 8.230 ;
        RECT 56.460 8.185 56.780 8.245 ;
        RECT 53.255 8.045 56.780 8.185 ;
        RECT 53.255 8.000 53.545 8.045 ;
        RECT 56.460 7.985 56.780 8.045 ;
        RECT 62.455 8.185 62.745 8.230 ;
        RECT 63.820 8.185 64.140 8.245 ;
        RECT 68.035 8.230 68.325 8.545 ;
        RECT 70.260 8.525 70.580 8.585 ;
        RECT 73.495 8.525 73.785 8.570 ;
        RECT 70.260 8.385 73.785 8.525 ;
        RECT 70.260 8.325 70.580 8.385 ;
        RECT 73.495 8.340 73.785 8.385 ;
        RECT 78.540 8.525 78.860 8.585 ;
        RECT 79.015 8.525 79.305 8.570 ;
        RECT 78.540 8.385 79.305 8.525 ;
        RECT 78.540 8.325 78.860 8.385 ;
        RECT 79.015 8.340 79.305 8.385 ;
        RECT 62.455 8.045 64.140 8.185 ;
        RECT 62.455 8.000 62.745 8.045 ;
        RECT 63.820 7.985 64.140 8.045 ;
        RECT 64.735 8.185 65.385 8.230 ;
        RECT 68.035 8.185 68.625 8.230 ;
        RECT 79.920 8.185 80.240 8.245 ;
        RECT 64.735 8.045 80.240 8.185 ;
        RECT 64.735 8.000 65.385 8.045 ;
        RECT 68.335 8.000 68.625 8.045 ;
        RECT 79.920 7.985 80.240 8.045 ;
        RECT 45.880 7.845 46.200 7.905 ;
        RECT 42.290 7.705 46.200 7.845 ;
        RECT 30.255 7.660 30.545 7.705 ;
        RECT 37.600 7.645 37.920 7.705 ;
        RECT 45.880 7.645 46.200 7.705 ;
        RECT 59.235 7.845 59.525 7.890 ;
        RECT 68.880 7.845 69.200 7.905 ;
        RECT 59.235 7.705 69.200 7.845 ;
        RECT 59.235 7.660 59.525 7.705 ;
        RECT 68.880 7.645 69.200 7.705 ;
        RECT 69.800 7.645 70.120 7.905 ;
        RECT 71.195 7.845 71.485 7.890 ;
        RECT 72.100 7.845 72.420 7.905 ;
        RECT 71.195 7.705 72.420 7.845 ;
        RECT 71.195 7.660 71.485 7.705 ;
        RECT 72.100 7.645 72.420 7.705 ;
        RECT 73.020 7.645 73.340 7.905 ;
        RECT 15.450 7.025 82.150 7.505 ;
        RECT 20.120 6.825 20.440 6.885 ;
        RECT 30.700 6.825 31.020 6.885 ;
        RECT 20.120 6.685 31.020 6.825 ;
        RECT 20.120 6.625 20.440 6.685 ;
        RECT 30.700 6.625 31.020 6.685 ;
        RECT 41.740 6.825 42.060 6.885 ;
        RECT 44.500 6.825 44.820 6.885 ;
        RECT 48.180 6.825 48.500 6.885 ;
        RECT 41.740 6.685 44.820 6.825 ;
        RECT 41.740 6.625 42.060 6.685 ;
        RECT 44.500 6.625 44.820 6.685 ;
        RECT 45.510 6.685 48.500 6.825 ;
        RECT 17.360 6.485 17.680 6.545 ;
        RECT 23.355 6.485 23.645 6.530 ;
        RECT 17.360 6.345 23.645 6.485 ;
        RECT 17.360 6.285 17.680 6.345 ;
        RECT 23.355 6.300 23.645 6.345 ;
        RECT 25.635 6.485 26.285 6.530 ;
        RECT 28.400 6.485 28.720 6.545 ;
        RECT 29.235 6.485 29.525 6.530 ;
        RECT 25.635 6.345 29.525 6.485 ;
        RECT 25.635 6.300 26.285 6.345 ;
        RECT 28.400 6.285 28.720 6.345 ;
        RECT 28.935 6.300 29.525 6.345 ;
        RECT 43.580 6.485 43.900 6.545 ;
        RECT 45.510 6.485 45.650 6.685 ;
        RECT 48.180 6.625 48.500 6.685 ;
        RECT 43.580 6.345 45.650 6.485 ;
        RECT 16.440 6.145 16.760 6.205 ;
        RECT 16.915 6.145 17.205 6.190 ;
        RECT 16.440 6.005 17.205 6.145 ;
        RECT 16.440 5.945 16.760 6.005 ;
        RECT 16.915 5.960 17.205 6.005 ;
        RECT 19.660 6.145 19.980 6.205 ;
        RECT 20.135 6.145 20.425 6.190 ;
        RECT 19.660 6.005 20.425 6.145 ;
        RECT 19.660 5.945 19.980 6.005 ;
        RECT 20.135 5.960 20.425 6.005 ;
        RECT 20.595 6.145 20.885 6.190 ;
        RECT 21.040 6.145 21.360 6.205 ;
        RECT 20.595 6.005 21.360 6.145 ;
        RECT 20.595 5.960 20.885 6.005 ;
        RECT 21.040 5.945 21.360 6.005 ;
        RECT 22.440 6.145 22.730 6.190 ;
        RECT 24.275 6.145 24.565 6.190 ;
        RECT 27.855 6.145 28.145 6.190 ;
        RECT 22.440 6.005 28.145 6.145 ;
        RECT 22.440 5.960 22.730 6.005 ;
        RECT 24.275 5.960 24.565 6.005 ;
        RECT 27.855 5.960 28.145 6.005 ;
        RECT 28.935 5.985 29.225 6.300 ;
        RECT 43.580 6.285 43.900 6.345 ;
        RECT 45.510 6.190 45.650 6.345 ;
        RECT 46.815 6.485 47.105 6.530 ;
        RECT 47.260 6.485 47.580 6.545 ;
        RECT 46.815 6.345 47.580 6.485 ;
        RECT 46.815 6.300 47.105 6.345 ;
        RECT 47.260 6.285 47.580 6.345 ;
        RECT 56.460 6.285 56.780 6.545 ;
        RECT 74.395 6.485 75.045 6.530 ;
        RECT 75.780 6.485 76.100 6.545 ;
        RECT 77.995 6.485 78.285 6.530 ;
        RECT 74.395 6.345 78.285 6.485 ;
        RECT 74.395 6.300 75.045 6.345 ;
        RECT 75.780 6.285 76.100 6.345 ;
        RECT 77.695 6.300 78.285 6.345 ;
        RECT 37.155 6.145 37.445 6.190 ;
        RECT 39.915 6.145 40.205 6.190 ;
        RECT 37.155 6.005 44.500 6.145 ;
        RECT 37.155 5.960 37.445 6.005 ;
        RECT 39.915 5.960 40.205 6.005 ;
        RECT 17.820 5.805 18.140 5.865 ;
        RECT 21.960 5.805 22.280 5.865 ;
        RECT 17.820 5.665 22.280 5.805 ;
        RECT 17.820 5.605 18.140 5.665 ;
        RECT 21.960 5.605 22.280 5.665 ;
        RECT 33.460 5.805 33.780 5.865 ;
        RECT 34.395 5.805 34.685 5.850 ;
        RECT 33.460 5.665 34.685 5.805 ;
        RECT 33.460 5.605 33.780 5.665 ;
        RECT 34.395 5.620 34.685 5.665 ;
        RECT 34.840 5.805 35.160 5.865 ;
        RECT 35.315 5.805 35.605 5.850 ;
        RECT 34.840 5.665 35.605 5.805 ;
        RECT 22.845 5.465 23.135 5.510 ;
        RECT 24.735 5.465 25.025 5.510 ;
        RECT 27.855 5.465 28.145 5.510 ;
        RECT 22.845 5.325 28.145 5.465 ;
        RECT 22.845 5.280 23.135 5.325 ;
        RECT 24.735 5.280 25.025 5.325 ;
        RECT 27.855 5.280 28.145 5.325 ;
        RECT 29.320 5.465 29.640 5.525 ;
        RECT 31.635 5.465 31.925 5.510 ;
        RECT 29.320 5.325 31.925 5.465 ;
        RECT 34.470 5.465 34.610 5.620 ;
        RECT 34.840 5.605 35.160 5.665 ;
        RECT 35.315 5.620 35.605 5.665 ;
        RECT 38.060 5.805 38.380 5.865 ;
        RECT 39.455 5.805 39.745 5.850 ;
        RECT 38.060 5.665 39.745 5.805 ;
        RECT 44.360 5.805 44.500 6.005 ;
        RECT 45.435 5.960 45.725 6.190 ;
        RECT 45.880 6.145 46.200 6.205 ;
        RECT 45.880 6.005 47.490 6.145 ;
        RECT 45.880 5.945 46.200 6.005 ;
        RECT 46.340 5.805 46.660 5.865 ;
        RECT 47.350 5.850 47.490 6.005 ;
        RECT 50.480 5.945 50.800 6.205 ;
        RECT 52.320 5.945 52.640 6.205 ;
        RECT 52.780 5.945 53.100 6.205 ;
        RECT 61.520 6.145 61.840 6.205 ;
        RECT 67.515 6.145 67.805 6.190 ;
        RECT 61.520 6.005 67.805 6.145 ;
        RECT 61.520 5.945 61.840 6.005 ;
        RECT 67.515 5.960 67.805 6.005 ;
        RECT 68.880 5.945 69.200 6.205 ;
        RECT 71.200 6.145 71.490 6.190 ;
        RECT 73.035 6.145 73.325 6.190 ;
        RECT 76.615 6.145 76.905 6.190 ;
        RECT 71.200 6.005 76.905 6.145 ;
        RECT 71.200 5.960 71.490 6.005 ;
        RECT 73.035 5.960 73.325 6.005 ;
        RECT 76.615 5.960 76.905 6.005 ;
        RECT 77.695 5.985 77.985 6.300 ;
        RECT 44.360 5.665 46.660 5.805 ;
        RECT 38.060 5.605 38.380 5.665 ;
        RECT 39.455 5.620 39.745 5.665 ;
        RECT 46.340 5.605 46.660 5.665 ;
        RECT 47.275 5.620 47.565 5.850 ;
        RECT 53.715 5.620 54.005 5.850 ;
        RECT 38.980 5.465 39.300 5.525 ;
        RECT 34.470 5.325 39.300 5.465 ;
        RECT 53.790 5.465 53.930 5.620 ;
        RECT 54.160 5.605 54.480 5.865 ;
        RECT 54.635 5.805 54.925 5.850 ;
        RECT 58.760 5.805 59.080 5.865 ;
        RECT 54.635 5.665 59.080 5.805 ;
        RECT 54.635 5.620 54.925 5.665 ;
        RECT 58.760 5.605 59.080 5.665 ;
        RECT 65.200 5.805 65.520 5.865 ;
        RECT 70.735 5.805 71.025 5.850 ;
        RECT 65.200 5.665 71.025 5.805 ;
        RECT 65.200 5.605 65.520 5.665 ;
        RECT 70.735 5.620 71.025 5.665 ;
        RECT 72.100 5.605 72.420 5.865 ;
        RECT 79.460 5.605 79.780 5.865 ;
        RECT 57.380 5.465 57.700 5.525 ;
        RECT 53.790 5.325 57.700 5.465 ;
        RECT 29.320 5.265 29.640 5.325 ;
        RECT 31.635 5.280 31.925 5.325 ;
        RECT 38.980 5.265 39.300 5.325 ;
        RECT 57.380 5.265 57.700 5.325 ;
        RECT 68.880 5.265 69.200 5.525 ;
        RECT 71.605 5.465 71.895 5.510 ;
        RECT 73.495 5.465 73.785 5.510 ;
        RECT 76.615 5.465 76.905 5.510 ;
        RECT 71.605 5.325 76.905 5.465 ;
        RECT 71.605 5.280 71.895 5.325 ;
        RECT 73.495 5.280 73.785 5.325 ;
        RECT 76.615 5.280 76.905 5.325 ;
        RECT 21.055 5.125 21.345 5.170 ;
        RECT 28.400 5.125 28.720 5.185 ;
        RECT 21.055 4.985 28.720 5.125 ;
        RECT 21.055 4.940 21.345 4.985 ;
        RECT 28.400 4.925 28.720 4.985 ;
        RECT 39.915 5.125 40.205 5.170 ;
        RECT 40.835 5.125 41.125 5.170 ;
        RECT 39.915 4.985 41.125 5.125 ;
        RECT 39.915 4.940 40.205 4.985 ;
        RECT 40.835 4.940 41.125 4.985 ;
        RECT 51.400 4.925 51.720 5.185 ;
        RECT 15.450 4.305 82.150 4.785 ;
        RECT 19.200 3.905 19.520 4.165 ;
        RECT 25.180 4.105 25.500 4.165 ;
        RECT 28.875 4.105 29.165 4.150 ;
        RECT 25.180 3.965 29.165 4.105 ;
        RECT 25.180 3.905 25.500 3.965 ;
        RECT 28.875 3.920 29.165 3.965 ;
        RECT 33.460 4.105 33.780 4.165 ;
        RECT 54.160 4.105 54.480 4.165 ;
        RECT 69.815 4.105 70.105 4.150 ;
        RECT 70.260 4.105 70.580 4.165 ;
        RECT 33.460 3.965 43.810 4.105 ;
        RECT 33.460 3.905 33.780 3.965 ;
        RECT 22.895 3.765 23.185 3.810 ;
        RECT 25.655 3.765 25.945 3.810 ;
        RECT 27.495 3.765 27.785 3.810 ;
        RECT 22.895 3.625 27.785 3.765 ;
        RECT 22.895 3.580 23.185 3.625 ;
        RECT 25.655 3.580 25.945 3.625 ;
        RECT 27.495 3.580 27.785 3.625 ;
        RECT 34.345 3.765 34.635 3.810 ;
        RECT 36.235 3.765 36.525 3.810 ;
        RECT 39.355 3.765 39.645 3.810 ;
        RECT 34.345 3.625 39.645 3.765 ;
        RECT 34.345 3.580 34.635 3.625 ;
        RECT 36.235 3.580 36.525 3.625 ;
        RECT 39.355 3.580 39.645 3.625 ;
        RECT 21.960 3.425 22.280 3.485 ;
        RECT 27.955 3.425 28.245 3.470 ;
        RECT 28.860 3.425 29.180 3.485 ;
        RECT 21.960 3.285 29.180 3.425 ;
        RECT 21.960 3.225 22.280 3.285 ;
        RECT 27.955 3.240 28.245 3.285 ;
        RECT 28.860 3.225 29.180 3.285 ;
        RECT 32.095 3.425 32.385 3.470 ;
        RECT 33.000 3.425 33.320 3.485 ;
        RECT 32.095 3.285 33.320 3.425 ;
        RECT 32.095 3.240 32.385 3.285 ;
        RECT 33.000 3.225 33.320 3.285 ;
        RECT 34.840 3.225 35.160 3.485 ;
        RECT 43.670 3.470 43.810 3.965 ;
        RECT 54.160 3.965 70.580 4.105 ;
        RECT 54.160 3.905 54.480 3.965 ;
        RECT 57.930 3.810 58.070 3.965 ;
        RECT 69.815 3.920 70.105 3.965 ;
        RECT 70.260 3.905 70.580 3.965 ;
        RECT 73.020 4.105 73.340 4.165 ;
        RECT 76.255 4.105 76.545 4.150 ;
        RECT 73.020 3.965 76.545 4.105 ;
        RECT 73.020 3.905 73.340 3.965 ;
        RECT 76.255 3.920 76.545 3.965 ;
        RECT 44.465 3.765 44.755 3.810 ;
        RECT 46.355 3.765 46.645 3.810 ;
        RECT 49.475 3.765 49.765 3.810 ;
        RECT 44.465 3.625 49.765 3.765 ;
        RECT 44.465 3.580 44.755 3.625 ;
        RECT 46.355 3.580 46.645 3.625 ;
        RECT 49.475 3.580 49.765 3.625 ;
        RECT 57.855 3.580 58.145 3.810 ;
        RECT 61.945 3.765 62.235 3.810 ;
        RECT 63.835 3.765 64.125 3.810 ;
        RECT 66.955 3.765 67.245 3.810 ;
        RECT 61.945 3.625 67.245 3.765 ;
        RECT 61.945 3.580 62.235 3.625 ;
        RECT 63.835 3.580 64.125 3.625 ;
        RECT 66.955 3.580 67.245 3.625 ;
        RECT 72.575 3.765 72.865 3.810 ;
        RECT 78.540 3.765 78.860 3.825 ;
        RECT 72.575 3.625 78.860 3.765 ;
        RECT 86.050 3.650 87.150 4.750 ;
        RECT 72.575 3.580 72.865 3.625 ;
        RECT 78.540 3.565 78.860 3.625 ;
        RECT 43.595 3.240 43.885 3.470 ;
        RECT 46.800 3.425 47.120 3.485 ;
        RECT 50.020 3.425 50.340 3.485 ;
        RECT 65.200 3.425 65.520 3.485 ;
        RECT 46.800 3.285 65.520 3.425 ;
        RECT 46.800 3.225 47.120 3.285 ;
        RECT 50.020 3.225 50.340 3.285 ;
        RECT 22.875 3.085 23.165 3.130 ;
        RECT 22.875 2.945 25.410 3.085 ;
        RECT 22.875 2.900 23.165 2.945 ;
        RECT 21.055 2.745 21.345 2.790 ;
        RECT 24.260 2.745 24.580 2.805 ;
        RECT 21.055 2.605 24.580 2.745 ;
        RECT 21.055 2.560 21.345 2.605 ;
        RECT 24.260 2.545 24.580 2.605 ;
        RECT 25.195 2.790 25.410 2.945 ;
        RECT 26.100 2.885 26.420 3.145 ;
        RECT 33.460 2.885 33.780 3.145 ;
        RECT 33.940 3.085 34.230 3.130 ;
        RECT 35.775 3.085 36.065 3.130 ;
        RECT 39.355 3.085 39.645 3.130 ;
        RECT 33.940 2.945 39.645 3.085 ;
        RECT 33.940 2.900 34.230 2.945 ;
        RECT 35.775 2.900 36.065 2.945 ;
        RECT 39.355 2.900 39.645 2.945 ;
        RECT 37.600 2.790 37.920 2.805 ;
        RECT 25.195 2.745 25.485 2.790 ;
        RECT 27.035 2.745 27.325 2.790 ;
        RECT 25.195 2.605 27.325 2.745 ;
        RECT 25.195 2.560 25.485 2.605 ;
        RECT 27.035 2.560 27.325 2.605 ;
        RECT 37.135 2.745 37.920 2.790 ;
        RECT 40.435 2.790 40.725 3.105 ;
        RECT 44.060 3.085 44.350 3.130 ;
        RECT 45.895 3.085 46.185 3.130 ;
        RECT 49.475 3.085 49.765 3.130 ;
        RECT 44.060 2.945 49.765 3.085 ;
        RECT 44.060 2.900 44.350 2.945 ;
        RECT 45.895 2.900 46.185 2.945 ;
        RECT 49.475 2.900 49.765 2.945 ;
        RECT 40.435 2.745 41.025 2.790 ;
        RECT 37.135 2.605 41.025 2.745 ;
        RECT 37.135 2.560 37.920 2.605 ;
        RECT 40.735 2.560 41.025 2.605 ;
        RECT 44.975 2.745 45.265 2.790 ;
        RECT 45.420 2.745 45.740 2.805 ;
        RECT 47.260 2.790 47.580 2.805 ;
        RECT 50.555 2.790 50.845 3.105 ;
        RECT 52.780 3.085 53.100 3.145 ;
        RECT 56.475 3.085 56.765 3.130 ;
        RECT 52.780 2.945 56.765 3.085 ;
        RECT 52.780 2.885 53.100 2.945 ;
        RECT 56.475 2.900 56.765 2.945 ;
        RECT 56.935 3.085 57.225 3.130 ;
        RECT 57.380 3.085 57.700 3.145 ;
        RECT 58.850 3.130 58.990 3.285 ;
        RECT 65.200 3.225 65.520 3.285 ;
        RECT 79.460 3.225 79.780 3.485 ;
        RECT 56.935 2.945 57.700 3.085 ;
        RECT 56.935 2.900 57.225 2.945 ;
        RECT 57.380 2.885 57.700 2.945 ;
        RECT 58.775 2.900 59.065 3.130 ;
        RECT 61.060 2.885 61.380 3.145 ;
        RECT 61.540 3.085 61.830 3.130 ;
        RECT 63.375 3.085 63.665 3.130 ;
        RECT 66.955 3.085 67.245 3.130 ;
        RECT 61.540 2.945 67.245 3.085 ;
        RECT 61.540 2.900 61.830 2.945 ;
        RECT 63.375 2.900 63.665 2.945 ;
        RECT 66.955 2.900 67.245 2.945 ;
        RECT 44.975 2.605 45.740 2.745 ;
        RECT 44.975 2.560 45.265 2.605 ;
        RECT 37.600 2.545 37.920 2.560 ;
        RECT 45.420 2.545 45.740 2.605 ;
        RECT 47.255 2.745 47.905 2.790 ;
        RECT 50.555 2.745 51.145 2.790 ;
        RECT 55.095 2.745 55.385 2.790 ;
        RECT 60.140 2.745 60.460 2.805 ;
        RECT 68.035 2.790 68.325 3.105 ;
        RECT 75.780 2.885 76.100 3.145 ;
        RECT 47.255 2.605 51.145 2.745 ;
        RECT 47.255 2.560 47.905 2.605 ;
        RECT 50.855 2.560 51.145 2.605 ;
        RECT 51.490 2.605 55.385 2.745 ;
        RECT 47.260 2.545 47.580 2.560 ;
        RECT 38.060 2.405 38.380 2.465 ;
        RECT 42.215 2.405 42.505 2.450 ;
        RECT 38.060 2.265 42.505 2.405 ;
        RECT 38.060 2.205 38.380 2.265 ;
        RECT 42.215 2.220 42.505 2.265 ;
        RECT 46.340 2.405 46.660 2.465 ;
        RECT 51.490 2.405 51.630 2.605 ;
        RECT 55.095 2.560 55.385 2.605 ;
        RECT 55.630 2.605 60.460 2.745 ;
        RECT 46.340 2.265 51.630 2.405 ;
        RECT 52.320 2.405 52.640 2.465 ;
        RECT 55.630 2.405 55.770 2.605 ;
        RECT 60.140 2.545 60.460 2.605 ;
        RECT 62.455 2.560 62.745 2.790 ;
        RECT 64.735 2.745 65.385 2.790 ;
        RECT 68.035 2.745 68.625 2.790 ;
        RECT 79.000 2.745 79.320 2.805 ;
        RECT 64.735 2.605 79.320 2.745 ;
        RECT 64.735 2.560 65.385 2.605 ;
        RECT 68.335 2.560 68.625 2.605 ;
        RECT 52.320 2.265 55.770 2.405 ;
        RECT 46.340 2.205 46.660 2.265 ;
        RECT 52.320 2.205 52.640 2.265 ;
        RECT 56.000 2.205 56.320 2.465 ;
        RECT 62.530 2.405 62.670 2.560 ;
        RECT 79.000 2.545 79.320 2.605 ;
        RECT 68.880 2.405 69.200 2.465 ;
        RECT 62.530 2.265 69.200 2.405 ;
        RECT 68.880 2.205 69.200 2.265 ;
        RECT 15.450 1.585 82.150 2.065 ;
        RECT 87.940 1.510 88.820 1.850 ;
        RECT 90.640 1.510 91.520 1.850 ;
        RECT 20.135 1.385 20.425 1.430 ;
        RECT 20.580 1.385 20.900 1.445 ;
        RECT 20.135 1.245 20.900 1.385 ;
        RECT 20.135 1.200 20.425 1.245 ;
        RECT 20.580 1.185 20.900 1.245 ;
        RECT 24.260 1.385 24.580 1.445 ;
        RECT 29.795 1.385 30.085 1.430 ;
        RECT 24.260 1.245 30.085 1.385 ;
        RECT 24.260 1.185 24.580 1.245 ;
        RECT 29.795 1.200 30.085 1.245 ;
        RECT 44.960 1.185 45.280 1.445 ;
        RECT 56.000 1.385 56.320 1.445 ;
        RECT 66.135 1.385 66.425 1.430 ;
        RECT 56.000 1.245 66.425 1.385 ;
        RECT 56.000 1.185 56.320 1.245 ;
        RECT 66.135 1.200 66.425 1.245 ;
        RECT 18.755 1.045 19.045 1.090 ;
        RECT 21.615 1.045 21.905 1.090 ;
        RECT 24.855 1.045 25.505 1.090 ;
        RECT 18.755 0.905 25.505 1.045 ;
        RECT 18.755 0.860 19.045 0.905 ;
        RECT 21.615 0.860 22.205 0.905 ;
        RECT 24.855 0.860 25.505 0.905 ;
        RECT 27.495 1.045 27.785 1.090 ;
        RECT 29.320 1.045 29.640 1.105 ;
        RECT 27.495 0.905 29.640 1.045 ;
        RECT 27.495 0.860 27.785 0.905 ;
        RECT 19.215 0.520 19.505 0.750 ;
        RECT 21.915 0.545 22.205 0.860 ;
        RECT 29.320 0.845 29.640 0.905 ;
        RECT 33.575 1.045 33.865 1.090 ;
        RECT 36.815 1.045 37.465 1.090 ;
        RECT 45.895 1.045 46.185 1.090 ;
        RECT 33.575 0.905 46.185 1.045 ;
        RECT 33.575 0.860 34.165 0.905 ;
        RECT 36.815 0.860 37.465 0.905 ;
        RECT 45.895 0.860 46.185 0.905 ;
        RECT 50.935 1.045 51.585 1.090 ;
        RECT 54.535 1.045 54.825 1.090 ;
        RECT 57.395 1.045 57.685 1.090 ;
        RECT 69.800 1.045 70.120 1.105 ;
        RECT 50.935 0.905 57.685 1.045 ;
        RECT 50.935 0.860 51.585 0.905 ;
        RECT 54.235 0.860 54.825 0.905 ;
        RECT 57.395 0.860 57.685 0.905 ;
        RECT 58.850 0.905 70.120 1.045 ;
        RECT 22.995 0.705 23.285 0.750 ;
        RECT 26.575 0.705 26.865 0.750 ;
        RECT 28.410 0.705 28.700 0.750 ;
        RECT 22.995 0.565 28.700 0.705 ;
        RECT 22.995 0.520 23.285 0.565 ;
        RECT 26.575 0.520 26.865 0.565 ;
        RECT 28.410 0.520 28.700 0.565 ;
        RECT 19.290 0.365 19.430 0.520 ;
        RECT 28.860 0.505 29.180 0.765 ;
        RECT 30.255 0.520 30.545 0.750 ;
        RECT 33.875 0.545 34.165 0.860 ;
        RECT 34.955 0.705 35.245 0.750 ;
        RECT 38.535 0.705 38.825 0.750 ;
        RECT 40.370 0.705 40.660 0.750 ;
        RECT 34.955 0.565 40.660 0.705 ;
        RECT 34.955 0.520 35.245 0.565 ;
        RECT 38.535 0.520 38.825 0.565 ;
        RECT 40.370 0.520 40.660 0.565 ;
        RECT 27.480 0.365 27.800 0.425 ;
        RECT 30.330 0.365 30.470 0.520 ;
        RECT 41.740 0.505 42.060 0.765 ;
        RECT 44.500 0.705 44.820 0.765 ;
        RECT 45.435 0.705 45.725 0.750 ;
        RECT 44.500 0.565 45.725 0.705 ;
        RECT 44.500 0.505 44.820 0.565 ;
        RECT 45.435 0.520 45.725 0.565 ;
        RECT 47.740 0.705 48.030 0.750 ;
        RECT 49.575 0.705 49.865 0.750 ;
        RECT 53.155 0.705 53.445 0.750 ;
        RECT 47.740 0.565 53.445 0.705 ;
        RECT 47.740 0.520 48.030 0.565 ;
        RECT 49.575 0.520 49.865 0.565 ;
        RECT 53.155 0.520 53.445 0.565 ;
        RECT 54.235 0.545 54.525 0.860 ;
        RECT 58.850 0.765 58.990 0.905 ;
        RECT 57.855 0.520 58.145 0.750 ;
        RECT 19.290 0.225 30.470 0.365 ;
        RECT 27.480 0.165 27.800 0.225 ;
        RECT 39.440 0.165 39.760 0.425 ;
        RECT 40.835 0.365 41.125 0.410 ;
        RECT 46.800 0.365 47.120 0.425 ;
        RECT 47.275 0.365 47.565 0.410 ;
        RECT 40.835 0.225 47.565 0.365 ;
        RECT 40.835 0.180 41.125 0.225 ;
        RECT 46.800 0.165 47.120 0.225 ;
        RECT 47.275 0.180 47.565 0.225 ;
        RECT 48.640 0.165 48.960 0.425 ;
        RECT 50.480 0.365 50.800 0.425 ;
        RECT 57.930 0.365 58.070 0.520 ;
        RECT 58.760 0.505 59.080 0.765 ;
        RECT 59.235 0.705 59.525 0.750 ;
        RECT 61.520 0.705 61.840 0.765 ;
        RECT 61.995 0.705 62.285 0.750 ;
        RECT 59.235 0.565 62.285 0.705 ;
        RECT 59.235 0.520 59.525 0.565 ;
        RECT 61.520 0.505 61.840 0.565 ;
        RECT 61.995 0.520 62.285 0.565 ;
        RECT 63.820 0.505 64.140 0.765 ;
        RECT 65.290 0.750 65.430 0.905 ;
        RECT 69.800 0.845 70.120 0.905 ;
        RECT 71.635 1.045 72.285 1.090 ;
        RECT 73.020 1.045 73.340 1.105 ;
        RECT 75.235 1.045 75.525 1.090 ;
        RECT 71.635 0.905 75.525 1.045 ;
        RECT 71.635 0.860 72.285 0.905 ;
        RECT 73.020 0.845 73.340 0.905 ;
        RECT 74.935 0.860 75.525 0.905 ;
        RECT 79.475 1.045 79.765 1.090 ;
        RECT 79.920 1.045 80.240 1.105 ;
        RECT 79.475 0.905 80.240 1.045 ;
        RECT 79.475 0.860 79.765 0.905 ;
        RECT 65.215 0.520 65.505 0.750 ;
        RECT 65.660 0.705 65.980 0.765 ;
        RECT 67.975 0.705 68.265 0.750 ;
        RECT 65.660 0.565 68.265 0.705 ;
        RECT 65.660 0.505 65.980 0.565 ;
        RECT 67.975 0.520 68.265 0.565 ;
        RECT 68.440 0.705 68.730 0.750 ;
        RECT 70.275 0.705 70.565 0.750 ;
        RECT 73.855 0.705 74.145 0.750 ;
        RECT 68.440 0.565 74.145 0.705 ;
        RECT 68.440 0.520 68.730 0.565 ;
        RECT 70.275 0.520 70.565 0.565 ;
        RECT 73.855 0.520 74.145 0.565 ;
        RECT 74.935 0.545 75.225 0.860 ;
        RECT 79.920 0.845 80.240 0.905 ;
        RECT 77.620 0.505 77.940 0.765 ;
        RECT 78.540 0.505 78.860 0.765 ;
        RECT 60.140 0.365 60.460 0.425 ;
        RECT 64.295 0.365 64.585 0.410 ;
        RECT 50.480 0.225 59.910 0.365 ;
        RECT 50.480 0.165 50.800 0.225 ;
        RECT 22.995 0.025 23.285 0.070 ;
        RECT 26.115 0.025 26.405 0.070 ;
        RECT 28.005 0.025 28.295 0.070 ;
        RECT 22.995 -0.115 28.295 0.025 ;
        RECT 22.995 -0.160 23.285 -0.115 ;
        RECT 26.115 -0.160 26.405 -0.115 ;
        RECT 28.005 -0.160 28.295 -0.115 ;
        RECT 34.955 0.025 35.245 0.070 ;
        RECT 38.075 0.025 38.365 0.070 ;
        RECT 39.965 0.025 40.255 0.070 ;
        RECT 34.955 -0.115 40.255 0.025 ;
        RECT 34.955 -0.160 35.245 -0.115 ;
        RECT 38.075 -0.160 38.365 -0.115 ;
        RECT 39.965 -0.160 40.255 -0.115 ;
        RECT 48.145 0.025 48.435 0.070 ;
        RECT 50.035 0.025 50.325 0.070 ;
        RECT 53.155 0.025 53.445 0.070 ;
        RECT 48.145 -0.115 53.445 0.025 ;
        RECT 48.145 -0.160 48.435 -0.115 ;
        RECT 50.035 -0.160 50.325 -0.115 ;
        RECT 53.155 -0.160 53.445 -0.115 ;
        RECT 32.095 -0.315 32.385 -0.270 ;
        RECT 33.000 -0.315 33.320 -0.255 ;
        RECT 32.095 -0.455 33.320 -0.315 ;
        RECT 32.095 -0.500 32.385 -0.455 ;
        RECT 33.000 -0.515 33.320 -0.455 ;
        RECT 56.015 -0.315 56.305 -0.270 ;
        RECT 57.380 -0.315 57.700 -0.255 ;
        RECT 56.015 -0.455 57.700 -0.315 ;
        RECT 56.015 -0.500 56.305 -0.455 ;
        RECT 57.380 -0.515 57.700 -0.455 ;
        RECT 58.315 -0.315 58.605 -0.270 ;
        RECT 59.235 -0.315 59.525 -0.270 ;
        RECT 58.315 -0.455 59.525 -0.315 ;
        RECT 59.770 -0.315 59.910 0.225 ;
        RECT 60.140 0.225 64.585 0.365 ;
        RECT 60.140 0.165 60.460 0.225 ;
        RECT 64.295 0.180 64.585 0.225 ;
        RECT 69.340 0.165 69.660 0.425 ;
        RECT 68.845 0.025 69.135 0.070 ;
        RECT 70.735 0.025 71.025 0.070 ;
        RECT 73.855 0.025 74.145 0.070 ;
        RECT 68.845 -0.115 74.145 0.025 ;
        RECT 68.845 -0.160 69.135 -0.115 ;
        RECT 70.735 -0.160 71.025 -0.115 ;
        RECT 73.855 -0.160 74.145 -0.115 ;
        RECT 89.200 -0.250 90.100 0.650 ;
        RECT 72.560 -0.315 72.880 -0.255 ;
        RECT 59.770 -0.455 72.880 -0.315 ;
        RECT 58.315 -0.500 58.605 -0.455 ;
        RECT 59.235 -0.500 59.525 -0.455 ;
        RECT 72.560 -0.515 72.880 -0.455 ;
        RECT 76.700 -0.515 77.020 -0.255 ;
        RECT 15.060 -1.335 15.380 -1.275 ;
        RECT 16.915 -1.335 17.205 -1.290 ;
        RECT 15.060 -1.475 17.205 -1.335 ;
        RECT 15.060 -1.535 15.380 -1.475 ;
        RECT 16.915 -1.520 17.205 -1.475 ;
        RECT 26.100 -1.335 26.420 -1.275 ;
        RECT 31.175 -1.335 31.465 -1.290 ;
        RECT 26.100 -1.475 31.465 -1.335 ;
        RECT 26.100 -1.535 26.420 -1.475 ;
        RECT 31.175 -1.520 31.465 -1.475 ;
        RECT 35.775 -1.335 36.065 -1.290 ;
        RECT 39.440 -1.335 39.760 -1.275 ;
        RECT 35.775 -1.475 39.760 -1.335 ;
        RECT 35.775 -1.520 36.065 -1.475 ;
        RECT 39.440 -1.535 39.760 -1.475 ;
        RECT 45.420 -1.335 45.740 -1.275 ;
        RECT 45.895 -1.335 46.185 -1.290 ;
        RECT 45.420 -1.475 46.185 -1.335 ;
        RECT 45.420 -1.535 45.740 -1.475 ;
        RECT 45.895 -1.520 46.185 -1.475 ;
        RECT 48.640 -1.335 48.960 -1.275 ;
        RECT 50.035 -1.335 50.325 -1.290 ;
        RECT 48.640 -1.475 50.325 -1.335 ;
        RECT 48.640 -1.535 48.960 -1.475 ;
        RECT 50.035 -1.520 50.325 -1.475 ;
        RECT 68.435 -1.335 68.725 -1.290 ;
        RECT 69.340 -1.335 69.660 -1.275 ;
        RECT 68.435 -1.475 69.660 -1.335 ;
        RECT 68.435 -1.520 68.725 -1.475 ;
        RECT 69.340 -1.535 69.660 -1.475 ;
        RECT 73.020 -1.535 73.340 -1.275 ;
        RECT 24.735 -1.675 25.025 -1.630 ;
        RECT 33.460 -1.675 33.780 -1.615 ;
        RECT 24.735 -1.815 33.780 -1.675 ;
        RECT 24.735 -1.860 25.025 -1.815 ;
        RECT 33.460 -1.875 33.780 -1.815 ;
        RECT 46.815 -1.675 47.105 -1.630 ;
        RECT 51.400 -1.675 51.720 -1.615 ;
        RECT 73.940 -1.675 74.260 -1.615 ;
        RECT 46.815 -1.815 51.720 -1.675 ;
        RECT 46.815 -1.860 47.105 -1.815 ;
        RECT 51.400 -1.875 51.720 -1.815 ;
        RECT 52.870 -1.815 74.260 -1.675 ;
        RECT 20.580 -2.015 20.900 -1.955 ;
        RECT 21.055 -2.015 21.345 -1.970 ;
        RECT 20.580 -2.155 21.345 -2.015 ;
        RECT 20.580 -2.215 20.900 -2.155 ;
        RECT 21.055 -2.200 21.345 -2.155 ;
        RECT 24.275 -2.015 24.565 -1.970 ;
        RECT 24.275 -2.155 30.470 -2.015 ;
        RECT 24.275 -2.200 24.565 -2.155 ;
        RECT 20.120 -2.555 20.440 -2.295 ;
        RECT 30.330 -2.310 30.470 -2.155 ;
        RECT 38.060 -2.215 38.380 -1.955 ;
        RECT 38.980 -2.015 39.300 -1.955 ;
        RECT 46.340 -2.015 46.660 -1.955 ;
        RECT 52.870 -1.970 53.010 -1.815 ;
        RECT 48.195 -2.015 48.485 -1.970 ;
        RECT 52.795 -2.015 53.085 -1.970 ;
        RECT 38.980 -2.155 42.430 -2.015 ;
        RECT 38.980 -2.215 39.300 -2.155 ;
        RECT 30.255 -2.540 30.545 -2.310 ;
        RECT 32.555 -2.355 32.845 -2.310 ;
        RECT 33.000 -2.355 33.320 -2.295 ;
        RECT 41.755 -2.355 42.045 -2.310 ;
        RECT 32.555 -2.495 42.045 -2.355 ;
        RECT 42.290 -2.355 42.430 -2.155 ;
        RECT 46.340 -2.155 48.485 -2.015 ;
        RECT 46.340 -2.215 46.660 -2.155 ;
        RECT 48.195 -2.200 48.485 -2.155 ;
        RECT 51.950 -2.155 53.085 -2.015 ;
        RECT 51.950 -2.355 52.090 -2.155 ;
        RECT 52.795 -2.200 53.085 -2.155 ;
        RECT 57.380 -2.015 57.700 -1.955 ;
        RECT 69.800 -2.015 70.120 -1.955 ;
        RECT 71.270 -1.970 71.410 -1.815 ;
        RECT 73.940 -1.875 74.260 -1.815 ;
        RECT 79.000 -1.875 79.320 -1.615 ;
        RECT 70.735 -2.015 71.025 -1.970 ;
        RECT 57.380 -2.155 62.670 -2.015 ;
        RECT 57.380 -2.215 57.700 -2.155 ;
        RECT 42.290 -2.495 52.090 -2.355 ;
        RECT 32.555 -2.540 32.845 -2.495 ;
        RECT 33.000 -2.555 33.320 -2.495 ;
        RECT 41.755 -2.540 42.045 -2.495 ;
        RECT 52.320 -2.555 52.640 -2.295 ;
        RECT 61.535 -2.540 61.825 -2.310 ;
        RECT 62.050 -2.385 62.340 -2.310 ;
        RECT 62.530 -2.385 62.670 -2.155 ;
        RECT 69.800 -2.155 71.025 -2.015 ;
        RECT 69.800 -2.215 70.120 -2.155 ;
        RECT 70.735 -2.200 71.025 -2.155 ;
        RECT 71.195 -2.200 71.485 -1.970 ;
        RECT 76.700 -2.015 77.020 -1.955 ;
        RECT 71.730 -2.155 77.020 -2.015 ;
        RECT 71.730 -2.355 71.870 -2.155 ;
        RECT 76.700 -2.215 77.020 -2.155 ;
        RECT 77.250 -2.155 78.770 -2.015 ;
        RECT 62.050 -2.525 62.670 -2.385 ;
        RECT 69.890 -2.495 71.870 -2.355 ;
        RECT 72.560 -2.355 72.880 -2.295 ;
        RECT 77.250 -2.355 77.390 -2.155 ;
        RECT 72.560 -2.495 77.390 -2.355 ;
        RECT 62.050 -2.540 62.340 -2.525 ;
        RECT 28.400 -2.695 28.720 -2.635 ;
        RECT 28.875 -2.695 29.165 -2.650 ;
        RECT 28.400 -2.835 29.165 -2.695 ;
        RECT 28.400 -2.895 28.720 -2.835 ;
        RECT 28.875 -2.880 29.165 -2.835 ;
        RECT 29.320 -2.895 29.640 -2.635 ;
        RECT 35.315 -2.695 35.605 -2.650 ;
        RECT 37.615 -2.695 37.905 -2.650 ;
        RECT 35.315 -2.835 37.905 -2.695 ;
        RECT 35.315 -2.880 35.605 -2.835 ;
        RECT 37.615 -2.880 37.905 -2.835 ;
        RECT 51.875 -2.695 52.165 -2.650 ;
        RECT 54.635 -2.695 54.925 -2.650 ;
        RECT 51.875 -2.835 54.925 -2.695 ;
        RECT 51.875 -2.880 52.165 -2.835 ;
        RECT 54.635 -2.880 54.925 -2.835 ;
        RECT 61.610 -3.035 61.750 -2.540 ;
        RECT 69.890 -3.035 70.030 -2.495 ;
        RECT 72.560 -2.555 72.880 -2.495 ;
        RECT 77.620 -2.555 77.940 -2.295 ;
        RECT 78.630 -2.310 78.770 -2.155 ;
        RECT 78.555 -2.540 78.845 -2.310 ;
        RECT 70.275 -2.695 70.565 -2.650 ;
        RECT 73.955 -2.695 74.245 -2.650 ;
        RECT 70.275 -2.835 74.245 -2.695 ;
        RECT 70.275 -2.880 70.565 -2.835 ;
        RECT 73.955 -2.880 74.245 -2.835 ;
        RECT 61.610 -3.175 70.030 -3.035 ;
      LAYER met2 ;
        RECT 37.070 98.600 37.450 99.500 ;
        RECT 115.305 99.185 115.605 99.215 ;
        RECT 39.755 98.790 40.680 99.070 ;
        RECT 115.260 98.825 115.630 99.185 ;
        RECT 144.100 99.180 144.545 99.645 ;
        RECT 115.305 98.795 115.605 98.825 ;
        RECT 124.850 98.640 126.000 98.750 ;
        RECT 144.170 98.640 144.470 98.645 ;
        RECT 159.320 98.640 160.660 98.860 ;
        RECT 12.295 97.835 42.595 98.385 ;
        RECT 44.270 98.330 44.610 98.610 ;
        RECT 44.300 97.990 44.580 98.330 ;
        RECT 12.295 92.845 12.845 97.835 ;
        RECT 16.170 95.720 17.220 95.770 ;
        RECT 16.170 93.800 36.120 95.720 ;
        RECT 42.045 95.520 42.595 97.835 ;
        RECT 44.255 97.710 44.625 97.990 ;
        RECT 121.360 97.760 160.660 98.640 ;
        RECT 121.360 97.715 122.240 97.760 ;
        RECT 124.850 97.700 126.000 97.760 ;
        RECT 159.320 97.560 160.660 97.760 ;
        RECT 83.000 96.300 83.500 96.400 ;
        RECT 131.700 96.300 132.150 96.500 ;
        RECT 83.000 96.000 132.150 96.300 ;
        RECT 142.580 96.080 143.460 96.420 ;
        RECT 145.280 96.080 146.160 96.420 ;
        RECT 83.000 95.900 83.500 96.000 ;
        RECT 131.700 95.850 132.150 96.000 ;
        RECT 41.920 94.820 42.620 95.520 ;
        RECT 76.005 95.495 76.960 95.505 ;
        RECT 16.170 93.620 31.520 93.800 ;
        RECT 14.320 92.370 15.270 92.970 ;
        RECT 19.910 92.410 20.920 93.620 ;
        RECT 5.520 45.180 7.560 47.180 ;
        RECT 8.170 41.495 10.210 43.495 ;
        RECT 19.920 33.270 20.920 92.410 ;
        RECT 33.820 92.070 36.120 93.800 ;
        RECT 76.005 94.540 111.295 95.495 ;
        RECT 118.650 95.450 119.530 95.790 ;
        RECT 121.350 95.450 122.230 95.790 ;
        RECT 142.580 95.285 143.460 95.625 ;
        RECT 145.280 95.285 146.160 95.625 ;
        RECT 118.650 94.650 119.530 94.990 ;
        RECT 33.820 91.380 50.020 92.070 ;
        RECT 33.815 90.405 50.020 91.380 ;
        RECT 33.820 90.320 50.020 90.405 ;
        RECT 32.960 88.270 33.460 88.300 ;
        RECT 29.380 87.770 33.460 88.270 ;
        RECT 32.960 87.740 33.460 87.770 ;
        RECT 48.270 86.270 50.020 90.320 ;
        RECT 76.005 89.815 76.960 94.540 ;
        RECT 85.515 94.495 86.490 94.540 ;
        RECT 106.500 94.495 107.455 94.540 ;
        RECT 142.580 94.485 143.460 94.825 ;
        RECT 145.280 94.485 146.160 94.825 ;
        RECT 156.710 93.940 158.050 94.130 ;
        RECT 118.660 93.390 119.540 93.940 ;
        RECT 118.650 93.050 119.540 93.390 ;
        RECT 121.350 93.050 122.230 93.390 ;
        RECT 128.025 93.060 158.050 93.940 ;
        RECT 118.660 93.015 119.540 93.050 ;
        RECT 91.820 91.420 92.860 92.400 ;
        RECT 102.300 92.220 102.660 92.245 ;
        RECT 103.860 92.220 104.740 92.560 ;
        RECT 106.560 92.220 107.440 92.560 ;
        RECT 102.270 91.920 102.690 92.220 ;
        RECT 105.460 92.180 105.820 92.205 ;
        RECT 102.300 91.875 102.660 91.920 ;
        RECT 105.430 91.880 105.850 92.180 ;
        RECT 105.460 91.835 105.820 91.880 ;
        RECT 67.360 88.860 76.985 89.815 ;
        RECT 91.850 89.500 92.830 91.420 ;
        RECT 103.870 91.380 104.850 91.425 ;
        RECT 114.345 91.380 115.275 91.400 ;
        RECT 100.130 90.400 115.300 91.380 ;
        RECT 116.750 91.250 117.850 92.350 ;
        RECT 118.635 90.925 119.565 90.940 ;
        RECT 118.635 90.880 119.570 90.925 ;
        RECT 128.025 90.880 128.905 93.060 ;
        RECT 156.710 92.830 158.050 93.060 ;
        RECT 114.345 90.380 115.275 90.400 ;
        RECT 118.635 89.950 128.905 90.880 ;
        RECT 118.635 89.890 119.565 89.950 ;
        RECT 112.975 89.500 113.905 89.520 ;
        RECT 59.970 87.170 60.340 87.190 ;
        RECT 66.780 87.170 67.080 87.200 ;
        RECT 59.970 86.870 67.080 87.170 ;
        RECT 59.970 86.860 60.340 86.870 ;
        RECT 66.780 86.840 67.080 86.870 ;
        RECT 67.360 86.270 68.315 88.860 ;
        RECT 91.850 88.520 113.930 89.500 ;
        RECT 112.975 88.500 113.905 88.520 ;
        RECT 68.660 87.170 69.260 87.190 ;
        RECT 68.630 86.860 69.260 87.170 ;
        RECT 122.565 86.965 122.845 86.985 ;
        RECT 68.960 86.670 69.260 86.860 ;
        RECT 68.960 86.370 89.640 86.670 ;
        RECT 92.130 86.640 122.870 86.965 ;
        RECT 122.565 86.615 122.845 86.640 ;
        RECT 48.270 84.470 68.320 86.270 ;
        RECT 60.620 84.450 61.580 84.470 ;
        RECT 22.820 82.320 23.270 83.670 ;
        RECT 56.570 82.370 58.270 83.570 ;
        RECT 60.600 81.860 65.070 81.890 ;
        RECT 57.200 80.930 65.070 81.860 ;
        RECT 57.200 80.900 61.660 80.930 ;
        RECT 43.600 80.750 44.560 80.780 ;
        RECT 33.300 80.180 33.620 80.210 ;
        RECT 39.550 80.180 39.870 80.210 ;
        RECT 33.300 79.860 42.030 80.180 ;
        RECT 33.300 79.830 33.620 79.860 ;
        RECT 39.550 79.830 39.870 79.860 ;
        RECT 43.600 79.790 46.220 80.750 ;
        RECT 56.590 79.850 56.910 79.880 ;
        RECT 63.450 79.850 63.770 79.880 ;
        RECT 43.600 79.760 44.560 79.790 ;
        RECT 56.590 79.530 63.770 79.850 ;
        RECT 56.590 79.500 56.910 79.530 ;
        RECT 63.450 79.500 63.770 79.530 ;
        RECT 22.770 76.720 23.220 78.220 ;
        RECT 34.950 77.540 37.590 78.500 ;
        RECT 29.460 76.940 29.960 76.970 ;
        RECT 29.460 76.440 66.305 76.940 ;
        RECT 29.460 76.410 29.960 76.440 ;
        RECT 38.120 76.170 39.080 76.230 ;
        RECT 21.560 75.210 39.080 76.170 ;
        RECT 45.230 75.500 46.190 75.530 ;
        RECT 38.120 75.150 39.080 75.210 ;
        RECT 40.050 74.930 40.370 74.960 ;
        RECT 41.800 74.930 42.120 74.960 ;
        RECT 43.700 74.930 46.190 75.500 ;
        RECT 48.660 74.930 49.060 74.970 ;
        RECT 34.650 74.610 49.060 74.930 ;
        RECT 40.050 74.580 40.370 74.610 ;
        RECT 41.800 74.580 42.120 74.610 ;
        RECT 43.700 74.540 46.190 74.610 ;
        RECT 48.660 74.570 49.060 74.610 ;
        RECT 45.230 74.510 46.190 74.540 ;
        RECT 66.720 73.145 68.315 84.470 ;
        RECT 89.340 82.600 89.640 86.370 ;
        RECT 89.340 82.300 102.685 82.600 ;
        RECT 69.335 76.940 69.785 76.960 ;
        RECT 105.290 76.940 105.790 76.985 ;
        RECT 69.170 76.440 105.790 76.940 ;
        RECT 69.335 76.420 69.785 76.440 ;
        RECT 50.570 71.410 58.210 71.430 ;
        RECT 50.570 70.470 65.060 71.410 ;
        RECT 57.200 70.450 65.060 70.470 ;
        RECT 66.720 70.795 70.145 73.145 ;
        RECT 42.290 68.790 44.720 69.750 ;
        RECT 63.420 68.870 64.620 69.620 ;
        RECT 66.720 69.540 70.095 70.795 ;
        RECT 66.720 69.145 68.315 69.540 ;
        RECT 77.970 69.500 79.120 73.220 ;
        RECT 141.630 70.870 143.650 72.460 ;
        RECT 66.720 68.650 73.545 69.145 ;
        RECT 58.645 67.695 73.545 68.650 ;
        RECT 74.870 67.720 76.370 69.220 ;
        RECT 77.900 68.540 79.120 69.500 ;
        RECT 77.970 68.520 79.120 68.540 ;
        RECT 60.570 66.620 61.570 67.695 ;
        RECT 61.895 67.670 62.850 67.695 ;
        RECT 64.920 67.670 70.320 67.695 ;
        RECT 29.460 65.520 29.960 65.550 ;
        RECT 29.460 65.020 37.990 65.520 ;
        RECT 29.460 64.990 29.960 65.020 ;
        RECT 64.920 64.520 70.320 66.970 ;
        RECT 78.120 63.500 79.080 68.520 ;
        RECT 35.290 63.490 79.120 63.500 ;
        RECT 32.210 62.550 79.120 63.490 ;
        RECT 35.290 62.540 79.120 62.550 ;
        RECT 35.720 59.520 37.170 60.570 ;
        RECT 22.670 58.320 23.170 59.520 ;
        RECT 55.920 58.320 57.920 59.520 ;
        RECT 22.670 56.470 57.920 58.320 ;
        RECT 22.670 56.370 23.470 56.470 ;
        RECT 78.160 49.980 79.120 62.540 ;
        RECT 153.525 57.650 155.475 59.690 ;
        RECT 114.330 56.340 115.290 56.385 ;
        RECT 114.300 55.380 115.320 56.340 ;
        RECT 85.510 52.665 86.510 52.710 ;
        RECT 92.110 52.665 93.110 52.695 ;
        RECT 85.510 51.665 93.110 52.665 ;
        RECT 131.510 51.770 132.250 52.460 ;
        RECT 92.110 51.635 93.110 51.665 ;
        RECT 121.040 51.605 122.000 51.635 ;
        RECT 121.040 51.595 122.670 51.605 ;
        RECT 134.975 51.595 135.805 51.615 ;
        RECT 121.040 50.715 135.830 51.595 ;
        RECT 105.500 50.645 105.780 50.665 ;
        RECT 121.040 50.645 122.670 50.715 ;
        RECT 134.975 50.695 135.805 50.715 ;
        RECT 88.610 50.325 119.470 50.645 ;
        RECT 121.040 50.615 122.000 50.645 ;
        RECT 105.500 50.295 105.780 50.325 ;
        RECT 78.160 49.020 84.440 49.980 ;
        RECT 92.915 49.865 108.430 49.875 ;
        RECT 24.770 46.320 25.770 47.370 ;
        RECT 73.720 46.070 75.020 48.920 ;
        RECT 92.915 48.905 108.450 49.865 ;
        RECT 132.250 48.995 133.130 49.335 ;
        RECT 134.950 48.995 135.830 49.335 ;
        RECT 92.915 48.900 108.430 48.905 ;
        RECT 130.450 48.095 131.330 48.135 ;
        RECT 130.450 47.795 131.950 48.095 ;
        RECT 92.060 46.765 92.560 46.795 ;
        RECT 88.480 46.265 92.560 46.765 ;
        RECT 92.060 46.235 92.560 46.265 ;
        RECT 63.420 44.770 75.020 46.070 ;
        RECT 23.600 39.580 32.740 43.410 ;
        RECT 54.220 33.270 55.670 38.920 ;
        RECT 59.620 38.470 62.920 41.720 ;
        RECT 63.420 34.770 66.070 44.770 ;
        RECT 80.420 44.470 83.520 45.370 ;
        RECT 131.650 44.895 131.950 47.795 ;
        RECT 134.950 46.595 135.830 46.935 ;
        RECT 132.250 45.795 133.130 46.135 ;
        RECT 136.750 44.895 137.630 44.935 ;
        RECT 102.340 44.630 102.620 44.665 ;
        RECT 119.080 44.640 119.400 44.670 ;
        RECT 102.930 44.630 119.400 44.640 ;
        RECT 66.570 38.220 69.870 41.720 ;
        RECT 73.120 38.470 76.620 41.720 ;
        RECT 80.410 38.420 83.510 44.470 ;
        RECT 102.330 44.330 119.400 44.630 ;
        RECT 131.650 44.595 137.630 44.895 ;
        RECT 102.340 44.295 102.620 44.330 ;
        RECT 102.930 44.320 119.400 44.330 ;
        RECT 119.080 44.290 119.400 44.320 ;
        RECT 119.720 43.935 120.680 43.965 ;
        RECT 127.480 43.935 128.440 43.965 ;
        RECT 112.220 42.975 128.440 43.935 ;
        RECT 132.250 43.395 133.130 43.735 ;
        RECT 134.950 43.395 135.830 43.735 ;
        RECT 119.720 42.945 120.680 42.975 ;
        RECT 127.480 42.945 128.440 42.975 ;
        RECT 132.250 41.795 133.130 42.135 ;
        RECT 134.950 41.795 135.830 42.135 ;
        RECT 129.850 41.375 130.150 41.405 ;
        RECT 127.780 41.075 130.150 41.375 ;
        RECT 129.850 41.045 130.150 41.075 ;
        RECT 119.700 40.355 124.170 40.385 ;
        RECT 116.300 39.425 124.170 40.355 ;
        RECT 116.300 39.395 120.760 39.425 ;
        RECT 132.250 39.395 133.130 39.735 ;
        RECT 134.950 39.395 135.830 39.735 ;
        RECT 102.700 39.245 103.660 39.275 ;
        RECT 92.400 38.675 92.720 38.705 ;
        RECT 98.650 38.675 98.970 38.705 ;
        RECT 92.400 38.355 101.130 38.675 ;
        RECT 92.400 38.325 92.720 38.355 ;
        RECT 98.650 38.325 98.970 38.355 ;
        RECT 102.700 38.285 105.320 39.245 ;
        RECT 115.690 38.345 116.010 38.375 ;
        RECT 122.550 38.345 122.870 38.375 ;
        RECT 102.700 38.255 103.660 38.285 ;
        RECT 115.690 38.025 122.870 38.345 ;
        RECT 115.690 37.995 116.010 38.025 ;
        RECT 122.550 37.995 122.870 38.025 ;
        RECT 132.250 36.995 133.130 37.335 ;
        RECT 134.950 36.995 135.830 37.335 ;
        RECT 94.050 36.035 96.690 36.995 ;
        RECT 132.250 35.395 133.130 35.735 ;
        RECT 134.950 35.395 135.830 35.735 ;
        RECT 19.920 32.270 55.670 33.270 ;
        RECT 59.620 31.720 62.920 34.770 ;
        RECT 63.420 31.670 69.670 34.770 ;
        RECT 73.120 31.720 76.620 34.770 ;
        RECT 59.820 24.920 62.920 28.020 ;
        RECT 66.370 24.720 69.870 28.220 ;
        RECT 73.120 24.720 76.620 28.020 ;
        RECT 79.700 23.945 80.300 35.155 ;
        RECT 97.220 34.665 98.180 34.725 ;
        RECT 85.750 33.705 98.180 34.665 ;
        RECT 134.950 34.595 135.830 34.935 ;
        RECT 104.330 33.995 105.290 34.025 ;
        RECT 97.220 33.645 98.180 33.705 ;
        RECT 99.150 33.425 99.470 33.455 ;
        RECT 100.900 33.425 101.220 33.455 ;
        RECT 102.800 33.425 105.290 33.995 ;
        RECT 107.760 33.425 108.160 33.465 ;
        RECT 81.405 33.145 81.705 33.155 ;
        RECT 81.370 32.865 81.740 33.145 ;
        RECT 93.750 33.105 108.160 33.425 ;
        RECT 99.150 33.075 99.470 33.105 ;
        RECT 100.900 33.075 101.220 33.105 ;
        RECT 102.800 33.035 105.290 33.105 ;
        RECT 107.760 33.065 108.160 33.105 ;
        RECT 104.330 33.005 105.290 33.035 ;
        RECT 122.540 32.960 122.860 33.005 ;
        RECT 132.250 32.995 133.130 33.335 ;
        RECT 134.950 32.995 135.830 33.335 ;
        RECT 13.630 23.920 80.300 23.945 ;
        RECT 13.610 23.370 80.300 23.920 ;
        RECT 13.630 23.345 80.300 23.370 ;
        RECT 81.405 22.580 81.705 32.865 ;
        RECT 122.510 32.640 122.890 32.960 ;
        RECT 122.540 32.635 122.860 32.640 ;
        RECT 132.250 32.195 133.130 32.535 ;
        RECT 134.950 32.195 135.830 32.535 ;
        RECT 132.250 31.395 133.130 31.735 ;
        RECT 134.950 31.395 135.830 31.735 ;
        RECT 82.685 30.790 83.340 31.315 ;
        RECT 12.795 22.285 81.705 22.580 ;
        RECT 12.795 21.870 13.390 22.285 ;
        RECT 34.720 22.280 81.705 22.285 ;
        RECT 12.795 12.745 13.395 21.870 ;
        RECT 65.620 21.445 66.020 21.840 ;
        RECT 82.920 21.740 83.200 30.790 ;
        RECT 127.495 30.200 128.425 30.230 ;
        RECT 109.670 29.905 117.310 29.925 ;
        RECT 109.670 28.965 124.160 29.905 ;
        RECT 127.495 29.270 135.875 30.200 ;
        RECT 127.495 29.240 128.425 29.270 ;
        RECT 134.945 29.225 135.875 29.270 ;
        RECT 116.300 28.945 124.160 28.965 ;
        RECT 101.390 27.285 103.820 28.245 ;
        RECT 132.240 27.085 133.120 27.425 ;
        RECT 134.940 27.085 135.820 27.425 ;
        RECT 119.960 27.015 120.460 27.045 ;
        RECT 119.960 26.995 120.750 27.015 ;
        RECT 119.960 26.675 122.900 26.995 ;
        RECT 119.960 26.515 120.750 26.675 ;
        RECT 119.960 26.485 120.460 26.515 ;
        RECT 135.220 25.685 135.620 25.715 ;
        RECT 135.175 25.225 135.620 25.685 ;
        RECT 129.980 25.195 130.280 25.225 ;
        RECT 135.220 25.195 135.620 25.225 ;
        RECT 124.720 24.895 130.280 25.195 ;
        RECT 129.980 24.865 130.280 24.895 ;
        RECT 88.560 24.015 89.060 24.045 ;
        RECT 119.960 24.015 120.460 24.045 ;
        RECT 88.560 23.515 120.460 24.015 ;
        RECT 88.560 23.485 89.060 23.515 ;
        RECT 119.960 23.485 120.460 23.515 ;
        RECT 132.230 22.985 133.110 23.325 ;
        RECT 134.930 22.985 135.810 23.325 ;
        RECT 94.390 21.985 133.630 21.995 ;
        RECT 67.520 21.460 83.200 21.740 ;
        RECT 31.000 20.680 32.540 21.050 ;
        RECT 65.750 19.835 65.890 21.445 ;
        RECT 67.590 19.835 67.730 21.460 ;
        RECT 88.080 21.045 133.630 21.985 ;
        RECT 88.080 21.000 89.020 21.045 ;
        RECT 89.860 21.025 90.880 21.045 ;
        RECT 94.390 21.035 133.630 21.045 ;
        RECT 131.340 21.025 132.360 21.035 ;
        RECT 63.850 19.515 64.110 19.835 ;
        RECT 65.690 19.515 65.950 19.835 ;
        RECT 67.530 19.515 67.790 19.835 ;
        RECT 20.150 19.175 20.410 19.495 ;
        RECT 20.610 19.175 20.870 19.495 ;
        RECT 29.810 19.175 30.070 19.495 ;
        RECT 36.710 19.175 36.970 19.495 ;
        RECT 45.450 19.175 45.710 19.495 ;
        RECT 48.670 19.175 48.930 19.495 ;
        RECT 61.550 19.175 61.810 19.495 ;
        RECT 14.515 18.425 14.945 18.870 ;
        RECT 18.310 18.495 18.570 18.815 ;
        RECT 17.850 16.455 18.110 16.775 ;
        RECT 17.910 14.395 18.050 16.455 ;
        RECT 17.850 14.075 18.110 14.395 ;
        RECT 16.460 12.860 16.740 13.230 ;
        RECT 12.820 12.725 13.370 12.745 ;
        RECT 15.080 11.500 15.360 11.870 ;
        RECT 15.150 -1.245 15.290 11.500 ;
        RECT 16.530 6.235 16.670 12.860 ;
        RECT 17.910 11.675 18.050 14.075 ;
        RECT 17.850 11.355 18.110 11.675 ;
        RECT 17.390 7.615 17.650 7.935 ;
        RECT 17.450 6.575 17.590 7.615 ;
        RECT 17.390 6.255 17.650 6.575 ;
        RECT 16.470 5.915 16.730 6.235 ;
        RECT 17.910 5.895 18.050 11.355 ;
        RECT 17.850 5.575 18.110 5.895 ;
        RECT 18.370 2.350 18.510 18.495 ;
        RECT 19.230 16.455 19.490 16.775 ;
        RECT 19.290 9.635 19.430 16.455 ;
        RECT 20.210 15.075 20.350 19.175 ;
        RECT 20.150 14.755 20.410 15.075 ;
        RECT 19.690 10.335 19.950 10.655 ;
        RECT 19.230 9.315 19.490 9.635 ;
        RECT 19.230 8.635 19.490 8.955 ;
        RECT 19.290 4.195 19.430 8.635 ;
        RECT 19.750 6.235 19.890 10.335 ;
        RECT 20.150 8.295 20.410 8.615 ;
        RECT 20.210 6.915 20.350 8.295 ;
        RECT 20.150 6.595 20.410 6.915 ;
        RECT 19.690 5.915 19.950 6.235 ;
        RECT 19.230 3.875 19.490 4.195 ;
        RECT 18.300 1.980 18.580 2.350 ;
        RECT 15.090 -1.565 15.350 -1.245 ;
        RECT 20.210 -2.265 20.350 6.595 ;
        RECT 20.670 1.475 20.810 19.175 ;
        RECT 24.290 18.835 24.550 19.155 ;
        RECT 24.350 13.715 24.490 18.835 ;
        RECT 28.890 18.495 29.150 18.815 ;
        RECT 27.510 16.795 27.770 17.115 ;
        RECT 26.590 15.775 26.850 16.095 ;
        RECT 24.290 13.395 24.550 13.715 ;
        RECT 23.370 11.015 23.630 11.335 ;
        RECT 23.430 9.635 23.570 11.015 ;
        RECT 23.370 9.315 23.630 9.635 ;
        RECT 26.650 8.955 26.790 15.775 ;
        RECT 26.590 8.635 26.850 8.955 ;
        RECT 21.070 7.955 21.330 8.275 ;
        RECT 21.990 7.955 22.250 8.275 ;
        RECT 21.130 6.235 21.270 7.955 ;
        RECT 21.070 5.915 21.330 6.235 ;
        RECT 21.130 5.750 21.270 5.915 ;
        RECT 22.050 5.895 22.190 7.955 ;
        RECT 25.210 7.615 25.470 7.935 ;
        RECT 21.060 5.380 21.340 5.750 ;
        RECT 21.990 5.575 22.250 5.895 ;
        RECT 22.050 3.515 22.190 5.575 ;
        RECT 25.270 4.195 25.410 7.615 ;
        RECT 25.210 3.875 25.470 4.195 ;
        RECT 21.990 3.195 22.250 3.515 ;
        RECT 26.130 2.855 26.390 3.175 ;
        RECT 24.290 2.515 24.550 2.835 ;
        RECT 24.350 1.475 24.490 2.515 ;
        RECT 20.610 1.155 20.870 1.475 ;
        RECT 24.290 1.155 24.550 1.475 ;
        RECT 20.670 -1.925 20.810 1.155 ;
        RECT 26.190 -1.245 26.330 2.855 ;
        RECT 27.570 0.455 27.710 16.795 ;
        RECT 27.970 15.775 28.230 16.095 ;
        RECT 28.430 15.775 28.690 16.095 ;
        RECT 28.030 12.015 28.170 15.775 ;
        RECT 27.970 11.695 28.230 12.015 ;
        RECT 28.490 6.575 28.630 15.775 ;
        RECT 28.950 14.055 29.090 18.495 ;
        RECT 29.870 17.115 30.010 19.175 ;
        RECT 33.950 18.835 34.210 19.155 ;
        RECT 30.730 18.495 30.990 18.815 ;
        RECT 30.790 17.455 30.930 18.495 ;
        RECT 30.730 17.135 30.990 17.455 ;
        RECT 29.810 16.795 30.070 17.115 ;
        RECT 33.030 16.115 33.290 16.435 ;
        RECT 29.810 15.775 30.070 16.095 ;
        RECT 28.890 13.735 29.150 14.055 ;
        RECT 29.870 10.655 30.010 15.775 ;
        RECT 31.000 15.240 32.540 15.610 ;
        RECT 30.730 14.415 30.990 14.735 ;
        RECT 30.270 11.925 30.530 12.015 ;
        RECT 30.790 11.925 30.930 14.415 ;
        RECT 31.650 13.735 31.910 14.055 ;
        RECT 31.190 13.055 31.450 13.375 ;
        RECT 31.250 12.355 31.390 13.055 ;
        RECT 31.190 12.035 31.450 12.355 ;
        RECT 30.270 11.785 30.930 11.925 ;
        RECT 30.270 11.695 30.530 11.785 ;
        RECT 29.810 10.335 30.070 10.655 ;
        RECT 29.870 9.295 30.010 10.335 ;
        RECT 29.810 8.975 30.070 9.295 ;
        RECT 30.330 9.035 30.470 11.695 ;
        RECT 31.710 11.335 31.850 13.735 ;
        RECT 33.090 12.015 33.230 16.115 ;
        RECT 34.010 15.075 34.150 18.835 ;
        RECT 36.250 18.495 36.510 18.815 ;
        RECT 34.300 17.960 35.840 18.330 ;
        RECT 34.410 16.455 34.670 16.775 ;
        RECT 33.950 14.755 34.210 15.075 ;
        RECT 33.490 14.075 33.750 14.395 ;
        RECT 33.030 11.695 33.290 12.015 ;
        RECT 31.650 11.015 31.910 11.335 ;
        RECT 33.030 10.335 33.290 10.655 ;
        RECT 31.000 9.800 32.540 10.170 ;
        RECT 30.330 8.895 30.930 9.035 ;
        RECT 29.350 8.470 29.610 8.615 ;
        RECT 29.340 8.355 29.620 8.470 ;
        RECT 29.340 8.215 30.010 8.355 ;
        RECT 30.270 8.295 30.530 8.615 ;
        RECT 29.340 8.100 29.620 8.215 ;
        RECT 28.430 6.255 28.690 6.575 ;
        RECT 29.350 5.235 29.610 5.555 ;
        RECT 28.430 4.895 28.690 5.215 ;
        RECT 27.510 0.135 27.770 0.455 ;
        RECT 26.130 -1.565 26.390 -1.245 ;
        RECT 20.610 -2.245 20.870 -1.925 ;
        RECT 20.150 -2.585 20.410 -2.265 ;
        RECT 28.490 -2.605 28.630 4.895 ;
        RECT 28.890 3.195 29.150 3.515 ;
        RECT 28.950 0.795 29.090 3.195 ;
        RECT 29.410 1.135 29.550 5.235 ;
        RECT 29.350 0.815 29.610 1.135 ;
        RECT 28.890 0.475 29.150 0.795 ;
        RECT 29.870 0.195 30.010 8.215 ;
        RECT 30.330 6.430 30.470 8.295 ;
        RECT 30.790 6.915 30.930 8.895 ;
        RECT 30.730 6.595 30.990 6.915 ;
        RECT 30.260 6.060 30.540 6.430 ;
        RECT 31.000 4.360 32.540 4.730 ;
        RECT 33.090 3.515 33.230 10.335 ;
        RECT 33.550 8.955 33.690 14.075 ;
        RECT 34.010 12.355 34.150 14.755 ;
        RECT 34.470 14.735 34.610 16.455 ;
        RECT 34.410 14.415 34.670 14.735 ;
        RECT 36.310 14.395 36.450 18.495 ;
        RECT 36.770 17.795 36.910 19.175 ;
        RECT 39.010 18.495 39.270 18.815 ;
        RECT 36.710 17.475 36.970 17.795 ;
        RECT 36.710 16.455 36.970 16.775 ;
        RECT 36.250 14.075 36.510 14.395 ;
        RECT 36.770 13.375 36.910 16.455 ;
        RECT 39.070 13.715 39.210 18.495 ;
        RECT 41.770 17.135 42.030 17.455 ;
        RECT 39.010 13.395 39.270 13.715 ;
        RECT 36.710 13.055 36.970 13.375 ;
        RECT 34.300 12.520 35.840 12.890 ;
        RECT 36.770 12.355 36.910 13.055 ;
        RECT 33.950 12.035 34.210 12.355 ;
        RECT 36.710 12.035 36.970 12.355 ;
        RECT 34.870 11.075 35.130 11.335 ;
        RECT 34.010 11.015 35.130 11.075 ;
        RECT 34.010 10.935 35.070 11.015 ;
        RECT 33.490 8.635 33.750 8.955 ;
        RECT 33.550 5.895 33.690 8.635 ;
        RECT 33.490 5.575 33.750 5.895 ;
        RECT 34.010 4.955 34.150 10.935 ;
        RECT 41.830 8.275 41.970 17.135 ;
        RECT 43.150 16.115 43.410 16.435 ;
        RECT 43.210 14.735 43.350 16.115 ;
        RECT 45.510 14.735 45.650 19.175 ;
        RECT 48.210 18.835 48.470 19.155 ;
        RECT 43.150 14.415 43.410 14.735 ;
        RECT 45.450 14.645 45.710 14.735 ;
        RECT 44.520 14.220 44.800 14.590 ;
        RECT 45.450 14.505 46.110 14.645 ;
        RECT 45.450 14.415 45.710 14.505 ;
        RECT 44.590 8.615 44.730 14.220 ;
        RECT 45.450 13.055 45.710 13.375 ;
        RECT 45.510 12.015 45.650 13.055 ;
        RECT 45.450 11.695 45.710 12.015 ;
        RECT 41.770 7.955 42.030 8.275 ;
        RECT 43.600 8.100 43.880 8.470 ;
        RECT 44.530 8.295 44.790 8.615 ;
        RECT 37.630 7.615 37.890 7.935 ;
        RECT 34.300 7.080 35.840 7.450 ;
        RECT 34.870 5.575 35.130 5.895 ;
        RECT 33.550 4.815 34.150 4.955 ;
        RECT 33.550 4.195 33.690 4.815 ;
        RECT 33.490 3.875 33.750 4.195 ;
        RECT 33.030 3.195 33.290 3.515 ;
        RECT 33.550 3.175 33.690 3.875 ;
        RECT 34.930 3.515 35.070 5.575 ;
        RECT 34.870 3.195 35.130 3.515 ;
        RECT 33.490 2.855 33.750 3.175 ;
        RECT 29.410 0.055 30.010 0.195 ;
        RECT 29.410 -2.605 29.550 0.055 ;
        RECT 33.030 -0.545 33.290 -0.225 ;
        RECT 33.090 -2.265 33.230 -0.545 ;
        RECT 33.550 -1.585 33.690 2.855 ;
        RECT 37.690 2.835 37.830 7.615 ;
        RECT 41.830 6.915 41.970 7.955 ;
        RECT 41.770 6.595 42.030 6.915 ;
        RECT 43.670 6.575 43.810 8.100 ;
        RECT 45.970 7.935 46.110 14.505 ;
        RECT 48.270 14.055 48.410 18.835 ;
        RECT 48.730 14.055 48.870 19.175 ;
        RECT 53.730 18.495 53.990 18.815 ;
        RECT 54.650 18.495 54.910 18.815 ;
        RECT 56.950 18.495 57.210 18.815 ;
        RECT 53.790 17.455 53.930 18.495 ;
        RECT 54.710 17.795 54.850 18.495 ;
        RECT 54.650 17.475 54.910 17.795 ;
        RECT 53.730 17.135 53.990 17.455 ;
        RECT 50.050 16.455 50.310 16.775 ;
        RECT 48.210 13.735 48.470 14.055 ;
        RECT 48.670 13.735 48.930 14.055 ;
        RECT 48.270 8.615 48.410 13.735 ;
        RECT 48.670 13.055 48.930 13.375 ;
        RECT 48.730 12.015 48.870 13.055 ;
        RECT 48.670 11.695 48.930 12.015 ;
        RECT 48.210 8.295 48.470 8.615 ;
        RECT 45.910 7.615 46.170 7.935 ;
        RECT 44.530 6.595 44.790 6.915 ;
        RECT 43.610 6.255 43.870 6.575 ;
        RECT 38.090 5.575 38.350 5.895 ;
        RECT 37.630 2.515 37.890 2.835 ;
        RECT 38.150 2.495 38.290 5.575 ;
        RECT 39.010 5.235 39.270 5.555 ;
        RECT 38.090 2.175 38.350 2.495 ;
        RECT 34.300 1.640 35.840 2.010 ;
        RECT 33.490 -1.905 33.750 -1.585 ;
        RECT 38.150 -1.925 38.290 2.175 ;
        RECT 39.070 -1.925 39.210 5.235 ;
        RECT 41.760 3.340 42.040 3.710 ;
        RECT 41.830 0.795 41.970 3.340 ;
        RECT 44.590 0.795 44.730 6.595 ;
        RECT 45.970 6.235 46.110 7.615 ;
        RECT 48.270 6.915 48.410 8.295 ;
        RECT 48.210 6.595 48.470 6.915 ;
        RECT 47.290 6.255 47.550 6.575 ;
        RECT 45.910 5.915 46.170 6.235 ;
        RECT 44.980 5.380 45.260 5.750 ;
        RECT 46.370 5.575 46.630 5.895 ;
        RECT 45.050 1.475 45.190 5.380 ;
        RECT 45.450 2.515 45.710 2.835 ;
        RECT 44.990 1.155 45.250 1.475 ;
        RECT 41.770 0.475 42.030 0.795 ;
        RECT 44.530 0.475 44.790 0.795 ;
        RECT 39.470 0.135 39.730 0.455 ;
        RECT 39.530 -1.245 39.670 0.135 ;
        RECT 45.510 -1.245 45.650 2.515 ;
        RECT 46.430 2.495 46.570 5.575 ;
        RECT 46.830 3.195 47.090 3.515 ;
        RECT 46.370 2.175 46.630 2.495 ;
        RECT 39.470 -1.565 39.730 -1.245 ;
        RECT 45.450 -1.565 45.710 -1.245 ;
        RECT 46.430 -1.925 46.570 2.175 ;
        RECT 46.890 0.455 47.030 3.195 ;
        RECT 47.350 2.835 47.490 6.255 ;
        RECT 50.110 3.515 50.250 16.455 ;
        RECT 57.010 14.735 57.150 18.495 ;
        RECT 61.610 17.795 61.750 19.175 ;
        RECT 61.550 17.475 61.810 17.795 ;
        RECT 57.870 16.795 58.130 17.115 ;
        RECT 62.470 16.795 62.730 17.115 ;
        RECT 57.930 15.075 58.070 16.795 ;
        RECT 59.710 16.115 59.970 16.435 ;
        RECT 57.870 14.755 58.130 15.075 ;
        RECT 56.950 14.415 57.210 14.735 ;
        RECT 56.490 13.735 56.750 14.055 ;
        RECT 51.890 13.395 52.150 13.715 ;
        RECT 51.950 12.015 52.090 13.395 ;
        RECT 56.550 12.015 56.690 13.735 ;
        RECT 51.890 11.695 52.150 12.015 ;
        RECT 56.490 11.695 56.750 12.015 ;
        RECT 56.550 10.655 56.690 11.695 ;
        RECT 57.010 11.675 57.150 14.415 ;
        RECT 59.770 14.395 59.910 16.115 ;
        RECT 59.710 14.075 59.970 14.395 ;
        RECT 57.410 13.735 57.670 14.055 ;
        RECT 57.470 11.675 57.610 13.735 ;
        RECT 61.090 13.395 61.350 13.715 ;
        RECT 57.870 13.055 58.130 13.375 ;
        RECT 57.930 12.355 58.070 13.055 ;
        RECT 57.870 12.035 58.130 12.355 ;
        RECT 56.950 11.355 57.210 11.675 ;
        RECT 57.410 11.355 57.670 11.675 ;
        RECT 56.490 10.335 56.750 10.655 ;
        RECT 56.550 9.035 56.690 10.335 ;
        RECT 57.930 9.295 58.070 12.035 ;
        RECT 59.710 11.695 59.970 12.015 ;
        RECT 52.810 8.635 53.070 8.955 ;
        RECT 56.550 8.895 57.610 9.035 ;
        RECT 57.870 8.975 58.130 9.295 ;
        RECT 59.770 8.955 59.910 11.695 ;
        RECT 61.150 10.995 61.290 13.395 ;
        RECT 62.530 12.015 62.670 16.795 ;
        RECT 63.910 16.775 64.050 19.515 ;
        RECT 76.270 19.175 76.530 19.495 ;
        RECT 97.900 19.355 98.860 20.510 ;
        RECT 104.610 19.355 105.570 20.490 ;
        RECT 111.180 19.355 112.140 20.650 ;
        RECT 112.960 19.355 113.920 20.525 ;
        RECT 118.070 19.355 119.030 20.680 ;
        RECT 124.660 19.355 125.620 20.680 ;
        RECT 132.620 19.355 133.640 19.385 ;
        RECT 65.690 18.835 65.950 19.155 ;
        RECT 64.770 18.495 65.030 18.815 ;
        RECT 64.830 17.795 64.970 18.495 ;
        RECT 64.770 17.475 65.030 17.795 ;
        RECT 63.850 16.455 64.110 16.775 ;
        RECT 64.310 16.455 64.570 16.775 ;
        RECT 65.230 16.455 65.490 16.775 ;
        RECT 64.370 13.375 64.510 16.455 ;
        RECT 64.310 13.055 64.570 13.375 ;
        RECT 62.470 11.695 62.730 12.015 ;
        RECT 64.370 11.675 64.510 13.055 ;
        RECT 64.310 11.355 64.570 11.675 ;
        RECT 61.090 10.675 61.350 10.995 ;
        RECT 50.500 6.060 50.780 6.430 ;
        RECT 52.870 6.235 53.010 8.635 ;
        RECT 57.470 8.615 57.610 8.895 ;
        RECT 59.710 8.635 59.970 8.955 ;
        RECT 61.150 8.615 61.290 10.675 ;
        RECT 61.550 10.335 61.810 10.655 ;
        RECT 57.410 8.295 57.670 8.615 ;
        RECT 61.090 8.295 61.350 8.615 ;
        RECT 56.490 7.955 56.750 8.275 ;
        RECT 56.550 6.575 56.690 7.955 ;
        RECT 56.490 6.255 56.750 6.575 ;
        RECT 50.510 5.915 50.770 6.060 ;
        RECT 52.350 5.915 52.610 6.235 ;
        RECT 52.810 5.915 53.070 6.235 ;
        RECT 50.050 3.195 50.310 3.515 ;
        RECT 47.290 2.515 47.550 2.835 ;
        RECT 50.570 0.455 50.710 5.915 ;
        RECT 51.430 4.895 51.690 5.215 ;
        RECT 46.830 0.135 47.090 0.455 ;
        RECT 48.670 0.135 48.930 0.455 ;
        RECT 50.510 0.135 50.770 0.455 ;
        RECT 48.730 -1.245 48.870 0.135 ;
        RECT 48.670 -1.565 48.930 -1.245 ;
        RECT 51.490 -1.585 51.630 4.895 ;
        RECT 52.410 2.495 52.550 5.915 ;
        RECT 52.870 3.175 53.010 5.915 ;
        RECT 54.190 5.575 54.450 5.895 ;
        RECT 54.250 4.195 54.390 5.575 ;
        RECT 57.470 5.555 57.610 8.295 ;
        RECT 58.790 5.575 59.050 5.895 ;
        RECT 57.410 5.235 57.670 5.555 ;
        RECT 54.190 3.875 54.450 4.195 ;
        RECT 57.470 3.175 57.610 5.235 ;
        RECT 52.810 2.855 53.070 3.175 ;
        RECT 57.410 2.855 57.670 3.175 ;
        RECT 52.350 2.175 52.610 2.495 ;
        RECT 56.030 2.175 56.290 2.495 ;
        RECT 51.430 -1.905 51.690 -1.585 ;
        RECT 38.090 -2.245 38.350 -1.925 ;
        RECT 39.010 -2.245 39.270 -1.925 ;
        RECT 46.370 -2.245 46.630 -1.925 ;
        RECT 52.410 -2.265 52.550 2.175 ;
        RECT 56.090 1.475 56.230 2.175 ;
        RECT 56.030 1.155 56.290 1.475 ;
        RECT 58.850 0.795 58.990 5.575 ;
        RECT 61.150 3.175 61.290 8.295 ;
        RECT 61.610 6.235 61.750 10.335 ;
        RECT 63.850 7.955 64.110 8.275 ;
        RECT 61.550 5.915 61.810 6.235 ;
        RECT 61.090 2.855 61.350 3.175 ;
        RECT 60.170 2.515 60.430 2.835 ;
        RECT 58.790 0.475 59.050 0.795 ;
        RECT 60.230 0.455 60.370 2.515 ;
        RECT 61.610 0.795 61.750 5.915 ;
        RECT 63.910 0.795 64.050 7.955 ;
        RECT 65.290 5.895 65.430 16.455 ;
        RECT 65.750 14.395 65.890 18.835 ;
        RECT 76.330 17.795 76.470 19.175 ;
        RECT 91.050 18.395 133.880 19.355 ;
        RECT 91.140 18.375 92.160 18.395 ;
        RECT 76.270 17.475 76.530 17.795 ;
        RECT 71.210 17.135 71.470 17.455 ;
        RECT 71.270 15.075 71.410 17.135 ;
        RECT 73.970 15.775 74.230 16.095 ;
        RECT 71.210 14.755 71.470 15.075 ;
        RECT 65.690 14.075 65.950 14.395 ;
        RECT 65.750 11.675 65.890 14.075 ;
        RECT 66.150 13.395 66.410 13.715 ;
        RECT 66.210 12.355 66.350 13.395 ;
        RECT 66.150 12.035 66.410 12.355 ;
        RECT 65.690 11.355 65.950 11.675 ;
        RECT 66.150 11.355 66.410 11.675 ;
        RECT 66.210 9.635 66.350 11.355 ;
        RECT 71.670 11.015 71.930 11.335 ;
        RECT 71.730 9.635 71.870 11.015 ;
        RECT 72.590 10.335 72.850 10.655 ;
        RECT 66.150 9.315 66.410 9.635 ;
        RECT 71.670 9.315 71.930 9.635 ;
        RECT 70.290 8.295 70.550 8.615 ;
        RECT 68.910 7.615 69.170 7.935 ;
        RECT 69.830 7.615 70.090 7.935 ;
        RECT 68.970 6.235 69.110 7.615 ;
        RECT 68.910 5.915 69.170 6.235 ;
        RECT 65.230 5.575 65.490 5.895 ;
        RECT 65.290 3.515 65.430 5.575 ;
        RECT 68.910 5.235 69.170 5.555 ;
        RECT 65.230 3.195 65.490 3.515 ;
        RECT 61.550 0.475 61.810 0.795 ;
        RECT 63.850 0.475 64.110 0.795 ;
        RECT 65.290 0.705 65.430 3.195 ;
        RECT 68.970 2.495 69.110 5.235 ;
        RECT 68.910 2.175 69.170 2.495 ;
        RECT 69.890 1.135 70.030 7.615 ;
        RECT 70.350 4.195 70.490 8.295 ;
        RECT 72.130 7.615 72.390 7.935 ;
        RECT 72.190 5.895 72.330 7.615 ;
        RECT 72.130 5.575 72.390 5.895 ;
        RECT 70.290 3.875 70.550 4.195 ;
        RECT 69.830 0.815 70.090 1.135 ;
        RECT 65.690 0.705 65.950 0.795 ;
        RECT 65.290 0.565 65.950 0.705 ;
        RECT 65.690 0.475 65.950 0.565 ;
        RECT 60.170 0.135 60.430 0.455 ;
        RECT 69.370 0.135 69.630 0.455 ;
        RECT 57.410 -0.545 57.670 -0.225 ;
        RECT 57.470 -1.925 57.610 -0.545 ;
        RECT 69.430 -1.245 69.570 0.135 ;
        RECT 69.370 -1.565 69.630 -1.245 ;
        RECT 69.890 -1.925 70.030 0.815 ;
        RECT 72.650 -0.225 72.790 10.335 ;
        RECT 74.030 8.955 74.170 15.775 ;
        RECT 77.650 11.695 77.910 12.015 ;
        RECT 75.810 10.335 76.070 10.655 ;
        RECT 73.970 8.635 74.230 8.955 ;
        RECT 73.050 7.615 73.310 7.935 ;
        RECT 73.110 4.195 73.250 7.615 ;
        RECT 73.050 3.875 73.310 4.195 ;
        RECT 73.050 0.815 73.310 1.135 ;
        RECT 72.590 -0.545 72.850 -0.225 ;
        RECT 57.410 -2.245 57.670 -1.925 ;
        RECT 69.830 -2.245 70.090 -1.925 ;
        RECT 72.650 -2.265 72.790 -0.545 ;
        RECT 73.110 -1.245 73.250 0.815 ;
        RECT 73.050 -1.565 73.310 -1.245 ;
        RECT 74.030 -1.585 74.170 8.635 ;
        RECT 75.870 6.575 76.010 10.335 ;
        RECT 75.810 6.255 76.070 6.575 ;
        RECT 75.810 2.855 76.070 3.175 ;
        RECT 75.870 2.350 76.010 2.855 ;
        RECT 75.800 1.980 76.080 2.350 ;
        RECT 77.710 0.795 77.850 11.695 ;
        RECT 79.490 11.355 79.750 11.675 ;
        RECT 94.810 11.605 128.260 12.565 ;
        RECT 78.570 8.295 78.830 8.615 ;
        RECT 78.630 3.855 78.770 8.295 ;
        RECT 79.550 5.895 79.690 11.355 ;
        RECT 80.410 10.335 80.670 10.655 ;
        RECT 97.700 10.420 98.660 11.605 ;
        RECT 80.470 9.150 80.610 10.335 ;
        RECT 104.430 10.330 105.390 11.605 ;
        RECT 111.080 10.270 112.040 11.605 ;
        RECT 117.910 10.250 118.870 11.605 ;
        RECT 124.560 10.140 125.520 11.605 ;
        RECT 82.620 9.265 83.170 9.285 ;
        RECT 88.495 9.265 89.205 9.445 ;
        RECT 80.400 8.780 80.680 9.150 ;
        RECT 82.595 8.665 89.205 9.265 ;
        RECT 82.620 8.645 83.170 8.665 ;
        RECT 88.495 8.545 89.205 8.665 ;
        RECT 79.950 7.955 80.210 8.275 ;
        RECT 79.490 5.575 79.750 5.895 ;
        RECT 78.570 3.535 78.830 3.855 ;
        RECT 78.630 0.795 78.770 3.535 ;
        RECT 79.550 3.515 79.690 5.575 ;
        RECT 79.490 3.195 79.750 3.515 ;
        RECT 79.030 2.515 79.290 2.835 ;
        RECT 77.650 0.475 77.910 0.795 ;
        RECT 78.570 0.475 78.830 0.795 ;
        RECT 76.730 -0.545 76.990 -0.225 ;
        RECT 73.970 -1.905 74.230 -1.585 ;
        RECT 76.790 -1.925 76.930 -0.545 ;
        RECT 76.730 -2.245 76.990 -1.925 ;
        RECT 77.710 -2.265 77.850 0.475 ;
        RECT 79.090 -1.585 79.230 2.515 ;
        RECT 80.010 1.135 80.150 7.955 ;
        RECT 86.050 3.650 87.150 4.750 ;
        RECT 87.940 1.510 88.820 1.850 ;
        RECT 90.640 1.510 91.520 1.850 ;
        RECT 79.950 0.815 80.210 1.135 ;
        RECT 89.200 -0.250 90.100 0.650 ;
        RECT 90.650 0.375 91.550 0.400 ;
        RECT 90.630 0.000 91.570 0.375 ;
        RECT 79.030 -1.905 79.290 -1.585 ;
        RECT 33.030 -2.585 33.290 -2.265 ;
        RECT 52.350 -2.585 52.610 -2.265 ;
        RECT 72.590 -2.585 72.850 -2.265 ;
        RECT 77.650 -2.585 77.910 -2.265 ;
        RECT 28.430 -2.925 28.690 -2.605 ;
        RECT 29.350 -2.925 29.610 -2.605 ;
      LAYER met3 ;
        RECT 6.295 100.345 86.195 100.350 ;
        RECT 6.270 99.755 86.195 100.345 ;
        RECT 6.295 99.750 86.195 99.755 ;
        RECT 37.060 98.590 37.440 99.360 ;
        RECT 41.670 99.150 42.050 99.160 ;
        RECT 115.280 99.150 115.610 99.210 ;
        RECT 39.775 99.090 40.105 99.095 ;
        RECT 39.540 99.080 40.105 99.090 ;
        RECT 39.540 98.780 40.730 99.080 ;
        RECT 41.670 98.850 115.655 99.150 ;
        RECT 144.035 99.145 144.615 99.725 ;
        RECT 41.670 98.840 42.050 98.850 ;
        RECT 39.540 98.770 40.105 98.780 ;
        RECT 39.775 98.765 40.105 98.770 ;
        RECT 44.290 98.015 44.590 98.850 ;
        RECT 115.280 98.800 115.610 98.850 ;
        RECT 44.275 97.685 44.605 98.015 ;
        RECT 121.335 97.735 122.265 98.615 ;
        RECT 121.360 96.800 122.240 97.735 ;
        RECT 118.650 96.475 119.530 96.800 ;
        RECT 83.000 95.900 83.500 96.400 ;
        RECT 16.170 95.720 31.520 95.770 ;
        RECT 8.300 93.715 31.520 95.720 ;
        RECT 85.490 94.515 86.515 95.470 ;
        RECT 106.475 94.515 107.480 95.470 ;
        RECT 5.540 47.180 7.540 47.205 ;
        RECT 8.300 47.180 10.305 93.715 ;
        RECT 16.170 93.670 31.520 93.715 ;
        RECT 14.320 92.960 15.270 92.980 ;
        RECT 14.320 91.990 23.370 92.960 ;
        RECT 0.000 45.180 10.305 47.180 ;
        RECT 22.320 47.370 23.370 91.990 ;
        RECT 65.785 76.940 66.285 76.965 ;
        RECT 65.785 76.440 69.810 76.940 ;
        RECT 65.785 76.415 66.285 76.440 ;
        RECT 63.420 69.220 64.670 69.620 ;
        RECT 68.270 69.520 70.170 73.170 ;
        RECT 63.420 68.370 76.370 69.220 ;
        RECT 74.870 67.720 76.370 68.370 ;
        RECT 64.920 62.320 70.320 66.970 ;
        RECT 22.320 46.945 25.770 47.370 ;
        RECT 22.320 46.495 25.795 46.945 ;
        RECT 22.320 46.320 25.770 46.495 ;
        RECT 5.540 45.155 7.540 45.180 ;
        RECT 35.720 44.770 37.170 60.570 ;
        RECT 58.320 46.320 70.320 62.320 ;
        RECT 85.530 53.320 86.485 94.515 ;
        RECT 102.275 91.895 102.685 92.225 ;
        RECT 103.860 92.120 104.740 93.570 ;
        RECT 106.505 93.425 107.460 94.515 ;
        RECT 118.640 93.915 119.570 96.475 ;
        RECT 103.860 91.970 104.850 92.120 ;
        RECT 102.330 86.685 102.630 91.895 ;
        RECT 103.870 91.405 104.850 91.970 ;
        RECT 105.435 91.855 105.845 92.185 ;
        RECT 106.560 91.970 107.440 93.425 ;
        RECT 118.635 93.035 119.570 93.915 ;
        RECT 103.845 90.425 104.875 91.405 ;
        RECT 102.315 86.355 102.645 86.685 ;
        RECT 102.330 82.625 102.630 86.355 ;
        RECT 102.330 82.275 102.665 82.625 ;
        RECT 85.510 52.690 86.510 53.320 ;
        RECT 85.485 52.090 86.535 52.690 ;
        RECT 85.480 51.690 86.535 52.090 ;
        RECT 85.480 49.960 86.360 51.690 ;
        RECT 8.190 43.495 10.190 43.520 ;
        RECT 2.365 41.495 32.790 43.495 ;
        RECT 35.720 42.120 66.070 44.770 ;
        RECT 102.330 44.645 102.630 82.275 ;
        RECT 105.490 76.965 105.790 91.855 ;
        RECT 114.320 90.400 115.300 91.380 ;
        RECT 116.750 91.250 117.850 92.350 ;
        RECT 105.265 76.465 105.815 76.965 ;
        RECT 105.490 50.645 105.790 76.465 ;
        RECT 105.475 50.315 105.805 50.645 ;
        RECT 102.315 44.315 102.645 44.645 ;
        RECT 8.190 41.450 10.190 41.495 ;
        RECT 23.530 39.510 32.730 41.495 ;
        RECT 63.420 41.470 66.070 42.120 ;
        RECT 38.600 29.900 39.350 30.000 ;
        RECT 9.095 29.895 39.350 29.900 ;
        RECT 9.070 29.305 39.350 29.895 ;
        RECT 9.095 29.300 39.350 29.305 ;
        RECT 38.600 29.250 39.350 29.300 ;
        RECT 10.255 28.945 55.830 28.950 ;
        RECT 10.230 28.355 55.830 28.945 ;
        RECT 10.255 28.350 55.830 28.355 ;
        RECT 59.820 24.920 76.420 41.470 ;
        RECT 79.675 34.505 80.325 35.155 ;
        RECT 81.205 32.730 81.870 33.300 ;
        RECT 82.685 30.790 83.340 31.315 ;
        RECT 112.950 24.120 113.930 89.500 ;
        RECT 114.330 56.365 115.290 90.400 ;
        RECT 114.305 55.405 115.315 56.365 ;
        RECT 117.000 30.900 117.550 91.250 ;
        RECT 118.640 90.905 119.570 93.035 ;
        RECT 121.350 95.510 122.240 96.800 ;
        RECT 131.700 95.850 132.150 96.500 ;
        RECT 121.350 92.800 122.230 95.510 ;
        RECT 142.580 93.060 143.460 97.430 ;
        RECT 145.280 94.235 146.160 98.640 ;
        RECT 159.380 97.580 160.510 98.820 ;
        RECT 156.710 92.760 158.090 94.200 ;
        RECT 118.615 89.975 119.595 90.905 ;
        RECT 122.540 86.635 122.870 86.965 ;
        RECT 122.540 32.985 122.865 86.635 ;
        RECT 141.630 70.870 143.650 72.460 ;
        RECT 141.650 56.115 143.650 70.870 ;
        RECT 153.500 57.670 161.000 59.670 ;
        RECT 141.650 54.115 158.635 56.115 ;
        RECT 131.510 52.450 132.250 52.460 ;
        RECT 141.350 52.450 142.050 52.470 ;
        RECT 131.510 51.900 142.050 52.450 ;
        RECT 131.510 51.770 132.300 51.900 ;
        RECT 131.550 51.750 132.300 51.770 ;
        RECT 141.300 51.750 142.050 51.900 ;
        RECT 141.350 51.720 142.050 51.750 ;
        RECT 122.515 32.655 122.885 32.985 ;
        RECT 132.250 31.285 133.130 50.345 ;
        RECT 132.230 31.145 133.130 31.285 ;
        RECT 134.950 31.145 135.830 51.595 ;
        RECT 117.000 28.350 117.600 30.900 ;
        RECT 132.230 28.435 133.110 31.145 ;
        RECT 134.920 29.245 135.900 30.175 ;
        RECT 134.945 28.435 135.875 29.245 ;
        RECT 117.005 28.325 117.595 28.350 ;
        RECT 132.230 26.835 133.120 28.435 ;
        RECT 134.940 28.360 135.875 28.435 ;
        RECT 13.630 18.870 14.230 23.945 ;
        RECT 36.100 22.850 36.600 23.000 ;
        RECT 36.100 22.550 87.150 22.850 ;
        RECT 36.100 22.400 36.600 22.550 ;
        RECT 65.440 21.440 66.095 21.875 ;
        RECT 30.980 20.700 32.560 21.030 ;
        RECT 13.630 18.425 14.945 18.870 ;
        RECT 13.630 18.350 14.230 18.425 ;
        RECT 34.280 17.980 35.860 18.310 ;
        RECT 13.945 15.915 14.595 16.065 ;
        RECT 13.945 15.615 27.100 15.915 ;
        RECT 13.945 15.465 14.595 15.615 ;
        RECT 26.800 14.555 27.100 15.615 ;
        RECT 30.980 15.260 32.560 15.590 ;
        RECT 44.495 14.555 44.825 14.570 ;
        RECT 26.800 14.255 44.825 14.555 ;
        RECT 44.495 14.240 44.825 14.255 ;
        RECT 12.795 13.195 14.575 13.345 ;
        RECT 16.435 13.195 16.765 13.210 ;
        RECT 12.795 12.895 16.765 13.195 ;
        RECT 12.795 12.745 14.575 12.895 ;
        RECT 16.435 12.880 16.765 12.895 ;
        RECT 34.280 12.540 35.860 12.870 ;
        RECT 10.230 11.835 14.575 11.985 ;
        RECT 15.055 11.835 15.385 11.850 ;
        RECT 10.230 11.535 15.385 11.835 ;
        RECT 10.230 11.385 14.575 11.535 ;
        RECT 15.055 11.520 15.385 11.535 ;
        RECT 30.980 9.820 32.560 10.150 ;
        RECT 80.375 9.115 80.705 9.130 ;
        RECT 82.595 9.115 83.195 9.265 ;
        RECT 80.375 8.815 83.195 9.115 ;
        RECT 80.375 8.800 80.705 8.815 ;
        RECT 82.595 8.665 83.195 8.815 ;
        RECT 29.315 8.435 29.645 8.450 ;
        RECT 43.575 8.435 43.905 8.450 ;
        RECT 29.315 8.135 43.905 8.435 ;
        RECT 29.315 8.120 29.645 8.135 ;
        RECT 43.575 8.120 43.905 8.135 ;
        RECT 34.280 7.100 35.860 7.430 ;
        RECT 30.235 6.395 30.565 6.410 ;
        RECT 50.475 6.395 50.805 6.410 ;
        RECT 30.235 6.095 50.805 6.395 ;
        RECT 30.235 6.080 30.565 6.095 ;
        RECT 50.475 6.080 50.805 6.095 ;
        RECT 21.035 5.715 21.365 5.730 ;
        RECT 44.955 5.715 45.285 5.730 ;
        RECT 21.035 5.415 45.285 5.715 ;
        RECT 21.035 5.400 21.365 5.415 ;
        RECT 44.955 5.400 45.285 5.415 ;
        RECT 30.980 4.380 32.560 4.710 ;
        RECT 9.070 3.675 14.765 3.825 ;
        RECT 41.735 3.675 42.065 3.690 ;
        RECT 9.070 3.375 42.065 3.675 ;
        RECT 86.050 3.650 87.150 22.550 ;
        RECT 88.055 21.020 89.045 21.960 ;
        RECT 88.080 20.420 89.020 21.020 ;
        RECT 88.060 20.340 89.020 20.420 ;
        RECT 88.060 18.820 88.940 20.340 ;
        RECT 97.875 19.510 98.885 20.520 ;
        RECT 104.585 19.490 105.595 20.500 ;
        RECT 111.155 19.650 112.165 20.660 ;
        RECT 112.960 20.505 113.920 24.120 ;
        RECT 132.230 21.055 133.110 26.835 ;
        RECT 134.940 24.335 135.820 28.360 ;
        RECT 134.930 24.195 135.820 24.335 ;
        RECT 134.930 22.735 135.810 24.195 ;
        RECT 112.935 19.545 113.945 20.505 ;
        RECT 118.045 19.680 119.055 20.690 ;
        RECT 124.635 19.680 125.645 20.690 ;
        RECT 95.510 12.785 100.910 18.185 ;
        RECT 97.700 11.400 98.660 12.785 ;
        RECT 102.170 12.775 107.570 18.175 ;
        RECT 108.890 12.785 114.290 18.185 ;
        RECT 115.680 12.785 121.080 18.185 ;
        RECT 97.675 10.440 98.685 11.400 ;
        RECT 104.430 11.310 105.390 12.775 ;
        RECT 104.405 10.350 105.415 11.310 ;
        RECT 111.080 11.250 112.040 12.785 ;
        RECT 111.055 10.290 112.065 11.250 ;
        RECT 117.910 11.230 118.870 12.785 ;
        RECT 122.360 12.755 127.760 18.155 ;
        RECT 117.885 10.270 118.895 11.230 ;
        RECT 124.560 11.120 125.520 12.755 ;
        RECT 124.535 10.160 125.545 11.120 ;
        RECT 88.495 8.545 89.205 9.445 ;
        RECT 9.070 3.225 14.765 3.375 ;
        RECT 41.735 3.360 42.065 3.375 ;
        RECT 6.270 2.315 14.765 2.465 ;
        RECT 18.275 2.315 18.605 2.330 ;
        RECT 6.270 2.015 18.605 2.315 ;
        RECT 6.270 1.865 14.765 2.015 ;
        RECT 18.275 2.000 18.605 2.015 ;
        RECT 75.775 2.315 76.105 2.330 ;
        RECT 82.620 2.315 83.220 2.465 ;
        RECT 75.775 2.015 83.220 2.315 ;
        RECT 75.775 2.000 76.105 2.015 ;
        RECT 34.280 1.660 35.860 1.990 ;
        RECT 82.620 0.550 83.220 2.015 ;
        RECT 87.940 1.260 88.820 2.860 ;
        RECT 90.640 2.200 91.520 2.860 ;
        RECT 90.640 1.260 91.550 2.200 ;
        RECT 89.200 0.550 90.100 0.650 ;
        RECT 82.620 -0.050 90.100 0.550 ;
        RECT 90.650 0.000 91.550 1.260 ;
        RECT 89.200 -0.250 90.100 -0.050 ;
      LAYER met4 ;
        RECT 38.940 100.520 38.950 101.200 ;
        RECT 85.570 100.520 85.870 100.690 ;
        RECT 2.390 41.490 2.400 43.500 ;
        RECT 6.295 1.860 6.895 100.350 ;
        RECT 33.430 99.280 33.730 100.520 ;
        RECT 12.250 98.680 33.730 99.280 ;
        RECT 36.190 98.940 36.490 100.520 ;
        RECT 38.940 99.080 39.240 100.520 ;
        RECT 41.710 99.165 42.010 100.520 ;
        RECT 39.565 99.080 39.895 99.095 ;
        RECT 37.075 98.940 37.405 98.955 ;
        RECT 9.095 3.220 9.695 29.900 ;
        RECT 10.255 11.380 10.855 28.950 ;
        RECT 12.250 16.065 12.850 98.680 ;
        RECT 36.190 98.640 37.405 98.940 ;
        RECT 36.190 23.000 36.490 98.640 ;
        RECT 37.075 98.625 37.405 98.640 ;
        RECT 38.940 98.780 39.895 99.080 ;
        RECT 41.695 98.835 42.025 99.165 ;
        RECT 38.940 29.905 39.240 98.780 ;
        RECT 39.565 98.765 39.895 98.780 ;
        RECT 83.110 96.400 83.410 100.520 ;
        RECT 85.570 99.745 86.170 100.520 ;
        RECT 88.630 100.230 88.930 100.520 ;
        RECT 91.390 100.230 91.690 100.520 ;
        RECT 94.150 100.230 94.450 100.520 ;
        RECT 96.910 100.230 97.210 100.520 ;
        RECT 99.670 100.230 99.970 100.520 ;
        RECT 102.430 100.230 102.730 100.520 ;
        RECT 83.000 95.900 83.500 96.400 ;
        RECT 67.020 65.270 70.320 73.170 ;
        RECT 64.920 62.320 70.320 65.270 ;
        RECT 58.320 46.320 70.320 62.320 ;
        RECT 105.190 35.130 105.490 100.520 ;
        RECT 79.670 34.530 105.490 35.130 ;
        RECT 81.355 33.160 81.760 33.200 ;
        RECT 107.950 33.160 108.250 100.520 ;
        RECT 81.355 32.860 108.250 33.160 ;
        RECT 81.355 32.810 81.760 32.860 ;
        RECT 82.890 31.205 83.230 31.225 ;
        RECT 110.710 31.205 111.010 100.520 ;
        RECT 113.470 39.230 113.770 100.520 ;
        RECT 116.230 41.095 116.530 100.520 ;
        RECT 118.990 42.950 119.290 100.520 ;
        RECT 121.750 45.700 122.050 100.520 ;
        RECT 124.510 47.600 124.810 100.520 ;
        RECT 127.270 100.170 127.570 100.520 ;
        RECT 130.030 100.190 130.330 100.520 ;
        RECT 132.790 100.120 133.090 100.520 ;
        RECT 135.550 100.160 135.850 100.520 ;
        RECT 138.310 100.190 138.610 100.520 ;
        RECT 141.070 100.170 141.370 100.520 ;
        RECT 143.830 100.180 144.130 100.520 ;
        RECT 146.590 100.160 146.890 100.520 ;
        RECT 127.270 99.600 127.570 99.870 ;
        RECT 130.030 99.600 130.330 99.890 ;
        RECT 132.790 99.600 133.090 99.820 ;
        RECT 135.550 99.600 135.850 99.860 ;
        RECT 138.310 99.600 138.610 99.890 ;
        RECT 141.070 99.600 141.370 99.870 ;
        RECT 143.830 99.645 144.130 99.880 ;
        RECT 143.830 99.600 144.545 99.645 ;
        RECT 146.590 99.600 146.890 99.860 ;
        RECT 126.910 99.350 146.890 99.600 ;
        RECT 126.910 99.240 146.860 99.350 ;
        RECT 144.100 99.180 144.545 99.240 ;
        RECT 131.510 53.090 132.190 96.550 ;
        RECT 156.600 56.120 158.600 101.520 ;
        RECT 156.600 54.110 158.610 56.120 ;
        RECT 131.510 51.740 132.250 53.090 ;
        RECT 141.345 51.745 142.055 52.445 ;
        RECT 124.510 47.300 139.100 47.600 ;
        RECT 121.750 45.400 137.100 45.700 ;
        RECT 118.990 42.650 135.150 42.950 ;
        RECT 116.230 40.495 133.760 41.095 ;
        RECT 113.470 38.930 131.805 39.230 ;
        RECT 82.890 30.905 111.010 31.205 ;
        RECT 82.890 30.885 83.230 30.905 ;
        RECT 38.645 29.295 39.255 29.905 ;
        RECT 55.205 28.950 55.805 28.955 ;
        RECT 55.205 28.350 117.600 28.950 ;
        RECT 55.205 28.345 55.805 28.350 ;
        RECT 36.100 22.400 36.600 23.000 ;
        RECT 65.660 21.790 65.990 21.810 ;
        RECT 131.505 21.790 131.805 38.930 ;
        RECT 65.660 21.490 131.805 21.790 ;
        RECT 65.660 21.470 65.990 21.490 ;
        RECT 13.970 16.065 14.570 16.070 ;
        RECT 12.250 15.465 14.570 16.065 ;
        RECT 13.970 15.460 14.570 15.465 ;
        RECT 30.970 0.000 32.570 21.105 ;
        RECT 34.270 0.000 35.870 21.105 ;
        RECT 97.870 19.535 98.890 20.495 ;
        RECT 97.900 18.185 98.860 19.535 ;
        RECT 104.580 19.515 105.600 20.475 ;
        RECT 111.150 19.675 112.170 20.635 ;
        RECT 118.040 19.705 119.060 20.665 ;
        RECT 124.630 19.705 125.650 20.665 ;
        RECT 95.510 12.785 100.910 18.185 ;
        RECT 104.610 18.175 105.570 19.515 ;
        RECT 111.180 18.185 112.140 19.675 ;
        RECT 118.070 18.185 119.030 19.705 ;
        RECT 102.170 12.775 107.570 18.175 ;
        RECT 108.890 12.785 114.290 18.185 ;
        RECT 115.680 12.785 121.080 18.185 ;
        RECT 124.660 18.155 125.620 19.705 ;
        RECT 122.360 12.755 127.760 18.155 ;
        RECT 88.495 9.265 89.205 9.445 ;
        RECT 133.160 9.265 133.760 40.495 ;
        RECT 88.495 8.665 133.760 9.265 ;
        RECT 88.495 8.545 89.205 8.665 ;
        RECT 87.950 0.000 88.850 2.850 ;
        RECT 134.850 0.000 135.150 42.650 ;
        RECT 136.800 0.000 137.100 45.400 ;
        RECT 138.800 0.000 139.100 47.300 ;
        RECT 141.350 0.000 142.050 51.745 ;
        RECT 156.600 0.000 158.600 54.110 ;
        RECT 159.000 0.000 161.000 101.520 ;
      LAYER met5 ;
        RECT 15.450 15.535 82.150 17.135 ;
        RECT 15.450 12.235 82.150 13.835 ;
  END
END tt_um_lelo_gr01_analogicus
END LIBRARY

